VERSION 5.8 ;
BUSBITCHARS "[]" ;
DIVIDERCHAR "/" ;
UNITS
    DATABASE MICRONS 1000 ;
END UNITS

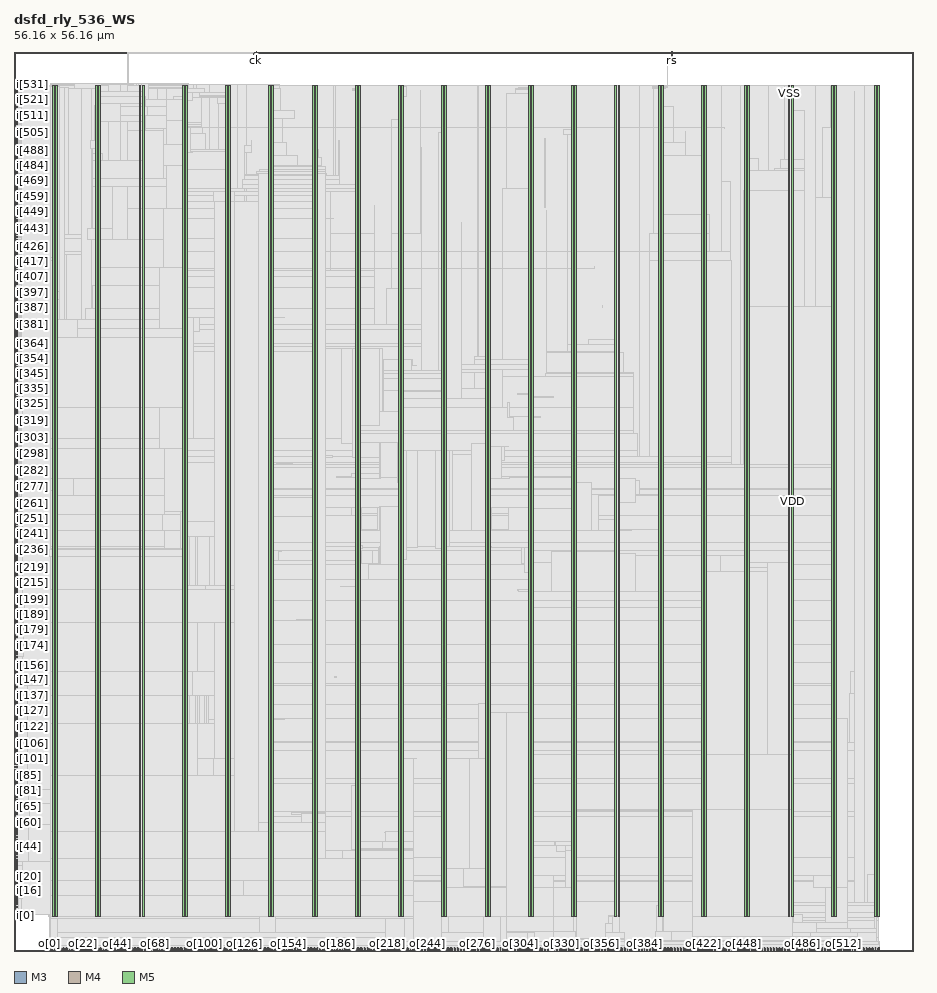
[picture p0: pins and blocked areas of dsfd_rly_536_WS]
MACRO dsfd_rly_536_WS
  FOREIGN dsfd_rly_536_WS 0 0 ;
  CLASS BLOCK ;
  SIZE 56.16 BY 56.16 ;
  PIN ck
    DIRECTION INPUT ;
    USE SIGNAL ;
    PORT
      LAYER M3 ;
        RECT  15.12 56.016 15.138 56.16 ;
    END
    PORT
      LAYER M3 ;
        RECT  14.94 55.915 15.138 56.028 ;
    END
  END ck
  PIN i[0]
    DIRECTION INPUT ;
    USE SIGNAL ;
    PORT
      LAYER M4 ;
        RECT  0 2.208 0.192 2.232 ;
    END
  END i[0]
  PIN i[100]
    DIRECTION INPUT ;
    USE SIGNAL ;
    PORT
      LAYER M4 ;
        RECT  0 11.904 0.192 11.928 ;
    END
  END i[100]
  PIN i[101]
    DIRECTION INPUT ;
    USE SIGNAL ;
    PORT
      LAYER M4 ;
        RECT  0 12 0.192 12.024 ;
    END
  END i[101]
  PIN i[102]
    DIRECTION INPUT ;
    USE SIGNAL ;
    PORT
      LAYER M4 ;
        RECT  0 12.096 0.192 12.12 ;
    END
  END i[102]
  PIN i[103]
    DIRECTION INPUT ;
    USE SIGNAL ;
    PORT
      LAYER M4 ;
        RECT  0 12.192 0.192 12.216 ;
    END
  END i[103]
  PIN i[104]
    DIRECTION INPUT ;
    USE SIGNAL ;
    PORT
      LAYER M4 ;
        RECT  0 12.288 0.192 12.312 ;
    END
  END i[104]
  PIN i[105]
    DIRECTION INPUT ;
    USE SIGNAL ;
    PORT
      LAYER M4 ;
        RECT  0 12.384 0.192 12.408 ;
    END
  END i[105]
  PIN i[106]
    DIRECTION INPUT ;
    USE SIGNAL ;
    PORT
      LAYER M4 ;
        RECT  0 12.48 0.192 12.504 ;
    END
  END i[106]
  PIN i[107]
    DIRECTION INPUT ;
    USE SIGNAL ;
    PORT
      LAYER M4 ;
        RECT  0 12.576 0.192 12.6 ;
    END
  END i[107]
  PIN i[108]
    DIRECTION INPUT ;
    USE SIGNAL ;
    PORT
      LAYER M4 ;
        RECT  0 12.672 0.192 12.696 ;
    END
  END i[108]
  PIN i[109]
    DIRECTION INPUT ;
    USE SIGNAL ;
    PORT
      LAYER M4 ;
        RECT  0 12.768 0.192 12.792 ;
    END
  END i[109]
  PIN i[10]
    DIRECTION INPUT ;
    USE SIGNAL ;
    PORT
      LAYER M4 ;
        RECT  0 3.168 0.192 3.192 ;
    END
  END i[10]
  PIN i[110]
    DIRECTION INPUT ;
    USE SIGNAL ;
    PORT
      LAYER M4 ;
        RECT  0 12.864 0.192 12.888 ;
    END
  END i[110]
  PIN i[111]
    DIRECTION INPUT ;
    USE SIGNAL ;
    PORT
      LAYER M4 ;
        RECT  0 12.96 0.192 12.984 ;
    END
  END i[111]
  PIN i[112]
    DIRECTION INPUT ;
    USE SIGNAL ;
    PORT
      LAYER M4 ;
        RECT  0 13.056 0.192 13.08 ;
    END
  END i[112]
  PIN i[113]
    DIRECTION INPUT ;
    USE SIGNAL ;
    PORT
      LAYER M4 ;
        RECT  0 13.152 0.192 13.176 ;
    END
  END i[113]
  PIN i[114]
    DIRECTION INPUT ;
    USE SIGNAL ;
    PORT
      LAYER M4 ;
        RECT  0 13.248 0.192 13.272 ;
    END
  END i[114]
  PIN i[115]
    DIRECTION INPUT ;
    USE SIGNAL ;
    PORT
      LAYER M4 ;
        RECT  0 13.344 0.192 13.368 ;
    END
  END i[115]
  PIN i[116]
    DIRECTION INPUT ;
    USE SIGNAL ;
    PORT
      LAYER M4 ;
        RECT  0 13.44 0.192 13.464 ;
    END
  END i[116]
  PIN i[117]
    DIRECTION INPUT ;
    USE SIGNAL ;
    PORT
      LAYER M4 ;
        RECT  0 13.536 0.192 13.56 ;
    END
  END i[117]
  PIN i[118]
    DIRECTION INPUT ;
    USE SIGNAL ;
    PORT
      LAYER M4 ;
        RECT  0 13.632 0.192 13.656 ;
    END
  END i[118]
  PIN i[119]
    DIRECTION INPUT ;
    USE SIGNAL ;
    PORT
      LAYER M4 ;
        RECT  0 13.728 0.192 13.752 ;
    END
  END i[119]
  PIN i[11]
    DIRECTION INPUT ;
    USE SIGNAL ;
    PORT
      LAYER M4 ;
        RECT  0 3.264 0.192 3.288 ;
    END
  END i[11]
  PIN i[120]
    DIRECTION INPUT ;
    USE SIGNAL ;
    PORT
      LAYER M4 ;
        RECT  0 13.824 0.192 13.848 ;
    END
  END i[120]
  PIN i[121]
    DIRECTION INPUT ;
    USE SIGNAL ;
    PORT
      LAYER M4 ;
        RECT  0 13.92 0.192 13.944 ;
    END
  END i[121]
  PIN i[122]
    DIRECTION INPUT ;
    USE SIGNAL ;
    PORT
      LAYER M4 ;
        RECT  0 14.016 0.192 14.04 ;
    END
  END i[122]
  PIN i[123]
    DIRECTION INPUT ;
    USE SIGNAL ;
    PORT
      LAYER M4 ;
        RECT  0 14.112 0.192 14.136 ;
    END
  END i[123]
  PIN i[124]
    DIRECTION INPUT ;
    USE SIGNAL ;
    PORT
      LAYER M4 ;
        RECT  0 14.208 0.192 14.232 ;
    END
  END i[124]
  PIN i[125]
    DIRECTION INPUT ;
    USE SIGNAL ;
    PORT
      LAYER M4 ;
        RECT  0 14.304 0.192 14.328 ;
    END
  END i[125]
  PIN i[126]
    DIRECTION INPUT ;
    USE SIGNAL ;
    PORT
      LAYER M4 ;
        RECT  0 14.4 0.192 14.424 ;
    END
  END i[126]
  PIN i[127]
    DIRECTION INPUT ;
    USE SIGNAL ;
    PORT
      LAYER M4 ;
        RECT  0 14.496 0.192 14.52 ;
    END
  END i[127]
  PIN i[128]
    DIRECTION INPUT ;
    USE SIGNAL ;
    PORT
      LAYER M4 ;
        RECT  0 14.592 0.192 14.616 ;
    END
  END i[128]
  PIN i[129]
    DIRECTION INPUT ;
    USE SIGNAL ;
    PORT
      LAYER M4 ;
        RECT  0 14.688 0.192 14.712 ;
    END
  END i[129]
  PIN i[12]
    DIRECTION INPUT ;
    USE SIGNAL ;
    PORT
      LAYER M4 ;
        RECT  0 3.36 0.192 3.384 ;
    END
  END i[12]
  PIN i[130]
    DIRECTION INPUT ;
    USE SIGNAL ;
    PORT
      LAYER M4 ;
        RECT  0 14.784 0.192 14.808 ;
    END
  END i[130]
  PIN i[131]
    DIRECTION INPUT ;
    USE SIGNAL ;
    PORT
      LAYER M4 ;
        RECT  0 14.88 0.192 14.904 ;
    END
  END i[131]
  PIN i[132]
    DIRECTION INPUT ;
    USE SIGNAL ;
    PORT
      LAYER M4 ;
        RECT  0 14.976 0.192 15 ;
    END
  END i[132]
  PIN i[133]
    DIRECTION INPUT ;
    USE SIGNAL ;
    PORT
      LAYER M4 ;
        RECT  0 15.072 0.192 15.096 ;
    END
  END i[133]
  PIN i[134]
    DIRECTION INPUT ;
    USE SIGNAL ;
    PORT
      LAYER M4 ;
        RECT  0 15.168 0.192 15.192 ;
    END
  END i[134]
  PIN i[135]
    DIRECTION INPUT ;
    USE SIGNAL ;
    PORT
      LAYER M4 ;
        RECT  0 15.264 0.192 15.288 ;
    END
  END i[135]
  PIN i[136]
    DIRECTION INPUT ;
    USE SIGNAL ;
    PORT
      LAYER M4 ;
        RECT  0 15.36 0.192 15.384 ;
    END
  END i[136]
  PIN i[137]
    DIRECTION INPUT ;
    USE SIGNAL ;
    PORT
      LAYER M4 ;
        RECT  0 15.456 0.192 15.48 ;
    END
  END i[137]
  PIN i[138]
    DIRECTION INPUT ;
    USE SIGNAL ;
    PORT
      LAYER M4 ;
        RECT  0 15.552 0.192 15.576 ;
    END
  END i[138]
  PIN i[139]
    DIRECTION INPUT ;
    USE SIGNAL ;
    PORT
      LAYER M4 ;
        RECT  0 15.648 0.192 15.672 ;
    END
  END i[139]
  PIN i[13]
    DIRECTION INPUT ;
    USE SIGNAL ;
    PORT
      LAYER M4 ;
        RECT  0 3.456 0.192 3.48 ;
    END
  END i[13]
  PIN i[140]
    DIRECTION INPUT ;
    USE SIGNAL ;
    PORT
      LAYER M4 ;
        RECT  0 15.744 0.192 15.768 ;
    END
  END i[140]
  PIN i[141]
    DIRECTION INPUT ;
    USE SIGNAL ;
    PORT
      LAYER M4 ;
        RECT  0 15.84 0.192 15.864 ;
    END
  END i[141]
  PIN i[142]
    DIRECTION INPUT ;
    USE SIGNAL ;
    PORT
      LAYER M4 ;
        RECT  0 15.936 0.192 15.96 ;
    END
  END i[142]
  PIN i[143]
    DIRECTION INPUT ;
    USE SIGNAL ;
    PORT
      LAYER M4 ;
        RECT  0 16.032 0.192 16.056 ;
    END
  END i[143]
  PIN i[144]
    DIRECTION INPUT ;
    USE SIGNAL ;
    PORT
      LAYER M4 ;
        RECT  0 16.128 0.192 16.152 ;
    END
  END i[144]
  PIN i[145]
    DIRECTION INPUT ;
    USE SIGNAL ;
    PORT
      LAYER M4 ;
        RECT  0 16.224 0.192 16.248 ;
    END
  END i[145]
  PIN i[146]
    DIRECTION INPUT ;
    USE SIGNAL ;
    PORT
      LAYER M4 ;
        RECT  0 16.32 0.192 16.344 ;
    END
  END i[146]
  PIN i[147]
    DIRECTION INPUT ;
    USE SIGNAL ;
    PORT
      LAYER M4 ;
        RECT  0 16.416 0.192 16.44 ;
    END
  END i[147]
  PIN i[148]
    DIRECTION INPUT ;
    USE SIGNAL ;
    PORT
      LAYER M4 ;
        RECT  0 16.512 0.192 16.536 ;
    END
  END i[148]
  PIN i[149]
    DIRECTION INPUT ;
    USE SIGNAL ;
    PORT
      LAYER M4 ;
        RECT  0 16.608 0.192 16.632 ;
    END
  END i[149]
  PIN i[14]
    DIRECTION INPUT ;
    USE SIGNAL ;
    PORT
      LAYER M4 ;
        RECT  0 3.552 0.192 3.576 ;
    END
  END i[14]
  PIN i[150]
    DIRECTION INPUT ;
    USE SIGNAL ;
    PORT
      LAYER M4 ;
        RECT  0 16.704 0.192 16.728 ;
    END
  END i[150]
  PIN i[151]
    DIRECTION INPUT ;
    USE SIGNAL ;
    PORT
      LAYER M4 ;
        RECT  0 16.848 0.192 16.872 ;
    END
  END i[151]
  PIN i[152]
    DIRECTION INPUT ;
    USE SIGNAL ;
    PORT
      LAYER M4 ;
        RECT  0 16.944 0.192 16.968 ;
    END
  END i[152]
  PIN i[153]
    DIRECTION INPUT ;
    USE SIGNAL ;
    PORT
      LAYER M4 ;
        RECT  0 17.04 0.192 17.064 ;
    END
  END i[153]
  PIN i[154]
    DIRECTION INPUT ;
    USE SIGNAL ;
    PORT
      LAYER M4 ;
        RECT  0 17.136 0.192 17.16 ;
    END
  END i[154]
  PIN i[155]
    DIRECTION INPUT ;
    USE SIGNAL ;
    PORT
      LAYER M4 ;
        RECT  0 17.232 0.192 17.256 ;
    END
  END i[155]
  PIN i[156]
    DIRECTION INPUT ;
    USE SIGNAL ;
    PORT
      LAYER M4 ;
        RECT  0 17.328 0.192 17.352 ;
    END
  END i[156]
  PIN i[157]
    DIRECTION INPUT ;
    USE SIGNAL ;
    PORT
      LAYER M4 ;
        RECT  0 17.424 0.192 17.448 ;
    END
  END i[157]
  PIN i[158]
    DIRECTION INPUT ;
    USE SIGNAL ;
    PORT
      LAYER M4 ;
        RECT  0 17.52 0.192 17.544 ;
    END
  END i[158]
  PIN i[159]
    DIRECTION INPUT ;
    USE SIGNAL ;
    PORT
      LAYER M4 ;
        RECT  0 17.616 0.192 17.64 ;
    END
  END i[159]
  PIN i[15]
    DIRECTION INPUT ;
    USE SIGNAL ;
    PORT
      LAYER M4 ;
        RECT  0 3.648 0.192 3.672 ;
    END
  END i[15]
  PIN i[160]
    DIRECTION INPUT ;
    USE SIGNAL ;
    PORT
      LAYER M4 ;
        RECT  0 17.712 0.192 17.736 ;
    END
  END i[160]
  PIN i[161]
    DIRECTION INPUT ;
    USE SIGNAL ;
    PORT
      LAYER M4 ;
        RECT  0 17.808 0.192 17.832 ;
    END
  END i[161]
  PIN i[162]
    DIRECTION INPUT ;
    USE SIGNAL ;
    PORT
      LAYER M4 ;
        RECT  0 17.904 0.192 17.928 ;
    END
  END i[162]
  PIN i[163]
    DIRECTION INPUT ;
    USE SIGNAL ;
    PORT
      LAYER M4 ;
        RECT  0 18 0.192 18.024 ;
    END
  END i[163]
  PIN i[164]
    DIRECTION INPUT ;
    USE SIGNAL ;
    PORT
      LAYER M4 ;
        RECT  0 18.096 0.192 18.12 ;
    END
  END i[164]
  PIN i[165]
    DIRECTION INPUT ;
    USE SIGNAL ;
    PORT
      LAYER M4 ;
        RECT  0 18.192 0.192 18.216 ;
    END
  END i[165]
  PIN i[166]
    DIRECTION INPUT ;
    USE SIGNAL ;
    PORT
      LAYER M4 ;
        RECT  0 18.288 0.192 18.312 ;
    END
  END i[166]
  PIN i[167]
    DIRECTION INPUT ;
    USE SIGNAL ;
    PORT
      LAYER M4 ;
        RECT  0 18.384 0.192 18.408 ;
    END
  END i[167]
  PIN i[168]
    DIRECTION INPUT ;
    USE SIGNAL ;
    PORT
      LAYER M4 ;
        RECT  0 18.48 0.192 18.504 ;
    END
  END i[168]
  PIN i[169]
    DIRECTION INPUT ;
    USE SIGNAL ;
    PORT
      LAYER M4 ;
        RECT  0 18.576 0.192 18.6 ;
    END
  END i[169]
  PIN i[16]
    DIRECTION INPUT ;
    USE SIGNAL ;
    PORT
      LAYER M4 ;
        RECT  0 3.744 0.192 3.768 ;
    END
  END i[16]
  PIN i[170]
    DIRECTION INPUT ;
    USE SIGNAL ;
    PORT
      LAYER M4 ;
        RECT  0 18.672 0.192 18.696 ;
    END
  END i[170]
  PIN i[171]
    DIRECTION INPUT ;
    USE SIGNAL ;
    PORT
      LAYER M4 ;
        RECT  0 18.768 0.192 18.792 ;
    END
  END i[171]
  PIN i[172]
    DIRECTION INPUT ;
    USE SIGNAL ;
    PORT
      LAYER M4 ;
        RECT  0 18.864 0.192 18.888 ;
    END
  END i[172]
  PIN i[173]
    DIRECTION INPUT ;
    USE SIGNAL ;
    PORT
      LAYER M4 ;
        RECT  0 18.96 0.192 18.984 ;
    END
  END i[173]
  PIN i[174]
    DIRECTION INPUT ;
    USE SIGNAL ;
    PORT
      LAYER M4 ;
        RECT  0 19.056 0.192 19.08 ;
    END
  END i[174]
  PIN i[175]
    DIRECTION INPUT ;
    USE SIGNAL ;
    PORT
      LAYER M4 ;
        RECT  0 19.152 0.192 19.176 ;
    END
  END i[175]
  PIN i[176]
    DIRECTION INPUT ;
    USE SIGNAL ;
    PORT
      LAYER M4 ;
        RECT  0 19.248 0.192 19.272 ;
    END
  END i[176]
  PIN i[177]
    DIRECTION INPUT ;
    USE SIGNAL ;
    PORT
      LAYER M4 ;
        RECT  0 19.344 0.192 19.368 ;
    END
  END i[177]
  PIN i[178]
    DIRECTION INPUT ;
    USE SIGNAL ;
    PORT
      LAYER M4 ;
        RECT  0 19.44 0.192 19.464 ;
    END
  END i[178]
  PIN i[179]
    DIRECTION INPUT ;
    USE SIGNAL ;
    PORT
      LAYER M4 ;
        RECT  0 19.536 0.192 19.56 ;
    END
  END i[179]
  PIN i[17]
    DIRECTION INPUT ;
    USE SIGNAL ;
    PORT
      LAYER M4 ;
        RECT  0 3.888 0.192 3.912 ;
    END
  END i[17]
  PIN i[180]
    DIRECTION INPUT ;
    USE SIGNAL ;
    PORT
      LAYER M4 ;
        RECT  0 19.632 0.192 19.656 ;
    END
  END i[180]
  PIN i[181]
    DIRECTION INPUT ;
    USE SIGNAL ;
    PORT
      LAYER M4 ;
        RECT  0 19.728 0.192 19.752 ;
    END
  END i[181]
  PIN i[182]
    DIRECTION INPUT ;
    USE SIGNAL ;
    PORT
      LAYER M4 ;
        RECT  0 19.824 0.192 19.848 ;
    END
  END i[182]
  PIN i[183]
    DIRECTION INPUT ;
    USE SIGNAL ;
    PORT
      LAYER M4 ;
        RECT  0 19.92 0.192 19.944 ;
    END
  END i[183]
  PIN i[184]
    DIRECTION INPUT ;
    USE SIGNAL ;
    PORT
      LAYER M4 ;
        RECT  0 20.016 0.192 20.04 ;
    END
  END i[184]
  PIN i[185]
    DIRECTION INPUT ;
    USE SIGNAL ;
    PORT
      LAYER M4 ;
        RECT  0 20.112 0.192 20.136 ;
    END
  END i[185]
  PIN i[186]
    DIRECTION INPUT ;
    USE SIGNAL ;
    PORT
      LAYER M4 ;
        RECT  0 20.208 0.192 20.232 ;
    END
  END i[186]
  PIN i[187]
    DIRECTION INPUT ;
    USE SIGNAL ;
    PORT
      LAYER M4 ;
        RECT  0 20.304 0.192 20.328 ;
    END
  END i[187]
  PIN i[188]
    DIRECTION INPUT ;
    USE SIGNAL ;
    PORT
      LAYER M4 ;
        RECT  0 20.4 0.192 20.424 ;
    END
  END i[188]
  PIN i[189]
    DIRECTION INPUT ;
    USE SIGNAL ;
    PORT
      LAYER M4 ;
        RECT  0 20.496 0.192 20.52 ;
    END
  END i[189]
  PIN i[18]
    DIRECTION INPUT ;
    USE SIGNAL ;
    PORT
      LAYER M4 ;
        RECT  0 3.984 0.192 4.008 ;
    END
  END i[18]
  PIN i[190]
    DIRECTION INPUT ;
    USE SIGNAL ;
    PORT
      LAYER M4 ;
        RECT  0 20.592 0.192 20.616 ;
    END
  END i[190]
  PIN i[191]
    DIRECTION INPUT ;
    USE SIGNAL ;
    PORT
      LAYER M4 ;
        RECT  0 20.688 0.192 20.712 ;
    END
  END i[191]
  PIN i[192]
    DIRECTION INPUT ;
    USE SIGNAL ;
    PORT
      LAYER M4 ;
        RECT  0 20.784 0.192 20.808 ;
    END
  END i[192]
  PIN i[193]
    DIRECTION INPUT ;
    USE SIGNAL ;
    PORT
      LAYER M4 ;
        RECT  0 20.88 0.192 20.904 ;
    END
  END i[193]
  PIN i[194]
    DIRECTION INPUT ;
    USE SIGNAL ;
    PORT
      LAYER M4 ;
        RECT  0 20.976 0.192 21 ;
    END
  END i[194]
  PIN i[195]
    DIRECTION INPUT ;
    USE SIGNAL ;
    PORT
      LAYER M4 ;
        RECT  0 21.072 0.192 21.096 ;
    END
  END i[195]
  PIN i[196]
    DIRECTION INPUT ;
    USE SIGNAL ;
    PORT
      LAYER M4 ;
        RECT  0 21.168 0.192 21.192 ;
    END
  END i[196]
  PIN i[197]
    DIRECTION INPUT ;
    USE SIGNAL ;
    PORT
      LAYER M4 ;
        RECT  0 21.264 0.192 21.288 ;
    END
  END i[197]
  PIN i[198]
    DIRECTION INPUT ;
    USE SIGNAL ;
    PORT
      LAYER M4 ;
        RECT  0 21.36 0.192 21.384 ;
    END
  END i[198]
  PIN i[199]
    DIRECTION INPUT ;
    USE SIGNAL ;
    PORT
      LAYER M4 ;
        RECT  0 21.456 0.192 21.48 ;
    END
  END i[199]
  PIN i[19]
    DIRECTION INPUT ;
    USE SIGNAL ;
    PORT
      LAYER M4 ;
        RECT  0 4.08 0.192 4.104 ;
    END
  END i[19]
  PIN i[1]
    DIRECTION INPUT ;
    USE SIGNAL ;
    PORT
      LAYER M4 ;
        RECT  0 2.304 0.192 2.328 ;
    END
  END i[1]
  PIN i[200]
    DIRECTION INPUT ;
    USE SIGNAL ;
    PORT
      LAYER M4 ;
        RECT  0 21.552 0.192 21.576 ;
    END
  END i[200]
  PIN i[201]
    DIRECTION INPUT ;
    USE SIGNAL ;
    PORT
      LAYER M4 ;
        RECT  0 21.648 0.192 21.672 ;
    END
  END i[201]
  PIN i[202]
    DIRECTION INPUT ;
    USE SIGNAL ;
    PORT
      LAYER M4 ;
        RECT  0 21.744 0.192 21.768 ;
    END
  END i[202]
  PIN i[203]
    DIRECTION INPUT ;
    USE SIGNAL ;
    PORT
      LAYER M4 ;
        RECT  0 21.84 0.192 21.864 ;
    END
  END i[203]
  PIN i[204]
    DIRECTION INPUT ;
    USE SIGNAL ;
    PORT
      LAYER M4 ;
        RECT  0 21.936 0.192 21.96 ;
    END
  END i[204]
  PIN i[205]
    DIRECTION INPUT ;
    USE SIGNAL ;
    PORT
      LAYER M4 ;
        RECT  0 22.032 0.192 22.056 ;
    END
  END i[205]
  PIN i[206]
    DIRECTION INPUT ;
    USE SIGNAL ;
    PORT
      LAYER M4 ;
        RECT  0 22.128 0.192 22.152 ;
    END
  END i[206]
  PIN i[207]
    DIRECTION INPUT ;
    USE SIGNAL ;
    PORT
      LAYER M4 ;
        RECT  0 22.224 0.192 22.248 ;
    END
  END i[207]
  PIN i[208]
    DIRECTION INPUT ;
    USE SIGNAL ;
    PORT
      LAYER M4 ;
        RECT  0 22.32 0.192 22.344 ;
    END
  END i[208]
  PIN i[209]
    DIRECTION INPUT ;
    USE SIGNAL ;
    PORT
      LAYER M4 ;
        RECT  0 22.416 0.192 22.44 ;
    END
  END i[209]
  PIN i[20]
    DIRECTION INPUT ;
    USE SIGNAL ;
    PORT
      LAYER M4 ;
        RECT  0 4.176 0.192 4.2 ;
    END
  END i[20]
  PIN i[210]
    DIRECTION INPUT ;
    USE SIGNAL ;
    PORT
      LAYER M4 ;
        RECT  0 22.512 0.192 22.536 ;
    END
  END i[210]
  PIN i[211]
    DIRECTION INPUT ;
    USE SIGNAL ;
    PORT
      LAYER M4 ;
        RECT  0 22.608 0.192 22.632 ;
    END
  END i[211]
  PIN i[212]
    DIRECTION INPUT ;
    USE SIGNAL ;
    PORT
      LAYER M4 ;
        RECT  0 22.704 0.192 22.728 ;
    END
  END i[212]
  PIN i[213]
    DIRECTION INPUT ;
    USE SIGNAL ;
    PORT
      LAYER M4 ;
        RECT  0 22.8 0.192 22.824 ;
    END
  END i[213]
  PIN i[214]
    DIRECTION INPUT ;
    USE SIGNAL ;
    PORT
      LAYER M4 ;
        RECT  0 22.896 0.192 22.92 ;
    END
  END i[214]
  PIN i[215]
    DIRECTION INPUT ;
    USE SIGNAL ;
    PORT
      LAYER M4 ;
        RECT  0 22.992 0.192 23.016 ;
    END
  END i[215]
  PIN i[216]
    DIRECTION INPUT ;
    USE SIGNAL ;
    PORT
      LAYER M4 ;
        RECT  0 23.088 0.192 23.112 ;
    END
  END i[216]
  PIN i[217]
    DIRECTION INPUT ;
    USE SIGNAL ;
    PORT
      LAYER M4 ;
        RECT  0 23.184 0.192 23.208 ;
    END
  END i[217]
  PIN i[218]
    DIRECTION INPUT ;
    USE SIGNAL ;
    PORT
      LAYER M4 ;
        RECT  0 23.328 0.192 23.352 ;
    END
  END i[218]
  PIN i[219]
    DIRECTION INPUT ;
    USE SIGNAL ;
    PORT
      LAYER M4 ;
        RECT  0 23.424 0.192 23.448 ;
    END
  END i[219]
  PIN i[21]
    DIRECTION INPUT ;
    USE SIGNAL ;
    PORT
      LAYER M4 ;
        RECT  0 4.272 0.192 4.296 ;
    END
  END i[21]
  PIN i[220]
    DIRECTION INPUT ;
    USE SIGNAL ;
    PORT
      LAYER M4 ;
        RECT  0 23.52 0.192 23.544 ;
    END
  END i[220]
  PIN i[221]
    DIRECTION INPUT ;
    USE SIGNAL ;
    PORT
      LAYER M4 ;
        RECT  0 23.616 0.192 23.64 ;
    END
  END i[221]
  PIN i[222]
    DIRECTION INPUT ;
    USE SIGNAL ;
    PORT
      LAYER M4 ;
        RECT  0 23.712 0.192 23.736 ;
    END
  END i[222]
  PIN i[223]
    DIRECTION INPUT ;
    USE SIGNAL ;
    PORT
      LAYER M4 ;
        RECT  0 23.808 0.192 23.832 ;
    END
  END i[223]
  PIN i[224]
    DIRECTION INPUT ;
    USE SIGNAL ;
    PORT
      LAYER M4 ;
        RECT  0 23.904 0.192 23.928 ;
    END
  END i[224]
  PIN i[225]
    DIRECTION INPUT ;
    USE SIGNAL ;
    PORT
      LAYER M4 ;
        RECT  0 24 0.192 24.024 ;
    END
  END i[225]
  PIN i[226]
    DIRECTION INPUT ;
    USE SIGNAL ;
    PORT
      LAYER M4 ;
        RECT  0 24.096 0.192 24.12 ;
    END
  END i[226]
  PIN i[227]
    DIRECTION INPUT ;
    USE SIGNAL ;
    PORT
      LAYER M4 ;
        RECT  0 24.192 0.192 24.216 ;
    END
  END i[227]
  PIN i[228]
    DIRECTION INPUT ;
    USE SIGNAL ;
    PORT
      LAYER M4 ;
        RECT  0 24.288 0.192 24.312 ;
    END
  END i[228]
  PIN i[229]
    DIRECTION INPUT ;
    USE SIGNAL ;
    PORT
      LAYER M4 ;
        RECT  0 24.384 0.192 24.408 ;
    END
  END i[229]
  PIN i[22]
    DIRECTION INPUT ;
    USE SIGNAL ;
    PORT
      LAYER M4 ;
        RECT  0 4.368 0.192 4.392 ;
    END
  END i[22]
  PIN i[230]
    DIRECTION INPUT ;
    USE SIGNAL ;
    PORT
      LAYER M4 ;
        RECT  0 24.48 0.192 24.504 ;
    END
  END i[230]
  PIN i[231]
    DIRECTION INPUT ;
    USE SIGNAL ;
    PORT
      LAYER M4 ;
        RECT  0 24.576 0.192 24.6 ;
    END
  END i[231]
  PIN i[232]
    DIRECTION INPUT ;
    USE SIGNAL ;
    PORT
      LAYER M4 ;
        RECT  0 24.672 0.192 24.696 ;
    END
  END i[232]
  PIN i[233]
    DIRECTION INPUT ;
    USE SIGNAL ;
    PORT
      LAYER M4 ;
        RECT  0 24.768 0.192 24.792 ;
    END
  END i[233]
  PIN i[234]
    DIRECTION INPUT ;
    USE SIGNAL ;
    PORT
      LAYER M4 ;
        RECT  0 24.864 0.192 24.888 ;
    END
  END i[234]
  PIN i[235]
    DIRECTION INPUT ;
    USE SIGNAL ;
    PORT
      LAYER M4 ;
        RECT  0 24.96 0.192 24.984 ;
    END
  END i[235]
  PIN i[236]
    DIRECTION INPUT ;
    USE SIGNAL ;
    PORT
      LAYER M4 ;
        RECT  0 25.056 0.192 25.08 ;
    END
  END i[236]
  PIN i[237]
    DIRECTION INPUT ;
    USE SIGNAL ;
    PORT
      LAYER M4 ;
        RECT  0 25.152 0.192 25.176 ;
    END
  END i[237]
  PIN i[238]
    DIRECTION INPUT ;
    USE SIGNAL ;
    PORT
      LAYER M4 ;
        RECT  0 25.248 0.192 25.272 ;
    END
  END i[238]
  PIN i[239]
    DIRECTION INPUT ;
    USE SIGNAL ;
    PORT
      LAYER M4 ;
        RECT  0 25.344 0.192 25.368 ;
    END
  END i[239]
  PIN i[23]
    DIRECTION INPUT ;
    USE SIGNAL ;
    PORT
      LAYER M4 ;
        RECT  0 4.464 0.192 4.488 ;
    END
  END i[23]
  PIN i[240]
    DIRECTION INPUT ;
    USE SIGNAL ;
    PORT
      LAYER M4 ;
        RECT  0 25.44 0.192 25.464 ;
    END
  END i[240]
  PIN i[241]
    DIRECTION INPUT ;
    USE SIGNAL ;
    PORT
      LAYER M4 ;
        RECT  0 25.536 0.192 25.56 ;
    END
  END i[241]
  PIN i[242]
    DIRECTION INPUT ;
    USE SIGNAL ;
    PORT
      LAYER M4 ;
        RECT  0 25.632 0.192 25.656 ;
    END
  END i[242]
  PIN i[243]
    DIRECTION INPUT ;
    USE SIGNAL ;
    PORT
      LAYER M4 ;
        RECT  0 25.728 0.192 25.752 ;
    END
  END i[243]
  PIN i[244]
    DIRECTION INPUT ;
    USE SIGNAL ;
    PORT
      LAYER M4 ;
        RECT  0 25.824 0.192 25.848 ;
    END
  END i[244]
  PIN i[245]
    DIRECTION INPUT ;
    USE SIGNAL ;
    PORT
      LAYER M4 ;
        RECT  0 25.92 0.192 25.944 ;
    END
  END i[245]
  PIN i[246]
    DIRECTION INPUT ;
    USE SIGNAL ;
    PORT
      LAYER M4 ;
        RECT  0 26.016 0.192 26.04 ;
    END
  END i[246]
  PIN i[247]
    DIRECTION INPUT ;
    USE SIGNAL ;
    PORT
      LAYER M4 ;
        RECT  0 26.112 0.192 26.136 ;
    END
  END i[247]
  PIN i[248]
    DIRECTION INPUT ;
    USE SIGNAL ;
    PORT
      LAYER M4 ;
        RECT  0 26.208 0.192 26.232 ;
    END
  END i[248]
  PIN i[249]
    DIRECTION INPUT ;
    USE SIGNAL ;
    PORT
      LAYER M4 ;
        RECT  0 26.304 0.192 26.328 ;
    END
  END i[249]
  PIN i[24]
    DIRECTION INPUT ;
    USE SIGNAL ;
    PORT
      LAYER M4 ;
        RECT  0 4.56 0.192 4.584 ;
    END
  END i[24]
  PIN i[250]
    DIRECTION INPUT ;
    USE SIGNAL ;
    PORT
      LAYER M4 ;
        RECT  0 26.4 0.192 26.424 ;
    END
  END i[250]
  PIN i[251]
    DIRECTION INPUT ;
    USE SIGNAL ;
    PORT
      LAYER M4 ;
        RECT  0 26.496 0.192 26.52 ;
    END
  END i[251]
  PIN i[252]
    DIRECTION INPUT ;
    USE SIGNAL ;
    PORT
      LAYER M4 ;
        RECT  0 26.592 0.192 26.616 ;
    END
  END i[252]
  PIN i[253]
    DIRECTION INPUT ;
    USE SIGNAL ;
    PORT
      LAYER M4 ;
        RECT  0 26.688 0.192 26.712 ;
    END
  END i[253]
  PIN i[254]
    DIRECTION INPUT ;
    USE SIGNAL ;
    PORT
      LAYER M4 ;
        RECT  0 26.784 0.192 26.808 ;
    END
  END i[254]
  PIN i[255]
    DIRECTION INPUT ;
    USE SIGNAL ;
    PORT
      LAYER M4 ;
        RECT  0 26.88 0.192 26.904 ;
    END
  END i[255]
  PIN i[256]
    DIRECTION INPUT ;
    USE SIGNAL ;
    PORT
      LAYER M4 ;
        RECT  0 26.976 0.192 27 ;
    END
  END i[256]
  PIN i[257]
    DIRECTION INPUT ;
    USE SIGNAL ;
    PORT
      LAYER M4 ;
        RECT  0 27.072 0.192 27.096 ;
    END
  END i[257]
  PIN i[258]
    DIRECTION INPUT ;
    USE SIGNAL ;
    PORT
      LAYER M4 ;
        RECT  0 27.168 0.192 27.192 ;
    END
  END i[258]
  PIN i[259]
    DIRECTION INPUT ;
    USE SIGNAL ;
    PORT
      LAYER M4 ;
        RECT  0 27.264 0.192 27.288 ;
    END
  END i[259]
  PIN i[25]
    DIRECTION INPUT ;
    USE SIGNAL ;
    PORT
      LAYER M4 ;
        RECT  0 4.656 0.192 4.68 ;
    END
  END i[25]
  PIN i[260]
    DIRECTION INPUT ;
    USE SIGNAL ;
    PORT
      LAYER M4 ;
        RECT  0 27.36 0.192 27.384 ;
    END
  END i[260]
  PIN i[261]
    DIRECTION INPUT ;
    USE SIGNAL ;
    PORT
      LAYER M4 ;
        RECT  0 27.456 0.192 27.48 ;
    END
  END i[261]
  PIN i[262]
    DIRECTION INPUT ;
    USE SIGNAL ;
    PORT
      LAYER M4 ;
        RECT  0 27.552 0.192 27.576 ;
    END
  END i[262]
  PIN i[263]
    DIRECTION INPUT ;
    USE SIGNAL ;
    PORT
      LAYER M4 ;
        RECT  0 27.648 0.192 27.672 ;
    END
  END i[263]
  PIN i[264]
    DIRECTION INPUT ;
    USE SIGNAL ;
    PORT
      LAYER M4 ;
        RECT  0 27.744 0.192 27.768 ;
    END
  END i[264]
  PIN i[265]
    DIRECTION INPUT ;
    USE SIGNAL ;
    PORT
      LAYER M4 ;
        RECT  0 27.84 0.192 27.864 ;
    END
  END i[265]
  PIN i[266]
    DIRECTION INPUT ;
    USE SIGNAL ;
    PORT
      LAYER M4 ;
        RECT  0 27.936 0.192 27.96 ;
    END
  END i[266]
  PIN i[267]
    DIRECTION INPUT ;
    USE SIGNAL ;
    PORT
      LAYER M4 ;
        RECT  0 28.032 0.192 28.056 ;
    END
  END i[267]
  PIN i[268]
    DIRECTION INPUT ;
    USE SIGNAL ;
    PORT
      LAYER M4 ;
        RECT  0 28.128 0.192 28.152 ;
    END
  END i[268]
  PIN i[269]
    DIRECTION INPUT ;
    USE SIGNAL ;
    PORT
      LAYER M4 ;
        RECT  0 28.224 0.192 28.248 ;
    END
  END i[269]
  PIN i[26]
    DIRECTION INPUT ;
    USE SIGNAL ;
    PORT
      LAYER M4 ;
        RECT  0 4.752 0.192 4.776 ;
    END
  END i[26]
  PIN i[270]
    DIRECTION INPUT ;
    USE SIGNAL ;
    PORT
      LAYER M4 ;
        RECT  0 28.32 0.192 28.344 ;
    END
  END i[270]
  PIN i[271]
    DIRECTION INPUT ;
    USE SIGNAL ;
    PORT
      LAYER M4 ;
        RECT  0 28.416 0.192 28.44 ;
    END
  END i[271]
  PIN i[272]
    DIRECTION INPUT ;
    USE SIGNAL ;
    PORT
      LAYER M4 ;
        RECT  0 28.512 0.192 28.536 ;
    END
  END i[272]
  PIN i[273]
    DIRECTION INPUT ;
    USE SIGNAL ;
    PORT
      LAYER M4 ;
        RECT  0 28.608 0.192 28.632 ;
    END
  END i[273]
  PIN i[274]
    DIRECTION INPUT ;
    USE SIGNAL ;
    PORT
      LAYER M4 ;
        RECT  0 28.704 0.192 28.728 ;
    END
  END i[274]
  PIN i[275]
    DIRECTION INPUT ;
    USE SIGNAL ;
    PORT
      LAYER M4 ;
        RECT  0 28.8 0.192 28.824 ;
    END
  END i[275]
  PIN i[276]
    DIRECTION INPUT ;
    USE SIGNAL ;
    PORT
      LAYER M4 ;
        RECT  0 28.896 0.192 28.92 ;
    END
  END i[276]
  PIN i[277]
    DIRECTION INPUT ;
    USE SIGNAL ;
    PORT
      LAYER M4 ;
        RECT  0 28.992 0.192 29.016 ;
    END
  END i[277]
  PIN i[278]
    DIRECTION INPUT ;
    USE SIGNAL ;
    PORT
      LAYER M4 ;
        RECT  0 29.088 0.192 29.112 ;
    END
  END i[278]
  PIN i[279]
    DIRECTION INPUT ;
    USE SIGNAL ;
    PORT
      LAYER M4 ;
        RECT  0 29.184 0.192 29.208 ;
    END
  END i[279]
  PIN i[27]
    DIRECTION INPUT ;
    USE SIGNAL ;
    PORT
      LAYER M4 ;
        RECT  0 4.848 0.192 4.872 ;
    END
  END i[27]
  PIN i[280]
    DIRECTION INPUT ;
    USE SIGNAL ;
    PORT
      LAYER M4 ;
        RECT  0 29.28 0.192 29.304 ;
    END
  END i[280]
  PIN i[281]
    DIRECTION INPUT ;
    USE SIGNAL ;
    PORT
      LAYER M4 ;
        RECT  0 29.376 0.192 29.4 ;
    END
  END i[281]
  PIN i[282]
    DIRECTION INPUT ;
    USE SIGNAL ;
    PORT
      LAYER M4 ;
        RECT  0 29.472 0.192 29.496 ;
    END
  END i[282]
  PIN i[283]
    DIRECTION INPUT ;
    USE SIGNAL ;
    PORT
      LAYER M4 ;
        RECT  0 29.568 0.192 29.592 ;
    END
  END i[283]
  PIN i[284]
    DIRECTION INPUT ;
    USE SIGNAL ;
    PORT
      LAYER M4 ;
        RECT  0 29.664 0.192 29.688 ;
    END
  END i[284]
  PIN i[285]
    DIRECTION INPUT ;
    USE SIGNAL ;
    PORT
      LAYER M4 ;
        RECT  0 29.808 0.192 29.832 ;
    END
  END i[285]
  PIN i[286]
    DIRECTION INPUT ;
    USE SIGNAL ;
    PORT
      LAYER M4 ;
        RECT  0 29.904 0.192 29.928 ;
    END
  END i[286]
  PIN i[287]
    DIRECTION INPUT ;
    USE SIGNAL ;
    PORT
      LAYER M4 ;
        RECT  0 30 0.192 30.024 ;
    END
  END i[287]
  PIN i[288]
    DIRECTION INPUT ;
    USE SIGNAL ;
    PORT
      LAYER M4 ;
        RECT  0 30.096 0.192 30.12 ;
    END
  END i[288]
  PIN i[289]
    DIRECTION INPUT ;
    USE SIGNAL ;
    PORT
      LAYER M4 ;
        RECT  0 30.192 0.192 30.216 ;
    END
  END i[289]
  PIN i[28]
    DIRECTION INPUT ;
    USE SIGNAL ;
    PORT
      LAYER M4 ;
        RECT  0 4.944 0.192 4.968 ;
    END
  END i[28]
  PIN i[290]
    DIRECTION INPUT ;
    USE SIGNAL ;
    PORT
      LAYER M4 ;
        RECT  0 30.288 0.192 30.312 ;
    END
  END i[290]
  PIN i[291]
    DIRECTION INPUT ;
    USE SIGNAL ;
    PORT
      LAYER M4 ;
        RECT  0 30.384 0.192 30.408 ;
    END
  END i[291]
  PIN i[292]
    DIRECTION INPUT ;
    USE SIGNAL ;
    PORT
      LAYER M4 ;
        RECT  0 30.48 0.192 30.504 ;
    END
  END i[292]
  PIN i[293]
    DIRECTION INPUT ;
    USE SIGNAL ;
    PORT
      LAYER M4 ;
        RECT  0 30.576 0.192 30.6 ;
    END
  END i[293]
  PIN i[294]
    DIRECTION INPUT ;
    USE SIGNAL ;
    PORT
      LAYER M4 ;
        RECT  0 30.672 0.192 30.696 ;
    END
  END i[294]
  PIN i[295]
    DIRECTION INPUT ;
    USE SIGNAL ;
    PORT
      LAYER M4 ;
        RECT  0 30.768 0.192 30.792 ;
    END
  END i[295]
  PIN i[296]
    DIRECTION INPUT ;
    USE SIGNAL ;
    PORT
      LAYER M4 ;
        RECT  0 30.864 0.192 30.888 ;
    END
  END i[296]
  PIN i[297]
    DIRECTION INPUT ;
    USE SIGNAL ;
    PORT
      LAYER M4 ;
        RECT  0 30.96 0.192 30.984 ;
    END
  END i[297]
  PIN i[298]
    DIRECTION INPUT ;
    USE SIGNAL ;
    PORT
      LAYER M4 ;
        RECT  0 31.056 0.192 31.08 ;
    END
  END i[298]
  PIN i[299]
    DIRECTION INPUT ;
    USE SIGNAL ;
    PORT
      LAYER M4 ;
        RECT  0 31.152 0.192 31.176 ;
    END
  END i[299]
  PIN i[29]
    DIRECTION INPUT ;
    USE SIGNAL ;
    PORT
      LAYER M4 ;
        RECT  0 5.04 0.192 5.064 ;
    END
  END i[29]
  PIN i[2]
    DIRECTION INPUT ;
    USE SIGNAL ;
    PORT
      LAYER M4 ;
        RECT  0 2.4 0.192 2.424 ;
    END
  END i[2]
  PIN i[300]
    DIRECTION INPUT ;
    USE SIGNAL ;
    PORT
      LAYER M4 ;
        RECT  0 31.248 0.192 31.272 ;
    END
  END i[300]
  PIN i[301]
    DIRECTION INPUT ;
    USE SIGNAL ;
    PORT
      LAYER M4 ;
        RECT  0 31.344 0.192 31.368 ;
    END
  END i[301]
  PIN i[302]
    DIRECTION INPUT ;
    USE SIGNAL ;
    PORT
      LAYER M4 ;
        RECT  0 31.44 0.192 31.464 ;
    END
  END i[302]
  PIN i[303]
    DIRECTION INPUT ;
    USE SIGNAL ;
    PORT
      LAYER M4 ;
        RECT  0 31.536 0.192 31.56 ;
    END
  END i[303]
  PIN i[304]
    DIRECTION INPUT ;
    USE SIGNAL ;
    PORT
      LAYER M4 ;
        RECT  0 31.632 0.192 31.656 ;
    END
  END i[304]
  PIN i[305]
    DIRECTION INPUT ;
    USE SIGNAL ;
    PORT
      LAYER M4 ;
        RECT  0 31.728 0.192 31.752 ;
    END
  END i[305]
  PIN i[306]
    DIRECTION INPUT ;
    USE SIGNAL ;
    PORT
      LAYER M4 ;
        RECT  0 31.824 0.192 31.848 ;
    END
  END i[306]
  PIN i[307]
    DIRECTION INPUT ;
    USE SIGNAL ;
    PORT
      LAYER M4 ;
        RECT  0 31.92 0.192 31.944 ;
    END
  END i[307]
  PIN i[308]
    DIRECTION INPUT ;
    USE SIGNAL ;
    PORT
      LAYER M4 ;
        RECT  0 32.016 0.192 32.04 ;
    END
  END i[308]
  PIN i[309]
    DIRECTION INPUT ;
    USE SIGNAL ;
    PORT
      LAYER M4 ;
        RECT  0 32.112 0.192 32.136 ;
    END
  END i[309]
  PIN i[30]
    DIRECTION INPUT ;
    USE SIGNAL ;
    PORT
      LAYER M4 ;
        RECT  0 5.136 0.192 5.16 ;
    END
  END i[30]
  PIN i[310]
    DIRECTION INPUT ;
    USE SIGNAL ;
    PORT
      LAYER M4 ;
        RECT  0 32.208 0.192 32.232 ;
    END
  END i[310]
  PIN i[311]
    DIRECTION INPUT ;
    USE SIGNAL ;
    PORT
      LAYER M4 ;
        RECT  0 32.304 0.192 32.328 ;
    END
  END i[311]
  PIN i[312]
    DIRECTION INPUT ;
    USE SIGNAL ;
    PORT
      LAYER M4 ;
        RECT  0 32.4 0.192 32.424 ;
    END
  END i[312]
  PIN i[313]
    DIRECTION INPUT ;
    USE SIGNAL ;
    PORT
      LAYER M4 ;
        RECT  0 32.496 0.192 32.52 ;
    END
  END i[313]
  PIN i[314]
    DIRECTION INPUT ;
    USE SIGNAL ;
    PORT
      LAYER M4 ;
        RECT  0 32.592 0.192 32.616 ;
    END
  END i[314]
  PIN i[315]
    DIRECTION INPUT ;
    USE SIGNAL ;
    PORT
      LAYER M4 ;
        RECT  0 32.688 0.192 32.712 ;
    END
  END i[315]
  PIN i[316]
    DIRECTION INPUT ;
    USE SIGNAL ;
    PORT
      LAYER M4 ;
        RECT  0 32.784 0.192 32.808 ;
    END
  END i[316]
  PIN i[317]
    DIRECTION INPUT ;
    USE SIGNAL ;
    PORT
      LAYER M4 ;
        RECT  0 32.88 0.192 32.904 ;
    END
  END i[317]
  PIN i[318]
    DIRECTION INPUT ;
    USE SIGNAL ;
    PORT
      LAYER M4 ;
        RECT  0 32.976 0.192 33 ;
    END
  END i[318]
  PIN i[319]
    DIRECTION INPUT ;
    USE SIGNAL ;
    PORT
      LAYER M4 ;
        RECT  0 33.072 0.192 33.096 ;
    END
  END i[319]
  PIN i[31]
    DIRECTION INPUT ;
    USE SIGNAL ;
    PORT
      LAYER M4 ;
        RECT  0 5.232 0.192 5.256 ;
    END
  END i[31]
  PIN i[320]
    DIRECTION INPUT ;
    USE SIGNAL ;
    PORT
      LAYER M4 ;
        RECT  0 33.168 0.192 33.192 ;
    END
  END i[320]
  PIN i[321]
    DIRECTION INPUT ;
    USE SIGNAL ;
    PORT
      LAYER M4 ;
        RECT  0 33.264 0.192 33.288 ;
    END
  END i[321]
  PIN i[322]
    DIRECTION INPUT ;
    USE SIGNAL ;
    PORT
      LAYER M4 ;
        RECT  0 33.36 0.192 33.384 ;
    END
  END i[322]
  PIN i[323]
    DIRECTION INPUT ;
    USE SIGNAL ;
    PORT
      LAYER M4 ;
        RECT  0 33.456 0.192 33.48 ;
    END
  END i[323]
  PIN i[324]
    DIRECTION INPUT ;
    USE SIGNAL ;
    PORT
      LAYER M4 ;
        RECT  0 33.552 0.192 33.576 ;
    END
  END i[324]
  PIN i[325]
    DIRECTION INPUT ;
    USE SIGNAL ;
    PORT
      LAYER M4 ;
        RECT  0 33.648 0.192 33.672 ;
    END
  END i[325]
  PIN i[326]
    DIRECTION INPUT ;
    USE SIGNAL ;
    PORT
      LAYER M4 ;
        RECT  0 33.744 0.192 33.768 ;
    END
  END i[326]
  PIN i[327]
    DIRECTION INPUT ;
    USE SIGNAL ;
    PORT
      LAYER M4 ;
        RECT  0 33.84 0.192 33.864 ;
    END
  END i[327]
  PIN i[328]
    DIRECTION INPUT ;
    USE SIGNAL ;
    PORT
      LAYER M4 ;
        RECT  0 33.936 0.192 33.96 ;
    END
  END i[328]
  PIN i[329]
    DIRECTION INPUT ;
    USE SIGNAL ;
    PORT
      LAYER M4 ;
        RECT  0 34.032 0.192 34.056 ;
    END
  END i[329]
  PIN i[32]
    DIRECTION INPUT ;
    USE SIGNAL ;
    PORT
      LAYER M4 ;
        RECT  0 5.328 0.192 5.352 ;
    END
  END i[32]
  PIN i[330]
    DIRECTION INPUT ;
    USE SIGNAL ;
    PORT
      LAYER M4 ;
        RECT  0 34.128 0.192 34.152 ;
    END
  END i[330]
  PIN i[331]
    DIRECTION INPUT ;
    USE SIGNAL ;
    PORT
      LAYER M4 ;
        RECT  0 34.224 0.192 34.248 ;
    END
  END i[331]
  PIN i[332]
    DIRECTION INPUT ;
    USE SIGNAL ;
    PORT
      LAYER M4 ;
        RECT  0 34.32 0.192 34.344 ;
    END
  END i[332]
  PIN i[333]
    DIRECTION INPUT ;
    USE SIGNAL ;
    PORT
      LAYER M4 ;
        RECT  0 34.416 0.192 34.44 ;
    END
  END i[333]
  PIN i[334]
    DIRECTION INPUT ;
    USE SIGNAL ;
    PORT
      LAYER M4 ;
        RECT  0 34.512 0.192 34.536 ;
    END
  END i[334]
  PIN i[335]
    DIRECTION INPUT ;
    USE SIGNAL ;
    PORT
      LAYER M4 ;
        RECT  0 34.608 0.192 34.632 ;
    END
  END i[335]
  PIN i[336]
    DIRECTION INPUT ;
    USE SIGNAL ;
    PORT
      LAYER M4 ;
        RECT  0 34.704 0.192 34.728 ;
    END
  END i[336]
  PIN i[337]
    DIRECTION INPUT ;
    USE SIGNAL ;
    PORT
      LAYER M4 ;
        RECT  0 34.8 0.192 34.824 ;
    END
  END i[337]
  PIN i[338]
    DIRECTION INPUT ;
    USE SIGNAL ;
    PORT
      LAYER M4 ;
        RECT  0 34.896 0.192 34.92 ;
    END
  END i[338]
  PIN i[339]
    DIRECTION INPUT ;
    USE SIGNAL ;
    PORT
      LAYER M4 ;
        RECT  0 34.992 0.192 35.016 ;
    END
  END i[339]
  PIN i[33]
    DIRECTION INPUT ;
    USE SIGNAL ;
    PORT
      LAYER M4 ;
        RECT  0 5.424 0.192 5.448 ;
    END
  END i[33]
  PIN i[340]
    DIRECTION INPUT ;
    USE SIGNAL ;
    PORT
      LAYER M4 ;
        RECT  0 35.088 0.192 35.112 ;
    END
  END i[340]
  PIN i[341]
    DIRECTION INPUT ;
    USE SIGNAL ;
    PORT
      LAYER M4 ;
        RECT  0 35.184 0.192 35.208 ;
    END
  END i[341]
  PIN i[342]
    DIRECTION INPUT ;
    USE SIGNAL ;
    PORT
      LAYER M4 ;
        RECT  0 35.28 0.192 35.304 ;
    END
  END i[342]
  PIN i[343]
    DIRECTION INPUT ;
    USE SIGNAL ;
    PORT
      LAYER M4 ;
        RECT  0 35.376 0.192 35.4 ;
    END
  END i[343]
  PIN i[344]
    DIRECTION INPUT ;
    USE SIGNAL ;
    PORT
      LAYER M4 ;
        RECT  0 35.472 0.192 35.496 ;
    END
  END i[344]
  PIN i[345]
    DIRECTION INPUT ;
    USE SIGNAL ;
    PORT
      LAYER M4 ;
        RECT  0 35.568 0.192 35.592 ;
    END
  END i[345]
  PIN i[346]
    DIRECTION INPUT ;
    USE SIGNAL ;
    PORT
      LAYER M4 ;
        RECT  0 35.664 0.192 35.688 ;
    END
  END i[346]
  PIN i[347]
    DIRECTION INPUT ;
    USE SIGNAL ;
    PORT
      LAYER M4 ;
        RECT  0 35.76 0.192 35.784 ;
    END
  END i[347]
  PIN i[348]
    DIRECTION INPUT ;
    USE SIGNAL ;
    PORT
      LAYER M4 ;
        RECT  0 35.856 0.192 35.88 ;
    END
  END i[348]
  PIN i[349]
    DIRECTION INPUT ;
    USE SIGNAL ;
    PORT
      LAYER M4 ;
        RECT  0 35.952 0.192 35.976 ;
    END
  END i[349]
  PIN i[34]
    DIRECTION INPUT ;
    USE SIGNAL ;
    PORT
      LAYER M4 ;
        RECT  0 5.52 0.192 5.544 ;
    END
  END i[34]
  PIN i[350]
    DIRECTION INPUT ;
    USE SIGNAL ;
    PORT
      LAYER M4 ;
        RECT  0 36.048 0.192 36.072 ;
    END
  END i[350]
  PIN i[351]
    DIRECTION INPUT ;
    USE SIGNAL ;
    PORT
      LAYER M4 ;
        RECT  0 36.144 0.192 36.168 ;
    END
  END i[351]
  PIN i[352]
    DIRECTION INPUT ;
    USE SIGNAL ;
    PORT
      LAYER M4 ;
        RECT  0 36.288 0.192 36.312 ;
    END
  END i[352]
  PIN i[353]
    DIRECTION INPUT ;
    USE SIGNAL ;
    PORT
      LAYER M4 ;
        RECT  0 36.384 0.192 36.408 ;
    END
  END i[353]
  PIN i[354]
    DIRECTION INPUT ;
    USE SIGNAL ;
    PORT
      LAYER M4 ;
        RECT  0 36.48 0.192 36.504 ;
    END
  END i[354]
  PIN i[355]
    DIRECTION INPUT ;
    USE SIGNAL ;
    PORT
      LAYER M4 ;
        RECT  0 36.576 0.192 36.6 ;
    END
  END i[355]
  PIN i[356]
    DIRECTION INPUT ;
    USE SIGNAL ;
    PORT
      LAYER M4 ;
        RECT  0 36.672 0.192 36.696 ;
    END
  END i[356]
  PIN i[357]
    DIRECTION INPUT ;
    USE SIGNAL ;
    PORT
      LAYER M4 ;
        RECT  0 36.768 0.192 36.792 ;
    END
  END i[357]
  PIN i[358]
    DIRECTION INPUT ;
    USE SIGNAL ;
    PORT
      LAYER M4 ;
        RECT  0 36.864 0.192 36.888 ;
    END
  END i[358]
  PIN i[359]
    DIRECTION INPUT ;
    USE SIGNAL ;
    PORT
      LAYER M4 ;
        RECT  0 36.96 0.192 36.984 ;
    END
  END i[359]
  PIN i[35]
    DIRECTION INPUT ;
    USE SIGNAL ;
    PORT
      LAYER M4 ;
        RECT  0 5.616 0.192 5.64 ;
    END
  END i[35]
  PIN i[360]
    DIRECTION INPUT ;
    USE SIGNAL ;
    PORT
      LAYER M4 ;
        RECT  0 37.056 0.192 37.08 ;
    END
  END i[360]
  PIN i[361]
    DIRECTION INPUT ;
    USE SIGNAL ;
    PORT
      LAYER M4 ;
        RECT  0 37.152 0.192 37.176 ;
    END
  END i[361]
  PIN i[362]
    DIRECTION INPUT ;
    USE SIGNAL ;
    PORT
      LAYER M4 ;
        RECT  0 37.248 0.192 37.272 ;
    END
  END i[362]
  PIN i[363]
    DIRECTION INPUT ;
    USE SIGNAL ;
    PORT
      LAYER M4 ;
        RECT  0 37.344 0.192 37.368 ;
    END
  END i[363]
  PIN i[364]
    DIRECTION INPUT ;
    USE SIGNAL ;
    PORT
      LAYER M4 ;
        RECT  0 37.44 0.192 37.464 ;
    END
  END i[364]
  PIN i[365]
    DIRECTION INPUT ;
    USE SIGNAL ;
    PORT
      LAYER M4 ;
        RECT  0 37.536 0.192 37.56 ;
    END
  END i[365]
  PIN i[366]
    DIRECTION INPUT ;
    USE SIGNAL ;
    PORT
      LAYER M4 ;
        RECT  0 37.632 0.192 37.656 ;
    END
  END i[366]
  PIN i[367]
    DIRECTION INPUT ;
    USE SIGNAL ;
    PORT
      LAYER M4 ;
        RECT  0 37.728 0.192 37.752 ;
    END
  END i[367]
  PIN i[368]
    DIRECTION INPUT ;
    USE SIGNAL ;
    PORT
      LAYER M4 ;
        RECT  0 37.824 0.192 37.848 ;
    END
  END i[368]
  PIN i[369]
    DIRECTION INPUT ;
    USE SIGNAL ;
    PORT
      LAYER M4 ;
        RECT  0 37.92 0.192 37.944 ;
    END
  END i[369]
  PIN i[36]
    DIRECTION INPUT ;
    USE SIGNAL ;
    PORT
      LAYER M4 ;
        RECT  0 5.712 0.192 5.736 ;
    END
  END i[36]
  PIN i[370]
    DIRECTION INPUT ;
    USE SIGNAL ;
    PORT
      LAYER M4 ;
        RECT  0 38.016 0.192 38.04 ;
    END
  END i[370]
  PIN i[371]
    DIRECTION INPUT ;
    USE SIGNAL ;
    PORT
      LAYER M4 ;
        RECT  0 38.112 0.192 38.136 ;
    END
  END i[371]
  PIN i[372]
    DIRECTION INPUT ;
    USE SIGNAL ;
    PORT
      LAYER M4 ;
        RECT  0 38.208 0.192 38.232 ;
    END
  END i[372]
  PIN i[373]
    DIRECTION INPUT ;
    USE SIGNAL ;
    PORT
      LAYER M4 ;
        RECT  0 38.304 0.192 38.328 ;
    END
  END i[373]
  PIN i[374]
    DIRECTION INPUT ;
    USE SIGNAL ;
    PORT
      LAYER M4 ;
        RECT  0 38.4 0.192 38.424 ;
    END
  END i[374]
  PIN i[375]
    DIRECTION INPUT ;
    USE SIGNAL ;
    PORT
      LAYER M4 ;
        RECT  0 38.496 0.192 38.52 ;
    END
  END i[375]
  PIN i[376]
    DIRECTION INPUT ;
    USE SIGNAL ;
    PORT
      LAYER M4 ;
        RECT  0 38.592 0.192 38.616 ;
    END
  END i[376]
  PIN i[377]
    DIRECTION INPUT ;
    USE SIGNAL ;
    PORT
      LAYER M4 ;
        RECT  0 38.688 0.192 38.712 ;
    END
  END i[377]
  PIN i[378]
    DIRECTION INPUT ;
    USE SIGNAL ;
    PORT
      LAYER M4 ;
        RECT  0 38.784 0.192 38.808 ;
    END
  END i[378]
  PIN i[379]
    DIRECTION INPUT ;
    USE SIGNAL ;
    PORT
      LAYER M4 ;
        RECT  0 38.88 0.192 38.904 ;
    END
  END i[379]
  PIN i[37]
    DIRECTION INPUT ;
    USE SIGNAL ;
    PORT
      LAYER M4 ;
        RECT  0 5.808 0.192 5.832 ;
    END
  END i[37]
  PIN i[380]
    DIRECTION INPUT ;
    USE SIGNAL ;
    PORT
      LAYER M4 ;
        RECT  0 38.976 0.192 39 ;
    END
  END i[380]
  PIN i[381]
    DIRECTION INPUT ;
    USE SIGNAL ;
    PORT
      LAYER M4 ;
        RECT  0 39.072 0.192 39.096 ;
    END
  END i[381]
  PIN i[382]
    DIRECTION INPUT ;
    USE SIGNAL ;
    PORT
      LAYER M4 ;
        RECT  0 39.168 0.192 39.192 ;
    END
  END i[382]
  PIN i[383]
    DIRECTION INPUT ;
    USE SIGNAL ;
    PORT
      LAYER M4 ;
        RECT  0 39.264 0.192 39.288 ;
    END
  END i[383]
  PIN i[384]
    DIRECTION INPUT ;
    USE SIGNAL ;
    PORT
      LAYER M4 ;
        RECT  0 39.36 0.192 39.384 ;
    END
  END i[384]
  PIN i[385]
    DIRECTION INPUT ;
    USE SIGNAL ;
    PORT
      LAYER M4 ;
        RECT  0 39.456 0.192 39.48 ;
    END
  END i[385]
  PIN i[386]
    DIRECTION INPUT ;
    USE SIGNAL ;
    PORT
      LAYER M4 ;
        RECT  0 39.552 0.192 39.576 ;
    END
  END i[386]
  PIN i[387]
    DIRECTION INPUT ;
    USE SIGNAL ;
    PORT
      LAYER M4 ;
        RECT  0 39.648 0.192 39.672 ;
    END
  END i[387]
  PIN i[388]
    DIRECTION INPUT ;
    USE SIGNAL ;
    PORT
      LAYER M4 ;
        RECT  0 39.744 0.192 39.768 ;
    END
  END i[388]
  PIN i[389]
    DIRECTION INPUT ;
    USE SIGNAL ;
    PORT
      LAYER M4 ;
        RECT  0 39.84 0.192 39.864 ;
    END
  END i[389]
  PIN i[38]
    DIRECTION INPUT ;
    USE SIGNAL ;
    PORT
      LAYER M4 ;
        RECT  0 5.904 0.192 5.928 ;
    END
  END i[38]
  PIN i[390]
    DIRECTION INPUT ;
    USE SIGNAL ;
    PORT
      LAYER M4 ;
        RECT  0 39.936 0.192 39.96 ;
    END
  END i[390]
  PIN i[391]
    DIRECTION INPUT ;
    USE SIGNAL ;
    PORT
      LAYER M4 ;
        RECT  0 40.032 0.192 40.056 ;
    END
  END i[391]
  PIN i[392]
    DIRECTION INPUT ;
    USE SIGNAL ;
    PORT
      LAYER M4 ;
        RECT  0 40.128 0.192 40.152 ;
    END
  END i[392]
  PIN i[393]
    DIRECTION INPUT ;
    USE SIGNAL ;
    PORT
      LAYER M4 ;
        RECT  0 40.224 0.192 40.248 ;
    END
  END i[393]
  PIN i[394]
    DIRECTION INPUT ;
    USE SIGNAL ;
    PORT
      LAYER M4 ;
        RECT  0 40.32 0.192 40.344 ;
    END
  END i[394]
  PIN i[395]
    DIRECTION INPUT ;
    USE SIGNAL ;
    PORT
      LAYER M4 ;
        RECT  0 40.416 0.192 40.44 ;
    END
  END i[395]
  PIN i[396]
    DIRECTION INPUT ;
    USE SIGNAL ;
    PORT
      LAYER M4 ;
        RECT  0 40.512 0.192 40.536 ;
    END
  END i[396]
  PIN i[397]
    DIRECTION INPUT ;
    USE SIGNAL ;
    PORT
      LAYER M4 ;
        RECT  0 40.608 0.192 40.632 ;
    END
  END i[397]
  PIN i[398]
    DIRECTION INPUT ;
    USE SIGNAL ;
    PORT
      LAYER M4 ;
        RECT  0 40.704 0.192 40.728 ;
    END
  END i[398]
  PIN i[399]
    DIRECTION INPUT ;
    USE SIGNAL ;
    PORT
      LAYER M4 ;
        RECT  0 40.8 0.192 40.824 ;
    END
  END i[399]
  PIN i[39]
    DIRECTION INPUT ;
    USE SIGNAL ;
    PORT
      LAYER M4 ;
        RECT  0 6 0.192 6.024 ;
    END
  END i[39]
  PIN i[3]
    DIRECTION INPUT ;
    USE SIGNAL ;
    PORT
      LAYER M4 ;
        RECT  0 2.496 0.192 2.52 ;
    END
  END i[3]
  PIN i[400]
    DIRECTION INPUT ;
    USE SIGNAL ;
    PORT
      LAYER M4 ;
        RECT  0 40.896 0.192 40.92 ;
    END
  END i[400]
  PIN i[401]
    DIRECTION INPUT ;
    USE SIGNAL ;
    PORT
      LAYER M4 ;
        RECT  0 40.992 0.192 41.016 ;
    END
  END i[401]
  PIN i[402]
    DIRECTION INPUT ;
    USE SIGNAL ;
    PORT
      LAYER M4 ;
        RECT  0 41.088 0.192 41.112 ;
    END
  END i[402]
  PIN i[403]
    DIRECTION INPUT ;
    USE SIGNAL ;
    PORT
      LAYER M4 ;
        RECT  0 41.184 0.192 41.208 ;
    END
  END i[403]
  PIN i[404]
    DIRECTION INPUT ;
    USE SIGNAL ;
    PORT
      LAYER M4 ;
        RECT  0 41.28 0.192 41.304 ;
    END
  END i[404]
  PIN i[405]
    DIRECTION INPUT ;
    USE SIGNAL ;
    PORT
      LAYER M4 ;
        RECT  0 41.376 0.192 41.4 ;
    END
  END i[405]
  PIN i[406]
    DIRECTION INPUT ;
    USE SIGNAL ;
    PORT
      LAYER M4 ;
        RECT  0 41.472 0.192 41.496 ;
    END
  END i[406]
  PIN i[407]
    DIRECTION INPUT ;
    USE SIGNAL ;
    PORT
      LAYER M4 ;
        RECT  0 41.568 0.192 41.592 ;
    END
  END i[407]
  PIN i[408]
    DIRECTION INPUT ;
    USE SIGNAL ;
    PORT
      LAYER M4 ;
        RECT  0 41.664 0.192 41.688 ;
    END
  END i[408]
  PIN i[409]
    DIRECTION INPUT ;
    USE SIGNAL ;
    PORT
      LAYER M4 ;
        RECT  0 41.76 0.192 41.784 ;
    END
  END i[409]
  PIN i[40]
    DIRECTION INPUT ;
    USE SIGNAL ;
    PORT
      LAYER M4 ;
        RECT  0 6.096 0.192 6.12 ;
    END
  END i[40]
  PIN i[410]
    DIRECTION INPUT ;
    USE SIGNAL ;
    PORT
      LAYER M4 ;
        RECT  0 41.856 0.192 41.88 ;
    END
  END i[410]
  PIN i[411]
    DIRECTION INPUT ;
    USE SIGNAL ;
    PORT
      LAYER M4 ;
        RECT  0 41.952 0.192 41.976 ;
    END
  END i[411]
  PIN i[412]
    DIRECTION INPUT ;
    USE SIGNAL ;
    PORT
      LAYER M4 ;
        RECT  0 42.048 0.192 42.072 ;
    END
  END i[412]
  PIN i[413]
    DIRECTION INPUT ;
    USE SIGNAL ;
    PORT
      LAYER M4 ;
        RECT  0 42.144 0.192 42.168 ;
    END
  END i[413]
  PIN i[414]
    DIRECTION INPUT ;
    USE SIGNAL ;
    PORT
      LAYER M4 ;
        RECT  0 42.24 0.192 42.264 ;
    END
  END i[414]
  PIN i[415]
    DIRECTION INPUT ;
    USE SIGNAL ;
    PORT
      LAYER M4 ;
        RECT  0 42.336 0.192 42.36 ;
    END
  END i[415]
  PIN i[416]
    DIRECTION INPUT ;
    USE SIGNAL ;
    PORT
      LAYER M4 ;
        RECT  0 42.432 0.192 42.456 ;
    END
  END i[416]
  PIN i[417]
    DIRECTION INPUT ;
    USE SIGNAL ;
    PORT
      LAYER M4 ;
        RECT  0 42.528 0.192 42.552 ;
    END
  END i[417]
  PIN i[418]
    DIRECTION INPUT ;
    USE SIGNAL ;
    PORT
      LAYER M4 ;
        RECT  0 42.624 0.192 42.648 ;
    END
  END i[418]
  PIN i[419]
    DIRECTION INPUT ;
    USE SIGNAL ;
    PORT
      LAYER M4 ;
        RECT  0 42.768 0.192 42.792 ;
    END
  END i[419]
  PIN i[41]
    DIRECTION INPUT ;
    USE SIGNAL ;
    PORT
      LAYER M4 ;
        RECT  0 6.192 0.192 6.216 ;
    END
  END i[41]
  PIN i[420]
    DIRECTION INPUT ;
    USE SIGNAL ;
    PORT
      LAYER M4 ;
        RECT  0 42.864 0.192 42.888 ;
    END
  END i[420]
  PIN i[421]
    DIRECTION INPUT ;
    USE SIGNAL ;
    PORT
      LAYER M4 ;
        RECT  0 42.96 0.192 42.984 ;
    END
  END i[421]
  PIN i[422]
    DIRECTION INPUT ;
    USE SIGNAL ;
    PORT
      LAYER M4 ;
        RECT  0 43.056 0.192 43.08 ;
    END
  END i[422]
  PIN i[423]
    DIRECTION INPUT ;
    USE SIGNAL ;
    PORT
      LAYER M4 ;
        RECT  0 43.152 0.192 43.176 ;
    END
  END i[423]
  PIN i[424]
    DIRECTION INPUT ;
    USE SIGNAL ;
    PORT
      LAYER M4 ;
        RECT  0 43.248 0.192 43.272 ;
    END
  END i[424]
  PIN i[425]
    DIRECTION INPUT ;
    USE SIGNAL ;
    PORT
      LAYER M4 ;
        RECT  0 43.344 0.192 43.368 ;
    END
  END i[425]
  PIN i[426]
    DIRECTION INPUT ;
    USE SIGNAL ;
    PORT
      LAYER M4 ;
        RECT  0 43.44 0.192 43.464 ;
    END
  END i[426]
  PIN i[427]
    DIRECTION INPUT ;
    USE SIGNAL ;
    PORT
      LAYER M4 ;
        RECT  0 43.536 0.192 43.56 ;
    END
  END i[427]
  PIN i[428]
    DIRECTION INPUT ;
    USE SIGNAL ;
    PORT
      LAYER M4 ;
        RECT  0 43.632 0.192 43.656 ;
    END
  END i[428]
  PIN i[429]
    DIRECTION INPUT ;
    USE SIGNAL ;
    PORT
      LAYER M4 ;
        RECT  0 43.728 0.192 43.752 ;
    END
  END i[429]
  PIN i[42]
    DIRECTION INPUT ;
    USE SIGNAL ;
    PORT
      LAYER M4 ;
        RECT  0 6.288 0.192 6.312 ;
    END
  END i[42]
  PIN i[430]
    DIRECTION INPUT ;
    USE SIGNAL ;
    PORT
      LAYER M4 ;
        RECT  0 43.824 0.192 43.848 ;
    END
  END i[430]
  PIN i[431]
    DIRECTION INPUT ;
    USE SIGNAL ;
    PORT
      LAYER M4 ;
        RECT  0 43.92 0.192 43.944 ;
    END
  END i[431]
  PIN i[432]
    DIRECTION INPUT ;
    USE SIGNAL ;
    PORT
      LAYER M4 ;
        RECT  0 44.016 0.192 44.04 ;
    END
  END i[432]
  PIN i[433]
    DIRECTION INPUT ;
    USE SIGNAL ;
    PORT
      LAYER M4 ;
        RECT  0 44.112 0.192 44.136 ;
    END
  END i[433]
  PIN i[434]
    DIRECTION INPUT ;
    USE SIGNAL ;
    PORT
      LAYER M4 ;
        RECT  0 44.208 0.192 44.232 ;
    END
  END i[434]
  PIN i[435]
    DIRECTION INPUT ;
    USE SIGNAL ;
    PORT
      LAYER M4 ;
        RECT  0 44.304 0.192 44.328 ;
    END
  END i[435]
  PIN i[436]
    DIRECTION INPUT ;
    USE SIGNAL ;
    PORT
      LAYER M4 ;
        RECT  0 44.4 0.192 44.424 ;
    END
  END i[436]
  PIN i[437]
    DIRECTION INPUT ;
    USE SIGNAL ;
    PORT
      LAYER M4 ;
        RECT  0 44.496 0.192 44.52 ;
    END
  END i[437]
  PIN i[438]
    DIRECTION INPUT ;
    USE SIGNAL ;
    PORT
      LAYER M4 ;
        RECT  0 44.592 0.192 44.616 ;
    END
  END i[438]
  PIN i[439]
    DIRECTION INPUT ;
    USE SIGNAL ;
    PORT
      LAYER M4 ;
        RECT  0 44.688 0.192 44.712 ;
    END
  END i[439]
  PIN i[43]
    DIRECTION INPUT ;
    USE SIGNAL ;
    PORT
      LAYER M4 ;
        RECT  0 6.384 0.192 6.408 ;
    END
  END i[43]
  PIN i[440]
    DIRECTION INPUT ;
    USE SIGNAL ;
    PORT
      LAYER M4 ;
        RECT  0 44.784 0.192 44.808 ;
    END
  END i[440]
  PIN i[441]
    DIRECTION INPUT ;
    USE SIGNAL ;
    PORT
      LAYER M4 ;
        RECT  0 44.88 0.192 44.904 ;
    END
  END i[441]
  PIN i[442]
    DIRECTION INPUT ;
    USE SIGNAL ;
    PORT
      LAYER M4 ;
        RECT  0 44.976 0.192 45 ;
    END
  END i[442]
  PIN i[443]
    DIRECTION INPUT ;
    USE SIGNAL ;
    PORT
      LAYER M4 ;
        RECT  0 45.072 0.192 45.096 ;
    END
  END i[443]
  PIN i[444]
    DIRECTION INPUT ;
    USE SIGNAL ;
    PORT
      LAYER M4 ;
        RECT  0 45.168 0.192 45.192 ;
    END
  END i[444]
  PIN i[445]
    DIRECTION INPUT ;
    USE SIGNAL ;
    PORT
      LAYER M4 ;
        RECT  0 45.264 0.192 45.288 ;
    END
  END i[445]
  PIN i[446]
    DIRECTION INPUT ;
    USE SIGNAL ;
    PORT
      LAYER M4 ;
        RECT  0 45.36 0.192 45.384 ;
    END
  END i[446]
  PIN i[447]
    DIRECTION INPUT ;
    USE SIGNAL ;
    PORT
      LAYER M4 ;
        RECT  0 45.456 0.192 45.48 ;
    END
  END i[447]
  PIN i[448]
    DIRECTION INPUT ;
    USE SIGNAL ;
    PORT
      LAYER M4 ;
        RECT  0 45.552 0.192 45.576 ;
    END
  END i[448]
  PIN i[449]
    DIRECTION INPUT ;
    USE SIGNAL ;
    PORT
      LAYER M4 ;
        RECT  0 45.648 0.192 45.672 ;
    END
  END i[449]
  PIN i[44]
    DIRECTION INPUT ;
    USE SIGNAL ;
    PORT
      LAYER M4 ;
        RECT  0 6.48 0.192 6.504 ;
    END
  END i[44]
  PIN i[450]
    DIRECTION INPUT ;
    USE SIGNAL ;
    PORT
      LAYER M4 ;
        RECT  0 45.744 0.192 45.768 ;
    END
  END i[450]
  PIN i[451]
    DIRECTION INPUT ;
    USE SIGNAL ;
    PORT
      LAYER M4 ;
        RECT  0 45.84 0.192 45.864 ;
    END
  END i[451]
  PIN i[452]
    DIRECTION INPUT ;
    USE SIGNAL ;
    PORT
      LAYER M4 ;
        RECT  0 45.936 0.192 45.96 ;
    END
  END i[452]
  PIN i[453]
    DIRECTION INPUT ;
    USE SIGNAL ;
    PORT
      LAYER M4 ;
        RECT  0 46.032 0.192 46.056 ;
    END
  END i[453]
  PIN i[454]
    DIRECTION INPUT ;
    USE SIGNAL ;
    PORT
      LAYER M4 ;
        RECT  0 46.128 0.192 46.152 ;
    END
  END i[454]
  PIN i[455]
    DIRECTION INPUT ;
    USE SIGNAL ;
    PORT
      LAYER M4 ;
        RECT  0 46.224 0.192 46.248 ;
    END
  END i[455]
  PIN i[456]
    DIRECTION INPUT ;
    USE SIGNAL ;
    PORT
      LAYER M4 ;
        RECT  0 46.32 0.192 46.344 ;
    END
  END i[456]
  PIN i[457]
    DIRECTION INPUT ;
    USE SIGNAL ;
    PORT
      LAYER M4 ;
        RECT  0 46.416 0.192 46.44 ;
    END
  END i[457]
  PIN i[458]
    DIRECTION INPUT ;
    USE SIGNAL ;
    PORT
      LAYER M4 ;
        RECT  0 46.512 0.192 46.536 ;
    END
  END i[458]
  PIN i[459]
    DIRECTION INPUT ;
    USE SIGNAL ;
    PORT
      LAYER M4 ;
        RECT  0 46.608 0.192 46.632 ;
    END
  END i[459]
  PIN i[45]
    DIRECTION INPUT ;
    USE SIGNAL ;
    PORT
      LAYER M4 ;
        RECT  0 6.576 0.192 6.6 ;
    END
  END i[45]
  PIN i[460]
    DIRECTION INPUT ;
    USE SIGNAL ;
    PORT
      LAYER M4 ;
        RECT  0 46.704 0.192 46.728 ;
    END
  END i[460]
  PIN i[461]
    DIRECTION INPUT ;
    USE SIGNAL ;
    PORT
      LAYER M4 ;
        RECT  0 46.8 0.192 46.824 ;
    END
  END i[461]
  PIN i[462]
    DIRECTION INPUT ;
    USE SIGNAL ;
    PORT
      LAYER M4 ;
        RECT  0 46.896 0.192 46.92 ;
    END
  END i[462]
  PIN i[463]
    DIRECTION INPUT ;
    USE SIGNAL ;
    PORT
      LAYER M4 ;
        RECT  0 46.992 0.192 47.016 ;
    END
  END i[463]
  PIN i[464]
    DIRECTION INPUT ;
    USE SIGNAL ;
    PORT
      LAYER M4 ;
        RECT  0 47.088 0.192 47.112 ;
    END
  END i[464]
  PIN i[465]
    DIRECTION INPUT ;
    USE SIGNAL ;
    PORT
      LAYER M4 ;
        RECT  0 47.184 0.192 47.208 ;
    END
  END i[465]
  PIN i[466]
    DIRECTION INPUT ;
    USE SIGNAL ;
    PORT
      LAYER M4 ;
        RECT  0 47.28 0.192 47.304 ;
    END
  END i[466]
  PIN i[467]
    DIRECTION INPUT ;
    USE SIGNAL ;
    PORT
      LAYER M4 ;
        RECT  0 47.376 0.192 47.4 ;
    END
  END i[467]
  PIN i[468]
    DIRECTION INPUT ;
    USE SIGNAL ;
    PORT
      LAYER M4 ;
        RECT  0 47.472 0.192 47.496 ;
    END
  END i[468]
  PIN i[469]
    DIRECTION INPUT ;
    USE SIGNAL ;
    PORT
      LAYER M4 ;
        RECT  0 47.568 0.192 47.592 ;
    END
  END i[469]
  PIN i[46]
    DIRECTION INPUT ;
    USE SIGNAL ;
    PORT
      LAYER M4 ;
        RECT  0 6.672 0.192 6.696 ;
    END
  END i[46]
  PIN i[470]
    DIRECTION INPUT ;
    USE SIGNAL ;
    PORT
      LAYER M4 ;
        RECT  0 47.664 0.192 47.688 ;
    END
  END i[470]
  PIN i[471]
    DIRECTION INPUT ;
    USE SIGNAL ;
    PORT
      LAYER M4 ;
        RECT  0 47.76 0.192 47.784 ;
    END
  END i[471]
  PIN i[472]
    DIRECTION INPUT ;
    USE SIGNAL ;
    PORT
      LAYER M4 ;
        RECT  0 47.856 0.192 47.88 ;
    END
  END i[472]
  PIN i[473]
    DIRECTION INPUT ;
    USE SIGNAL ;
    PORT
      LAYER M4 ;
        RECT  0 47.952 0.192 47.976 ;
    END
  END i[473]
  PIN i[474]
    DIRECTION INPUT ;
    USE SIGNAL ;
    PORT
      LAYER M4 ;
        RECT  0 48.048 0.192 48.072 ;
    END
  END i[474]
  PIN i[475]
    DIRECTION INPUT ;
    USE SIGNAL ;
    PORT
      LAYER M4 ;
        RECT  0 48.144 0.192 48.168 ;
    END
  END i[475]
  PIN i[476]
    DIRECTION INPUT ;
    USE SIGNAL ;
    PORT
      LAYER M4 ;
        RECT  0 48.24 0.192 48.264 ;
    END
  END i[476]
  PIN i[477]
    DIRECTION INPUT ;
    USE SIGNAL ;
    PORT
      LAYER M4 ;
        RECT  0 48.336 0.192 48.36 ;
    END
  END i[477]
  PIN i[478]
    DIRECTION INPUT ;
    USE SIGNAL ;
    PORT
      LAYER M4 ;
        RECT  0 48.432 0.192 48.456 ;
    END
  END i[478]
  PIN i[479]
    DIRECTION INPUT ;
    USE SIGNAL ;
    PORT
      LAYER M4 ;
        RECT  0 48.528 0.192 48.552 ;
    END
  END i[479]
  PIN i[47]
    DIRECTION INPUT ;
    USE SIGNAL ;
    PORT
      LAYER M4 ;
        RECT  0 6.768 0.192 6.792 ;
    END
  END i[47]
  PIN i[480]
    DIRECTION INPUT ;
    USE SIGNAL ;
    PORT
      LAYER M4 ;
        RECT  0 48.624 0.192 48.648 ;
    END
  END i[480]
  PIN i[481]
    DIRECTION INPUT ;
    USE SIGNAL ;
    PORT
      LAYER M4 ;
        RECT  0 48.72 0.192 48.744 ;
    END
  END i[481]
  PIN i[482]
    DIRECTION INPUT ;
    USE SIGNAL ;
    PORT
      LAYER M4 ;
        RECT  0 48.816 0.192 48.84 ;
    END
  END i[482]
  PIN i[483]
    DIRECTION INPUT ;
    USE SIGNAL ;
    PORT
      LAYER M4 ;
        RECT  0 48.912 0.192 48.936 ;
    END
  END i[483]
  PIN i[484]
    DIRECTION INPUT ;
    USE SIGNAL ;
    PORT
      LAYER M4 ;
        RECT  0 49.008 0.192 49.032 ;
    END
  END i[484]
  PIN i[485]
    DIRECTION INPUT ;
    USE SIGNAL ;
    PORT
      LAYER M4 ;
        RECT  0 49.104 0.192 49.128 ;
    END
  END i[485]
  PIN i[486]
    DIRECTION INPUT ;
    USE SIGNAL ;
    PORT
      LAYER M4 ;
        RECT  0 49.248 0.192 49.272 ;
    END
  END i[486]
  PIN i[487]
    DIRECTION INPUT ;
    USE SIGNAL ;
    PORT
      LAYER M4 ;
        RECT  0 49.344 0.192 49.368 ;
    END
  END i[487]
  PIN i[488]
    DIRECTION INPUT ;
    USE SIGNAL ;
    PORT
      LAYER M4 ;
        RECT  0 49.44 0.192 49.464 ;
    END
  END i[488]
  PIN i[489]
    DIRECTION INPUT ;
    USE SIGNAL ;
    PORT
      LAYER M4 ;
        RECT  0 49.536 0.192 49.56 ;
    END
  END i[489]
  PIN i[48]
    DIRECTION INPUT ;
    USE SIGNAL ;
    PORT
      LAYER M4 ;
        RECT  0 6.864 0.192 6.888 ;
    END
  END i[48]
  PIN i[490]
    DIRECTION INPUT ;
    USE SIGNAL ;
    PORT
      LAYER M4 ;
        RECT  0 49.632 0.192 49.656 ;
    END
  END i[490]
  PIN i[491]
    DIRECTION INPUT ;
    USE SIGNAL ;
    PORT
      LAYER M4 ;
        RECT  0 49.728 0.192 49.752 ;
    END
  END i[491]
  PIN i[492]
    DIRECTION INPUT ;
    USE SIGNAL ;
    PORT
      LAYER M4 ;
        RECT  0 49.824 0.192 49.848 ;
    END
  END i[492]
  PIN i[493]
    DIRECTION INPUT ;
    USE SIGNAL ;
    PORT
      LAYER M4 ;
        RECT  0 49.92 0.192 49.944 ;
    END
  END i[493]
  PIN i[494]
    DIRECTION INPUT ;
    USE SIGNAL ;
    PORT
      LAYER M4 ;
        RECT  0 50.016 0.192 50.04 ;
    END
  END i[494]
  PIN i[495]
    DIRECTION INPUT ;
    USE SIGNAL ;
    PORT
      LAYER M4 ;
        RECT  0 50.112 0.192 50.136 ;
    END
  END i[495]
  PIN i[496]
    DIRECTION INPUT ;
    USE SIGNAL ;
    PORT
      LAYER M4 ;
        RECT  0 50.208 0.192 50.232 ;
    END
  END i[496]
  PIN i[497]
    DIRECTION INPUT ;
    USE SIGNAL ;
    PORT
      LAYER M4 ;
        RECT  0 50.304 0.192 50.328 ;
    END
  END i[497]
  PIN i[498]
    DIRECTION INPUT ;
    USE SIGNAL ;
    PORT
      LAYER M4 ;
        RECT  0 50.4 0.192 50.424 ;
    END
  END i[498]
  PIN i[499]
    DIRECTION INPUT ;
    USE SIGNAL ;
    PORT
      LAYER M4 ;
        RECT  0 50.496 0.192 50.52 ;
    END
  END i[499]
  PIN i[49]
    DIRECTION INPUT ;
    USE SIGNAL ;
    PORT
      LAYER M4 ;
        RECT  0 6.96 0.192 6.984 ;
    END
  END i[49]
  PIN i[4]
    DIRECTION INPUT ;
    USE SIGNAL ;
    PORT
      LAYER M4 ;
        RECT  0 2.592 0.192 2.616 ;
    END
  END i[4]
  PIN i[500]
    DIRECTION INPUT ;
    USE SIGNAL ;
    PORT
      LAYER M4 ;
        RECT  0 50.592 0.192 50.616 ;
    END
  END i[500]
  PIN i[501]
    DIRECTION INPUT ;
    USE SIGNAL ;
    PORT
      LAYER M4 ;
        RECT  0 50.688 0.192 50.712 ;
    END
  END i[501]
  PIN i[502]
    DIRECTION INPUT ;
    USE SIGNAL ;
    PORT
      LAYER M4 ;
        RECT  0 50.784 0.192 50.808 ;
    END
  END i[502]
  PIN i[503]
    DIRECTION INPUT ;
    USE SIGNAL ;
    PORT
      LAYER M4 ;
        RECT  0 50.88 0.192 50.904 ;
    END
  END i[503]
  PIN i[504]
    DIRECTION INPUT ;
    USE SIGNAL ;
    PORT
      LAYER M4 ;
        RECT  0 50.976 0.192 51 ;
    END
  END i[504]
  PIN i[505]
    DIRECTION INPUT ;
    USE SIGNAL ;
    PORT
      LAYER M4 ;
        RECT  0 51.072 0.192 51.096 ;
    END
  END i[505]
  PIN i[506]
    DIRECTION INPUT ;
    USE SIGNAL ;
    PORT
      LAYER M4 ;
        RECT  0 51.168 0.192 51.192 ;
    END
  END i[506]
  PIN i[507]
    DIRECTION INPUT ;
    USE SIGNAL ;
    PORT
      LAYER M4 ;
        RECT  0 51.264 0.192 51.288 ;
    END
  END i[507]
  PIN i[508]
    DIRECTION INPUT ;
    USE SIGNAL ;
    PORT
      LAYER M4 ;
        RECT  0 51.36 0.192 51.384 ;
    END
  END i[508]
  PIN i[509]
    DIRECTION INPUT ;
    USE SIGNAL ;
    PORT
      LAYER M4 ;
        RECT  0 51.456 0.192 51.48 ;
    END
  END i[509]
  PIN i[50]
    DIRECTION INPUT ;
    USE SIGNAL ;
    PORT
      LAYER M4 ;
        RECT  0 7.056 0.192 7.08 ;
    END
  END i[50]
  PIN i[510]
    DIRECTION INPUT ;
    USE SIGNAL ;
    PORT
      LAYER M4 ;
        RECT  0 51.552 0.192 51.576 ;
    END
  END i[510]
  PIN i[511]
    DIRECTION INPUT ;
    USE SIGNAL ;
    PORT
      LAYER M4 ;
        RECT  0 51.648 0.192 51.672 ;
    END
  END i[511]
  PIN i[512]
    DIRECTION INPUT ;
    USE SIGNAL ;
    PORT
      LAYER M4 ;
        RECT  0 51.744 0.192 51.768 ;
    END
  END i[512]
  PIN i[513]
    DIRECTION INPUT ;
    USE SIGNAL ;
    PORT
      LAYER M4 ;
        RECT  0 51.84 0.192 51.864 ;
    END
  END i[513]
  PIN i[514]
    DIRECTION INPUT ;
    USE SIGNAL ;
    PORT
      LAYER M4 ;
        RECT  0 51.936 0.192 51.96 ;
    END
  END i[514]
  PIN i[515]
    DIRECTION INPUT ;
    USE SIGNAL ;
    PORT
      LAYER M4 ;
        RECT  0 52.032 0.192 52.056 ;
    END
  END i[515]
  PIN i[516]
    DIRECTION INPUT ;
    USE SIGNAL ;
    PORT
      LAYER M4 ;
        RECT  0 52.128 0.192 52.152 ;
    END
  END i[516]
  PIN i[517]
    DIRECTION INPUT ;
    USE SIGNAL ;
    PORT
      LAYER M4 ;
        RECT  0 52.224 0.192 52.248 ;
    END
  END i[517]
  PIN i[518]
    DIRECTION INPUT ;
    USE SIGNAL ;
    PORT
      LAYER M4 ;
        RECT  0 52.32 0.192 52.344 ;
    END
  END i[518]
  PIN i[519]
    DIRECTION INPUT ;
    USE SIGNAL ;
    PORT
      LAYER M4 ;
        RECT  0 52.416 0.192 52.44 ;
    END
  END i[519]
  PIN i[51]
    DIRECTION INPUT ;
    USE SIGNAL ;
    PORT
      LAYER M4 ;
        RECT  0 7.152 0.192 7.176 ;
    END
  END i[51]
  PIN i[520]
    DIRECTION INPUT ;
    USE SIGNAL ;
    PORT
      LAYER M4 ;
        RECT  0 52.512 0.192 52.536 ;
    END
  END i[520]
  PIN i[521]
    DIRECTION INPUT ;
    USE SIGNAL ;
    PORT
      LAYER M4 ;
        RECT  0 52.608 0.192 52.632 ;
    END
  END i[521]
  PIN i[522]
    DIRECTION INPUT ;
    USE SIGNAL ;
    PORT
      LAYER M4 ;
        RECT  0 52.704 0.192 52.728 ;
    END
  END i[522]
  PIN i[523]
    DIRECTION INPUT ;
    USE SIGNAL ;
    PORT
      LAYER M4 ;
        RECT  0 52.8 0.192 52.824 ;
    END
  END i[523]
  PIN i[524]
    DIRECTION INPUT ;
    USE SIGNAL ;
    PORT
      LAYER M4 ;
        RECT  0 52.896 0.192 52.92 ;
    END
  END i[524]
  PIN i[525]
    DIRECTION INPUT ;
    USE SIGNAL ;
    PORT
      LAYER M4 ;
        RECT  0 52.992 0.192 53.016 ;
    END
  END i[525]
  PIN i[526]
    DIRECTION INPUT ;
    USE SIGNAL ;
    PORT
      LAYER M4 ;
        RECT  0 53.088 0.192 53.112 ;
    END
  END i[526]
  PIN i[527]
    DIRECTION INPUT ;
    USE SIGNAL ;
    PORT
      LAYER M4 ;
        RECT  0 53.184 0.192 53.208 ;
    END
  END i[527]
  PIN i[528]
    DIRECTION INPUT ;
    USE SIGNAL ;
    PORT
      LAYER M4 ;
        RECT  0 53.28 0.192 53.304 ;
    END
  END i[528]
  PIN i[529]
    DIRECTION INPUT ;
    USE SIGNAL ;
    PORT
      LAYER M4 ;
        RECT  0 53.376 0.192 53.4 ;
    END
  END i[529]
  PIN i[52]
    DIRECTION INPUT ;
    USE SIGNAL ;
    PORT
      LAYER M4 ;
        RECT  0 7.248 0.192 7.272 ;
    END
  END i[52]
  PIN i[530]
    DIRECTION INPUT ;
    USE SIGNAL ;
    PORT
      LAYER M4 ;
        RECT  0 53.472 0.192 53.496 ;
    END
  END i[530]
  PIN i[531]
    DIRECTION INPUT ;
    USE SIGNAL ;
    PORT
      LAYER M4 ;
        RECT  0 53.568 0.192 53.592 ;
    END
  END i[531]
  PIN i[532]
    DIRECTION INPUT ;
    USE SIGNAL ;
    PORT
      LAYER M4 ;
        RECT  0 53.664 0.192 53.688 ;
    END
  END i[532]
  PIN i[533]
    DIRECTION INPUT ;
    USE SIGNAL ;
    PORT
      LAYER M4 ;
        RECT  0 53.76 0.192 53.784 ;
    END
  END i[533]
  PIN i[534]
    DIRECTION INPUT ;
    USE SIGNAL ;
    PORT
      LAYER M4 ;
        RECT  0 53.856 0.192 53.88 ;
    END
  END i[534]
  PIN i[535]
    DIRECTION INPUT ;
    USE SIGNAL ;
    PORT
      LAYER M4 ;
        RECT  0 53.952 0.192 53.976 ;
    END
  END i[535]
  PIN i[53]
    DIRECTION INPUT ;
    USE SIGNAL ;
    PORT
      LAYER M4 ;
        RECT  0 7.344 0.192 7.368 ;
    END
  END i[53]
  PIN i[54]
    DIRECTION INPUT ;
    USE SIGNAL ;
    PORT
      LAYER M4 ;
        RECT  0 7.44 0.192 7.464 ;
    END
  END i[54]
  PIN i[55]
    DIRECTION INPUT ;
    USE SIGNAL ;
    PORT
      LAYER M4 ;
        RECT  0 7.536 0.192 7.56 ;
    END
  END i[55]
  PIN i[56]
    DIRECTION INPUT ;
    USE SIGNAL ;
    PORT
      LAYER M4 ;
        RECT  0 7.632 0.192 7.656 ;
    END
  END i[56]
  PIN i[57]
    DIRECTION INPUT ;
    USE SIGNAL ;
    PORT
      LAYER M4 ;
        RECT  0 7.728 0.192 7.752 ;
    END
  END i[57]
  PIN i[58]
    DIRECTION INPUT ;
    USE SIGNAL ;
    PORT
      LAYER M4 ;
        RECT  0 7.824 0.192 7.848 ;
    END
  END i[58]
  PIN i[59]
    DIRECTION INPUT ;
    USE SIGNAL ;
    PORT
      LAYER M4 ;
        RECT  0 7.92 0.192 7.944 ;
    END
  END i[59]
  PIN i[5]
    DIRECTION INPUT ;
    USE SIGNAL ;
    PORT
      LAYER M4 ;
        RECT  0 2.688 0.192 2.712 ;
    END
  END i[5]
  PIN i[60]
    DIRECTION INPUT ;
    USE SIGNAL ;
    PORT
      LAYER M4 ;
        RECT  0 8.016 0.192 8.04 ;
    END
  END i[60]
  PIN i[61]
    DIRECTION INPUT ;
    USE SIGNAL ;
    PORT
      LAYER M4 ;
        RECT  0 8.112 0.192 8.136 ;
    END
  END i[61]
  PIN i[62]
    DIRECTION INPUT ;
    USE SIGNAL ;
    PORT
      LAYER M4 ;
        RECT  0 8.208 0.192 8.232 ;
    END
  END i[62]
  PIN i[63]
    DIRECTION INPUT ;
    USE SIGNAL ;
    PORT
      LAYER M4 ;
        RECT  0 8.304 0.192 8.328 ;
    END
  END i[63]
  PIN i[64]
    DIRECTION INPUT ;
    USE SIGNAL ;
    PORT
      LAYER M4 ;
        RECT  0 8.4 0.192 8.424 ;
    END
  END i[64]
  PIN i[65]
    DIRECTION INPUT ;
    USE SIGNAL ;
    PORT
      LAYER M4 ;
        RECT  0 8.496 0.192 8.52 ;
    END
  END i[65]
  PIN i[66]
    DIRECTION INPUT ;
    USE SIGNAL ;
    PORT
      LAYER M4 ;
        RECT  0 8.592 0.192 8.616 ;
    END
  END i[66]
  PIN i[67]
    DIRECTION INPUT ;
    USE SIGNAL ;
    PORT
      LAYER M4 ;
        RECT  0 8.688 0.192 8.712 ;
    END
  END i[67]
  PIN i[68]
    DIRECTION INPUT ;
    USE SIGNAL ;
    PORT
      LAYER M4 ;
        RECT  0 8.784 0.192 8.808 ;
    END
  END i[68]
  PIN i[69]
    DIRECTION INPUT ;
    USE SIGNAL ;
    PORT
      LAYER M4 ;
        RECT  0 8.88 0.192 8.904 ;
    END
  END i[69]
  PIN i[6]
    DIRECTION INPUT ;
    USE SIGNAL ;
    PORT
      LAYER M4 ;
        RECT  0 2.784 0.192 2.808 ;
    END
  END i[6]
  PIN i[70]
    DIRECTION INPUT ;
    USE SIGNAL ;
    PORT
      LAYER M4 ;
        RECT  0 8.976 0.192 9 ;
    END
  END i[70]
  PIN i[71]
    DIRECTION INPUT ;
    USE SIGNAL ;
    PORT
      LAYER M4 ;
        RECT  0 9.072 0.192 9.096 ;
    END
  END i[71]
  PIN i[72]
    DIRECTION INPUT ;
    USE SIGNAL ;
    PORT
      LAYER M4 ;
        RECT  0 9.168 0.192 9.192 ;
    END
  END i[72]
  PIN i[73]
    DIRECTION INPUT ;
    USE SIGNAL ;
    PORT
      LAYER M4 ;
        RECT  0 9.264 0.192 9.288 ;
    END
  END i[73]
  PIN i[74]
    DIRECTION INPUT ;
    USE SIGNAL ;
    PORT
      LAYER M4 ;
        RECT  0 9.36 0.192 9.384 ;
    END
  END i[74]
  PIN i[75]
    DIRECTION INPUT ;
    USE SIGNAL ;
    PORT
      LAYER M4 ;
        RECT  0 9.456 0.192 9.48 ;
    END
  END i[75]
  PIN i[76]
    DIRECTION INPUT ;
    USE SIGNAL ;
    PORT
      LAYER M4 ;
        RECT  0 9.552 0.192 9.576 ;
    END
  END i[76]
  PIN i[77]
    DIRECTION INPUT ;
    USE SIGNAL ;
    PORT
      LAYER M4 ;
        RECT  0 9.648 0.192 9.672 ;
    END
  END i[77]
  PIN i[78]
    DIRECTION INPUT ;
    USE SIGNAL ;
    PORT
      LAYER M4 ;
        RECT  0 9.744 0.192 9.768 ;
    END
  END i[78]
  PIN i[79]
    DIRECTION INPUT ;
    USE SIGNAL ;
    PORT
      LAYER M4 ;
        RECT  0 9.84 0.192 9.864 ;
    END
  END i[79]
  PIN i[7]
    DIRECTION INPUT ;
    USE SIGNAL ;
    PORT
      LAYER M4 ;
        RECT  0 2.88 0.192 2.904 ;
    END
  END i[7]
  PIN i[80]
    DIRECTION INPUT ;
    USE SIGNAL ;
    PORT
      LAYER M4 ;
        RECT  0 9.936 0.192 9.96 ;
    END
  END i[80]
  PIN i[81]
    DIRECTION INPUT ;
    USE SIGNAL ;
    PORT
      LAYER M4 ;
        RECT  0 10.032 0.192 10.056 ;
    END
  END i[81]
  PIN i[82]
    DIRECTION INPUT ;
    USE SIGNAL ;
    PORT
      LAYER M4 ;
        RECT  0 10.128 0.192 10.152 ;
    END
  END i[82]
  PIN i[83]
    DIRECTION INPUT ;
    USE SIGNAL ;
    PORT
      LAYER M4 ;
        RECT  0 10.224 0.192 10.248 ;
    END
  END i[83]
  PIN i[84]
    DIRECTION INPUT ;
    USE SIGNAL ;
    PORT
      LAYER M4 ;
        RECT  0 10.368 0.192 10.392 ;
    END
  END i[84]
  PIN i[85]
    DIRECTION INPUT ;
    USE SIGNAL ;
    PORT
      LAYER M4 ;
        RECT  0 10.464 0.192 10.488 ;
    END
  END i[85]
  PIN i[86]
    DIRECTION INPUT ;
    USE SIGNAL ;
    PORT
      LAYER M4 ;
        RECT  0 10.56 0.192 10.584 ;
    END
  END i[86]
  PIN i[87]
    DIRECTION INPUT ;
    USE SIGNAL ;
    PORT
      LAYER M4 ;
        RECT  0 10.656 0.192 10.68 ;
    END
  END i[87]
  PIN i[88]
    DIRECTION INPUT ;
    USE SIGNAL ;
    PORT
      LAYER M4 ;
        RECT  0 10.752 0.192 10.776 ;
    END
  END i[88]
  PIN i[89]
    DIRECTION INPUT ;
    USE SIGNAL ;
    PORT
      LAYER M4 ;
        RECT  0 10.848 0.192 10.872 ;
    END
  END i[89]
  PIN i[8]
    DIRECTION INPUT ;
    USE SIGNAL ;
    PORT
      LAYER M4 ;
        RECT  0 2.976 0.192 3 ;
    END
  END i[8]
  PIN i[90]
    DIRECTION INPUT ;
    USE SIGNAL ;
    PORT
      LAYER M4 ;
        RECT  0 10.944 0.192 10.968 ;
    END
  END i[90]
  PIN i[91]
    DIRECTION INPUT ;
    USE SIGNAL ;
    PORT
      LAYER M4 ;
        RECT  0 11.04 0.192 11.064 ;
    END
  END i[91]
  PIN i[92]
    DIRECTION INPUT ;
    USE SIGNAL ;
    PORT
      LAYER M4 ;
        RECT  0 11.136 0.192 11.16 ;
    END
  END i[92]
  PIN i[93]
    DIRECTION INPUT ;
    USE SIGNAL ;
    PORT
      LAYER M4 ;
        RECT  0 11.232 0.192 11.256 ;
    END
  END i[93]
  PIN i[94]
    DIRECTION INPUT ;
    USE SIGNAL ;
    PORT
      LAYER M4 ;
        RECT  0 11.328 0.192 11.352 ;
    END
  END i[94]
  PIN i[95]
    DIRECTION INPUT ;
    USE SIGNAL ;
    PORT
      LAYER M4 ;
        RECT  0 11.424 0.192 11.448 ;
    END
  END i[95]
  PIN i[96]
    DIRECTION INPUT ;
    USE SIGNAL ;
    PORT
      LAYER M4 ;
        RECT  0 11.52 0.192 11.544 ;
    END
  END i[96]
  PIN i[97]
    DIRECTION INPUT ;
    USE SIGNAL ;
    PORT
      LAYER M4 ;
        RECT  0 11.616 0.192 11.64 ;
    END
  END i[97]
  PIN i[98]
    DIRECTION INPUT ;
    USE SIGNAL ;
    PORT
      LAYER M4 ;
        RECT  0 11.712 0.192 11.736 ;
    END
  END i[98]
  PIN i[99]
    DIRECTION INPUT ;
    USE SIGNAL ;
    PORT
      LAYER M4 ;
        RECT  0 11.808 0.192 11.832 ;
    END
  END i[99]
  PIN i[9]
    DIRECTION INPUT ;
    USE SIGNAL ;
    PORT
      LAYER M4 ;
        RECT  0 3.072 0.192 3.096 ;
    END
  END i[9]
  PIN o[0]
    DIRECTION OUTPUT ;
    USE SIGNAL ;
    PORT
      LAYER M3 ;
        RECT  2.196 0 2.214 0.144 ;
    END
  END o[0]
  PIN o[100]
    DIRECTION OUTPUT ;
    USE SIGNAL ;
    PORT
      LAYER M3 ;
        RECT  11.88 0 11.898 0.144 ;
    END
  END o[100]
  PIN o[101]
    DIRECTION OUTPUT ;
    USE SIGNAL ;
    PORT
      LAYER M5 ;
        RECT  11.952 0 11.976 0.192 ;
    END
  END o[101]
  PIN o[102]
    DIRECTION OUTPUT ;
    USE SIGNAL ;
    PORT
      LAYER M3 ;
        RECT  12.06 0 12.078 0.144 ;
    END
  END o[102]
  PIN o[103]
    DIRECTION OUTPUT ;
    USE SIGNAL ;
    PORT
      LAYER M5 ;
        RECT  12.144 0 12.168 0.192 ;
    END
  END o[103]
  PIN o[104]
    DIRECTION OUTPUT ;
    USE SIGNAL ;
    PORT
      LAYER M3 ;
        RECT  12.24 0 12.258 0.144 ;
    END
  END o[104]
  PIN o[105]
    DIRECTION OUTPUT ;
    USE SIGNAL ;
    PORT
      LAYER M5 ;
        RECT  12.336 0 12.36 0.192 ;
    END
  END o[105]
  PIN o[106]
    DIRECTION OUTPUT ;
    USE SIGNAL ;
    PORT
      LAYER M3 ;
        RECT  12.456 0 12.474 0.144 ;
    END
  END o[106]
  PIN o[107]
    DIRECTION OUTPUT ;
    USE SIGNAL ;
    PORT
      LAYER M5 ;
        RECT  12.528 0 12.552 0.192 ;
    END
  END o[107]
  PIN o[108]
    DIRECTION OUTPUT ;
    USE SIGNAL ;
    PORT
      LAYER M3 ;
        RECT  12.636 0 12.654 0.144 ;
    END
  END o[108]
  PIN o[109]
    DIRECTION OUTPUT ;
    USE SIGNAL ;
    PORT
      LAYER M5 ;
        RECT  12.72 0 12.744 0.192 ;
    END
  END o[109]
  PIN o[10]
    DIRECTION OUTPUT ;
    USE SIGNAL ;
    PORT
      LAYER M3 ;
        RECT  3.168 0 3.186 0.144 ;
    END
  END o[10]
  PIN o[110]
    DIRECTION OUTPUT ;
    USE SIGNAL ;
    PORT
      LAYER M3 ;
        RECT  12.852 0 12.87 0.144 ;
    END
  END o[110]
  PIN o[111]
    DIRECTION OUTPUT ;
    USE SIGNAL ;
    PORT
      LAYER M5 ;
        RECT  12.912 0 12.936 0.192 ;
    END
  END o[111]
  PIN o[112]
    DIRECTION OUTPUT ;
    USE SIGNAL ;
    PORT
      LAYER M3 ;
        RECT  13.032 0 13.05 0.144 ;
    END
  END o[112]
  PIN o[113]
    DIRECTION OUTPUT ;
    USE SIGNAL ;
    PORT
      LAYER M5 ;
        RECT  13.104 0 13.128 0.192 ;
    END
  END o[113]
  PIN o[114]
    DIRECTION OUTPUT ;
    USE SIGNAL ;
    PORT
      LAYER M3 ;
        RECT  13.212 0 13.23 0.144 ;
    END
  END o[114]
  PIN o[115]
    DIRECTION OUTPUT ;
    USE SIGNAL ;
    PORT
      LAYER M5 ;
        RECT  13.296 0 13.32 0.192 ;
    END
  END o[115]
  PIN o[116]
    DIRECTION OUTPUT ;
    USE SIGNAL ;
    PORT
      LAYER M3 ;
        RECT  13.428 0 13.446 0.144 ;
    END
  END o[116]
  PIN o[117]
    DIRECTION OUTPUT ;
    USE SIGNAL ;
    PORT
      LAYER M5 ;
        RECT  13.536 0 13.56 0.192 ;
    END
  END o[117]
  PIN o[118]
    DIRECTION OUTPUT ;
    USE SIGNAL ;
    PORT
      LAYER M3 ;
        RECT  13.608 0 13.626 0.144 ;
    END
  END o[118]
  PIN o[119]
    DIRECTION OUTPUT ;
    USE SIGNAL ;
    PORT
      LAYER M5 ;
        RECT  13.728 0 13.752 0.192 ;
    END
  END o[119]
  PIN o[11]
    DIRECTION OUTPUT ;
    USE SIGNAL ;
    PORT
      LAYER M5 ;
        RECT  3.264 0 3.288 0.192 ;
    END
  END o[11]
  PIN o[120]
    DIRECTION OUTPUT ;
    USE SIGNAL ;
    PORT
      LAYER M3 ;
        RECT  13.788 0 13.806 0.144 ;
    END
  END o[120]
  PIN o[121]
    DIRECTION OUTPUT ;
    USE SIGNAL ;
    PORT
      LAYER M5 ;
        RECT  13.92 0 13.944 0.192 ;
    END
  END o[121]
  PIN o[122]
    DIRECTION OUTPUT ;
    USE SIGNAL ;
    PORT
      LAYER M3 ;
        RECT  14.004 0 14.022 0.144 ;
    END
  END o[122]
  PIN o[123]
    DIRECTION OUTPUT ;
    USE SIGNAL ;
    PORT
      LAYER M5 ;
        RECT  14.112 0 14.136 0.192 ;
    END
  END o[123]
  PIN o[124]
    DIRECTION OUTPUT ;
    USE SIGNAL ;
    PORT
      LAYER M3 ;
        RECT  14.184 0 14.202 0.144 ;
    END
  END o[124]
  PIN o[125]
    DIRECTION OUTPUT ;
    USE SIGNAL ;
    PORT
      LAYER M5 ;
        RECT  14.304 0 14.328 0.192 ;
    END
  END o[125]
  PIN o[126]
    DIRECTION OUTPUT ;
    USE SIGNAL ;
    PORT
      LAYER M3 ;
        RECT  14.4 0 14.418 0.144 ;
    END
  END o[126]
  PIN o[127]
    DIRECTION OUTPUT ;
    USE SIGNAL ;
    PORT
      LAYER M5 ;
        RECT  14.496 0 14.52 0.192 ;
    END
  END o[127]
  PIN o[128]
    DIRECTION OUTPUT ;
    USE SIGNAL ;
    PORT
      LAYER M3 ;
        RECT  14.58 0 14.598 0.144 ;
    END
  END o[128]
  PIN o[129]
    DIRECTION OUTPUT ;
    USE SIGNAL ;
    PORT
      LAYER M5 ;
        RECT  14.688 0 14.712 0.192 ;
    END
  END o[129]
  PIN o[12]
    DIRECTION OUTPUT ;
    USE SIGNAL ;
    PORT
      LAYER M3 ;
        RECT  3.348 0 3.366 0.144 ;
    END
  END o[12]
  PIN o[130]
    DIRECTION OUTPUT ;
    USE SIGNAL ;
    PORT
      LAYER M3 ;
        RECT  14.76 0 14.778 0.144 ;
    END
  END o[130]
  PIN o[131]
    DIRECTION OUTPUT ;
    USE SIGNAL ;
    PORT
      LAYER M5 ;
        RECT  14.88 0 14.904 0.192 ;
    END
  END o[131]
  PIN o[132]
    DIRECTION OUTPUT ;
    USE SIGNAL ;
    PORT
      LAYER M3 ;
        RECT  14.976 0 14.994 0.144 ;
    END
  END o[132]
  PIN o[133]
    DIRECTION OUTPUT ;
    USE SIGNAL ;
    PORT
      LAYER M5 ;
        RECT  15.072 0 15.096 0.192 ;
    END
  END o[133]
  PIN o[134]
    DIRECTION OUTPUT ;
    USE SIGNAL ;
    PORT
      LAYER M3 ;
        RECT  15.156 0 15.174 0.144 ;
    END
  END o[134]
  PIN o[135]
    DIRECTION OUTPUT ;
    USE SIGNAL ;
    PORT
      LAYER M5 ;
        RECT  15.264 0 15.288 0.192 ;
    END
  END o[135]
  PIN o[136]
    DIRECTION OUTPUT ;
    USE SIGNAL ;
    PORT
      LAYER M3 ;
        RECT  15.336 0 15.354 0.144 ;
    END
  END o[136]
  PIN o[137]
    DIRECTION OUTPUT ;
    USE SIGNAL ;
    PORT
      LAYER M5 ;
        RECT  15.456 0 15.48 0.192 ;
    END
  END o[137]
  PIN o[138]
    DIRECTION OUTPUT ;
    USE SIGNAL ;
    PORT
      LAYER M3 ;
        RECT  15.552 0 15.57 0.144 ;
    END
  END o[138]
  PIN o[139]
    DIRECTION OUTPUT ;
    USE SIGNAL ;
    PORT
      LAYER M5 ;
        RECT  15.648 0 15.672 0.192 ;
    END
  END o[139]
  PIN o[13]
    DIRECTION OUTPUT ;
    USE SIGNAL ;
    PORT
      LAYER M5 ;
        RECT  3.456 0 3.48 0.192 ;
    END
  END o[13]
  PIN o[140]
    DIRECTION OUTPUT ;
    USE SIGNAL ;
    PORT
      LAYER M3 ;
        RECT  15.732 0 15.75 0.144 ;
    END
  END o[140]
  PIN o[141]
    DIRECTION OUTPUT ;
    USE SIGNAL ;
    PORT
      LAYER M5 ;
        RECT  15.84 0 15.864 0.192 ;
    END
  END o[141]
  PIN o[142]
    DIRECTION OUTPUT ;
    USE SIGNAL ;
    PORT
      LAYER M3 ;
        RECT  15.948 0 15.966 0.144 ;
    END
  END o[142]
  PIN o[143]
    DIRECTION OUTPUT ;
    USE SIGNAL ;
    PORT
      LAYER M5 ;
        RECT  16.032 0 16.056 0.192 ;
    END
  END o[143]
  PIN o[144]
    DIRECTION OUTPUT ;
    USE SIGNAL ;
    PORT
      LAYER M3 ;
        RECT  16.128 0 16.146 0.144 ;
    END
  END o[144]
  PIN o[145]
    DIRECTION OUTPUT ;
    USE SIGNAL ;
    PORT
      LAYER M5 ;
        RECT  16.224 0 16.248 0.192 ;
    END
  END o[145]
  PIN o[146]
    DIRECTION OUTPUT ;
    USE SIGNAL ;
    PORT
      LAYER M3 ;
        RECT  16.308 0 16.326 0.144 ;
    END
  END o[146]
  PIN o[147]
    DIRECTION OUTPUT ;
    USE SIGNAL ;
    PORT
      LAYER M5 ;
        RECT  16.416 0 16.44 0.192 ;
    END
  END o[147]
  PIN o[148]
    DIRECTION OUTPUT ;
    USE SIGNAL ;
    PORT
      LAYER M3 ;
        RECT  16.524 0 16.542 0.144 ;
    END
  END o[148]
  PIN o[149]
    DIRECTION OUTPUT ;
    USE SIGNAL ;
    PORT
      LAYER M5 ;
        RECT  16.608 0 16.632 0.192 ;
    END
  END o[149]
  PIN o[14]
    DIRECTION OUTPUT ;
    USE SIGNAL ;
    PORT
      LAYER M3 ;
        RECT  3.564 0 3.582 0.144 ;
    END
  END o[14]
  PIN o[150]
    DIRECTION OUTPUT ;
    USE SIGNAL ;
    PORT
      LAYER M3 ;
        RECT  16.704 0 16.722 0.144 ;
    END
  END o[150]
  PIN o[151]
    DIRECTION OUTPUT ;
    USE SIGNAL ;
    PORT
      LAYER M5 ;
        RECT  16.8 0 16.824 0.192 ;
    END
  END o[151]
  PIN o[152]
    DIRECTION OUTPUT ;
    USE SIGNAL ;
    PORT
      LAYER M3 ;
        RECT  16.884 0 16.902 0.144 ;
    END
  END o[152]
  PIN o[153]
    DIRECTION OUTPUT ;
    USE SIGNAL ;
    PORT
      LAYER M5 ;
        RECT  16.992 0 17.016 0.192 ;
    END
  END o[153]
  PIN o[154]
    DIRECTION OUTPUT ;
    USE SIGNAL ;
    PORT
      LAYER M3 ;
        RECT  17.1 0 17.118 0.144 ;
    END
  END o[154]
  PIN o[155]
    DIRECTION OUTPUT ;
    USE SIGNAL ;
    PORT
      LAYER M5 ;
        RECT  17.184 0 17.208 0.192 ;
    END
  END o[155]
  PIN o[156]
    DIRECTION OUTPUT ;
    USE SIGNAL ;
    PORT
      LAYER M3 ;
        RECT  17.28 0 17.298 0.144 ;
    END
  END o[156]
  PIN o[157]
    DIRECTION OUTPUT ;
    USE SIGNAL ;
    PORT
      LAYER M5 ;
        RECT  17.376 0 17.4 0.192 ;
    END
  END o[157]
  PIN o[158]
    DIRECTION OUTPUT ;
    USE SIGNAL ;
    PORT
      LAYER M3 ;
        RECT  17.496 0 17.514 0.144 ;
    END
  END o[158]
  PIN o[159]
    DIRECTION OUTPUT ;
    USE SIGNAL ;
    PORT
      LAYER M5 ;
        RECT  17.568 0 17.592 0.192 ;
    END
  END o[159]
  PIN o[15]
    DIRECTION OUTPUT ;
    USE SIGNAL ;
    PORT
      LAYER M5 ;
        RECT  3.648 0 3.672 0.192 ;
    END
  END o[15]
  PIN o[160]
    DIRECTION OUTPUT ;
    USE SIGNAL ;
    PORT
      LAYER M3 ;
        RECT  17.676 0 17.694 0.144 ;
    END
  END o[160]
  PIN o[161]
    DIRECTION OUTPUT ;
    USE SIGNAL ;
    PORT
      LAYER M5 ;
        RECT  17.76 0 17.784 0.192 ;
    END
  END o[161]
  PIN o[162]
    DIRECTION OUTPUT ;
    USE SIGNAL ;
    PORT
      LAYER M3 ;
        RECT  17.856 0 17.874 0.144 ;
    END
  END o[162]
  PIN o[163]
    DIRECTION OUTPUT ;
    USE SIGNAL ;
    PORT
      LAYER M5 ;
        RECT  17.952 0 17.976 0.192 ;
    END
  END o[163]
  PIN o[164]
    DIRECTION OUTPUT ;
    USE SIGNAL ;
    PORT
      LAYER M3 ;
        RECT  18.072 0 18.09 0.144 ;
    END
  END o[164]
  PIN o[165]
    DIRECTION OUTPUT ;
    USE SIGNAL ;
    PORT
      LAYER M5 ;
        RECT  18.144 0 18.168 0.192 ;
    END
  END o[165]
  PIN o[166]
    DIRECTION OUTPUT ;
    USE SIGNAL ;
    PORT
      LAYER M3 ;
        RECT  18.252 0 18.27 0.144 ;
    END
  END o[166]
  PIN o[167]
    DIRECTION OUTPUT ;
    USE SIGNAL ;
    PORT
      LAYER M5 ;
        RECT  18.336 0 18.36 0.192 ;
    END
  END o[167]
  PIN o[168]
    DIRECTION OUTPUT ;
    USE SIGNAL ;
    PORT
      LAYER M3 ;
        RECT  18.432 0 18.45 0.144 ;
    END
  END o[168]
  PIN o[169]
    DIRECTION OUTPUT ;
    USE SIGNAL ;
    PORT
      LAYER M5 ;
        RECT  18.528 0 18.552 0.192 ;
    END
  END o[169]
  PIN o[16]
    DIRECTION OUTPUT ;
    USE SIGNAL ;
    PORT
      LAYER M3 ;
        RECT  3.744 0 3.762 0.144 ;
    END
  END o[16]
  PIN o[170]
    DIRECTION OUTPUT ;
    USE SIGNAL ;
    PORT
      LAYER M3 ;
        RECT  18.648 0 18.666 0.144 ;
    END
  END o[170]
  PIN o[171]
    DIRECTION OUTPUT ;
    USE SIGNAL ;
    PORT
      LAYER M5 ;
        RECT  18.72 0 18.744 0.192 ;
    END
  END o[171]
  PIN o[172]
    DIRECTION OUTPUT ;
    USE SIGNAL ;
    PORT
      LAYER M3 ;
        RECT  18.828 0 18.846 0.144 ;
    END
  END o[172]
  PIN o[173]
    DIRECTION OUTPUT ;
    USE SIGNAL ;
    PORT
      LAYER M5 ;
        RECT  18.912 0 18.936 0.192 ;
    END
  END o[173]
  PIN o[174]
    DIRECTION OUTPUT ;
    USE SIGNAL ;
    PORT
      LAYER M3 ;
        RECT  19.044 0 19.062 0.144 ;
    END
  END o[174]
  PIN o[175]
    DIRECTION OUTPUT ;
    USE SIGNAL ;
    PORT
      LAYER M5 ;
        RECT  19.104 0 19.128 0.192 ;
    END
  END o[175]
  PIN o[176]
    DIRECTION OUTPUT ;
    USE SIGNAL ;
    PORT
      LAYER M3 ;
        RECT  19.224 0 19.242 0.144 ;
    END
  END o[176]
  PIN o[177]
    DIRECTION OUTPUT ;
    USE SIGNAL ;
    PORT
      LAYER M5 ;
        RECT  19.296 0 19.32 0.192 ;
    END
  END o[177]
  PIN o[178]
    DIRECTION OUTPUT ;
    USE SIGNAL ;
    PORT
      LAYER M3 ;
        RECT  19.404 0 19.422 0.144 ;
    END
  END o[178]
  PIN o[179]
    DIRECTION OUTPUT ;
    USE SIGNAL ;
    PORT
      LAYER M5 ;
        RECT  19.488 0 19.512 0.192 ;
    END
  END o[179]
  PIN o[17]
    DIRECTION OUTPUT ;
    USE SIGNAL ;
    PORT
      LAYER M5 ;
        RECT  3.84 0 3.864 0.192 ;
    END
  END o[17]
  PIN o[180]
    DIRECTION OUTPUT ;
    USE SIGNAL ;
    PORT
      LAYER M3 ;
        RECT  19.62 0 19.638 0.144 ;
    END
  END o[180]
  PIN o[181]
    DIRECTION OUTPUT ;
    USE SIGNAL ;
    PORT
      LAYER M5 ;
        RECT  19.68 0 19.704 0.192 ;
    END
  END o[181]
  PIN o[182]
    DIRECTION OUTPUT ;
    USE SIGNAL ;
    PORT
      LAYER M3 ;
        RECT  19.8 0 19.818 0.144 ;
    END
  END o[182]
  PIN o[183]
    DIRECTION OUTPUT ;
    USE SIGNAL ;
    PORT
      LAYER M5 ;
        RECT  19.872 0 19.896 0.192 ;
    END
  END o[183]
  PIN o[184]
    DIRECTION OUTPUT ;
    USE SIGNAL ;
    PORT
      LAYER M3 ;
        RECT  19.98 0 19.998 0.144 ;
    END
  END o[184]
  PIN o[185]
    DIRECTION OUTPUT ;
    USE SIGNAL ;
    PORT
      LAYER M5 ;
        RECT  20.112 0 20.136 0.192 ;
    END
  END o[185]
  PIN o[186]
    DIRECTION OUTPUT ;
    USE SIGNAL ;
    PORT
      LAYER M3 ;
        RECT  20.196 0 20.214 0.144 ;
    END
  END o[186]
  PIN o[187]
    DIRECTION OUTPUT ;
    USE SIGNAL ;
    PORT
      LAYER M5 ;
        RECT  20.304 0 20.328 0.192 ;
    END
  END o[187]
  PIN o[188]
    DIRECTION OUTPUT ;
    USE SIGNAL ;
    PORT
      LAYER M3 ;
        RECT  20.376 0 20.394 0.144 ;
    END
  END o[188]
  PIN o[189]
    DIRECTION OUTPUT ;
    USE SIGNAL ;
    PORT
      LAYER M5 ;
        RECT  20.496 0 20.52 0.192 ;
    END
  END o[189]
  PIN o[18]
    DIRECTION OUTPUT ;
    USE SIGNAL ;
    PORT
      LAYER M3 ;
        RECT  3.924 0 3.942 0.144 ;
    END
  END o[18]
  PIN o[190]
    DIRECTION OUTPUT ;
    USE SIGNAL ;
    PORT
      LAYER M3 ;
        RECT  20.592 0 20.61 0.144 ;
    END
  END o[190]
  PIN o[191]
    DIRECTION OUTPUT ;
    USE SIGNAL ;
    PORT
      LAYER M5 ;
        RECT  20.688 0 20.712 0.192 ;
    END
  END o[191]
  PIN o[192]
    DIRECTION OUTPUT ;
    USE SIGNAL ;
    PORT
      LAYER M3 ;
        RECT  20.772 0 20.79 0.144 ;
    END
  END o[192]
  PIN o[193]
    DIRECTION OUTPUT ;
    USE SIGNAL ;
    PORT
      LAYER M5 ;
        RECT  20.88 0 20.904 0.192 ;
    END
  END o[193]
  PIN o[194]
    DIRECTION OUTPUT ;
    USE SIGNAL ;
    PORT
      LAYER M3 ;
        RECT  20.952 0 20.97 0.144 ;
    END
  END o[194]
  PIN o[195]
    DIRECTION OUTPUT ;
    USE SIGNAL ;
    PORT
      LAYER M5 ;
        RECT  21.072 0 21.096 0.192 ;
    END
  END o[195]
  PIN o[196]
    DIRECTION OUTPUT ;
    USE SIGNAL ;
    PORT
      LAYER M3 ;
        RECT  21.168 0 21.186 0.144 ;
    END
  END o[196]
  PIN o[197]
    DIRECTION OUTPUT ;
    USE SIGNAL ;
    PORT
      LAYER M5 ;
        RECT  21.264 0 21.288 0.192 ;
    END
  END o[197]
  PIN o[198]
    DIRECTION OUTPUT ;
    USE SIGNAL ;
    PORT
      LAYER M3 ;
        RECT  21.348 0 21.366 0.144 ;
    END
  END o[198]
  PIN o[199]
    DIRECTION OUTPUT ;
    USE SIGNAL ;
    PORT
      LAYER M5 ;
        RECT  21.456 0 21.48 0.192 ;
    END
  END o[199]
  PIN o[19]
    DIRECTION OUTPUT ;
    USE SIGNAL ;
    PORT
      LAYER M5 ;
        RECT  4.032 0 4.056 0.192 ;
    END
  END o[19]
  PIN o[1]
    DIRECTION OUTPUT ;
    USE SIGNAL ;
    PORT
      LAYER M5 ;
        RECT  2.304 0 2.328 0.192 ;
    END
  END o[1]
  PIN o[200]
    DIRECTION OUTPUT ;
    USE SIGNAL ;
    PORT
      LAYER M3 ;
        RECT  21.528 0 21.546 0.144 ;
    END
  END o[200]
  PIN o[201]
    DIRECTION OUTPUT ;
    USE SIGNAL ;
    PORT
      LAYER M5 ;
        RECT  21.648 0 21.672 0.192 ;
    END
  END o[201]
  PIN o[202]
    DIRECTION OUTPUT ;
    USE SIGNAL ;
    PORT
      LAYER M3 ;
        RECT  21.744 0 21.762 0.144 ;
    END
  END o[202]
  PIN o[203]
    DIRECTION OUTPUT ;
    USE SIGNAL ;
    PORT
      LAYER M5 ;
        RECT  21.84 0 21.864 0.192 ;
    END
  END o[203]
  PIN o[204]
    DIRECTION OUTPUT ;
    USE SIGNAL ;
    PORT
      LAYER M3 ;
        RECT  21.924 0 21.942 0.144 ;
    END
  END o[204]
  PIN o[205]
    DIRECTION OUTPUT ;
    USE SIGNAL ;
    PORT
      LAYER M5 ;
        RECT  22.032 0 22.056 0.192 ;
    END
  END o[205]
  PIN o[206]
    DIRECTION OUTPUT ;
    USE SIGNAL ;
    PORT
      LAYER M3 ;
        RECT  22.14 0 22.158 0.144 ;
    END
  END o[206]
  PIN o[207]
    DIRECTION OUTPUT ;
    USE SIGNAL ;
    PORT
      LAYER M5 ;
        RECT  22.224 0 22.248 0.192 ;
    END
  END o[207]
  PIN o[208]
    DIRECTION OUTPUT ;
    USE SIGNAL ;
    PORT
      LAYER M3 ;
        RECT  22.32 0 22.338 0.144 ;
    END
  END o[208]
  PIN o[209]
    DIRECTION OUTPUT ;
    USE SIGNAL ;
    PORT
      LAYER M5 ;
        RECT  22.416 0 22.44 0.192 ;
    END
  END o[209]
  PIN o[20]
    DIRECTION OUTPUT ;
    USE SIGNAL ;
    PORT
      LAYER M3 ;
        RECT  4.14 0 4.158 0.144 ;
    END
  END o[20]
  PIN o[210]
    DIRECTION OUTPUT ;
    USE SIGNAL ;
    PORT
      LAYER M3 ;
        RECT  22.5 0 22.518 0.144 ;
    END
  END o[210]
  PIN o[211]
    DIRECTION OUTPUT ;
    USE SIGNAL ;
    PORT
      LAYER M5 ;
        RECT  22.608 0 22.632 0.192 ;
    END
  END o[211]
  PIN o[212]
    DIRECTION OUTPUT ;
    USE SIGNAL ;
    PORT
      LAYER M3 ;
        RECT  22.716 0 22.734 0.144 ;
    END
  END o[212]
  PIN o[213]
    DIRECTION OUTPUT ;
    USE SIGNAL ;
    PORT
      LAYER M5 ;
        RECT  22.8 0 22.824 0.192 ;
    END
  END o[213]
  PIN o[214]
    DIRECTION OUTPUT ;
    USE SIGNAL ;
    PORT
      LAYER M3 ;
        RECT  22.896 0 22.914 0.144 ;
    END
  END o[214]
  PIN o[215]
    DIRECTION OUTPUT ;
    USE SIGNAL ;
    PORT
      LAYER M5 ;
        RECT  22.992 0 23.016 0.192 ;
    END
  END o[215]
  PIN o[216]
    DIRECTION OUTPUT ;
    USE SIGNAL ;
    PORT
      LAYER M3 ;
        RECT  23.076 0 23.094 0.144 ;
    END
  END o[216]
  PIN o[217]
    DIRECTION OUTPUT ;
    USE SIGNAL ;
    PORT
      LAYER M5 ;
        RECT  23.184 0 23.208 0.192 ;
    END
  END o[217]
  PIN o[218]
    DIRECTION OUTPUT ;
    USE SIGNAL ;
    PORT
      LAYER M3 ;
        RECT  23.292 0 23.31 0.144 ;
    END
  END o[218]
  PIN o[219]
    DIRECTION OUTPUT ;
    USE SIGNAL ;
    PORT
      LAYER M5 ;
        RECT  23.376 0 23.4 0.192 ;
    END
  END o[219]
  PIN o[21]
    DIRECTION OUTPUT ;
    USE SIGNAL ;
    PORT
      LAYER M5 ;
        RECT  4.224 0 4.248 0.192 ;
    END
  END o[21]
  PIN o[220]
    DIRECTION OUTPUT ;
    USE SIGNAL ;
    PORT
      LAYER M3 ;
        RECT  23.472 0 23.49 0.144 ;
    END
  END o[220]
  PIN o[221]
    DIRECTION OUTPUT ;
    USE SIGNAL ;
    PORT
      LAYER M5 ;
        RECT  23.568 0 23.592 0.192 ;
    END
  END o[221]
  PIN o[222]
    DIRECTION OUTPUT ;
    USE SIGNAL ;
    PORT
      LAYER M3 ;
        RECT  23.688 0 23.706 0.144 ;
    END
  END o[222]
  PIN o[223]
    DIRECTION OUTPUT ;
    USE SIGNAL ;
    PORT
      LAYER M5 ;
        RECT  23.76 0 23.784 0.192 ;
    END
  END o[223]
  PIN o[224]
    DIRECTION OUTPUT ;
    USE SIGNAL ;
    PORT
      LAYER M3 ;
        RECT  23.868 0 23.886 0.144 ;
    END
  END o[224]
  PIN o[225]
    DIRECTION OUTPUT ;
    USE SIGNAL ;
    PORT
      LAYER M5 ;
        RECT  23.952 0 23.976 0.192 ;
    END
  END o[225]
  PIN o[226]
    DIRECTION OUTPUT ;
    USE SIGNAL ;
    PORT
      LAYER M3 ;
        RECT  24.048 0 24.066 0.144 ;
    END
  END o[226]
  PIN o[227]
    DIRECTION OUTPUT ;
    USE SIGNAL ;
    PORT
      LAYER M5 ;
        RECT  24.144 0 24.168 0.192 ;
    END
  END o[227]
  PIN o[228]
    DIRECTION OUTPUT ;
    USE SIGNAL ;
    PORT
      LAYER M3 ;
        RECT  24.264 0 24.282 0.144 ;
    END
  END o[228]
  PIN o[229]
    DIRECTION OUTPUT ;
    USE SIGNAL ;
    PORT
      LAYER M5 ;
        RECT  24.336 0 24.36 0.192 ;
    END
  END o[229]
  PIN o[22]
    DIRECTION OUTPUT ;
    USE SIGNAL ;
    PORT
      LAYER M3 ;
        RECT  4.32 0 4.338 0.144 ;
    END
  END o[22]
  PIN o[230]
    DIRECTION OUTPUT ;
    USE SIGNAL ;
    PORT
      LAYER M3 ;
        RECT  24.444 0 24.462 0.144 ;
    END
  END o[230]
  PIN o[231]
    DIRECTION OUTPUT ;
    USE SIGNAL ;
    PORT
      LAYER M5 ;
        RECT  24.528 0 24.552 0.192 ;
    END
  END o[231]
  PIN o[232]
    DIRECTION OUTPUT ;
    USE SIGNAL ;
    PORT
      LAYER M3 ;
        RECT  24.624 0 24.642 0.144 ;
    END
  END o[232]
  PIN o[233]
    DIRECTION OUTPUT ;
    USE SIGNAL ;
    PORT
      LAYER M5 ;
        RECT  24.72 0 24.744 0.192 ;
    END
  END o[233]
  PIN o[234]
    DIRECTION OUTPUT ;
    USE SIGNAL ;
    PORT
      LAYER M3 ;
        RECT  24.84 0 24.858 0.144 ;
    END
  END o[234]
  PIN o[235]
    DIRECTION OUTPUT ;
    USE SIGNAL ;
    PORT
      LAYER M5 ;
        RECT  24.912 0 24.936 0.192 ;
    END
  END o[235]
  PIN o[236]
    DIRECTION OUTPUT ;
    USE SIGNAL ;
    PORT
      LAYER M3 ;
        RECT  25.02 0 25.038 0.144 ;
    END
  END o[236]
  PIN o[237]
    DIRECTION OUTPUT ;
    USE SIGNAL ;
    PORT
      LAYER M5 ;
        RECT  25.104 0 25.128 0.192 ;
    END
  END o[237]
  PIN o[238]
    DIRECTION OUTPUT ;
    USE SIGNAL ;
    PORT
      LAYER M3 ;
        RECT  25.2 0 25.218 0.144 ;
    END
  END o[238]
  PIN o[239]
    DIRECTION OUTPUT ;
    USE SIGNAL ;
    PORT
      LAYER M5 ;
        RECT  25.296 0 25.32 0.192 ;
    END
  END o[239]
  PIN o[23]
    DIRECTION OUTPUT ;
    USE SIGNAL ;
    PORT
      LAYER M5 ;
        RECT  4.416 0 4.44 0.192 ;
    END
  END o[23]
  PIN o[240]
    DIRECTION OUTPUT ;
    USE SIGNAL ;
    PORT
      LAYER M3 ;
        RECT  25.416 0 25.434 0.144 ;
    END
  END o[240]
  PIN o[241]
    DIRECTION OUTPUT ;
    USE SIGNAL ;
    PORT
      LAYER M5 ;
        RECT  25.488 0 25.512 0.192 ;
    END
  END o[241]
  PIN o[242]
    DIRECTION OUTPUT ;
    USE SIGNAL ;
    PORT
      LAYER M3 ;
        RECT  25.596 0 25.614 0.144 ;
    END
  END o[242]
  PIN o[243]
    DIRECTION OUTPUT ;
    USE SIGNAL ;
    PORT
      LAYER M5 ;
        RECT  25.68 0 25.704 0.192 ;
    END
  END o[243]
  PIN o[244]
    DIRECTION OUTPUT ;
    USE SIGNAL ;
    PORT
      LAYER M3 ;
        RECT  25.812 0 25.83 0.144 ;
    END
  END o[244]
  PIN o[245]
    DIRECTION OUTPUT ;
    USE SIGNAL ;
    PORT
      LAYER M5 ;
        RECT  25.872 0 25.896 0.192 ;
    END
  END o[245]
  PIN o[246]
    DIRECTION OUTPUT ;
    USE SIGNAL ;
    PORT
      LAYER M3 ;
        RECT  25.992 0 26.01 0.144 ;
    END
  END o[246]
  PIN o[247]
    DIRECTION OUTPUT ;
    USE SIGNAL ;
    PORT
      LAYER M5 ;
        RECT  26.064 0 26.088 0.192 ;
    END
  END o[247]
  PIN o[248]
    DIRECTION OUTPUT ;
    USE SIGNAL ;
    PORT
      LAYER M3 ;
        RECT  26.172 0 26.19 0.144 ;
    END
  END o[248]
  PIN o[249]
    DIRECTION OUTPUT ;
    USE SIGNAL ;
    PORT
      LAYER M5 ;
        RECT  26.256 0 26.28 0.192 ;
    END
  END o[249]
  PIN o[24]
    DIRECTION OUTPUT ;
    USE SIGNAL ;
    PORT
      LAYER M3 ;
        RECT  4.536 0 4.554 0.144 ;
    END
  END o[24]
  PIN o[250]
    DIRECTION OUTPUT ;
    USE SIGNAL ;
    PORT
      LAYER M3 ;
        RECT  26.388 0 26.406 0.144 ;
    END
  END o[250]
  PIN o[251]
    DIRECTION OUTPUT ;
    USE SIGNAL ;
    PORT
      LAYER M5 ;
        RECT  26.496 0 26.52 0.192 ;
    END
  END o[251]
  PIN o[252]
    DIRECTION OUTPUT ;
    USE SIGNAL ;
    PORT
      LAYER M3 ;
        RECT  26.568 0 26.586 0.144 ;
    END
  END o[252]
  PIN o[253]
    DIRECTION OUTPUT ;
    USE SIGNAL ;
    PORT
      LAYER M5 ;
        RECT  26.688 0 26.712 0.192 ;
    END
  END o[253]
  PIN o[254]
    DIRECTION OUTPUT ;
    USE SIGNAL ;
    PORT
      LAYER M3 ;
        RECT  26.748 0 26.766 0.144 ;
    END
  END o[254]
  PIN o[255]
    DIRECTION OUTPUT ;
    USE SIGNAL ;
    PORT
      LAYER M5 ;
        RECT  26.88 0 26.904 0.192 ;
    END
  END o[255]
  PIN o[256]
    DIRECTION OUTPUT ;
    USE SIGNAL ;
    PORT
      LAYER M3 ;
        RECT  26.964 0 26.982 0.144 ;
    END
  END o[256]
  PIN o[257]
    DIRECTION OUTPUT ;
    USE SIGNAL ;
    PORT
      LAYER M5 ;
        RECT  27.072 0 27.096 0.192 ;
    END
  END o[257]
  PIN o[258]
    DIRECTION OUTPUT ;
    USE SIGNAL ;
    PORT
      LAYER M3 ;
        RECT  27.144 0 27.162 0.144 ;
    END
  END o[258]
  PIN o[259]
    DIRECTION OUTPUT ;
    USE SIGNAL ;
    PORT
      LAYER M5 ;
        RECT  27.264 0 27.288 0.192 ;
    END
  END o[259]
  PIN o[25]
    DIRECTION OUTPUT ;
    USE SIGNAL ;
    PORT
      LAYER M5 ;
        RECT  4.608 0 4.632 0.192 ;
    END
  END o[25]
  PIN o[260]
    DIRECTION OUTPUT ;
    USE SIGNAL ;
    PORT
      LAYER M3 ;
        RECT  27.36 0 27.378 0.144 ;
    END
  END o[260]
  PIN o[261]
    DIRECTION OUTPUT ;
    USE SIGNAL ;
    PORT
      LAYER M5 ;
        RECT  27.456 0 27.48 0.192 ;
    END
  END o[261]
  PIN o[262]
    DIRECTION OUTPUT ;
    USE SIGNAL ;
    PORT
      LAYER M3 ;
        RECT  27.54 0 27.558 0.144 ;
    END
  END o[262]
  PIN o[263]
    DIRECTION OUTPUT ;
    USE SIGNAL ;
    PORT
      LAYER M5 ;
        RECT  27.648 0 27.672 0.192 ;
    END
  END o[263]
  PIN o[264]
    DIRECTION OUTPUT ;
    USE SIGNAL ;
    PORT
      LAYER M3 ;
        RECT  27.72 0 27.738 0.144 ;
    END
  END o[264]
  PIN o[265]
    DIRECTION OUTPUT ;
    USE SIGNAL ;
    PORT
      LAYER M5 ;
        RECT  27.84 0 27.864 0.192 ;
    END
  END o[265]
  PIN o[266]
    DIRECTION OUTPUT ;
    USE SIGNAL ;
    PORT
      LAYER M3 ;
        RECT  27.936 0 27.954 0.144 ;
    END
  END o[266]
  PIN o[267]
    DIRECTION OUTPUT ;
    USE SIGNAL ;
    PORT
      LAYER M5 ;
        RECT  28.032 0 28.056 0.192 ;
    END
  END o[267]
  PIN o[268]
    DIRECTION OUTPUT ;
    USE SIGNAL ;
    PORT
      LAYER M3 ;
        RECT  28.116 0 28.134 0.144 ;
    END
  END o[268]
  PIN o[269]
    DIRECTION OUTPUT ;
    USE SIGNAL ;
    PORT
      LAYER M5 ;
        RECT  28.224 0 28.248 0.192 ;
    END
  END o[269]
  PIN o[26]
    DIRECTION OUTPUT ;
    USE SIGNAL ;
    PORT
      LAYER M3 ;
        RECT  4.716 0 4.734 0.144 ;
    END
  END o[26]
  PIN o[270]
    DIRECTION OUTPUT ;
    USE SIGNAL ;
    PORT
      LAYER M3 ;
        RECT  28.296 0 28.314 0.144 ;
    END
  END o[270]
  PIN o[271]
    DIRECTION OUTPUT ;
    USE SIGNAL ;
    PORT
      LAYER M5 ;
        RECT  28.416 0 28.44 0.192 ;
    END
  END o[271]
  PIN o[272]
    DIRECTION OUTPUT ;
    USE SIGNAL ;
    PORT
      LAYER M3 ;
        RECT  28.512 0 28.53 0.144 ;
    END
  END o[272]
  PIN o[273]
    DIRECTION OUTPUT ;
    USE SIGNAL ;
    PORT
      LAYER M5 ;
        RECT  28.608 0 28.632 0.192 ;
    END
  END o[273]
  PIN o[274]
    DIRECTION OUTPUT ;
    USE SIGNAL ;
    PORT
      LAYER M3 ;
        RECT  28.692 0 28.71 0.144 ;
    END
  END o[274]
  PIN o[275]
    DIRECTION OUTPUT ;
    USE SIGNAL ;
    PORT
      LAYER M5 ;
        RECT  28.8 0 28.824 0.192 ;
    END
  END o[275]
  PIN o[276]
    DIRECTION OUTPUT ;
    USE SIGNAL ;
    PORT
      LAYER M3 ;
        RECT  28.908 0 28.926 0.144 ;
    END
  END o[276]
  PIN o[277]
    DIRECTION OUTPUT ;
    USE SIGNAL ;
    PORT
      LAYER M5 ;
        RECT  28.992 0 29.016 0.192 ;
    END
  END o[277]
  PIN o[278]
    DIRECTION OUTPUT ;
    USE SIGNAL ;
    PORT
      LAYER M3 ;
        RECT  29.088 0 29.106 0.144 ;
    END
  END o[278]
  PIN o[279]
    DIRECTION OUTPUT ;
    USE SIGNAL ;
    PORT
      LAYER M5 ;
        RECT  29.184 0 29.208 0.192 ;
    END
  END o[279]
  PIN o[27]
    DIRECTION OUTPUT ;
    USE SIGNAL ;
    PORT
      LAYER M5 ;
        RECT  4.8 0 4.824 0.192 ;
    END
  END o[27]
  PIN o[280]
    DIRECTION OUTPUT ;
    USE SIGNAL ;
    PORT
      LAYER M3 ;
        RECT  29.268 0 29.286 0.144 ;
    END
  END o[280]
  PIN o[281]
    DIRECTION OUTPUT ;
    USE SIGNAL ;
    PORT
      LAYER M5 ;
        RECT  29.376 0 29.4 0.192 ;
    END
  END o[281]
  PIN o[282]
    DIRECTION OUTPUT ;
    USE SIGNAL ;
    PORT
      LAYER M3 ;
        RECT  29.484 0 29.502 0.144 ;
    END
  END o[282]
  PIN o[283]
    DIRECTION OUTPUT ;
    USE SIGNAL ;
    PORT
      LAYER M5 ;
        RECT  29.568 0 29.592 0.192 ;
    END
  END o[283]
  PIN o[284]
    DIRECTION OUTPUT ;
    USE SIGNAL ;
    PORT
      LAYER M3 ;
        RECT  29.664 0 29.682 0.144 ;
    END
  END o[284]
  PIN o[285]
    DIRECTION OUTPUT ;
    USE SIGNAL ;
    PORT
      LAYER M5 ;
        RECT  29.76 0 29.784 0.192 ;
    END
  END o[285]
  PIN o[286]
    DIRECTION OUTPUT ;
    USE SIGNAL ;
    PORT
      LAYER M3 ;
        RECT  29.844 0 29.862 0.144 ;
    END
  END o[286]
  PIN o[287]
    DIRECTION OUTPUT ;
    USE SIGNAL ;
    PORT
      LAYER M5 ;
        RECT  29.952 0 29.976 0.192 ;
    END
  END o[287]
  PIN o[288]
    DIRECTION OUTPUT ;
    USE SIGNAL ;
    PORT
      LAYER M3 ;
        RECT  30.06 0 30.078 0.144 ;
    END
  END o[288]
  PIN o[289]
    DIRECTION OUTPUT ;
    USE SIGNAL ;
    PORT
      LAYER M5 ;
        RECT  30.144 0 30.168 0.192 ;
    END
  END o[289]
  PIN o[28]
    DIRECTION OUTPUT ;
    USE SIGNAL ;
    PORT
      LAYER M3 ;
        RECT  4.896 0 4.914 0.144 ;
    END
  END o[28]
  PIN o[290]
    DIRECTION OUTPUT ;
    USE SIGNAL ;
    PORT
      LAYER M3 ;
        RECT  30.24 0 30.258 0.144 ;
    END
  END o[290]
  PIN o[291]
    DIRECTION OUTPUT ;
    USE SIGNAL ;
    PORT
      LAYER M5 ;
        RECT  30.336 0 30.36 0.192 ;
    END
  END o[291]
  PIN o[292]
    DIRECTION OUTPUT ;
    USE SIGNAL ;
    PORT
      LAYER M3 ;
        RECT  30.456 0 30.474 0.144 ;
    END
  END o[292]
  PIN o[293]
    DIRECTION OUTPUT ;
    USE SIGNAL ;
    PORT
      LAYER M5 ;
        RECT  30.528 0 30.552 0.192 ;
    END
  END o[293]
  PIN o[294]
    DIRECTION OUTPUT ;
    USE SIGNAL ;
    PORT
      LAYER M3 ;
        RECT  30.636 0 30.654 0.144 ;
    END
  END o[294]
  PIN o[295]
    DIRECTION OUTPUT ;
    USE SIGNAL ;
    PORT
      LAYER M5 ;
        RECT  30.72 0 30.744 0.192 ;
    END
  END o[295]
  PIN o[296]
    DIRECTION OUTPUT ;
    USE SIGNAL ;
    PORT
      LAYER M3 ;
        RECT  30.816 0 30.834 0.144 ;
    END
  END o[296]
  PIN o[297]
    DIRECTION OUTPUT ;
    USE SIGNAL ;
    PORT
      LAYER M5 ;
        RECT  30.912 0 30.936 0.192 ;
    END
  END o[297]
  PIN o[298]
    DIRECTION OUTPUT ;
    USE SIGNAL ;
    PORT
      LAYER M3 ;
        RECT  31.032 0 31.05 0.144 ;
    END
  END o[298]
  PIN o[299]
    DIRECTION OUTPUT ;
    USE SIGNAL ;
    PORT
      LAYER M5 ;
        RECT  31.104 0 31.128 0.192 ;
    END
  END o[299]
  PIN o[29]
    DIRECTION OUTPUT ;
    USE SIGNAL ;
    PORT
      LAYER M5 ;
        RECT  4.992 0 5.016 0.192 ;
    END
  END o[29]
  PIN o[2]
    DIRECTION OUTPUT ;
    USE SIGNAL ;
    PORT
      LAYER M3 ;
        RECT  2.376 0 2.394 0.144 ;
    END
  END o[2]
  PIN o[300]
    DIRECTION OUTPUT ;
    USE SIGNAL ;
    PORT
      LAYER M3 ;
        RECT  31.212 0 31.23 0.144 ;
    END
  END o[300]
  PIN o[301]
    DIRECTION OUTPUT ;
    USE SIGNAL ;
    PORT
      LAYER M5 ;
        RECT  31.296 0 31.32 0.192 ;
    END
  END o[301]
  PIN o[302]
    DIRECTION OUTPUT ;
    USE SIGNAL ;
    PORT
      LAYER M3 ;
        RECT  31.392 0 31.41 0.144 ;
    END
  END o[302]
  PIN o[303]
    DIRECTION OUTPUT ;
    USE SIGNAL ;
    PORT
      LAYER M5 ;
        RECT  31.488 0 31.512 0.192 ;
    END
  END o[303]
  PIN o[304]
    DIRECTION OUTPUT ;
    USE SIGNAL ;
    PORT
      LAYER M3 ;
        RECT  31.608 0 31.626 0.144 ;
    END
  END o[304]
  PIN o[305]
    DIRECTION OUTPUT ;
    USE SIGNAL ;
    PORT
      LAYER M5 ;
        RECT  31.68 0 31.704 0.192 ;
    END
  END o[305]
  PIN o[306]
    DIRECTION OUTPUT ;
    USE SIGNAL ;
    PORT
      LAYER M3 ;
        RECT  31.788 0 31.806 0.144 ;
    END
  END o[306]
  PIN o[307]
    DIRECTION OUTPUT ;
    USE SIGNAL ;
    PORT
      LAYER M5 ;
        RECT  31.872 0 31.896 0.192 ;
    END
  END o[307]
  PIN o[308]
    DIRECTION OUTPUT ;
    USE SIGNAL ;
    PORT
      LAYER M3 ;
        RECT  32.004 0 32.022 0.144 ;
    END
  END o[308]
  PIN o[309]
    DIRECTION OUTPUT ;
    USE SIGNAL ;
    PORT
      LAYER M5 ;
        RECT  32.064 0 32.088 0.192 ;
    END
  END o[309]
  PIN o[30]
    DIRECTION OUTPUT ;
    USE SIGNAL ;
    PORT
      LAYER M3 ;
        RECT  5.112 0 5.13 0.144 ;
    END
  END o[30]
  PIN o[310]
    DIRECTION OUTPUT ;
    USE SIGNAL ;
    PORT
      LAYER M3 ;
        RECT  32.184 0 32.202 0.144 ;
    END
  END o[310]
  PIN o[311]
    DIRECTION OUTPUT ;
    USE SIGNAL ;
    PORT
      LAYER M5 ;
        RECT  32.256 0 32.28 0.192 ;
    END
  END o[311]
  PIN o[312]
    DIRECTION OUTPUT ;
    USE SIGNAL ;
    PORT
      LAYER M3 ;
        RECT  32.364 0 32.382 0.144 ;
    END
  END o[312]
  PIN o[313]
    DIRECTION OUTPUT ;
    USE SIGNAL ;
    PORT
      LAYER M5 ;
        RECT  32.448 0 32.472 0.192 ;
    END
  END o[313]
  PIN o[314]
    DIRECTION OUTPUT ;
    USE SIGNAL ;
    PORT
      LAYER M3 ;
        RECT  32.58 0 32.598 0.144 ;
    END
  END o[314]
  PIN o[315]
    DIRECTION OUTPUT ;
    USE SIGNAL ;
    PORT
      LAYER M5 ;
        RECT  32.64 0 32.664 0.192 ;
    END
  END o[315]
  PIN o[316]
    DIRECTION OUTPUT ;
    USE SIGNAL ;
    PORT
      LAYER M3 ;
        RECT  32.76 0 32.778 0.144 ;
    END
  END o[316]
  PIN o[317]
    DIRECTION OUTPUT ;
    USE SIGNAL ;
    PORT
      LAYER M5 ;
        RECT  32.832 0 32.856 0.192 ;
    END
  END o[317]
  PIN o[318]
    DIRECTION OUTPUT ;
    USE SIGNAL ;
    PORT
      LAYER M3 ;
        RECT  32.94 0 32.958 0.144 ;
    END
  END o[318]
  PIN o[319]
    DIRECTION OUTPUT ;
    USE SIGNAL ;
    PORT
      LAYER M5 ;
        RECT  33.072 0 33.096 0.192 ;
    END
  END o[319]
  PIN o[31]
    DIRECTION OUTPUT ;
    USE SIGNAL ;
    PORT
      LAYER M5 ;
        RECT  5.184 0 5.208 0.192 ;
    END
  END o[31]
  PIN o[320]
    DIRECTION OUTPUT ;
    USE SIGNAL ;
    PORT
      LAYER M3 ;
        RECT  33.156 0 33.174 0.144 ;
    END
  END o[320]
  PIN o[321]
    DIRECTION OUTPUT ;
    USE SIGNAL ;
    PORT
      LAYER M5 ;
        RECT  33.264 0 33.288 0.192 ;
    END
  END o[321]
  PIN o[322]
    DIRECTION OUTPUT ;
    USE SIGNAL ;
    PORT
      LAYER M3 ;
        RECT  33.336 0 33.354 0.144 ;
    END
  END o[322]
  PIN o[323]
    DIRECTION OUTPUT ;
    USE SIGNAL ;
    PORT
      LAYER M5 ;
        RECT  33.456 0 33.48 0.192 ;
    END
  END o[323]
  PIN o[324]
    DIRECTION OUTPUT ;
    USE SIGNAL ;
    PORT
      LAYER M3 ;
        RECT  33.552 0 33.57 0.144 ;
    END
  END o[324]
  PIN o[325]
    DIRECTION OUTPUT ;
    USE SIGNAL ;
    PORT
      LAYER M5 ;
        RECT  33.648 0 33.672 0.192 ;
    END
  END o[325]
  PIN o[326]
    DIRECTION OUTPUT ;
    USE SIGNAL ;
    PORT
      LAYER M3 ;
        RECT  33.732 0 33.75 0.144 ;
    END
  END o[326]
  PIN o[327]
    DIRECTION OUTPUT ;
    USE SIGNAL ;
    PORT
      LAYER M5 ;
        RECT  33.84 0 33.864 0.192 ;
    END
  END o[327]
  PIN o[328]
    DIRECTION OUTPUT ;
    USE SIGNAL ;
    PORT
      LAYER M3 ;
        RECT  33.912 0 33.93 0.144 ;
    END
  END o[328]
  PIN o[329]
    DIRECTION OUTPUT ;
    USE SIGNAL ;
    PORT
      LAYER M5 ;
        RECT  34.032 0 34.056 0.192 ;
    END
  END o[329]
  PIN o[32]
    DIRECTION OUTPUT ;
    USE SIGNAL ;
    PORT
      LAYER M3 ;
        RECT  5.292 0 5.31 0.144 ;
    END
  END o[32]
  PIN o[330]
    DIRECTION OUTPUT ;
    USE SIGNAL ;
    PORT
      LAYER M3 ;
        RECT  34.128 0 34.146 0.144 ;
    END
  END o[330]
  PIN o[331]
    DIRECTION OUTPUT ;
    USE SIGNAL ;
    PORT
      LAYER M5 ;
        RECT  34.224 0 34.248 0.192 ;
    END
  END o[331]
  PIN o[332]
    DIRECTION OUTPUT ;
    USE SIGNAL ;
    PORT
      LAYER M3 ;
        RECT  34.308 0 34.326 0.144 ;
    END
  END o[332]
  PIN o[333]
    DIRECTION OUTPUT ;
    USE SIGNAL ;
    PORT
      LAYER M5 ;
        RECT  34.416 0 34.44 0.192 ;
    END
  END o[333]
  PIN o[334]
    DIRECTION OUTPUT ;
    USE SIGNAL ;
    PORT
      LAYER M3 ;
        RECT  34.488 0 34.506 0.144 ;
    END
  END o[334]
  PIN o[335]
    DIRECTION OUTPUT ;
    USE SIGNAL ;
    PORT
      LAYER M5 ;
        RECT  34.608 0 34.632 0.192 ;
    END
  END o[335]
  PIN o[336]
    DIRECTION OUTPUT ;
    USE SIGNAL ;
    PORT
      LAYER M3 ;
        RECT  34.704 0 34.722 0.144 ;
    END
  END o[336]
  PIN o[337]
    DIRECTION OUTPUT ;
    USE SIGNAL ;
    PORT
      LAYER M5 ;
        RECT  34.8 0 34.824 0.192 ;
    END
  END o[337]
  PIN o[338]
    DIRECTION OUTPUT ;
    USE SIGNAL ;
    PORT
      LAYER M3 ;
        RECT  34.884 0 34.902 0.144 ;
    END
  END o[338]
  PIN o[339]
    DIRECTION OUTPUT ;
    USE SIGNAL ;
    PORT
      LAYER M5 ;
        RECT  34.992 0 35.016 0.192 ;
    END
  END o[339]
  PIN o[33]
    DIRECTION OUTPUT ;
    USE SIGNAL ;
    PORT
      LAYER M5 ;
        RECT  5.376 0 5.4 0.192 ;
    END
  END o[33]
  PIN o[340]
    DIRECTION OUTPUT ;
    USE SIGNAL ;
    PORT
      LAYER M3 ;
        RECT  35.1 0 35.118 0.144 ;
    END
  END o[340]
  PIN o[341]
    DIRECTION OUTPUT ;
    USE SIGNAL ;
    PORT
      LAYER M5 ;
        RECT  35.184 0 35.208 0.192 ;
    END
  END o[341]
  PIN o[342]
    DIRECTION OUTPUT ;
    USE SIGNAL ;
    PORT
      LAYER M3 ;
        RECT  35.28 0 35.298 0.144 ;
    END
  END o[342]
  PIN o[343]
    DIRECTION OUTPUT ;
    USE SIGNAL ;
    PORT
      LAYER M5 ;
        RECT  35.376 0 35.4 0.192 ;
    END
  END o[343]
  PIN o[344]
    DIRECTION OUTPUT ;
    USE SIGNAL ;
    PORT
      LAYER M3 ;
        RECT  35.46 0 35.478 0.144 ;
    END
  END o[344]
  PIN o[345]
    DIRECTION OUTPUT ;
    USE SIGNAL ;
    PORT
      LAYER M5 ;
        RECT  35.568 0 35.592 0.192 ;
    END
  END o[345]
  PIN o[346]
    DIRECTION OUTPUT ;
    USE SIGNAL ;
    PORT
      LAYER M3 ;
        RECT  35.676 0 35.694 0.144 ;
    END
  END o[346]
  PIN o[347]
    DIRECTION OUTPUT ;
    USE SIGNAL ;
    PORT
      LAYER M5 ;
        RECT  35.76 0 35.784 0.192 ;
    END
  END o[347]
  PIN o[348]
    DIRECTION OUTPUT ;
    USE SIGNAL ;
    PORT
      LAYER M3 ;
        RECT  35.856 0 35.874 0.144 ;
    END
  END o[348]
  PIN o[349]
    DIRECTION OUTPUT ;
    USE SIGNAL ;
    PORT
      LAYER M5 ;
        RECT  35.952 0 35.976 0.192 ;
    END
  END o[349]
  PIN o[34]
    DIRECTION OUTPUT ;
    USE SIGNAL ;
    PORT
      LAYER M3 ;
        RECT  5.472 0 5.49 0.144 ;
    END
  END o[34]
  PIN o[350]
    DIRECTION OUTPUT ;
    USE SIGNAL ;
    PORT
      LAYER M3 ;
        RECT  36.036 0 36.054 0.144 ;
    END
  END o[350]
  PIN o[351]
    DIRECTION OUTPUT ;
    USE SIGNAL ;
    PORT
      LAYER M5 ;
        RECT  36.144 0 36.168 0.192 ;
    END
  END o[351]
  PIN o[352]
    DIRECTION OUTPUT ;
    USE SIGNAL ;
    PORT
      LAYER M3 ;
        RECT  36.252 0 36.27 0.144 ;
    END
  END o[352]
  PIN o[353]
    DIRECTION OUTPUT ;
    USE SIGNAL ;
    PORT
      LAYER M5 ;
        RECT  36.336 0 36.36 0.192 ;
    END
  END o[353]
  PIN o[354]
    DIRECTION OUTPUT ;
    USE SIGNAL ;
    PORT
      LAYER M3 ;
        RECT  36.432 0 36.45 0.144 ;
    END
  END o[354]
  PIN o[355]
    DIRECTION OUTPUT ;
    USE SIGNAL ;
    PORT
      LAYER M5 ;
        RECT  36.528 0 36.552 0.192 ;
    END
  END o[355]
  PIN o[356]
    DIRECTION OUTPUT ;
    USE SIGNAL ;
    PORT
      LAYER M3 ;
        RECT  36.648 0 36.666 0.144 ;
    END
  END o[356]
  PIN o[357]
    DIRECTION OUTPUT ;
    USE SIGNAL ;
    PORT
      LAYER M5 ;
        RECT  36.72 0 36.744 0.192 ;
    END
  END o[357]
  PIN o[358]
    DIRECTION OUTPUT ;
    USE SIGNAL ;
    PORT
      LAYER M3 ;
        RECT  36.828 0 36.846 0.144 ;
    END
  END o[358]
  PIN o[359]
    DIRECTION OUTPUT ;
    USE SIGNAL ;
    PORT
      LAYER M5 ;
        RECT  36.912 0 36.936 0.192 ;
    END
  END o[359]
  PIN o[35]
    DIRECTION OUTPUT ;
    USE SIGNAL ;
    PORT
      LAYER M5 ;
        RECT  5.568 0 5.592 0.192 ;
    END
  END o[35]
  PIN o[360]
    DIRECTION OUTPUT ;
    USE SIGNAL ;
    PORT
      LAYER M3 ;
        RECT  37.008 0 37.026 0.144 ;
    END
  END o[360]
  PIN o[361]
    DIRECTION OUTPUT ;
    USE SIGNAL ;
    PORT
      LAYER M5 ;
        RECT  37.104 0 37.128 0.192 ;
    END
  END o[361]
  PIN o[362]
    DIRECTION OUTPUT ;
    USE SIGNAL ;
    PORT
      LAYER M3 ;
        RECT  37.224 0 37.242 0.144 ;
    END
  END o[362]
  PIN o[363]
    DIRECTION OUTPUT ;
    USE SIGNAL ;
    PORT
      LAYER M5 ;
        RECT  37.296 0 37.32 0.192 ;
    END
  END o[363]
  PIN o[364]
    DIRECTION OUTPUT ;
    USE SIGNAL ;
    PORT
      LAYER M3 ;
        RECT  37.404 0 37.422 0.144 ;
    END
  END o[364]
  PIN o[365]
    DIRECTION OUTPUT ;
    USE SIGNAL ;
    PORT
      LAYER M5 ;
        RECT  37.488 0 37.512 0.192 ;
    END
  END o[365]
  PIN o[366]
    DIRECTION OUTPUT ;
    USE SIGNAL ;
    PORT
      LAYER M3 ;
        RECT  37.584 0 37.602 0.144 ;
    END
  END o[366]
  PIN o[367]
    DIRECTION OUTPUT ;
    USE SIGNAL ;
    PORT
      LAYER M5 ;
        RECT  37.68 0 37.704 0.192 ;
    END
  END o[367]
  PIN o[368]
    DIRECTION OUTPUT ;
    USE SIGNAL ;
    PORT
      LAYER M3 ;
        RECT  37.8 0 37.818 0.144 ;
    END
  END o[368]
  PIN o[369]
    DIRECTION OUTPUT ;
    USE SIGNAL ;
    PORT
      LAYER M5 ;
        RECT  37.872 0 37.896 0.192 ;
    END
  END o[369]
  PIN o[36]
    DIRECTION OUTPUT ;
    USE SIGNAL ;
    PORT
      LAYER M3 ;
        RECT  5.688 0 5.706 0.144 ;
    END
  END o[36]
  PIN o[370]
    DIRECTION OUTPUT ;
    USE SIGNAL ;
    PORT
      LAYER M3 ;
        RECT  37.98 0 37.998 0.144 ;
    END
  END o[370]
  PIN o[371]
    DIRECTION OUTPUT ;
    USE SIGNAL ;
    PORT
      LAYER M5 ;
        RECT  38.064 0 38.088 0.192 ;
    END
  END o[371]
  PIN o[372]
    DIRECTION OUTPUT ;
    USE SIGNAL ;
    PORT
      LAYER M3 ;
        RECT  38.16 0 38.178 0.144 ;
    END
  END o[372]
  PIN o[373]
    DIRECTION OUTPUT ;
    USE SIGNAL ;
    PORT
      LAYER M5 ;
        RECT  38.256 0 38.28 0.192 ;
    END
  END o[373]
  PIN o[374]
    DIRECTION OUTPUT ;
    USE SIGNAL ;
    PORT
      LAYER M3 ;
        RECT  38.376 0 38.394 0.144 ;
    END
  END o[374]
  PIN o[375]
    DIRECTION OUTPUT ;
    USE SIGNAL ;
    PORT
      LAYER M5 ;
        RECT  38.448 0 38.472 0.192 ;
    END
  END o[375]
  PIN o[376]
    DIRECTION OUTPUT ;
    USE SIGNAL ;
    PORT
      LAYER M3 ;
        RECT  38.556 0 38.574 0.144 ;
    END
  END o[376]
  PIN o[377]
    DIRECTION OUTPUT ;
    USE SIGNAL ;
    PORT
      LAYER M5 ;
        RECT  38.64 0 38.664 0.192 ;
    END
  END o[377]
  PIN o[378]
    DIRECTION OUTPUT ;
    USE SIGNAL ;
    PORT
      LAYER M3 ;
        RECT  38.772 0 38.79 0.144 ;
    END
  END o[378]
  PIN o[379]
    DIRECTION OUTPUT ;
    USE SIGNAL ;
    PORT
      LAYER M5 ;
        RECT  38.832 0 38.856 0.192 ;
    END
  END o[379]
  PIN o[37]
    DIRECTION OUTPUT ;
    USE SIGNAL ;
    PORT
      LAYER M5 ;
        RECT  5.76 0 5.784 0.192 ;
    END
  END o[37]
  PIN o[380]
    DIRECTION OUTPUT ;
    USE SIGNAL ;
    PORT
      LAYER M3 ;
        RECT  38.952 0 38.97 0.144 ;
    END
  END o[380]
  PIN o[381]
    DIRECTION OUTPUT ;
    USE SIGNAL ;
    PORT
      LAYER M5 ;
        RECT  39.024 0 39.048 0.192 ;
    END
  END o[381]
  PIN o[382]
    DIRECTION OUTPUT ;
    USE SIGNAL ;
    PORT
      LAYER M3 ;
        RECT  39.132 0 39.15 0.144 ;
    END
  END o[382]
  PIN o[383]
    DIRECTION OUTPUT ;
    USE SIGNAL ;
    PORT
      LAYER M5 ;
        RECT  39.216 0 39.24 0.192 ;
    END
  END o[383]
  PIN o[384]
    DIRECTION OUTPUT ;
    USE SIGNAL ;
    PORT
      LAYER M3 ;
        RECT  39.348 0 39.366 0.144 ;
    END
  END o[384]
  PIN o[385]
    DIRECTION OUTPUT ;
    USE SIGNAL ;
    PORT
      LAYER M5 ;
        RECT  39.456 0 39.48 0.192 ;
    END
  END o[385]
  PIN o[386]
    DIRECTION OUTPUT ;
    USE SIGNAL ;
    PORT
      LAYER M3 ;
        RECT  39.528 0 39.546 0.144 ;
    END
  END o[386]
  PIN o[387]
    DIRECTION OUTPUT ;
    USE SIGNAL ;
    PORT
      LAYER M5 ;
        RECT  39.648 0 39.672 0.192 ;
    END
  END o[387]
  PIN o[388]
    DIRECTION OUTPUT ;
    USE SIGNAL ;
    PORT
      LAYER M3 ;
        RECT  39.708 0 39.726 0.144 ;
    END
  END o[388]
  PIN o[389]
    DIRECTION OUTPUT ;
    USE SIGNAL ;
    PORT
      LAYER M5 ;
        RECT  39.84 0 39.864 0.192 ;
    END
  END o[389]
  PIN o[38]
    DIRECTION OUTPUT ;
    USE SIGNAL ;
    PORT
      LAYER M3 ;
        RECT  5.868 0 5.886 0.144 ;
    END
  END o[38]
  PIN o[390]
    DIRECTION OUTPUT ;
    USE SIGNAL ;
    PORT
      LAYER M3 ;
        RECT  39.924 0 39.942 0.144 ;
    END
  END o[390]
  PIN o[391]
    DIRECTION OUTPUT ;
    USE SIGNAL ;
    PORT
      LAYER M5 ;
        RECT  40.032 0 40.056 0.192 ;
    END
  END o[391]
  PIN o[392]
    DIRECTION OUTPUT ;
    USE SIGNAL ;
    PORT
      LAYER M3 ;
        RECT  40.104 0 40.122 0.144 ;
    END
  END o[392]
  PIN o[393]
    DIRECTION OUTPUT ;
    USE SIGNAL ;
    PORT
      LAYER M5 ;
        RECT  40.224 0 40.248 0.192 ;
    END
  END o[393]
  PIN o[394]
    DIRECTION OUTPUT ;
    USE SIGNAL ;
    PORT
      LAYER M3 ;
        RECT  40.32 0 40.338 0.144 ;
    END
  END o[394]
  PIN o[395]
    DIRECTION OUTPUT ;
    USE SIGNAL ;
    PORT
      LAYER M5 ;
        RECT  40.416 0 40.44 0.192 ;
    END
  END o[395]
  PIN o[396]
    DIRECTION OUTPUT ;
    USE SIGNAL ;
    PORT
      LAYER M3 ;
        RECT  40.5 0 40.518 0.144 ;
    END
  END o[396]
  PIN o[397]
    DIRECTION OUTPUT ;
    USE SIGNAL ;
    PORT
      LAYER M5 ;
        RECT  40.608 0 40.632 0.192 ;
    END
  END o[397]
  PIN o[398]
    DIRECTION OUTPUT ;
    USE SIGNAL ;
    PORT
      LAYER M3 ;
        RECT  40.68 0 40.698 0.144 ;
    END
  END o[398]
  PIN o[399]
    DIRECTION OUTPUT ;
    USE SIGNAL ;
    PORT
      LAYER M5 ;
        RECT  40.8 0 40.824 0.192 ;
    END
  END o[399]
  PIN o[39]
    DIRECTION OUTPUT ;
    USE SIGNAL ;
    PORT
      LAYER M5 ;
        RECT  5.952 0 5.976 0.192 ;
    END
  END o[39]
  PIN o[3]
    DIRECTION OUTPUT ;
    USE SIGNAL ;
    PORT
      LAYER M5 ;
        RECT  2.496 0 2.52 0.192 ;
    END
  END o[3]
  PIN o[400]
    DIRECTION OUTPUT ;
    USE SIGNAL ;
    PORT
      LAYER M3 ;
        RECT  40.896 0 40.914 0.144 ;
    END
  END o[400]
  PIN o[401]
    DIRECTION OUTPUT ;
    USE SIGNAL ;
    PORT
      LAYER M5 ;
        RECT  40.992 0 41.016 0.192 ;
    END
  END o[401]
  PIN o[402]
    DIRECTION OUTPUT ;
    USE SIGNAL ;
    PORT
      LAYER M3 ;
        RECT  41.076 0 41.094 0.144 ;
    END
  END o[402]
  PIN o[403]
    DIRECTION OUTPUT ;
    USE SIGNAL ;
    PORT
      LAYER M5 ;
        RECT  41.184 0 41.208 0.192 ;
    END
  END o[403]
  PIN o[404]
    DIRECTION OUTPUT ;
    USE SIGNAL ;
    PORT
      LAYER M3 ;
        RECT  41.256 0 41.274 0.144 ;
    END
  END o[404]
  PIN o[405]
    DIRECTION OUTPUT ;
    USE SIGNAL ;
    PORT
      LAYER M5 ;
        RECT  41.376 0 41.4 0.192 ;
    END
  END o[405]
  PIN o[406]
    DIRECTION OUTPUT ;
    USE SIGNAL ;
    PORT
      LAYER M3 ;
        RECT  41.472 0 41.49 0.144 ;
    END
  END o[406]
  PIN o[407]
    DIRECTION OUTPUT ;
    USE SIGNAL ;
    PORT
      LAYER M5 ;
        RECT  41.568 0 41.592 0.192 ;
    END
  END o[407]
  PIN o[408]
    DIRECTION OUTPUT ;
    USE SIGNAL ;
    PORT
      LAYER M3 ;
        RECT  41.652 0 41.67 0.144 ;
    END
  END o[408]
  PIN o[409]
    DIRECTION OUTPUT ;
    USE SIGNAL ;
    PORT
      LAYER M5 ;
        RECT  41.76 0 41.784 0.192 ;
    END
  END o[409]
  PIN o[40]
    DIRECTION OUTPUT ;
    USE SIGNAL ;
    PORT
      LAYER M3 ;
        RECT  6.084 0 6.102 0.144 ;
    END
  END o[40]
  PIN o[410]
    DIRECTION OUTPUT ;
    USE SIGNAL ;
    PORT
      LAYER M3 ;
        RECT  41.868 0 41.886 0.144 ;
    END
  END o[410]
  PIN o[411]
    DIRECTION OUTPUT ;
    USE SIGNAL ;
    PORT
      LAYER M5 ;
        RECT  41.952 0 41.976 0.192 ;
    END
  END o[411]
  PIN o[412]
    DIRECTION OUTPUT ;
    USE SIGNAL ;
    PORT
      LAYER M3 ;
        RECT  42.048 0 42.066 0.144 ;
    END
  END o[412]
  PIN o[413]
    DIRECTION OUTPUT ;
    USE SIGNAL ;
    PORT
      LAYER M5 ;
        RECT  42.144 0 42.168 0.192 ;
    END
  END o[413]
  PIN o[414]
    DIRECTION OUTPUT ;
    USE SIGNAL ;
    PORT
      LAYER M3 ;
        RECT  42.228 0 42.246 0.144 ;
    END
  END o[414]
  PIN o[415]
    DIRECTION OUTPUT ;
    USE SIGNAL ;
    PORT
      LAYER M5 ;
        RECT  42.336 0 42.36 0.192 ;
    END
  END o[415]
  PIN o[416]
    DIRECTION OUTPUT ;
    USE SIGNAL ;
    PORT
      LAYER M3 ;
        RECT  42.444 0 42.462 0.144 ;
    END
  END o[416]
  PIN o[417]
    DIRECTION OUTPUT ;
    USE SIGNAL ;
    PORT
      LAYER M5 ;
        RECT  42.528 0 42.552 0.192 ;
    END
  END o[417]
  PIN o[418]
    DIRECTION OUTPUT ;
    USE SIGNAL ;
    PORT
      LAYER M3 ;
        RECT  42.624 0 42.642 0.144 ;
    END
  END o[418]
  PIN o[419]
    DIRECTION OUTPUT ;
    USE SIGNAL ;
    PORT
      LAYER M5 ;
        RECT  42.72 0 42.744 0.192 ;
    END
  END o[419]
  PIN o[41]
    DIRECTION OUTPUT ;
    USE SIGNAL ;
    PORT
      LAYER M5 ;
        RECT  6.144 0 6.168 0.192 ;
    END
  END o[41]
  PIN o[420]
    DIRECTION OUTPUT ;
    USE SIGNAL ;
    PORT
      LAYER M3 ;
        RECT  42.804 0 42.822 0.144 ;
    END
  END o[420]
  PIN o[421]
    DIRECTION OUTPUT ;
    USE SIGNAL ;
    PORT
      LAYER M5 ;
        RECT  42.912 0 42.936 0.192 ;
    END
  END o[421]
  PIN o[422]
    DIRECTION OUTPUT ;
    USE SIGNAL ;
    PORT
      LAYER M3 ;
        RECT  43.02 0 43.038 0.144 ;
    END
  END o[422]
  PIN o[423]
    DIRECTION OUTPUT ;
    USE SIGNAL ;
    PORT
      LAYER M5 ;
        RECT  43.104 0 43.128 0.192 ;
    END
  END o[423]
  PIN o[424]
    DIRECTION OUTPUT ;
    USE SIGNAL ;
    PORT
      LAYER M3 ;
        RECT  43.2 0 43.218 0.144 ;
    END
  END o[424]
  PIN o[425]
    DIRECTION OUTPUT ;
    USE SIGNAL ;
    PORT
      LAYER M5 ;
        RECT  43.296 0 43.32 0.192 ;
    END
  END o[425]
  PIN o[426]
    DIRECTION OUTPUT ;
    USE SIGNAL ;
    PORT
      LAYER M3 ;
        RECT  43.416 0 43.434 0.144 ;
    END
  END o[426]
  PIN o[427]
    DIRECTION OUTPUT ;
    USE SIGNAL ;
    PORT
      LAYER M5 ;
        RECT  43.488 0 43.512 0.192 ;
    END
  END o[427]
  PIN o[428]
    DIRECTION OUTPUT ;
    USE SIGNAL ;
    PORT
      LAYER M3 ;
        RECT  43.596 0 43.614 0.144 ;
    END
  END o[428]
  PIN o[429]
    DIRECTION OUTPUT ;
    USE SIGNAL ;
    PORT
      LAYER M5 ;
        RECT  43.68 0 43.704 0.192 ;
    END
  END o[429]
  PIN o[42]
    DIRECTION OUTPUT ;
    USE SIGNAL ;
    PORT
      LAYER M3 ;
        RECT  6.264 0 6.282 0.144 ;
    END
  END o[42]
  PIN o[430]
    DIRECTION OUTPUT ;
    USE SIGNAL ;
    PORT
      LAYER M3 ;
        RECT  43.776 0 43.794 0.144 ;
    END
  END o[430]
  PIN o[431]
    DIRECTION OUTPUT ;
    USE SIGNAL ;
    PORT
      LAYER M5 ;
        RECT  43.872 0 43.896 0.192 ;
    END
  END o[431]
  PIN o[432]
    DIRECTION OUTPUT ;
    USE SIGNAL ;
    PORT
      LAYER M3 ;
        RECT  43.992 0 44.01 0.144 ;
    END
  END o[432]
  PIN o[433]
    DIRECTION OUTPUT ;
    USE SIGNAL ;
    PORT
      LAYER M5 ;
        RECT  44.064 0 44.088 0.192 ;
    END
  END o[433]
  PIN o[434]
    DIRECTION OUTPUT ;
    USE SIGNAL ;
    PORT
      LAYER M3 ;
        RECT  44.172 0 44.19 0.144 ;
    END
  END o[434]
  PIN o[435]
    DIRECTION OUTPUT ;
    USE SIGNAL ;
    PORT
      LAYER M5 ;
        RECT  44.256 0 44.28 0.192 ;
    END
  END o[435]
  PIN o[436]
    DIRECTION OUTPUT ;
    USE SIGNAL ;
    PORT
      LAYER M3 ;
        RECT  44.352 0 44.37 0.144 ;
    END
  END o[436]
  PIN o[437]
    DIRECTION OUTPUT ;
    USE SIGNAL ;
    PORT
      LAYER M5 ;
        RECT  44.448 0 44.472 0.192 ;
    END
  END o[437]
  PIN o[438]
    DIRECTION OUTPUT ;
    USE SIGNAL ;
    PORT
      LAYER M3 ;
        RECT  44.568 0 44.586 0.144 ;
    END
  END o[438]
  PIN o[439]
    DIRECTION OUTPUT ;
    USE SIGNAL ;
    PORT
      LAYER M5 ;
        RECT  44.64 0 44.664 0.192 ;
    END
  END o[439]
  PIN o[43]
    DIRECTION OUTPUT ;
    USE SIGNAL ;
    PORT
      LAYER M5 ;
        RECT  6.336 0 6.36 0.192 ;
    END
  END o[43]
  PIN o[440]
    DIRECTION OUTPUT ;
    USE SIGNAL ;
    PORT
      LAYER M3 ;
        RECT  44.748 0 44.766 0.144 ;
    END
  END o[440]
  PIN o[441]
    DIRECTION OUTPUT ;
    USE SIGNAL ;
    PORT
      LAYER M5 ;
        RECT  44.832 0 44.856 0.192 ;
    END
  END o[441]
  PIN o[442]
    DIRECTION OUTPUT ;
    USE SIGNAL ;
    PORT
      LAYER M3 ;
        RECT  44.964 0 44.982 0.144 ;
    END
  END o[442]
  PIN o[443]
    DIRECTION OUTPUT ;
    USE SIGNAL ;
    PORT
      LAYER M5 ;
        RECT  45.024 0 45.048 0.192 ;
    END
  END o[443]
  PIN o[444]
    DIRECTION OUTPUT ;
    USE SIGNAL ;
    PORT
      LAYER M3 ;
        RECT  45.144 0 45.162 0.144 ;
    END
  END o[444]
  PIN o[445]
    DIRECTION OUTPUT ;
    USE SIGNAL ;
    PORT
      LAYER M5 ;
        RECT  45.216 0 45.24 0.192 ;
    END
  END o[445]
  PIN o[446]
    DIRECTION OUTPUT ;
    USE SIGNAL ;
    PORT
      LAYER M3 ;
        RECT  45.324 0 45.342 0.144 ;
    END
  END o[446]
  PIN o[447]
    DIRECTION OUTPUT ;
    USE SIGNAL ;
    PORT
      LAYER M5 ;
        RECT  45.408 0 45.432 0.192 ;
    END
  END o[447]
  PIN o[448]
    DIRECTION OUTPUT ;
    USE SIGNAL ;
    PORT
      LAYER M3 ;
        RECT  45.54 0 45.558 0.144 ;
    END
  END o[448]
  PIN o[449]
    DIRECTION OUTPUT ;
    USE SIGNAL ;
    PORT
      LAYER M5 ;
        RECT  45.6 0 45.624 0.192 ;
    END
  END o[449]
  PIN o[44]
    DIRECTION OUTPUT ;
    USE SIGNAL ;
    PORT
      LAYER M3 ;
        RECT  6.444 0 6.462 0.144 ;
    END
  END o[44]
  PIN o[450]
    DIRECTION OUTPUT ;
    USE SIGNAL ;
    PORT
      LAYER M3 ;
        RECT  45.72 0 45.738 0.144 ;
    END
  END o[450]
  PIN o[451]
    DIRECTION OUTPUT ;
    USE SIGNAL ;
    PORT
      LAYER M5 ;
        RECT  45.792 0 45.816 0.192 ;
    END
  END o[451]
  PIN o[452]
    DIRECTION OUTPUT ;
    USE SIGNAL ;
    PORT
      LAYER M3 ;
        RECT  45.9 0 45.918 0.144 ;
    END
  END o[452]
  PIN o[453]
    DIRECTION OUTPUT ;
    USE SIGNAL ;
    PORT
      LAYER M5 ;
        RECT  46.032 0 46.056 0.192 ;
    END
  END o[453]
  PIN o[454]
    DIRECTION OUTPUT ;
    USE SIGNAL ;
    PORT
      LAYER M3 ;
        RECT  46.116 0 46.134 0.144 ;
    END
  END o[454]
  PIN o[455]
    DIRECTION OUTPUT ;
    USE SIGNAL ;
    PORT
      LAYER M5 ;
        RECT  46.224 0 46.248 0.192 ;
    END
  END o[455]
  PIN o[456]
    DIRECTION OUTPUT ;
    USE SIGNAL ;
    PORT
      LAYER M3 ;
        RECT  46.296 0 46.314 0.144 ;
    END
  END o[456]
  PIN o[457]
    DIRECTION OUTPUT ;
    USE SIGNAL ;
    PORT
      LAYER M5 ;
        RECT  46.416 0 46.44 0.192 ;
    END
  END o[457]
  PIN o[458]
    DIRECTION OUTPUT ;
    USE SIGNAL ;
    PORT
      LAYER M3 ;
        RECT  46.512 0 46.53 0.144 ;
    END
  END o[458]
  PIN o[459]
    DIRECTION OUTPUT ;
    USE SIGNAL ;
    PORT
      LAYER M5 ;
        RECT  46.608 0 46.632 0.192 ;
    END
  END o[459]
  PIN o[45]
    DIRECTION OUTPUT ;
    USE SIGNAL ;
    PORT
      LAYER M5 ;
        RECT  6.528 0 6.552 0.192 ;
    END
  END o[45]
  PIN o[460]
    DIRECTION OUTPUT ;
    USE SIGNAL ;
    PORT
      LAYER M3 ;
        RECT  46.692 0 46.71 0.144 ;
    END
  END o[460]
  PIN o[461]
    DIRECTION OUTPUT ;
    USE SIGNAL ;
    PORT
      LAYER M5 ;
        RECT  46.8 0 46.824 0.192 ;
    END
  END o[461]
  PIN o[462]
    DIRECTION OUTPUT ;
    USE SIGNAL ;
    PORT
      LAYER M3 ;
        RECT  46.872 0 46.89 0.144 ;
    END
  END o[462]
  PIN o[463]
    DIRECTION OUTPUT ;
    USE SIGNAL ;
    PORT
      LAYER M5 ;
        RECT  46.992 0 47.016 0.192 ;
    END
  END o[463]
  PIN o[464]
    DIRECTION OUTPUT ;
    USE SIGNAL ;
    PORT
      LAYER M3 ;
        RECT  47.088 0 47.106 0.144 ;
    END
  END o[464]
  PIN o[465]
    DIRECTION OUTPUT ;
    USE SIGNAL ;
    PORT
      LAYER M5 ;
        RECT  47.184 0 47.208 0.192 ;
    END
  END o[465]
  PIN o[466]
    DIRECTION OUTPUT ;
    USE SIGNAL ;
    PORT
      LAYER M3 ;
        RECT  47.268 0 47.286 0.144 ;
    END
  END o[466]
  PIN o[467]
    DIRECTION OUTPUT ;
    USE SIGNAL ;
    PORT
      LAYER M5 ;
        RECT  47.376 0 47.4 0.192 ;
    END
  END o[467]
  PIN o[468]
    DIRECTION OUTPUT ;
    USE SIGNAL ;
    PORT
      LAYER M3 ;
        RECT  47.448 0 47.466 0.144 ;
    END
  END o[468]
  PIN o[469]
    DIRECTION OUTPUT ;
    USE SIGNAL ;
    PORT
      LAYER M5 ;
        RECT  47.568 0 47.592 0.192 ;
    END
  END o[469]
  PIN o[46]
    DIRECTION OUTPUT ;
    USE SIGNAL ;
    PORT
      LAYER M3 ;
        RECT  6.66 0 6.678 0.144 ;
    END
  END o[46]
  PIN o[470]
    DIRECTION OUTPUT ;
    USE SIGNAL ;
    PORT
      LAYER M3 ;
        RECT  47.664 0 47.682 0.144 ;
    END
  END o[470]
  PIN o[471]
    DIRECTION OUTPUT ;
    USE SIGNAL ;
    PORT
      LAYER M5 ;
        RECT  47.76 0 47.784 0.192 ;
    END
  END o[471]
  PIN o[472]
    DIRECTION OUTPUT ;
    USE SIGNAL ;
    PORT
      LAYER M3 ;
        RECT  47.844 0 47.862 0.144 ;
    END
  END o[472]
  PIN o[473]
    DIRECTION OUTPUT ;
    USE SIGNAL ;
    PORT
      LAYER M5 ;
        RECT  47.952 0 47.976 0.192 ;
    END
  END o[473]
  PIN o[474]
    DIRECTION OUTPUT ;
    USE SIGNAL ;
    PORT
      LAYER M3 ;
        RECT  48.06 0 48.078 0.144 ;
    END
  END o[474]
  PIN o[475]
    DIRECTION OUTPUT ;
    USE SIGNAL ;
    PORT
      LAYER M5 ;
        RECT  48.144 0 48.168 0.192 ;
    END
  END o[475]
  PIN o[476]
    DIRECTION OUTPUT ;
    USE SIGNAL ;
    PORT
      LAYER M3 ;
        RECT  48.24 0 48.258 0.144 ;
    END
  END o[476]
  PIN o[477]
    DIRECTION OUTPUT ;
    USE SIGNAL ;
    PORT
      LAYER M5 ;
        RECT  48.336 0 48.36 0.192 ;
    END
  END o[477]
  PIN o[478]
    DIRECTION OUTPUT ;
    USE SIGNAL ;
    PORT
      LAYER M3 ;
        RECT  48.42 0 48.438 0.144 ;
    END
  END o[478]
  PIN o[479]
    DIRECTION OUTPUT ;
    USE SIGNAL ;
    PORT
      LAYER M5 ;
        RECT  48.528 0 48.552 0.192 ;
    END
  END o[479]
  PIN o[47]
    DIRECTION OUTPUT ;
    USE SIGNAL ;
    PORT
      LAYER M5 ;
        RECT  6.72 0 6.744 0.192 ;
    END
  END o[47]
  PIN o[480]
    DIRECTION OUTPUT ;
    USE SIGNAL ;
    PORT
      LAYER M3 ;
        RECT  48.636 0 48.654 0.144 ;
    END
  END o[480]
  PIN o[481]
    DIRECTION OUTPUT ;
    USE SIGNAL ;
    PORT
      LAYER M5 ;
        RECT  48.72 0 48.744 0.192 ;
    END
  END o[481]
  PIN o[482]
    DIRECTION OUTPUT ;
    USE SIGNAL ;
    PORT
      LAYER M3 ;
        RECT  48.816 0 48.834 0.144 ;
    END
  END o[482]
  PIN o[483]
    DIRECTION OUTPUT ;
    USE SIGNAL ;
    PORT
      LAYER M5 ;
        RECT  48.912 0 48.936 0.192 ;
    END
  END o[483]
  PIN o[484]
    DIRECTION OUTPUT ;
    USE SIGNAL ;
    PORT
      LAYER M3 ;
        RECT  48.996 0 49.014 0.144 ;
    END
  END o[484]
  PIN o[485]
    DIRECTION OUTPUT ;
    USE SIGNAL ;
    PORT
      LAYER M5 ;
        RECT  49.104 0 49.128 0.192 ;
    END
  END o[485]
  PIN o[486]
    DIRECTION OUTPUT ;
    USE SIGNAL ;
    PORT
      LAYER M3 ;
        RECT  49.212 0 49.23 0.144 ;
    END
  END o[486]
  PIN o[487]
    DIRECTION OUTPUT ;
    USE SIGNAL ;
    PORT
      LAYER M5 ;
        RECT  49.296 0 49.32 0.192 ;
    END
  END o[487]
  PIN o[488]
    DIRECTION OUTPUT ;
    USE SIGNAL ;
    PORT
      LAYER M3 ;
        RECT  49.392 0 49.41 0.144 ;
    END
  END o[488]
  PIN o[489]
    DIRECTION OUTPUT ;
    USE SIGNAL ;
    PORT
      LAYER M5 ;
        RECT  49.488 0 49.512 0.192 ;
    END
  END o[489]
  PIN o[48]
    DIRECTION OUTPUT ;
    USE SIGNAL ;
    PORT
      LAYER M3 ;
        RECT  6.84 0 6.858 0.144 ;
    END
  END o[48]
  PIN o[490]
    DIRECTION OUTPUT ;
    USE SIGNAL ;
    PORT
      LAYER M3 ;
        RECT  49.608 0 49.626 0.144 ;
    END
  END o[490]
  PIN o[491]
    DIRECTION OUTPUT ;
    USE SIGNAL ;
    PORT
      LAYER M5 ;
        RECT  49.68 0 49.704 0.192 ;
    END
  END o[491]
  PIN o[492]
    DIRECTION OUTPUT ;
    USE SIGNAL ;
    PORT
      LAYER M3 ;
        RECT  49.788 0 49.806 0.144 ;
    END
  END o[492]
  PIN o[493]
    DIRECTION OUTPUT ;
    USE SIGNAL ;
    PORT
      LAYER M5 ;
        RECT  49.872 0 49.896 0.192 ;
    END
  END o[493]
  PIN o[494]
    DIRECTION OUTPUT ;
    USE SIGNAL ;
    PORT
      LAYER M3 ;
        RECT  49.968 0 49.986 0.144 ;
    END
  END o[494]
  PIN o[495]
    DIRECTION OUTPUT ;
    USE SIGNAL ;
    PORT
      LAYER M5 ;
        RECT  50.064 0 50.088 0.192 ;
    END
  END o[495]
  PIN o[496]
    DIRECTION OUTPUT ;
    USE SIGNAL ;
    PORT
      LAYER M3 ;
        RECT  50.184 0 50.202 0.144 ;
    END
  END o[496]
  PIN o[497]
    DIRECTION OUTPUT ;
    USE SIGNAL ;
    PORT
      LAYER M5 ;
        RECT  50.256 0 50.28 0.192 ;
    END
  END o[497]
  PIN o[498]
    DIRECTION OUTPUT ;
    USE SIGNAL ;
    PORT
      LAYER M3 ;
        RECT  50.364 0 50.382 0.144 ;
    END
  END o[498]
  PIN o[499]
    DIRECTION OUTPUT ;
    USE SIGNAL ;
    PORT
      LAYER M5 ;
        RECT  50.448 0 50.472 0.192 ;
    END
  END o[499]
  PIN o[49]
    DIRECTION OUTPUT ;
    USE SIGNAL ;
    PORT
      LAYER M5 ;
        RECT  6.912 0 6.936 0.192 ;
    END
  END o[49]
  PIN o[4]
    DIRECTION OUTPUT ;
    USE SIGNAL ;
    PORT
      LAYER M3 ;
        RECT  2.592 0 2.61 0.144 ;
    END
  END o[4]
  PIN o[500]
    DIRECTION OUTPUT ;
    USE SIGNAL ;
    PORT
      LAYER M3 ;
        RECT  50.544 0 50.562 0.144 ;
    END
  END o[500]
  PIN o[501]
    DIRECTION OUTPUT ;
    USE SIGNAL ;
    PORT
      LAYER M5 ;
        RECT  50.64 0 50.664 0.192 ;
    END
  END o[501]
  PIN o[502]
    DIRECTION OUTPUT ;
    USE SIGNAL ;
    PORT
      LAYER M3 ;
        RECT  50.76 0 50.778 0.144 ;
    END
  END o[502]
  PIN o[503]
    DIRECTION OUTPUT ;
    USE SIGNAL ;
    PORT
      LAYER M5 ;
        RECT  50.832 0 50.856 0.192 ;
    END
  END o[503]
  PIN o[504]
    DIRECTION OUTPUT ;
    USE SIGNAL ;
    PORT
      LAYER M3 ;
        RECT  50.94 0 50.958 0.144 ;
    END
  END o[504]
  PIN o[505]
    DIRECTION OUTPUT ;
    USE SIGNAL ;
    PORT
      LAYER M5 ;
        RECT  51.024 0 51.048 0.192 ;
    END
  END o[505]
  PIN o[506]
    DIRECTION OUTPUT ;
    USE SIGNAL ;
    PORT
      LAYER M3 ;
        RECT  51.12 0 51.138 0.144 ;
    END
  END o[506]
  PIN o[507]
    DIRECTION OUTPUT ;
    USE SIGNAL ;
    PORT
      LAYER M5 ;
        RECT  51.216 0 51.24 0.192 ;
    END
  END o[507]
  PIN o[508]
    DIRECTION OUTPUT ;
    USE SIGNAL ;
    PORT
      LAYER M3 ;
        RECT  51.336 0 51.354 0.144 ;
    END
  END o[508]
  PIN o[509]
    DIRECTION OUTPUT ;
    USE SIGNAL ;
    PORT
      LAYER M5 ;
        RECT  51.408 0 51.432 0.192 ;
    END
  END o[509]
  PIN o[50]
    DIRECTION OUTPUT ;
    USE SIGNAL ;
    PORT
      LAYER M3 ;
        RECT  7.02 0 7.038 0.144 ;
    END
  END o[50]
  PIN o[510]
    DIRECTION OUTPUT ;
    USE SIGNAL ;
    PORT
      LAYER M3 ;
        RECT  51.516 0 51.534 0.144 ;
    END
  END o[510]
  PIN o[511]
    DIRECTION OUTPUT ;
    USE SIGNAL ;
    PORT
      LAYER M5 ;
        RECT  51.6 0 51.624 0.192 ;
    END
  END o[511]
  PIN o[512]
    DIRECTION OUTPUT ;
    USE SIGNAL ;
    PORT
      LAYER M3 ;
        RECT  51.732 0 51.75 0.144 ;
    END
  END o[512]
  PIN o[513]
    DIRECTION OUTPUT ;
    USE SIGNAL ;
    PORT
      LAYER M5 ;
        RECT  51.792 0 51.816 0.192 ;
    END
  END o[513]
  PIN o[514]
    DIRECTION OUTPUT ;
    USE SIGNAL ;
    PORT
      LAYER M3 ;
        RECT  51.912 0 51.93 0.144 ;
    END
  END o[514]
  PIN o[515]
    DIRECTION OUTPUT ;
    USE SIGNAL ;
    PORT
      LAYER M5 ;
        RECT  51.984 0 52.008 0.192 ;
    END
  END o[515]
  PIN o[516]
    DIRECTION OUTPUT ;
    USE SIGNAL ;
    PORT
      LAYER M3 ;
        RECT  52.092 0 52.11 0.144 ;
    END
  END o[516]
  PIN o[517]
    DIRECTION OUTPUT ;
    USE SIGNAL ;
    PORT
      LAYER M5 ;
        RECT  52.176 0 52.2 0.192 ;
    END
  END o[517]
  PIN o[518]
    DIRECTION OUTPUT ;
    USE SIGNAL ;
    PORT
      LAYER M3 ;
        RECT  52.308 0 52.326 0.144 ;
    END
  END o[518]
  PIN o[519]
    DIRECTION OUTPUT ;
    USE SIGNAL ;
    PORT
      LAYER M5 ;
        RECT  52.416 0 52.44 0.192 ;
    END
  END o[519]
  PIN o[51]
    DIRECTION OUTPUT ;
    USE SIGNAL ;
    PORT
      LAYER M5 ;
        RECT  7.152 0 7.176 0.192 ;
    END
  END o[51]
  PIN o[520]
    DIRECTION OUTPUT ;
    USE SIGNAL ;
    PORT
      LAYER M3 ;
        RECT  52.488 0 52.506 0.144 ;
    END
  END o[520]
  PIN o[521]
    DIRECTION OUTPUT ;
    USE SIGNAL ;
    PORT
      LAYER M5 ;
        RECT  52.608 0 52.632 0.192 ;
    END
  END o[521]
  PIN o[522]
    DIRECTION OUTPUT ;
    USE SIGNAL ;
    PORT
      LAYER M3 ;
        RECT  52.668 0 52.686 0.144 ;
    END
  END o[522]
  PIN o[523]
    DIRECTION OUTPUT ;
    USE SIGNAL ;
    PORT
      LAYER M5 ;
        RECT  52.8 0 52.824 0.192 ;
    END
  END o[523]
  PIN o[524]
    DIRECTION OUTPUT ;
    USE SIGNAL ;
    PORT
      LAYER M3 ;
        RECT  52.884 0 52.902 0.144 ;
    END
  END o[524]
  PIN o[525]
    DIRECTION OUTPUT ;
    USE SIGNAL ;
    PORT
      LAYER M5 ;
        RECT  52.992 0 53.016 0.192 ;
    END
  END o[525]
  PIN o[526]
    DIRECTION OUTPUT ;
    USE SIGNAL ;
    PORT
      LAYER M3 ;
        RECT  53.064 0 53.082 0.144 ;
    END
  END o[526]
  PIN o[527]
    DIRECTION OUTPUT ;
    USE SIGNAL ;
    PORT
      LAYER M5 ;
        RECT  53.184 0 53.208 0.192 ;
    END
  END o[527]
  PIN o[528]
    DIRECTION OUTPUT ;
    USE SIGNAL ;
    PORT
      LAYER M3 ;
        RECT  53.28 0 53.298 0.144 ;
    END
  END o[528]
  PIN o[529]
    DIRECTION OUTPUT ;
    USE SIGNAL ;
    PORT
      LAYER M5 ;
        RECT  53.376 0 53.4 0.192 ;
    END
  END o[529]
  PIN o[52]
    DIRECTION OUTPUT ;
    USE SIGNAL ;
    PORT
      LAYER M3 ;
        RECT  7.236 0 7.254 0.144 ;
    END
  END o[52]
  PIN o[530]
    DIRECTION OUTPUT ;
    USE SIGNAL ;
    PORT
      LAYER M3 ;
        RECT  53.46 0 53.478 0.144 ;
    END
  END o[530]
  PIN o[531]
    DIRECTION OUTPUT ;
    USE SIGNAL ;
    PORT
      LAYER M5 ;
        RECT  53.568 0 53.592 0.192 ;
    END
  END o[531]
  PIN o[532]
    DIRECTION OUTPUT ;
    USE SIGNAL ;
    PORT
      LAYER M3 ;
        RECT  53.64 0 53.658 0.144 ;
    END
  END o[532]
  PIN o[533]
    DIRECTION OUTPUT ;
    USE SIGNAL ;
    PORT
      LAYER M5 ;
        RECT  53.76 0 53.784 0.192 ;
    END
  END o[533]
  PIN o[534]
    DIRECTION OUTPUT ;
    USE SIGNAL ;
    PORT
      LAYER M3 ;
        RECT  53.856 0 53.874 0.144 ;
    END
  END o[534]
  PIN o[535]
    DIRECTION OUTPUT ;
    USE SIGNAL ;
    PORT
      LAYER M5 ;
        RECT  53.952 0 53.976 0.192 ;
    END
  END o[535]
  PIN o[53]
    DIRECTION OUTPUT ;
    USE SIGNAL ;
    PORT
      LAYER M5 ;
        RECT  7.344 0 7.368 0.192 ;
    END
  END o[53]
  PIN o[54]
    DIRECTION OUTPUT ;
    USE SIGNAL ;
    PORT
      LAYER M3 ;
        RECT  7.416 0 7.434 0.144 ;
    END
  END o[54]
  PIN o[55]
    DIRECTION OUTPUT ;
    USE SIGNAL ;
    PORT
      LAYER M5 ;
        RECT  7.536 0 7.56 0.192 ;
    END
  END o[55]
  PIN o[56]
    DIRECTION OUTPUT ;
    USE SIGNAL ;
    PORT
      LAYER M3 ;
        RECT  7.632 0 7.65 0.144 ;
    END
  END o[56]
  PIN o[57]
    DIRECTION OUTPUT ;
    USE SIGNAL ;
    PORT
      LAYER M5 ;
        RECT  7.728 0 7.752 0.192 ;
    END
  END o[57]
  PIN o[58]
    DIRECTION OUTPUT ;
    USE SIGNAL ;
    PORT
      LAYER M3 ;
        RECT  7.812 0 7.83 0.144 ;
    END
  END o[58]
  PIN o[59]
    DIRECTION OUTPUT ;
    USE SIGNAL ;
    PORT
      LAYER M5 ;
        RECT  7.92 0 7.944 0.192 ;
    END
  END o[59]
  PIN o[5]
    DIRECTION OUTPUT ;
    USE SIGNAL ;
    PORT
      LAYER M5 ;
        RECT  2.688 0 2.712 0.192 ;
    END
  END o[5]
  PIN o[60]
    DIRECTION OUTPUT ;
    USE SIGNAL ;
    PORT
      LAYER M3 ;
        RECT  7.992 0 8.01 0.144 ;
    END
  END o[60]
  PIN o[61]
    DIRECTION OUTPUT ;
    USE SIGNAL ;
    PORT
      LAYER M5 ;
        RECT  8.112 0 8.136 0.192 ;
    END
  END o[61]
  PIN o[62]
    DIRECTION OUTPUT ;
    USE SIGNAL ;
    PORT
      LAYER M3 ;
        RECT  8.208 0 8.226 0.144 ;
    END
  END o[62]
  PIN o[63]
    DIRECTION OUTPUT ;
    USE SIGNAL ;
    PORT
      LAYER M5 ;
        RECT  8.304 0 8.328 0.192 ;
    END
  END o[63]
  PIN o[64]
    DIRECTION OUTPUT ;
    USE SIGNAL ;
    PORT
      LAYER M3 ;
        RECT  8.388 0 8.406 0.144 ;
    END
  END o[64]
  PIN o[65]
    DIRECTION OUTPUT ;
    USE SIGNAL ;
    PORT
      LAYER M5 ;
        RECT  8.496 0 8.52 0.192 ;
    END
  END o[65]
  PIN o[66]
    DIRECTION OUTPUT ;
    USE SIGNAL ;
    PORT
      LAYER M3 ;
        RECT  8.568 0 8.586 0.144 ;
    END
  END o[66]
  PIN o[67]
    DIRECTION OUTPUT ;
    USE SIGNAL ;
    PORT
      LAYER M5 ;
        RECT  8.688 0 8.712 0.192 ;
    END
  END o[67]
  PIN o[68]
    DIRECTION OUTPUT ;
    USE SIGNAL ;
    PORT
      LAYER M3 ;
        RECT  8.784 0 8.802 0.144 ;
    END
  END o[68]
  PIN o[69]
    DIRECTION OUTPUT ;
    USE SIGNAL ;
    PORT
      LAYER M5 ;
        RECT  8.88 0 8.904 0.192 ;
    END
  END o[69]
  PIN o[6]
    DIRECTION OUTPUT ;
    USE SIGNAL ;
    PORT
      LAYER M3 ;
        RECT  2.772 0 2.79 0.144 ;
    END
  END o[6]
  PIN o[70]
    DIRECTION OUTPUT ;
    USE SIGNAL ;
    PORT
      LAYER M3 ;
        RECT  8.964 0 8.982 0.144 ;
    END
  END o[70]
  PIN o[71]
    DIRECTION OUTPUT ;
    USE SIGNAL ;
    PORT
      LAYER M5 ;
        RECT  9.072 0 9.096 0.192 ;
    END
  END o[71]
  PIN o[72]
    DIRECTION OUTPUT ;
    USE SIGNAL ;
    PORT
      LAYER M3 ;
        RECT  9.18 0 9.198 0.144 ;
    END
  END o[72]
  PIN o[73]
    DIRECTION OUTPUT ;
    USE SIGNAL ;
    PORT
      LAYER M5 ;
        RECT  9.264 0 9.288 0.192 ;
    END
  END o[73]
  PIN o[74]
    DIRECTION OUTPUT ;
    USE SIGNAL ;
    PORT
      LAYER M3 ;
        RECT  9.36 0 9.378 0.144 ;
    END
  END o[74]
  PIN o[75]
    DIRECTION OUTPUT ;
    USE SIGNAL ;
    PORT
      LAYER M5 ;
        RECT  9.456 0 9.48 0.192 ;
    END
  END o[75]
  PIN o[76]
    DIRECTION OUTPUT ;
    USE SIGNAL ;
    PORT
      LAYER M3 ;
        RECT  9.54 0 9.558 0.144 ;
    END
  END o[76]
  PIN o[77]
    DIRECTION OUTPUT ;
    USE SIGNAL ;
    PORT
      LAYER M5 ;
        RECT  9.648 0 9.672 0.192 ;
    END
  END o[77]
  PIN o[78]
    DIRECTION OUTPUT ;
    USE SIGNAL ;
    PORT
      LAYER M3 ;
        RECT  9.756 0 9.774 0.144 ;
    END
  END o[78]
  PIN o[79]
    DIRECTION OUTPUT ;
    USE SIGNAL ;
    PORT
      LAYER M5 ;
        RECT  9.84 0 9.864 0.192 ;
    END
  END o[79]
  PIN o[7]
    DIRECTION OUTPUT ;
    USE SIGNAL ;
    PORT
      LAYER M5 ;
        RECT  2.88 0 2.904 0.192 ;
    END
  END o[7]
  PIN o[80]
    DIRECTION OUTPUT ;
    USE SIGNAL ;
    PORT
      LAYER M3 ;
        RECT  9.936 0 9.954 0.144 ;
    END
  END o[80]
  PIN o[81]
    DIRECTION OUTPUT ;
    USE SIGNAL ;
    PORT
      LAYER M5 ;
        RECT  10.032 0 10.056 0.192 ;
    END
  END o[81]
  PIN o[82]
    DIRECTION OUTPUT ;
    USE SIGNAL ;
    PORT
      LAYER M3 ;
        RECT  10.116 0 10.134 0.144 ;
    END
  END o[82]
  PIN o[83]
    DIRECTION OUTPUT ;
    USE SIGNAL ;
    PORT
      LAYER M5 ;
        RECT  10.224 0 10.248 0.192 ;
    END
  END o[83]
  PIN o[84]
    DIRECTION OUTPUT ;
    USE SIGNAL ;
    PORT
      LAYER M3 ;
        RECT  10.332 0 10.35 0.144 ;
    END
  END o[84]
  PIN o[85]
    DIRECTION OUTPUT ;
    USE SIGNAL ;
    PORT
      LAYER M5 ;
        RECT  10.416 0 10.44 0.192 ;
    END
  END o[85]
  PIN o[86]
    DIRECTION OUTPUT ;
    USE SIGNAL ;
    PORT
      LAYER M3 ;
        RECT  10.512 0 10.53 0.144 ;
    END
  END o[86]
  PIN o[87]
    DIRECTION OUTPUT ;
    USE SIGNAL ;
    PORT
      LAYER M5 ;
        RECT  10.608 0 10.632 0.192 ;
    END
  END o[87]
  PIN o[88]
    DIRECTION OUTPUT ;
    USE SIGNAL ;
    PORT
      LAYER M3 ;
        RECT  10.728 0 10.746 0.144 ;
    END
  END o[88]
  PIN o[89]
    DIRECTION OUTPUT ;
    USE SIGNAL ;
    PORT
      LAYER M5 ;
        RECT  10.8 0 10.824 0.192 ;
    END
  END o[89]
  PIN o[8]
    DIRECTION OUTPUT ;
    USE SIGNAL ;
    PORT
      LAYER M3 ;
        RECT  2.988 0 3.006 0.144 ;
    END
  END o[8]
  PIN o[90]
    DIRECTION OUTPUT ;
    USE SIGNAL ;
    PORT
      LAYER M3 ;
        RECT  10.908 0 10.926 0.144 ;
    END
  END o[90]
  PIN o[91]
    DIRECTION OUTPUT ;
    USE SIGNAL ;
    PORT
      LAYER M5 ;
        RECT  10.992 0 11.016 0.192 ;
    END
  END o[91]
  PIN o[92]
    DIRECTION OUTPUT ;
    USE SIGNAL ;
    PORT
      LAYER M3 ;
        RECT  11.088 0 11.106 0.144 ;
    END
  END o[92]
  PIN o[93]
    DIRECTION OUTPUT ;
    USE SIGNAL ;
    PORT
      LAYER M5 ;
        RECT  11.184 0 11.208 0.192 ;
    END
  END o[93]
  PIN o[94]
    DIRECTION OUTPUT ;
    USE SIGNAL ;
    PORT
      LAYER M3 ;
        RECT  11.304 0 11.322 0.144 ;
    END
  END o[94]
  PIN o[95]
    DIRECTION OUTPUT ;
    USE SIGNAL ;
    PORT
      LAYER M5 ;
        RECT  11.376 0 11.4 0.192 ;
    END
  END o[95]
  PIN o[96]
    DIRECTION OUTPUT ;
    USE SIGNAL ;
    PORT
      LAYER M3 ;
        RECT  11.484 0 11.502 0.144 ;
    END
  END o[96]
  PIN o[97]
    DIRECTION OUTPUT ;
    USE SIGNAL ;
    PORT
      LAYER M5 ;
        RECT  11.568 0 11.592 0.192 ;
    END
  END o[97]
  PIN o[98]
    DIRECTION OUTPUT ;
    USE SIGNAL ;
    PORT
      LAYER M3 ;
        RECT  11.664 0 11.682 0.144 ;
    END
  END o[98]
  PIN o[99]
    DIRECTION OUTPUT ;
    USE SIGNAL ;
    PORT
      LAYER M5 ;
        RECT  11.76 0 11.784 0.192 ;
    END
  END o[99]
  PIN o[9]
    DIRECTION OUTPUT ;
    USE SIGNAL ;
    PORT
      LAYER M5 ;
        RECT  3.072 0 3.096 0.192 ;
    END
  END o[9]
  PIN rs
    DIRECTION INPUT ;
    USE SIGNAL ;
    PORT
      LAYER M5 ;
        RECT  41.04 55.968 41.064 56.16 ;
    END
    PORT
      LAYER M5 ;
        RECT  41.04 55.285 41.064 56.016 ;
    END
  END rs
  PIN VDD
    DIRECTION INOUT ;
    USE POWER ;
    PORT
      LAYER M5 ;
        RECT  53.892 2.151 54.012 54.009 ;
        RECT  51.192 2.151 51.312 54.009 ;
        RECT  48.492 2.151 48.612 54.009 ;
        RECT  45.792 2.151 45.912 54.009 ;
        RECT  43.092 2.151 43.212 54.009 ;
        RECT  40.392 2.151 40.512 54.009 ;
        RECT  37.692 2.151 37.812 54.009 ;
        RECT  34.992 2.151 35.112 54.009 ;
        RECT  32.292 2.151 32.412 54.009 ;
        RECT  29.592 2.151 29.712 54.009 ;
        RECT  26.892 2.151 27.012 54.009 ;
        RECT  24.192 2.151 24.312 54.009 ;
        RECT  21.492 2.151 21.612 54.009 ;
        RECT  18.792 2.151 18.912 54.009 ;
        RECT  16.092 2.151 16.212 54.009 ;
        RECT  13.392 2.151 13.512 54.009 ;
        RECT  10.692 2.151 10.812 54.009 ;
        RECT  7.992 2.151 8.112 54.009 ;
        RECT  5.292 2.151 5.412 54.009 ;
        RECT  2.592 2.151 2.712 54.009 ;
    END
  END VDD
  PIN VSS
    DIRECTION INOUT ;
    USE GROUND ;
    PORT
      LAYER M5 ;
        RECT  53.7 2.137 53.82 54.023 ;
        RECT  51 2.137 51.12 54.023 ;
        RECT  48.3 2.137 48.42 54.023 ;
        RECT  45.6 2.137 45.72 54.023 ;
        RECT  42.9 2.137 43.02 54.023 ;
        RECT  40.2 2.137 40.32 54.023 ;
        RECT  37.5 2.137 37.62 54.023 ;
        RECT  34.8 2.137 34.92 54.023 ;
        RECT  32.1 2.137 32.22 54.023 ;
        RECT  29.4 2.137 29.52 54.023 ;
        RECT  26.7 2.137 26.82 54.023 ;
        RECT  24 2.137 24.12 54.023 ;
        RECT  21.3 2.137 21.42 54.023 ;
        RECT  18.6 2.137 18.72 54.023 ;
        RECT  15.9 2.137 16.02 54.023 ;
        RECT  13.2 2.137 13.32 54.023 ;
        RECT  10.5 2.137 10.62 54.023 ;
        RECT  7.8 2.137 7.92 54.023 ;
        RECT  5.1 2.137 5.22 54.023 ;
        RECT  2.4 2.137 2.52 54.023 ;
    END
  END VSS
  # OT_OBS_CLOSED layer=M5 d_um=1.536 added=79
  OBS
    LAYER RVTN ;
     RECT  2.16 2.16 54 2.295 ;
     RECT  2.16 2.565 54 2.835 ;
     RECT  2.16 3.105 54 3.375 ;
     RECT  2.16 3.645 54 3.915 ;
     RECT  2.16 4.185 54 4.455 ;
     RECT  2.16 4.725 54 4.995 ;
     RECT  2.16 5.265 54 5.535 ;
     RECT  2.16 5.805 54 6.075 ;
     RECT  2.16 6.345 54 6.615 ;
     RECT  2.16 6.885 54 7.155 ;
     RECT  2.16 7.425 54 7.695 ;
     RECT  2.16 7.965 54 8.235 ;
     RECT  2.16 8.505 54 8.775 ;
     RECT  2.16 9.045 54 9.315 ;
     RECT  2.16 9.585 54 9.855 ;
     RECT  2.16 10.125 54 10.395 ;
     RECT  2.16 10.665 54 10.935 ;
     RECT  2.16 11.205 54 11.475 ;
     RECT  2.16 11.745 54 12.015 ;
     RECT  2.16 12.285 54 12.555 ;
     RECT  2.16 12.825 54 13.095 ;
     RECT  2.16 13.365 54 13.635 ;
     RECT  2.16 13.905 54 14.175 ;
     RECT  2.16 14.445 54 14.715 ;
     RECT  2.16 14.985 54 15.255 ;
     RECT  2.16 15.525 54 15.795 ;
     RECT  2.16 16.065 54 16.335 ;
     RECT  2.16 16.605 54 16.875 ;
     RECT  2.16 17.145 54 17.415 ;
     RECT  2.16 17.685 54 17.955 ;
     RECT  2.16 18.225 54 18.495 ;
     RECT  2.16 18.765 54 19.035 ;
     RECT  2.16 19.305 54 19.575 ;
     RECT  2.16 19.845 54 20.115 ;
     RECT  2.16 20.385 54 20.655 ;
     RECT  2.16 20.925 54 21.195 ;
     RECT  2.16 21.465 54 21.735 ;
     RECT  2.16 22.005 54 22.275 ;
     RECT  2.16 22.545 54 22.815 ;
     RECT  2.16 23.085 54 23.355 ;
     RECT  2.16 23.625 54 23.895 ;
     RECT  2.16 24.165 54 24.435 ;
     RECT  2.16 24.705 54 24.975 ;
     RECT  2.16 25.245 54 25.515 ;
     RECT  2.16 25.785 54 26.055 ;
     RECT  2.16 26.325 54 26.595 ;
     RECT  2.16 26.865 54 27.135 ;
     RECT  2.16 27.405 54 27.675 ;
     RECT  2.16 27.945 54 28.215 ;
     RECT  2.16 28.485 54 28.755 ;
     RECT  2.16 29.025 54 29.295 ;
     RECT  2.16 29.565 54 29.835 ;
     RECT  2.16 30.105 54 30.375 ;
     RECT  2.16 30.645 54 30.915 ;
     RECT  2.16 31.185 54 31.455 ;
     RECT  2.16 31.725 54 31.995 ;
     RECT  2.16 32.265 54 32.535 ;
     RECT  2.16 32.805 54 33.075 ;
     RECT  2.16 33.345 54 33.615 ;
     RECT  2.16 33.885 54 34.155 ;
     RECT  2.16 34.425 54 34.695 ;
     RECT  2.16 34.965 54 35.235 ;
     RECT  2.16 35.505 54 35.775 ;
     RECT  2.16 36.045 54 36.315 ;
     RECT  2.16 36.585 54 36.855 ;
     RECT  2.16 37.125 54 37.395 ;
     RECT  2.16 37.665 54 37.935 ;
     RECT  2.16 38.205 54 38.475 ;
     RECT  2.16 38.745 54 39.015 ;
     RECT  2.16 39.285 54 39.555 ;
     RECT  2.16 39.825 54 40.095 ;
     RECT  2.16 40.365 54 40.635 ;
     RECT  2.16 40.905 54 41.175 ;
     RECT  2.16 41.445 54 41.715 ;
     RECT  2.16 41.985 54 42.255 ;
     RECT  2.16 42.525 54 42.795 ;
     RECT  2.16 43.065 54 43.335 ;
     RECT  2.16 43.605 54 43.875 ;
     RECT  2.16 44.145 54 44.415 ;
     RECT  2.16 44.685 54 44.955 ;
     RECT  2.16 45.225 54 45.495 ;
     RECT  2.16 45.765 54 46.035 ;
     RECT  2.16 46.305 54 46.575 ;
     RECT  2.16 46.845 54 47.115 ;
     RECT  2.16 47.385 54 47.655 ;
     RECT  2.16 47.925 54 48.195 ;
     RECT  2.16 48.465 54 48.735 ;
     RECT  2.16 49.005 54 49.275 ;
     RECT  2.16 49.545 54 49.815 ;
     RECT  2.16 50.085 54 50.355 ;
     RECT  2.16 50.625 54 50.895 ;
     RECT  2.16 51.165 54 51.435 ;
     RECT  2.16 51.705 54 51.975 ;
     RECT  2.16 52.245 54 52.515 ;
     RECT  2.16 52.785 54 53.055 ;
     RECT  2.16 53.325 54 53.595 ;
     RECT  2.16 53.865 54 54 ;
    LAYER RVTP ;
     RECT  2.16 2.295 54 2.565 ;
     RECT  2.16 2.835 54 3.105 ;
     RECT  2.16 3.375 54 3.645 ;
     RECT  2.16 3.915 54 4.185 ;
     RECT  2.16 4.455 54 4.725 ;
     RECT  2.16 4.995 54 5.265 ;
     RECT  2.16 5.535 54 5.805 ;
     RECT  2.16 6.075 54 6.345 ;
     RECT  2.16 6.615 54 6.885 ;
     RECT  2.16 7.155 54 7.425 ;
     RECT  2.16 7.695 54 7.965 ;
     RECT  2.16 8.235 54 8.505 ;
     RECT  2.16 8.775 54 9.045 ;
     RECT  2.16 9.315 54 9.585 ;
     RECT  2.16 9.855 54 10.125 ;
     RECT  2.16 10.395 54 10.665 ;
     RECT  2.16 10.935 54 11.205 ;
     RECT  2.16 11.475 54 11.745 ;
     RECT  2.16 12.015 54 12.285 ;
     RECT  2.16 12.555 54 12.825 ;
     RECT  2.16 13.095 54 13.365 ;
     RECT  2.16 13.635 54 13.905 ;
     RECT  2.16 14.175 54 14.445 ;
     RECT  2.16 14.715 54 14.985 ;
     RECT  2.16 15.255 54 15.525 ;
     RECT  2.16 15.795 54 16.065 ;
     RECT  2.16 16.335 54 16.605 ;
     RECT  2.16 16.875 54 17.145 ;
     RECT  2.16 17.415 54 17.685 ;
     RECT  2.16 17.955 54 18.225 ;
     RECT  2.16 18.495 54 18.765 ;
     RECT  2.16 19.035 54 19.305 ;
     RECT  2.16 19.575 54 19.845 ;
     RECT  2.16 20.115 54 20.385 ;
     RECT  2.16 20.655 54 20.925 ;
     RECT  2.16 21.195 54 21.465 ;
     RECT  2.16 21.735 54 22.005 ;
     RECT  2.16 22.275 54 22.545 ;
     RECT  2.16 22.815 54 23.085 ;
     RECT  2.16 23.355 54 23.625 ;
     RECT  2.16 23.895 54 24.165 ;
     RECT  2.16 24.435 54 24.705 ;
     RECT  2.16 24.975 54 25.245 ;
     RECT  2.16 25.515 54 25.785 ;
     RECT  2.16 26.055 54 26.325 ;
     RECT  2.16 26.595 54 26.865 ;
     RECT  2.16 27.135 54 27.405 ;
     RECT  2.16 27.675 54 27.945 ;
     RECT  2.16 28.215 54 28.485 ;
     RECT  2.16 28.755 54 29.025 ;
     RECT  2.16 29.295 54 29.565 ;
     RECT  2.16 29.835 54 30.105 ;
     RECT  2.16 30.375 54 30.645 ;
     RECT  2.16 30.915 54 31.185 ;
     RECT  2.16 31.455 54 31.725 ;
     RECT  2.16 31.995 54 32.265 ;
     RECT  2.16 32.535 54 32.805 ;
     RECT  2.16 33.075 54 33.345 ;
     RECT  2.16 33.615 54 33.885 ;
     RECT  2.16 34.155 54 34.425 ;
     RECT  2.16 34.695 54 34.965 ;
     RECT  2.16 35.235 54 35.505 ;
     RECT  2.16 35.775 54 36.045 ;
     RECT  2.16 36.315 54 36.585 ;
     RECT  2.16 36.855 54 37.125 ;
     RECT  2.16 37.395 54 37.665 ;
     RECT  2.16 37.935 54 38.205 ;
     RECT  2.16 38.475 54 38.745 ;
     RECT  2.16 39.015 54 39.285 ;
     RECT  2.16 39.555 54 39.825 ;
     RECT  2.16 40.095 54 40.365 ;
     RECT  2.16 40.635 54 40.905 ;
     RECT  2.16 41.175 54 41.445 ;
     RECT  2.16 41.715 54 41.985 ;
     RECT  2.16 42.255 54 42.525 ;
     RECT  2.16 42.795 54 43.065 ;
     RECT  2.16 43.335 54 43.605 ;
     RECT  2.16 43.875 54 44.145 ;
     RECT  2.16 44.415 54 44.685 ;
     RECT  2.16 44.955 54 45.225 ;
     RECT  2.16 45.495 54 45.765 ;
     RECT  2.16 46.035 54 46.305 ;
     RECT  2.16 46.575 54 46.845 ;
     RECT  2.16 47.115 54 47.385 ;
     RECT  2.16 47.655 54 47.925 ;
     RECT  2.16 48.195 54 48.465 ;
     RECT  2.16 48.735 54 49.005 ;
     RECT  2.16 49.275 54 49.545 ;
     RECT  2.16 49.815 54 50.085 ;
     RECT  2.16 50.355 54 50.625 ;
     RECT  2.16 50.895 54 51.165 ;
     RECT  2.16 51.435 54 51.705 ;
     RECT  2.16 51.975 54 52.245 ;
     RECT  2.16 52.515 54 52.785 ;
     RECT  2.16 53.055 54 53.325 ;
     RECT  2.16 53.595 54 53.865 ;
    LAYER M1 ;
     RECT  2.16 2.151 54 54.009 ;
    LAYER M2 ;
     RECT  0.031 10.791 0.211 10.809 ;
     RECT  0.211 3.312 0.247 3.33 ;
     RECT  0.211 44.964 0.247 45.558 ;
     RECT  0.211 10.602 0.275 10.809 ;
     RECT  0.211 13.986 0.283 14.004 ;
     RECT  0.211 17.001 0.283 17.019 ;
     RECT  0.247 20.781 0.283 20.799 ;
     RECT  0.211 29.34 0.283 29.358 ;
     RECT  0.275 10.602 0.311 10.62 ;
     RECT  0.211 22.752 0.311 23.148 ;
     RECT  0.211 53.874 0.311 53.892 ;
     RECT  0.211 8.244 0.319 8.262 ;
     RECT  0.283 16.65 0.319 17.019 ;
     RECT  0.211 17.928 0.319 18.099 ;
     RECT  0.283 20.628 0.319 20.88 ;
     RECT  0.211 24.408 0.319 24.426 ;
     RECT  0.211 36.36 0.319 36.378 ;
     RECT  0.319 16.65 0.347 18.099 ;
     RECT  0.211 19.62 0.347 19.836 ;
     RECT  0.211 27.954 0.347 27.972 ;
     RECT  0.247 44.73 0.347 46.134 ;
     RECT  0.211 26.64 0.355 26.658 ;
     RECT  0.211 47.862 0.355 47.88 ;
     RECT  0.283 7.47 0.383 7.488 ;
     RECT  0.347 44.73 0.391 45.558 ;
     RECT  0.319 11.556 0.419 11.574 ;
     RECT  0.283 13.914 0.419 14.004 ;
     RECT  0.347 17.73 0.419 18.099 ;
     RECT  0.347 19.818 0.419 19.836 ;
     RECT  0.391 43.308 0.427 43.326 ;
     RECT  0.283 9.63 0.455 9.648 ;
     RECT  0.283 15.768 0.455 15.786 ;
     RECT  0.319 20.628 0.455 20.988 ;
     RECT  0.319 24.21 0.455 24.426 ;
     RECT  0.455 20.862 0.491 20.988 ;
     RECT  0.455 24.21 0.491 24.228 ;
     RECT  0.311 22.752 0.499 22.77 ;
     RECT  0.211 39.294 0.499 39.312 ;
     RECT  0.463 42.228 0.499 42.246 ;
     RECT  0.427 43.038 0.499 43.326 ;
     RECT  0.391 44.19 0.499 45.558 ;
     RECT  0.419 17.928 0.527 18.099 ;
     RECT  0.319 8.244 0.535 8.298 ;
     RECT  0.211 32.472 0.535 32.49 ;
     RECT  0.499 39.06 0.535 39.312 ;
     RECT  0.499 40.68 0.535 40.698 ;
     RECT  0.499 42.228 0.535 45.558 ;
     RECT  0.355 47.862 0.535 48.42 ;
     RECT  0.211 50.022 0.535 50.688 ;
     RECT  0.031 12.492 0.823 12.51 ;
     RECT  0.347 16.65 1.147 16.974 ;
     RECT  0.283 29.232 1.147 29.358 ;
     RECT  0.535 47.736 1.147 48.42 ;
     RECT  0.535 49.356 1.147 50.688 ;
     RECT  0.355 26.64 1.211 27.126 ;
     RECT  0.535 18.198 1.435 18.216 ;
     RECT  1.147 16.578 1.507 16.974 ;
     RECT  0.823 12.492 1.723 13.086 ;
     RECT  0.499 22.554 1.723 22.77 ;
     RECT  1.147 28.962 1.723 29.358 ;
     RECT  0.211 34.74 1.723 35.298 ;
     RECT  0.319 36.09 1.723 36.378 ;
     RECT  1.435 18 1.759 18.216 ;
     RECT  0.535 38.718 1.759 40.896 ;
     RECT  0.535 41.994 1.759 45.558 ;
     RECT  1.723 12.366 1.939 13.086 ;
     RECT  1.723 13.914 2.047 13.932 ;
     RECT  1.399 15.192 2.047 15.21 ;
     RECT  0.247 3.312 2.16 3.402 ;
     RECT  0.535 7.74 2.16 8.298 ;
     RECT  2.119 9.126 2.16 9.144 ;
     RECT  1.939 11.79 2.16 13.086 ;
     RECT  2.047 13.914 2.16 15.21 ;
     RECT  1.507 16.074 2.16 16.974 ;
     RECT  1.759 17.964 2.16 18.216 ;
     RECT  1.723 20.592 2.16 20.61 ;
     RECT  1.723 22.554 2.16 23.184 ;
     RECT  1.975 24.372 2.16 24.39 ;
     RECT  1.211 26.64 2.16 26.928 ;
     RECT  1.723 28.422 2.16 29.358 ;
     RECT  0.283 31.194 2.16 31.212 ;
     RECT  0.535 32.31 2.16 32.49 ;
     RECT  1.723 34.74 2.16 36.378 ;
     RECT  1.759 38.718 2.16 45.558 ;
     RECT  1.147 47.736 2.16 50.688 ;
     RECT  1.687 51.48 2.16 51.498 ;
     RECT  1.147 53.37 2.16 53.388 ;
     RECT  2.16 2.151 2.299 54.009 ;
     RECT  2.299 2.106 3.163 54.126 ;
     RECT  3.595 0.144 4.855 0.162 ;
     RECT  4.855 1.224 4.927 1.242 ;
     RECT  4.855 0.144 4.955 0.234 ;
     RECT  4.927 1.152 4.955 1.242 ;
     RECT  4.955 1.152 5.099 1.17 ;
     RECT  4.955 0.216 5.135 0.234 ;
     RECT  3.163 1.998 6.223 54.126 ;
     RECT  6.259 0.144 6.547 0.162 ;
     RECT  6.547 0.036 7.627 0.162 ;
     RECT  6.223 1.8 7.987 54.126 ;
     RECT  7.627 0.036 8.879 0.594 ;
     RECT  8.879 0.144 9.139 0.594 ;
     RECT  7.987 1.728 9.139 54.126 ;
     RECT  9.139 0.144 9.239 54.126 ;
     RECT  9.239 0.144 9.383 0.594 ;
     RECT  9.383 0.216 9.563 0.594 ;
     RECT  9.239 1.8 10.499 54.126 ;
     RECT  9.563 0.576 10.687 0.594 ;
     RECT  10.499 1.926 10.859 54.126 ;
     RECT  10.687 0.216 10.903 0.594 ;
     RECT  10.903 0.144 11.047 0.594 ;
     RECT  11.047 0.144 11.111 1.17 ;
     RECT  11.111 1.152 11.227 1.17 ;
     RECT  10.859 1.926 11.227 54.09 ;
     RECT  11.227 1.152 11.363 54.09 ;
     RECT  11.111 0.144 11.579 0.324 ;
     RECT  11.579 0.306 11.687 0.324 ;
     RECT  11.363 1.926 12.227 54.09 ;
     RECT  11.363 1.152 12.919 1.17 ;
     RECT  12.919 1.152 12.983 1.242 ;
     RECT  12.983 1.224 13.019 1.242 ;
     RECT  12.631 0.144 13.351 0.162 ;
     RECT  13.351 0.144 13.451 0.198 ;
     RECT  13.451 0.144 13.667 0.162 ;
     RECT  12.227 2.151 13.927 54.09 ;
     RECT  13.927 1.998 14.539 54.09 ;
     RECT  14.395 0.144 16.295 0.162 ;
     RECT  14.539 1.881 16.303 54.09 ;
     RECT  16.303 1.152 16.403 54.09 ;
     RECT  16.403 1.422 16.583 54.09 ;
     RECT  17.671 0.144 19.679 0.162 ;
     RECT  16.583 1.422 19.939 54.009 ;
     RECT  19.939 1.116 20.075 54.009 ;
     RECT  20.767 0.144 21.091 0.162 ;
     RECT  21.091 0.144 21.371 0.234 ;
     RECT  21.371 0.216 21.551 0.234 ;
     RECT  22.315 0.144 22.811 0.162 ;
     RECT  23.971 0.144 24.359 0.162 ;
     RECT  25.483 0.036 25.987 0.054 ;
     RECT  25.987 0.036 26.347 0.162 ;
     RECT  26.347 0.036 26.483 0.234 ;
     RECT  26.483 0.036 27.239 0.162 ;
     RECT  27.239 0.036 28.111 0.054 ;
     RECT  28.111 0.036 28.175 0.162 ;
     RECT  20.075 1.422 28.939 54.009 ;
     RECT  28.175 0.036 29.011 0.054 ;
     RECT  28.939 0.882 29.011 54.009 ;
     RECT  29.011 0.036 39.011 54.009 ;
     RECT  39.011 0.036 39.919 0.09 ;
     RECT  39.011 0.846 39.919 54.009 ;
     RECT  39.919 0.036 44.123 54.009 ;
     RECT  44.123 0.036 45.355 0.09 ;
     RECT  44.123 0.846 45.355 54.009 ;
     RECT  45.355 0.036 45.923 54.009 ;
     RECT  45.923 0.846 47.111 54.009 ;
     RECT  45.923 0.036 47.191 0.09 ;
     RECT  47.191 0.036 47.291 0.162 ;
     RECT  47.111 1.152 48.083 54.009 ;
     RECT  47.291 0.036 48.271 0.09 ;
     RECT  48.271 0.036 48.443 0.162 ;
     RECT  48.083 1.422 49.991 54.009 ;
     RECT  49.991 1.764 50.971 54.009 ;
     RECT  50.971 1.728 51.143 54.009 ;
     RECT  48.443 0.036 52.483 0.09 ;
     RECT  52.483 0.036 53.051 0.162 ;
     RECT  51.143 1.764 53.087 54.009 ;
     RECT  53.051 0.144 53.483 0.162 ;
     RECT  53.087 1.881 53.879 54.009 ;
     RECT  53.879 2.151 54 54.009 ;
     RECT  54 2.421 54.012 53.739 ;
    LAYER M3 ;
     RECT  53.028 0.031 53.046 0.067 ;
     RECT  6.552 0.031 6.57 0.108 ;
     RECT  8.856 0.031 8.874 0.108 ;
     RECT  25.488 0.031 25.506 0.108 ;
     RECT  35.172 0.067 35.19 0.108 ;
     RECT  52.56 0.067 52.668 0.108 ;
     RECT  52.686 0.067 52.884 0.108 ;
     RECT  52.902 0.067 53.046 0.108 ;
     RECT  2.214 0.108 2.376 0.144 ;
     RECT  2.394 0.108 2.592 0.144 ;
     RECT  2.61 0.108 2.772 0.144 ;
     RECT  2.79 0.108 2.988 0.144 ;
     RECT  3.006 0.108 3.168 0.144 ;
     RECT  3.186 0.108 3.348 0.144 ;
     RECT  3.366 0.108 3.564 0.144 ;
     RECT  3.582 0.108 3.744 0.144 ;
     RECT  3.762 0.108 3.924 0.144 ;
     RECT  3.942 0.108 4.14 0.144 ;
     RECT  4.158 0.108 4.32 0.144 ;
     RECT  4.338 0.108 4.536 0.144 ;
     RECT  4.554 0.108 4.716 0.144 ;
     RECT  4.734 0.108 4.896 0.144 ;
     RECT  4.914 0.108 5.112 0.144 ;
     RECT  5.13 0.108 5.292 0.144 ;
     RECT  5.31 0.108 5.472 0.144 ;
     RECT  5.49 0.108 5.688 0.144 ;
     RECT  5.706 0.108 5.868 0.144 ;
     RECT  5.886 0.108 6.084 0.144 ;
     RECT  6.102 0.108 6.264 0.144 ;
     RECT  6.282 0.108 6.444 0.144 ;
     RECT  6.462 0.108 6.66 0.144 ;
     RECT  6.678 0.108 6.84 0.144 ;
     RECT  6.858 0.108 7.02 0.144 ;
     RECT  7.038 0.108 7.236 0.144 ;
     RECT  7.254 0.108 7.416 0.144 ;
     RECT  7.434 0.108 7.632 0.144 ;
     RECT  7.65 0.108 7.812 0.144 ;
     RECT  7.83 0.108 7.992 0.144 ;
     RECT  8.01 0.108 8.208 0.144 ;
     RECT  8.226 0.108 8.388 0.144 ;
     RECT  8.406 0.108 8.568 0.144 ;
     RECT  8.586 0.108 8.784 0.144 ;
     RECT  8.802 0.108 8.964 0.144 ;
     RECT  8.982 0.108 9.18 0.144 ;
     RECT  9.198 0.108 9.36 0.144 ;
     RECT  9.378 0.108 9.54 0.144 ;
     RECT  9.558 0.108 9.756 0.144 ;
     RECT  9.774 0.108 9.936 0.144 ;
     RECT  9.954 0.108 10.116 0.144 ;
     RECT  10.134 0.108 10.332 0.144 ;
     RECT  10.35 0.108 10.512 0.144 ;
     RECT  10.53 0.108 10.728 0.144 ;
     RECT  10.746 0.108 10.908 0.144 ;
     RECT  10.926 0.108 11.088 0.144 ;
     RECT  11.106 0.108 11.304 0.144 ;
     RECT  11.322 0.108 11.484 0.144 ;
     RECT  11.502 0.108 11.664 0.144 ;
     RECT  11.682 0.108 11.88 0.144 ;
     RECT  11.898 0.108 12.06 0.144 ;
     RECT  12.078 0.108 12.24 0.144 ;
     RECT  12.258 0.108 12.456 0.144 ;
     RECT  12.474 0.108 12.636 0.144 ;
     RECT  12.654 0.108 12.852 0.144 ;
     RECT  12.87 0.108 13.032 0.144 ;
     RECT  13.05 0.108 13.212 0.144 ;
     RECT  13.23 0.108 13.428 0.144 ;
     RECT  13.446 0.108 13.608 0.144 ;
     RECT  13.626 0.108 13.788 0.144 ;
     RECT  13.806 0.108 14.004 0.144 ;
     RECT  14.022 0.108 14.184 0.144 ;
     RECT  14.202 0.108 14.4 0.144 ;
     RECT  14.418 0.108 14.58 0.144 ;
     RECT  14.598 0.108 14.76 0.144 ;
     RECT  14.778 0.108 14.976 0.144 ;
     RECT  14.994 0.108 15.156 0.144 ;
     RECT  15.174 0.108 15.336 0.144 ;
     RECT  15.354 0.108 15.552 0.144 ;
     RECT  15.57 0.108 15.732 0.144 ;
     RECT  15.75 0.108 15.948 0.144 ;
     RECT  15.966 0.108 16.128 0.144 ;
     RECT  16.146 0.108 16.308 0.144 ;
     RECT  16.326 0.108 16.524 0.144 ;
     RECT  16.542 0.108 16.704 0.144 ;
     RECT  16.722 0.108 16.884 0.144 ;
     RECT  16.902 0.108 17.1 0.144 ;
     RECT  17.118 0.108 17.28 0.144 ;
     RECT  17.298 0.108 17.496 0.144 ;
     RECT  17.514 0.108 17.676 0.144 ;
     RECT  17.694 0.108 17.856 0.144 ;
     RECT  17.874 0.108 18.072 0.144 ;
     RECT  18.09 0.108 18.252 0.144 ;
     RECT  18.27 0.108 18.432 0.144 ;
     RECT  18.45 0.108 18.648 0.144 ;
     RECT  18.666 0.108 18.828 0.144 ;
     RECT  18.846 0.108 19.044 0.144 ;
     RECT  19.062 0.108 19.224 0.144 ;
     RECT  19.242 0.108 19.404 0.144 ;
     RECT  19.422 0.108 19.62 0.144 ;
     RECT  19.638 0.108 19.8 0.144 ;
     RECT  19.818 0.108 19.98 0.144 ;
     RECT  19.998 0.108 20.196 0.144 ;
     RECT  20.214 0.108 20.376 0.144 ;
     RECT  20.394 0.108 20.592 0.144 ;
     RECT  20.61 0.108 20.772 0.144 ;
     RECT  20.79 0.108 20.952 0.144 ;
     RECT  20.97 0.108 21.168 0.144 ;
     RECT  21.186 0.108 21.348 0.144 ;
     RECT  21.366 0.108 21.528 0.144 ;
     RECT  21.546 0.108 21.744 0.144 ;
     RECT  21.762 0.108 21.924 0.144 ;
     RECT  21.942 0.108 22.14 0.144 ;
     RECT  22.158 0.108 22.32 0.144 ;
     RECT  22.338 0.108 22.5 0.144 ;
     RECT  22.518 0.108 22.716 0.144 ;
     RECT  22.734 0.108 22.896 0.144 ;
     RECT  22.914 0.108 23.076 0.144 ;
     RECT  23.094 0.108 23.292 0.144 ;
     RECT  23.31 0.108 23.472 0.144 ;
     RECT  23.49 0.108 23.688 0.144 ;
     RECT  23.706 0.108 23.868 0.144 ;
     RECT  23.886 0.108 24.048 0.144 ;
     RECT  24.066 0.108 24.264 0.144 ;
     RECT  24.282 0.108 24.444 0.144 ;
     RECT  24.462 0.108 24.624 0.144 ;
     RECT  24.642 0.108 24.84 0.144 ;
     RECT  24.858 0.108 25.02 0.144 ;
     RECT  25.038 0.108 25.2 0.144 ;
     RECT  25.218 0.108 25.416 0.144 ;
     RECT  25.434 0.108 25.596 0.144 ;
     RECT  25.614 0.108 25.812 0.144 ;
     RECT  25.83 0.108 25.992 0.144 ;
     RECT  26.01 0.108 26.172 0.144 ;
     RECT  26.19 0.108 26.388 0.144 ;
     RECT  26.406 0.108 26.568 0.144 ;
     RECT  26.586 0.108 26.748 0.144 ;
     RECT  26.766 0.108 26.964 0.144 ;
     RECT  26.982 0.108 27.144 0.144 ;
     RECT  27.162 0.108 27.36 0.144 ;
     RECT  27.378 0.108 27.54 0.144 ;
     RECT  27.558 0.108 27.72 0.144 ;
     RECT  27.738 0.108 27.936 0.144 ;
     RECT  27.954 0.108 28.116 0.144 ;
     RECT  28.134 0.108 28.296 0.144 ;
     RECT  28.314 0.108 28.512 0.144 ;
     RECT  28.53 0.108 28.692 0.144 ;
     RECT  28.71 0.108 28.908 0.144 ;
     RECT  28.926 0.108 29.088 0.144 ;
     RECT  29.106 0.108 29.268 0.144 ;
     RECT  29.286 0.108 29.484 0.144 ;
     RECT  29.502 0.108 29.664 0.144 ;
     RECT  29.682 0.108 29.844 0.144 ;
     RECT  29.862 0.108 30.06 0.144 ;
     RECT  30.078 0.108 30.24 0.144 ;
     RECT  30.258 0.108 30.456 0.144 ;
     RECT  30.474 0.108 30.636 0.144 ;
     RECT  30.654 0.108 30.816 0.144 ;
     RECT  30.834 0.108 31.032 0.144 ;
     RECT  31.05 0.108 31.212 0.144 ;
     RECT  31.23 0.108 31.392 0.144 ;
     RECT  31.41 0.108 31.608 0.144 ;
     RECT  31.626 0.108 31.788 0.144 ;
     RECT  31.806 0.108 32.004 0.144 ;
     RECT  32.022 0.108 32.184 0.144 ;
     RECT  32.202 0.108 32.364 0.144 ;
     RECT  32.382 0.108 32.58 0.144 ;
     RECT  32.598 0.108 32.76 0.144 ;
     RECT  32.778 0.108 32.94 0.144 ;
     RECT  32.958 0.108 33.156 0.144 ;
     RECT  33.174 0.108 33.336 0.144 ;
     RECT  33.354 0.108 33.552 0.144 ;
     RECT  33.57 0.108 33.732 0.144 ;
     RECT  33.75 0.108 33.912 0.144 ;
     RECT  33.93 0.108 34.128 0.144 ;
     RECT  34.146 0.108 34.308 0.144 ;
     RECT  34.326 0.108 34.488 0.144 ;
     RECT  34.506 0.108 34.704 0.144 ;
     RECT  34.722 0.108 34.884 0.144 ;
     RECT  34.902 0.108 35.1 0.144 ;
     RECT  35.118 0.108 35.28 0.144 ;
     RECT  35.298 0.108 35.46 0.144 ;
     RECT  35.478 0.108 35.676 0.144 ;
     RECT  35.694 0.108 35.856 0.144 ;
     RECT  35.874 0.108 36.036 0.144 ;
     RECT  36.054 0.108 36.252 0.144 ;
     RECT  36.27 0.108 36.432 0.144 ;
     RECT  36.45 0.108 36.648 0.144 ;
     RECT  36.666 0.108 36.828 0.144 ;
     RECT  36.846 0.108 37.008 0.144 ;
     RECT  37.026 0.108 37.224 0.144 ;
     RECT  37.242 0.108 37.404 0.144 ;
     RECT  37.422 0.108 37.584 0.144 ;
     RECT  37.602 0.108 37.8 0.144 ;
     RECT  37.818 0.108 37.98 0.144 ;
     RECT  37.998 0.108 38.16 0.144 ;
     RECT  38.178 0.108 38.376 0.144 ;
     RECT  38.394 0.108 38.556 0.144 ;
     RECT  38.574 0.108 38.772 0.144 ;
     RECT  38.79 0.108 38.952 0.144 ;
     RECT  38.97 0.108 39.132 0.144 ;
     RECT  39.15 0.108 39.348 0.144 ;
     RECT  39.366 0.108 39.528 0.144 ;
     RECT  39.546 0.108 39.708 0.144 ;
     RECT  39.726 0.108 39.924 0.144 ;
     RECT  39.942 0.108 40.104 0.144 ;
     RECT  40.122 0.108 40.32 0.144 ;
     RECT  40.338 0.108 40.5 0.144 ;
     RECT  40.518 0.108 40.68 0.144 ;
     RECT  40.698 0.108 40.896 0.144 ;
     RECT  40.914 0.108 41.076 0.144 ;
     RECT  41.094 0.108 41.256 0.144 ;
     RECT  41.274 0.108 41.472 0.144 ;
     RECT  41.49 0.108 41.652 0.144 ;
     RECT  41.67 0.108 41.868 0.144 ;
     RECT  41.886 0.108 42.048 0.144 ;
     RECT  42.066 0.108 42.228 0.144 ;
     RECT  42.246 0.108 42.444 0.144 ;
     RECT  42.462 0.108 42.624 0.144 ;
     RECT  42.642 0.108 42.804 0.144 ;
     RECT  42.822 0.108 43.02 0.144 ;
     RECT  43.038 0.108 43.2 0.144 ;
     RECT  43.218 0.108 43.416 0.144 ;
     RECT  43.434 0.108 43.596 0.144 ;
     RECT  43.614 0.108 43.776 0.144 ;
     RECT  43.794 0.108 43.992 0.144 ;
     RECT  44.01 0.108 44.172 0.144 ;
     RECT  44.19 0.108 44.352 0.144 ;
     RECT  44.37 0.108 44.568 0.144 ;
     RECT  44.586 0.108 44.748 0.144 ;
     RECT  44.766 0.108 44.964 0.144 ;
     RECT  44.982 0.108 45.144 0.144 ;
     RECT  45.162 0.108 45.324 0.144 ;
     RECT  45.342 0.108 45.54 0.144 ;
     RECT  45.558 0.108 45.72 0.144 ;
     RECT  45.738 0.108 45.9 0.144 ;
     RECT  45.918 0.108 46.116 0.144 ;
     RECT  46.134 0.108 46.296 0.144 ;
     RECT  46.314 0.108 46.512 0.144 ;
     RECT  46.53 0.108 46.692 0.144 ;
     RECT  46.71 0.108 46.872 0.144 ;
     RECT  46.89 0.108 47.088 0.144 ;
     RECT  47.106 0.108 47.268 0.144 ;
     RECT  47.286 0.108 47.448 0.144 ;
     RECT  47.466 0.108 47.664 0.144 ;
     RECT  47.682 0.108 47.844 0.144 ;
     RECT  47.862 0.108 48.06 0.144 ;
     RECT  48.078 0.108 48.24 0.144 ;
     RECT  48.258 0.108 48.42 0.144 ;
     RECT  48.438 0.108 48.636 0.144 ;
     RECT  48.654 0.108 48.816 0.144 ;
     RECT  48.834 0.108 48.996 0.144 ;
     RECT  49.014 0.108 49.212 0.144 ;
     RECT  49.23 0.108 49.392 0.144 ;
     RECT  49.41 0.108 49.608 0.144 ;
     RECT  49.626 0.108 49.788 0.144 ;
     RECT  49.806 0.108 49.968 0.144 ;
     RECT  49.986 0.108 50.184 0.144 ;
     RECT  50.202 0.108 50.364 0.144 ;
     RECT  50.382 0.108 50.544 0.144 ;
     RECT  50.562 0.108 50.76 0.144 ;
     RECT  50.778 0.108 50.94 0.144 ;
     RECT  50.958 0.108 51.12 0.144 ;
     RECT  51.138 0.108 51.336 0.144 ;
     RECT  51.354 0.108 51.516 0.144 ;
     RECT  51.534 0.108 51.732 0.144 ;
     RECT  51.75 0.108 51.912 0.144 ;
     RECT  51.93 0.108 52.092 0.144 ;
     RECT  52.11 0.108 52.308 0.144 ;
     RECT  52.326 0.108 52.488 0.144 ;
     RECT  52.506 0.108 52.668 0.144 ;
     RECT  52.686 0.108 52.884 0.144 ;
     RECT  52.902 0.108 53.064 0.144 ;
     RECT  53.082 0.108 53.28 0.144 ;
     RECT  53.298 0.108 53.46 0.144 ;
     RECT  53.478 0.108 53.64 0.144 ;
     RECT  53.658 0.108 53.856 0.144 ;
     RECT  2.196 0.144 53.874 0.317 ;
     RECT  2.196 0.317 5.706 0.413 ;
     RECT  6.66 0.317 53.874 0.571 ;
     RECT  6.66 0.571 53.946 0.845 ;
     RECT  6.228 1.795 6.246 1.876 ;
     RECT  7.128 0.845 53.946 1.876 ;
     RECT  2.196 0.413 5.49 2.065 ;
     RECT  6.228 1.876 53.946 2.065 ;
     RECT  2.196 2.065 53.946 2.413 ;
     RECT  0.288 2.539 0.306 2.683 ;
     RECT  2.196 2.413 53.997 2.867 ;
     RECT  0.288 2.683 0.414 2.971 ;
     RECT  2.304 2.867 53.997 3.029 ;
     RECT  0.252 2.971 0.414 3.307 ;
     RECT  0.216 3.307 0.414 3.355 ;
     RECT  0.216 3.355 0.558 3.581 ;
     RECT  0.252 3.581 0.558 3.773 ;
     RECT  2.304 3.029 52.47 4.363 ;
     RECT  2.268 4.363 52.47 4.415 ;
     RECT  0.54 3.773 0.558 4.555 ;
     RECT  53.28 3.029 53.997 4.793 ;
     RECT  0.252 4.555 0.558 4.843 ;
     RECT  0.252 4.843 0.846 5.131 ;
     RECT  2.304 4.415 52.47 5.845 ;
     RECT  0.216 5.131 0.846 8.267 ;
     RECT  2.196 5.845 52.47 8.395 ;
     RECT  0.252 8.267 0.846 8.683 ;
     RECT  1.98 8.395 52.47 8.683 ;
     RECT  0.252 8.683 52.47 10.459 ;
     RECT  0.216 10.459 52.47 10.786 ;
     RECT  0.036 10.786 52.47 12.515 ;
     RECT  0.684 12.515 52.47 13.019 ;
     RECT  0.684 13.019 51.297 13.091 ;
     RECT  0.252 13.339 0.414 13.915 ;
     RECT  0.216 13.915 0.414 14.009 ;
     RECT  0.324 14.009 0.414 14.189 ;
     RECT  1.404 13.091 51.297 14.477 ;
     RECT  1.404 14.477 1.53 14.587 ;
     RECT  0.936 14.587 1.53 14.717 ;
     RECT  1.404 14.717 1.53 15.215 ;
     RECT  1.44 15.215 1.53 15.355 ;
     RECT  2.304 14.477 51.297 15.355 ;
     RECT  0.288 15.019 0.414 15.763 ;
     RECT  0.288 15.763 0.45 15.869 ;
     RECT  52.128 13.019 52.47 16.061 ;
     RECT  0.252 16.075 0.27 16.253 ;
     RECT  1.44 15.355 51.297 16.573 ;
     RECT  1.152 16.573 51.297 16.673 ;
     RECT  0.288 16.645 0.306 16.891 ;
     RECT  0.288 16.891 0.342 16.939 ;
     RECT  0.288 16.939 0.414 16.951 ;
     RECT  0.288 16.951 0.558 16.996 ;
     RECT  0.216 16.996 0.558 17.069 ;
     RECT  0.252 17.069 0.558 17.261 ;
     RECT  52.2 16.061 52.47 17.411 ;
     RECT  0.252 17.261 0.522 17.899 ;
     RECT  1.44 16.673 51.297 17.987 ;
     RECT  1.44 17.987 1.458 18.023 ;
     RECT  0.216 17.899 0.522 18.125 ;
     RECT  0.468 18.125 0.522 18.193 ;
     RECT  0.468 18.193 0.558 18.605 ;
     RECT  0.468 18.605 0.486 18.859 ;
     RECT  2.232 17.987 51.297 19.099 ;
     RECT  0.252 18.859 0.486 19.277 ;
     RECT  0.252 19.277 0.45 19.612 ;
     RECT  0.216 19.612 0.45 20.107 ;
     RECT  1.728 19.099 51.297 20.615 ;
     RECT  0.216 20.107 0.522 20.779 ;
     RECT  0.216 20.779 0.702 21.053 ;
     RECT  1.98 20.615 51.297 21.883 ;
     RECT  0.216 21.053 0.594 22.649 ;
     RECT  0.216 22.649 0.522 23.153 ;
     RECT  1.728 21.883 51.297 23.189 ;
     RECT  0.252 23.153 0.522 23.597 ;
     RECT  0.324 23.597 0.522 23.741 ;
     RECT  1.98 23.189 51.297 24.089 ;
     RECT  0.324 23.741 0.486 24.379 ;
     RECT  1.98 24.089 21.654 24.395 ;
     RECT  0.216 24.379 0.486 24.413 ;
     RECT  0.216 24.413 0.45 24.431 ;
     RECT  0.252 24.431 0.45 24.509 ;
     RECT  0.252 24.509 0.27 24.941 ;
     RECT  2.232 24.395 21.654 24.979 ;
     RECT  22.392 24.089 51.297 24.979 ;
     RECT  2.232 24.979 51.297 25.469 ;
     RECT  0.396 25.915 0.414 26.011 ;
     RECT  0.288 26.011 0.414 26.347 ;
     RECT  0.252 26.347 0.414 26.635 ;
     RECT  1.152 26.347 1.17 26.905 ;
     RECT  0.216 26.635 0.414 26.909 ;
     RECT  0.216 26.909 0.378 27.005 ;
     RECT  1.152 26.905 1.206 27.163 ;
     RECT  2.304 25.469 51.297 27.163 ;
     RECT  0.36 27.005 0.378 27.389 ;
     RECT  0.216 27.931 0.342 27.977 ;
     RECT  0.252 27.977 0.342 28.123 ;
     RECT  0.252 28.123 0.414 28.253 ;
     RECT  1.152 27.163 51.297 28.445 ;
     RECT  1.944 28.445 51.297 28.823 ;
     RECT  2.268 28.823 51.297 28.859 ;
     RECT  1.152 28.445 1.17 28.985 ;
     RECT  0.252 28.253 0.27 29.227 ;
     RECT  0.252 29.227 0.306 29.335 ;
     RECT  0.216 29.335 0.306 29.693 ;
     RECT  0.252 29.693 0.306 30.077 ;
     RECT  2.304 28.859 51.297 30.187 ;
     RECT  2.232 30.187 51.297 30.371 ;
     RECT  2.232 30.371 44.802 30.479 ;
     RECT  0.288 30.077 0.306 30.571 ;
     RECT  0.288 30.571 0.414 30.701 ;
     RECT  2.268 30.479 44.802 30.839 ;
     RECT  0.288 30.701 0.306 31.217 ;
     RECT  2.268 30.839 38.934 31.217 ;
     RECT  2.268 31.217 38.898 31.243 ;
     RECT  0.252 31.339 0.27 31.709 ;
     RECT  2.232 31.243 38.898 32.261 ;
     RECT  0.54 32.305 0.558 32.467 ;
     RECT  2.232 32.261 38.646 32.491 ;
     RECT  0.216 32.467 0.558 32.621 ;
     RECT  0.54 32.621 0.558 33.197 ;
     RECT  1.728 32.491 38.646 33.917 ;
     RECT  1.728 33.917 29.697 34.457 ;
     RECT  0.252 34.459 0.27 34.735 ;
     RECT  0.216 34.735 0.27 34.987 ;
     RECT  27.9 34.457 29.697 35.069 ;
     RECT  0.216 34.987 0.414 35.117 ;
     RECT  0.216 35.117 0.27 35.405 ;
     RECT  0.252 35.405 0.27 35.501 ;
     RECT  1.728 34.457 26.997 35.735 ;
     RECT  30.456 33.917 38.646 35.879 ;
     RECT  2.268 35.735 26.997 36.005 ;
     RECT  33.156 35.879 38.646 36.041 ;
     RECT  27.9 35.069 27.918 36.085 ;
     RECT  28.728 35.069 29.697 36.085 ;
     RECT  33.228 36.041 38.646 36.113 ;
     RECT  2.304 36.005 26.997 36.239 ;
     RECT  27.9 36.085 29.697 36.283 ;
     RECT  30.456 35.879 32.397 36.283 ;
     RECT  0.288 35.947 0.414 36.355 ;
     RECT  27.9 36.283 32.397 36.581 ;
     RECT  0.216 36.355 0.414 36.605 ;
     RECT  28.728 36.581 32.397 36.887 ;
     RECT  0.252 36.605 0.414 36.893 ;
     RECT  28.728 36.887 29.697 37.121 ;
     RECT  0.252 36.893 0.27 37.277 ;
     RECT  33.228 36.113 38.034 37.319 ;
     RECT  33.228 37.319 37.797 37.427 ;
     RECT  2.304 36.239 25.398 37.723 ;
     RECT  34.56 37.427 37.797 37.859 ;
     RECT  2.268 37.723 25.398 37.931 ;
     RECT  35.856 37.859 37.797 38.129 ;
     RECT  35.928 38.129 36.162 38.165 ;
     RECT  0.252 38.011 0.27 38.189 ;
     RECT  0.396 38.299 0.414 38.429 ;
     RECT  2.304 37.931 25.398 38.779 ;
     RECT  2.052 38.779 25.398 39.083 ;
     RECT  0.504 38.713 0.558 39.163 ;
     RECT  0.252 39.163 0.558 39.289 ;
     RECT  0.216 39.289 0.558 39.451 ;
     RECT  0.216 39.451 1.278 39.677 ;
     RECT  0.216 39.677 0.558 39.773 ;
     RECT  0.252 39.773 0.558 40.109 ;
     RECT  2.052 39.083 22.482 40.123 ;
     RECT  45.54 30.371 51.297 40.199 ;
     RECT  36.72 40.171 36.738 40.289 ;
     RECT  0.288 40.109 0.558 41.213 ;
     RECT  23.256 39.083 25.398 41.369 ;
     RECT  1.764 40.123 22.482 41.405 ;
     RECT  0.288 41.213 0.522 41.419 ;
     RECT  0.252 41.419 0.522 41.947 ;
     RECT  2.268 41.405 22.482 42.077 ;
     RECT  0.252 41.947 1.17 42.173 ;
     RECT  0.468 42.173 1.17 42.235 ;
     RECT  2.304 42.077 22.482 42.485 ;
     RECT  36.216 42.571 36.234 42.719 ;
     RECT  0.468 42.235 1.206 42.955 ;
     RECT  0.396 42.955 1.206 43.033 ;
     RECT  39.672 30.839 44.802 43.061 ;
     RECT  0.396 43.033 1.242 43.133 ;
     RECT  39.672 43.061 44.73 43.661 ;
     RECT  2.304 42.485 18.954 43.673 ;
     RECT  0.396 43.133 1.206 44.203 ;
     RECT  2.34 43.673 18.954 44.491 ;
     RECT  0.252 44.203 1.206 44.645 ;
     RECT  19.764 42.485 22.482 44.753 ;
     RECT  39.672 43.661 43.398 44.753 ;
     RECT  23.544 41.369 25.398 44.789 ;
     RECT  0.252 44.645 0.558 44.959 ;
     RECT  27.9 36.581 27.918 45.455 ;
     RECT  0.216 44.959 0.558 45.677 ;
     RECT  0.216 45.677 0.414 45.869 ;
     RECT  40.215 44.753 43.398 45.959 ;
     RECT  33.228 37.427 33.246 46.229 ;
     RECT  2.304 44.491 18.954 46.363 ;
     RECT  22.464 44.753 22.482 46.499 ;
     RECT  0.252 45.869 0.414 46.541 ;
     RECT  1.692 46.363 18.954 46.769 ;
     RECT  0.252 46.541 0.342 47.021 ;
     RECT  50.04 40.199 51.297 47.039 ;
     RECT  15.372 46.769 18.954 47.371 ;
     RECT  19.764 44.753 21.597 47.371 ;
     RECT  45.54 40.199 49.302 47.453 ;
     RECT  0.324 47.021 0.342 47.467 ;
     RECT  0.324 47.467 0.414 47.563 ;
     RECT  1.692 46.769 14.382 47.579 ;
     RECT  30.456 36.887 32.397 47.579 ;
     RECT  14.256 47.579 14.382 47.587 ;
     RECT  15.372 47.371 21.597 47.587 ;
     RECT  0.324 47.563 0.486 47.731 ;
     RECT  14.256 47.587 21.597 47.849 ;
     RECT  0.324 47.731 0.558 47.857 ;
     RECT  44.136 43.661 44.73 47.993 ;
     RECT  0.216 47.857 0.558 48.077 ;
     RECT  14.256 47.849 20.322 48.119 ;
     RECT  0.216 48.077 0.414 48.365 ;
     RECT  14.364 48.119 20.322 48.389 ;
     RECT  14.364 48.389 19.458 48.425 ;
     RECT  44.136 47.993 44.154 48.461 ;
     RECT  15.156 48.425 19.458 48.659 ;
     RECT  45.615 47.453 49.302 48.731 ;
     RECT  1.692 47.579 13.497 48.767 ;
     RECT  15.3 48.659 19.458 48.767 ;
     RECT  47.484 48.731 49.302 48.839 ;
     RECT  15.915 48.767 19.458 48.929 ;
     RECT  15.915 48.929 19.206 49.001 ;
     RECT  1.152 48.973 1.17 49.037 ;
     RECT  0.288 48.365 0.414 49.339 ;
     RECT  0.252 49.339 0.414 49.351 ;
     RECT  47.808 48.839 49.302 49.379 ;
     RECT  45.615 48.731 46.458 49.469 ;
     RECT  18.615 49.001 19.206 49.505 ;
     RECT  40.215 45.959 43.197 49.613 ;
     RECT  15.915 49.001 17.694 49.649 ;
     RECT  14.364 48.425 14.382 49.819 ;
     RECT  2.268 48.767 13.497 49.883 ;
     RECT  0.252 49.351 0.558 49.949 ;
     RECT  2.304 49.883 13.497 50.009 ;
     RECT  18.615 49.505 19.026 50.009 ;
     RECT  0.252 49.949 0.414 50.017 ;
     RECT  25.344 44.789 25.398 50.117 ;
     RECT  14.364 49.819 14.85 50.279 ;
     RECT  40.215 49.613 41.922 50.423 ;
     RECT  15.915 49.649 17.01 50.459 ;
     RECT  14.832 50.279 14.85 50.549 ;
     RECT  18.615 50.009 18.954 50.549 ;
     RECT  20.232 48.389 20.322 50.549 ;
     RECT  33.12 46.381 33.138 50.729 ;
     RECT  0.216 50.017 0.414 50.813 ;
     RECT  34.56 37.859 35.097 50.971 ;
     RECT  2.304 50.009 11.934 50.999 ;
     RECT  26.46 36.239 26.997 51.089 ;
     RECT  41.904 50.423 41.922 51.125 ;
     RECT  34.308 50.971 35.097 51.269 ;
     RECT  2.304 50.999 11.79 51.359 ;
     RECT  44.316 51.331 44.334 51.389 ;
     RECT  50.436 47.039 51.297 51.395 ;
     RECT  1.152 51.259 1.17 51.475 ;
     RECT  2.304 51.359 11.718 51.475 ;
     RECT  0.288 50.813 0.414 51.547 ;
     RECT  1.152 51.475 11.718 51.547 ;
     RECT  0.288 51.547 11.718 51.677 ;
     RECT  0.288 51.677 0.378 51.869 ;
     RECT  23.544 44.789 24.297 51.899 ;
     RECT  15.915 50.459 16.758 51.979 ;
     RECT  0.288 51.869 0.342 52.171 ;
     RECT  0.252 52.171 0.342 52.349 ;
     RECT  15.915 51.979 17.478 52.439 ;
     RECT  48.315 49.379 49.302 52.439 ;
     RECT  0.324 52.349 0.342 52.445 ;
     RECT  40.215 50.423 41.13 52.709 ;
     RECT  12.744 50.009 13.497 52.861 ;
     RECT  1.152 51.677 11.718 53.257 ;
     RECT  12.672 52.861 13.497 53.257 ;
     RECT  24.015 51.899 24.297 53.293 ;
     RECT  1.152 53.257 13.497 53.393 ;
     RECT  30.744 47.579 32.397 53.519 ;
     RECT  1.692 53.393 13.497 53.555 ;
     RECT  0.396 53.467 0.414 53.563 ;
     RECT  0.288 53.563 0.414 53.597 ;
     RECT  52.452 17.411 52.47 53.663 ;
     RECT  21.315 47.849 21.597 53.671 ;
     RECT  25.344 50.117 25.362 53.699 ;
     RECT  13.215 53.555 13.497 53.747 ;
     RECT  18.615 50.549 18.897 53.747 ;
     RECT  21.132 53.671 21.597 53.747 ;
     RECT  26.715 51.089 26.997 53.747 ;
     RECT  29.415 37.121 29.697 53.747 ;
     RECT  31.284 53.519 32.397 53.747 ;
     RECT  34.815 51.269 35.097 53.747 ;
     RECT  37.515 38.129 37.797 53.747 ;
     RECT  42.915 49.613 43.197 53.747 ;
     RECT  45.615 49.469 45.897 53.747 ;
     RECT  48.315 52.439 48.597 53.747 ;
     RECT  51.015 51.395 51.297 53.747 ;
     RECT  53.715 4.793 53.997 53.747 ;
     RECT  1.692 53.555 11.862 53.789 ;
     RECT  15.915 52.439 16.65 53.789 ;
     RECT  19.944 51.907 19.962 53.789 ;
     RECT  21.132 53.747 21.405 53.789 ;
     RECT  31.284 53.747 32.205 53.789 ;
     RECT  34.815 53.747 34.905 53.797 ;
     RECT  40.215 52.709 40.497 53.797 ;
     RECT  1.692 53.789 4.158 53.837 ;
     RECT  0.288 53.597 0.378 53.851 ;
     RECT  13.215 53.747 13.374 53.861 ;
     RECT  0.216 53.851 0.378 53.885 ;
     RECT  0.216 53.885 0.306 53.897 ;
     RECT  5.076 53.789 10.854 53.897 ;
     RECT  31.464 53.789 32.205 53.897 ;
     RECT  39.852 53.797 40.626 53.905 ;
     RECT  0.288 53.897 0.306 53.933 ;
     RECT  39.852 53.905 40.77 53.933 ;
     RECT  5.076 53.897 5.922 53.969 ;
     RECT  24.015 53.293 24.498 53.969 ;
     RECT  34.776 53.797 34.905 53.969 ;
     RECT  40.14 53.933 40.77 53.969 ;
     RECT  1.692 53.837 3.798 53.981 ;
     RECT  5.115 53.969 5.922 54.017 ;
     RECT  6.696 53.897 10.854 54.017 ;
     RECT  13.215 53.861 13.305 54.017 ;
     RECT  15.915 53.789 16.578 54.017 ;
     RECT  18.615 53.747 18.705 54.017 ;
     RECT  21.315 53.789 21.405 54.017 ;
     RECT  24.015 53.969 24.105 54.017 ;
     RECT  26.715 53.747 26.805 54.017 ;
     RECT  29.415 53.747 29.505 54.017 ;
     RECT  32.115 53.897 32.205 54.017 ;
     RECT  34.815 53.969 34.905 54.017 ;
     RECT  37.515 53.747 37.605 54.017 ;
     RECT  40.215 53.969 40.77 54.017 ;
     RECT  42.915 53.747 43.005 54.017 ;
     RECT  45.615 53.747 45.705 54.017 ;
     RECT  48.315 53.747 48.405 54.017 ;
     RECT  51.015 53.747 51.105 54.017 ;
     RECT  53.715 53.747 53.805 54.017 ;
     RECT  2.304 53.981 3.798 54.059 ;
     RECT  5.436 54.017 5.922 54.059 ;
     RECT  8.388 54.017 10.854 54.059 ;
     RECT  5.904 54.059 5.922 54.077 ;
     RECT  2.304 54.059 3.078 54.095 ;
     RECT  6.696 54.017 7.65 54.095 ;
     RECT  8.388 54.059 9.702 54.095 ;
     RECT  16.56 54.017 16.578 54.095 ;
     RECT  8.388 54.095 8.406 54.125 ;
     RECT  2.304 54.095 2.934 54.131 ;
     RECT  7.488 54.095 7.578 54.131 ;
     RECT  10.836 54.059 10.854 54.131 ;
     RECT  40.752 54.017 40.77 55.325 ;
     RECT  14.94 56.028 14.958 56.045 ;
    LAYER M4 ;
     RECT  0.156 2.232 0.181 2.304 ;
     RECT  0.156 2.328 0.181 2.4 ;
     RECT  0.156 2.424 0.181 2.496 ;
     RECT  0.156 2.52 0.181 2.592 ;
     RECT  0.156 2.616 0.181 2.688 ;
     RECT  0.156 2.712 0.181 2.784 ;
     RECT  0.156 2.808 0.181 2.88 ;
     RECT  0.156 2.904 0.181 2.976 ;
     RECT  0.156 3 0.181 3.072 ;
     RECT  0.156 3.096 0.181 3.168 ;
     RECT  0.156 3.192 0.181 3.264 ;
     RECT  0.156 3.288 0.181 3.36 ;
     RECT  0.156 3.384 0.181 3.456 ;
     RECT  0.156 3.48 0.181 3.552 ;
     RECT  0.156 3.576 0.181 3.648 ;
     RECT  0.156 3.672 0.181 3.744 ;
     RECT  0.156 3.768 0.181 3.888 ;
     RECT  0.156 3.912 0.181 3.984 ;
     RECT  0.156 4.008 0.181 4.08 ;
     RECT  0.156 4.104 0.181 4.176 ;
     RECT  0.156 4.2 0.181 4.272 ;
     RECT  0.156 4.296 0.181 4.368 ;
     RECT  0.156 4.392 0.181 4.464 ;
     RECT  0.156 4.488 0.181 4.56 ;
     RECT  0.156 4.584 0.181 4.656 ;
     RECT  0.156 4.68 0.181 4.752 ;
     RECT  0.156 4.776 0.181 4.848 ;
     RECT  0.156 4.872 0.181 4.944 ;
     RECT  0.156 4.968 0.181 5.04 ;
     RECT  0.156 5.064 0.181 5.136 ;
     RECT  0.156 5.16 0.181 5.232 ;
     RECT  0.156 5.256 0.181 5.328 ;
     RECT  0.156 5.352 0.181 5.424 ;
     RECT  0.156 5.448 0.181 5.52 ;
     RECT  0.156 5.544 0.181 5.616 ;
     RECT  0.156 5.64 0.181 5.712 ;
     RECT  0.156 5.736 0.181 5.808 ;
     RECT  0.156 5.832 0.181 5.904 ;
     RECT  0.156 5.928 0.181 6 ;
     RECT  0.156 6.024 0.181 6.096 ;
     RECT  0.156 6.12 0.181 6.192 ;
     RECT  0.156 6.216 0.181 6.288 ;
     RECT  0.156 6.312 0.181 6.384 ;
     RECT  0.156 6.408 0.181 6.48 ;
     RECT  0.156 6.504 0.181 6.576 ;
     RECT  0.156 6.6 0.181 6.672 ;
     RECT  0.156 6.696 0.181 6.768 ;
     RECT  0.156 6.792 0.181 6.864 ;
     RECT  0.156 6.888 0.181 6.96 ;
     RECT  0.156 6.984 0.181 7.056 ;
     RECT  0.156 7.08 0.181 7.152 ;
     RECT  0.156 7.176 0.181 7.248 ;
     RECT  0.156 7.272 0.181 7.344 ;
     RECT  0.156 7.368 0.181 7.44 ;
     RECT  0.156 7.464 0.181 7.536 ;
     RECT  0.156 7.56 0.181 7.632 ;
     RECT  0.156 7.656 0.181 7.728 ;
     RECT  0.156 7.752 0.181 7.824 ;
     RECT  0.156 7.848 0.181 7.92 ;
     RECT  0.156 7.944 0.181 8.016 ;
     RECT  0.156 8.04 0.181 8.112 ;
     RECT  0.156 8.136 0.181 8.208 ;
     RECT  0.156 8.232 0.181 8.304 ;
     RECT  0.156 8.328 0.181 8.4 ;
     RECT  0.156 8.424 0.181 8.496 ;
     RECT  0.156 8.52 0.181 8.592 ;
     RECT  0.156 8.616 0.181 8.688 ;
     RECT  0.156 8.712 0.181 8.784 ;
     RECT  0.156 8.808 0.181 8.88 ;
     RECT  0.156 8.904 0.181 8.976 ;
     RECT  0.156 9 0.181 9.072 ;
     RECT  0.156 9.096 0.181 9.168 ;
     RECT  0.156 9.192 0.181 9.264 ;
     RECT  0.156 9.288 0.181 9.36 ;
     RECT  0.156 9.384 0.181 9.456 ;
     RECT  0.156 9.48 0.181 9.552 ;
     RECT  0.156 9.576 0.181 9.648 ;
     RECT  0.156 9.672 0.181 9.744 ;
     RECT  0.156 9.768 0.181 9.84 ;
     RECT  0.156 9.864 0.181 9.936 ;
     RECT  0.156 9.96 0.181 10.032 ;
     RECT  0.156 10.056 0.181 10.128 ;
     RECT  0.156 10.152 0.181 10.224 ;
     RECT  0.156 10.248 0.181 10.368 ;
     RECT  0.156 10.392 0.181 10.464 ;
     RECT  0.156 10.488 0.181 10.56 ;
     RECT  0.156 10.584 0.181 10.656 ;
     RECT  0.156 10.68 0.181 10.752 ;
     RECT  0.156 10.776 0.181 10.848 ;
     RECT  0.156 10.872 0.181 10.944 ;
     RECT  0.156 10.968 0.181 11.04 ;
     RECT  0.156 11.064 0.181 11.136 ;
     RECT  0.156 11.16 0.181 11.232 ;
     RECT  0.156 11.256 0.181 11.328 ;
     RECT  0.156 11.352 0.181 11.424 ;
     RECT  0.156 11.448 0.181 11.52 ;
     RECT  0.156 11.544 0.181 11.616 ;
     RECT  0.156 11.64 0.181 11.712 ;
     RECT  0.156 11.736 0.181 11.808 ;
     RECT  0.156 11.832 0.181 11.904 ;
     RECT  0.156 11.928 0.181 12 ;
     RECT  0.156 12.024 0.181 12.096 ;
     RECT  0.156 12.12 0.181 12.192 ;
     RECT  0.156 12.216 0.181 12.288 ;
     RECT  0.156 12.312 0.181 12.384 ;
     RECT  0.156 12.408 0.181 12.48 ;
     RECT  0.156 12.504 0.181 12.576 ;
     RECT  0.156 12.6 0.181 12.672 ;
     RECT  0.156 12.696 0.181 12.768 ;
     RECT  0.156 12.792 0.181 12.864 ;
     RECT  0.156 12.888 0.181 12.96 ;
     RECT  0.156 12.984 0.181 13.056 ;
     RECT  0.156 13.08 0.181 13.152 ;
     RECT  0.156 13.176 0.181 13.248 ;
     RECT  0.156 13.272 0.181 13.344 ;
     RECT  0.156 13.368 0.181 13.44 ;
     RECT  0.156 13.464 0.181 13.536 ;
     RECT  0.156 13.56 0.181 13.632 ;
     RECT  0.156 13.656 0.181 13.728 ;
     RECT  0.156 13.752 0.181 13.824 ;
     RECT  0.156 13.848 0.181 13.92 ;
     RECT  0.156 13.944 0.181 14.016 ;
     RECT  0.156 14.04 0.181 14.112 ;
     RECT  0.156 14.136 0.181 14.208 ;
     RECT  0.156 14.232 0.181 14.304 ;
     RECT  0.156 14.328 0.181 14.4 ;
     RECT  0.156 14.424 0.181 14.496 ;
     RECT  0.156 14.52 0.181 14.592 ;
     RECT  0.156 14.616 0.181 14.688 ;
     RECT  0.156 14.712 0.181 14.784 ;
     RECT  0.156 14.808 0.181 14.88 ;
     RECT  0.156 14.904 0.181 14.976 ;
     RECT  0.156 15 0.181 15.072 ;
     RECT  0.156 15.096 0.181 15.168 ;
     RECT  0.156 15.192 0.181 15.264 ;
     RECT  0.156 15.288 0.181 15.36 ;
     RECT  0.156 15.384 0.181 15.456 ;
     RECT  0.156 15.48 0.181 15.552 ;
     RECT  0.156 15.576 0.181 15.648 ;
     RECT  0.156 15.672 0.181 15.744 ;
     RECT  0.156 15.768 0.181 15.84 ;
     RECT  0.156 15.864 0.181 15.936 ;
     RECT  0.156 15.96 0.181 16.032 ;
     RECT  0.156 16.056 0.181 16.128 ;
     RECT  0.156 16.152 0.181 16.224 ;
     RECT  0.156 16.248 0.181 16.32 ;
     RECT  0.156 16.344 0.181 16.416 ;
     RECT  0.156 16.44 0.181 16.512 ;
     RECT  0.156 16.536 0.181 16.608 ;
     RECT  0.156 16.632 0.181 16.704 ;
     RECT  0.156 16.728 0.181 16.848 ;
     RECT  0.156 16.872 0.181 16.944 ;
     RECT  0.156 16.968 0.181 17.04 ;
     RECT  0.156 17.064 0.181 17.136 ;
     RECT  0.156 17.16 0.181 17.232 ;
     RECT  0.156 17.256 0.181 17.328 ;
     RECT  0.156 17.352 0.181 17.424 ;
     RECT  0.156 17.448 0.181 17.52 ;
     RECT  0.156 17.544 0.181 17.616 ;
     RECT  0.156 17.64 0.181 17.712 ;
     RECT  0.156 17.736 0.181 17.808 ;
     RECT  0.156 17.832 0.181 17.904 ;
     RECT  0.156 17.928 0.181 18 ;
     RECT  0.156 18.024 0.181 18.096 ;
     RECT  0.156 18.12 0.181 18.192 ;
     RECT  0.156 18.216 0.181 18.288 ;
     RECT  0.156 18.312 0.181 18.384 ;
     RECT  0.156 18.408 0.181 18.48 ;
     RECT  0.156 18.504 0.181 18.576 ;
     RECT  0.156 18.6 0.181 18.672 ;
     RECT  0.156 18.696 0.181 18.768 ;
     RECT  0.156 18.792 0.181 18.864 ;
     RECT  0.156 18.888 0.181 18.96 ;
     RECT  0.156 18.984 0.181 19.056 ;
     RECT  0.156 19.08 0.181 19.152 ;
     RECT  0.156 19.176 0.181 19.248 ;
     RECT  0.156 19.272 0.181 19.344 ;
     RECT  0.156 19.368 0.181 19.44 ;
     RECT  0.156 19.464 0.181 19.536 ;
     RECT  0.156 19.56 0.181 19.632 ;
     RECT  0.156 19.656 0.181 19.728 ;
     RECT  0.156 19.752 0.181 19.824 ;
     RECT  0.156 19.848 0.181 19.92 ;
     RECT  0.156 19.944 0.181 20.016 ;
     RECT  0.156 20.04 0.181 20.112 ;
     RECT  0.156 20.136 0.181 20.208 ;
     RECT  0.156 20.232 0.181 20.304 ;
     RECT  0.156 20.328 0.181 20.4 ;
     RECT  0.156 20.424 0.181 20.496 ;
     RECT  0.156 20.52 0.181 20.592 ;
     RECT  0.156 20.616 0.181 20.688 ;
     RECT  0.156 20.712 0.181 20.784 ;
     RECT  0.156 20.808 0.181 20.88 ;
     RECT  0.156 20.904 0.181 20.976 ;
     RECT  0.156 21 0.181 21.072 ;
     RECT  0.156 21.096 0.181 21.168 ;
     RECT  0.156 21.192 0.181 21.264 ;
     RECT  0.156 21.288 0.181 21.36 ;
     RECT  0.156 21.384 0.181 21.456 ;
     RECT  0.156 21.48 0.181 21.552 ;
     RECT  0.156 21.576 0.181 21.648 ;
     RECT  0.156 21.672 0.181 21.744 ;
     RECT  0.156 21.768 0.181 21.84 ;
     RECT  0.156 21.864 0.181 21.936 ;
     RECT  0.156 21.96 0.181 22.032 ;
     RECT  0.156 22.056 0.181 22.128 ;
     RECT  0.156 22.152 0.181 22.224 ;
     RECT  0.156 22.248 0.181 22.32 ;
     RECT  0.156 22.344 0.181 22.416 ;
     RECT  0.156 22.44 0.181 22.512 ;
     RECT  0.156 22.536 0.181 22.608 ;
     RECT  0.156 22.632 0.181 22.704 ;
     RECT  0.156 22.728 0.181 22.8 ;
     RECT  0.156 22.824 0.181 22.896 ;
     RECT  0.156 22.92 0.181 22.992 ;
     RECT  0.156 23.016 0.181 23.088 ;
     RECT  0.156 23.112 0.181 23.184 ;
     RECT  0.156 23.208 0.181 23.328 ;
     RECT  0.156 23.352 0.181 23.424 ;
     RECT  0.156 23.448 0.181 23.52 ;
     RECT  0.156 23.544 0.181 23.616 ;
     RECT  0.156 23.64 0.181 23.712 ;
     RECT  0.156 23.736 0.181 23.808 ;
     RECT  0.156 23.832 0.181 23.904 ;
     RECT  0.156 23.928 0.181 24 ;
     RECT  0.156 24.024 0.181 24.096 ;
     RECT  0.156 24.12 0.181 24.192 ;
     RECT  0.156 24.216 0.181 24.288 ;
     RECT  0.156 24.312 0.181 24.384 ;
     RECT  0.156 24.408 0.181 24.48 ;
     RECT  0.156 24.504 0.181 24.576 ;
     RECT  0.156 24.6 0.181 24.672 ;
     RECT  0.156 24.696 0.181 24.768 ;
     RECT  0.156 24.792 0.181 24.864 ;
     RECT  0.156 24.888 0.181 24.96 ;
     RECT  0.156 24.984 0.181 25.056 ;
     RECT  0.156 25.08 0.181 25.152 ;
     RECT  0.156 25.176 0.181 25.248 ;
     RECT  0.156 25.272 0.181 25.344 ;
     RECT  0.156 25.368 0.181 25.44 ;
     RECT  0.156 25.464 0.181 25.536 ;
     RECT  0.156 25.56 0.181 25.632 ;
     RECT  0.156 25.656 0.181 25.728 ;
     RECT  0.156 25.752 0.181 25.824 ;
     RECT  0.156 25.848 0.181 25.92 ;
     RECT  0.156 25.944 0.181 26.016 ;
     RECT  0.156 26.04 0.181 26.112 ;
     RECT  0.156 26.136 0.181 26.208 ;
     RECT  0.156 26.232 0.181 26.304 ;
     RECT  0.156 26.328 0.181 26.4 ;
     RECT  0.156 26.424 0.181 26.496 ;
     RECT  0.156 26.52 0.181 26.592 ;
     RECT  0.156 26.616 0.181 26.688 ;
     RECT  0.156 26.712 0.181 26.784 ;
     RECT  0.156 26.808 0.181 26.88 ;
     RECT  0.156 26.904 0.181 26.976 ;
     RECT  0.156 27 0.181 27.072 ;
     RECT  0.156 27.096 0.181 27.168 ;
     RECT  0.156 27.192 0.181 27.264 ;
     RECT  0.156 27.288 0.181 27.36 ;
     RECT  0.156 27.384 0.181 27.456 ;
     RECT  0.156 27.48 0.181 27.552 ;
     RECT  0.156 27.576 0.181 27.648 ;
     RECT  0.156 27.672 0.181 27.744 ;
     RECT  0.156 27.768 0.181 27.84 ;
     RECT  0.156 27.864 0.181 27.936 ;
     RECT  0.156 27.96 0.181 28.032 ;
     RECT  0.156 28.056 0.181 28.128 ;
     RECT  0.156 28.152 0.181 28.224 ;
     RECT  0.156 28.248 0.181 28.32 ;
     RECT  0.156 28.344 0.181 28.416 ;
     RECT  0.156 28.44 0.181 28.512 ;
     RECT  0.156 28.536 0.181 28.608 ;
     RECT  0.156 28.632 0.181 28.704 ;
     RECT  0.156 28.728 0.181 28.8 ;
     RECT  0.156 28.824 0.181 28.896 ;
     RECT  0.156 28.92 0.181 28.992 ;
     RECT  0.156 29.016 0.181 29.088 ;
     RECT  0.156 29.112 0.181 29.184 ;
     RECT  0.156 29.208 0.181 29.28 ;
     RECT  0.156 29.304 0.181 29.376 ;
     RECT  0.156 29.4 0.181 29.472 ;
     RECT  0.156 29.496 0.181 29.568 ;
     RECT  0.156 29.592 0.181 29.664 ;
     RECT  0.156 29.688 0.181 29.808 ;
     RECT  0.156 29.832 0.181 29.904 ;
     RECT  0.156 29.928 0.181 30 ;
     RECT  0.156 30.024 0.181 30.096 ;
     RECT  0.156 30.12 0.181 30.192 ;
     RECT  0.156 30.216 0.181 30.288 ;
     RECT  0.156 30.312 0.181 30.384 ;
     RECT  0.156 30.408 0.181 30.48 ;
     RECT  0.156 30.504 0.181 30.576 ;
     RECT  0.156 30.6 0.181 30.672 ;
     RECT  0.156 30.696 0.181 30.768 ;
     RECT  0.156 30.792 0.181 30.864 ;
     RECT  0.156 30.888 0.181 30.96 ;
     RECT  0.156 30.984 0.181 31.056 ;
     RECT  0.156 31.08 0.181 31.152 ;
     RECT  0.156 31.176 0.181 31.248 ;
     RECT  0.156 31.272 0.181 31.344 ;
     RECT  0.156 31.368 0.181 31.44 ;
     RECT  0.156 31.464 0.181 31.536 ;
     RECT  0.156 31.56 0.181 31.632 ;
     RECT  0.156 31.656 0.181 31.728 ;
     RECT  0.156 31.752 0.181 31.824 ;
     RECT  0.156 31.848 0.181 31.92 ;
     RECT  0.156 31.944 0.181 32.016 ;
     RECT  0.156 32.04 0.181 32.112 ;
     RECT  0.156 32.136 0.181 32.208 ;
     RECT  0.156 32.232 0.181 32.304 ;
     RECT  0.156 32.328 0.181 32.4 ;
     RECT  0.156 32.424 0.181 32.496 ;
     RECT  0.156 32.52 0.181 32.592 ;
     RECT  0.156 32.616 0.181 32.688 ;
     RECT  0.156 32.712 0.181 32.784 ;
     RECT  0.156 32.808 0.181 32.88 ;
     RECT  0.156 32.904 0.181 32.976 ;
     RECT  0.156 33 0.181 33.072 ;
     RECT  0.156 33.096 0.181 33.168 ;
     RECT  0.156 33.192 0.181 33.264 ;
     RECT  0.156 33.288 0.181 33.36 ;
     RECT  0.156 33.384 0.181 33.456 ;
     RECT  0.156 33.48 0.181 33.552 ;
     RECT  0.156 33.576 0.181 33.648 ;
     RECT  0.156 33.672 0.181 33.744 ;
     RECT  0.156 33.768 0.181 33.84 ;
     RECT  0.156 33.864 0.181 33.936 ;
     RECT  0.156 33.96 0.181 34.032 ;
     RECT  0.156 34.056 0.181 34.128 ;
     RECT  0.156 34.152 0.181 34.224 ;
     RECT  0.156 34.248 0.181 34.32 ;
     RECT  0.156 34.344 0.181 34.416 ;
     RECT  0.156 34.44 0.181 34.512 ;
     RECT  0.156 34.536 0.181 34.608 ;
     RECT  0.156 34.632 0.181 34.704 ;
     RECT  0.156 34.728 0.181 34.8 ;
     RECT  0.156 34.824 0.181 34.896 ;
     RECT  0.156 34.92 0.181 34.992 ;
     RECT  0.156 35.016 0.181 35.088 ;
     RECT  0.156 35.112 0.181 35.184 ;
     RECT  0.156 35.208 0.181 35.28 ;
     RECT  0.156 35.304 0.181 35.376 ;
     RECT  0.156 35.4 0.181 35.472 ;
     RECT  0.156 35.496 0.181 35.568 ;
     RECT  0.156 35.592 0.181 35.664 ;
     RECT  0.156 35.688 0.181 35.76 ;
     RECT  0.156 35.784 0.181 35.856 ;
     RECT  0.156 35.88 0.181 35.952 ;
     RECT  0.156 35.976 0.181 36.048 ;
     RECT  0.156 36.072 0.181 36.144 ;
     RECT  0.156 36.168 0.181 36.288 ;
     RECT  0.156 36.312 0.181 36.384 ;
     RECT  0.156 36.408 0.181 36.48 ;
     RECT  0.156 36.504 0.181 36.576 ;
     RECT  0.156 36.6 0.181 36.672 ;
     RECT  0.156 36.696 0.181 36.768 ;
     RECT  0.156 36.792 0.181 36.864 ;
     RECT  0.156 36.888 0.181 36.96 ;
     RECT  0.156 36.984 0.181 37.056 ;
     RECT  0.156 37.08 0.181 37.152 ;
     RECT  0.156 37.176 0.181 37.248 ;
     RECT  0.156 37.272 0.181 37.344 ;
     RECT  0.156 37.368 0.181 37.44 ;
     RECT  0.156 37.464 0.181 37.536 ;
     RECT  0.156 37.56 0.181 37.632 ;
     RECT  0.156 37.656 0.181 37.728 ;
     RECT  0.156 37.752 0.181 37.824 ;
     RECT  0.156 37.848 0.181 37.92 ;
     RECT  0.156 37.944 0.181 38.016 ;
     RECT  0.156 38.04 0.181 38.112 ;
     RECT  0.156 38.136 0.181 38.208 ;
     RECT  0.156 38.232 0.181 38.304 ;
     RECT  0.156 38.328 0.181 38.4 ;
     RECT  0.156 38.424 0.181 38.496 ;
     RECT  0.156 38.52 0.181 38.592 ;
     RECT  0.156 38.616 0.181 38.688 ;
     RECT  0.156 38.712 0.181 38.784 ;
     RECT  0.156 38.808 0.181 38.88 ;
     RECT  0.156 38.904 0.181 38.976 ;
     RECT  0.156 39 0.181 39.072 ;
     RECT  0.156 39.096 0.181 39.168 ;
     RECT  0.156 39.192 0.181 39.264 ;
     RECT  0.156 39.288 0.181 39.36 ;
     RECT  0.156 39.384 0.181 39.456 ;
     RECT  0.156 39.48 0.181 39.552 ;
     RECT  0.156 39.576 0.181 39.648 ;
     RECT  0.156 39.672 0.181 39.744 ;
     RECT  0.156 39.768 0.181 39.84 ;
     RECT  0.156 39.864 0.181 39.936 ;
     RECT  0.156 39.96 0.181 40.032 ;
     RECT  0.156 40.056 0.181 40.128 ;
     RECT  0.156 40.152 0.181 40.224 ;
     RECT  0.156 40.248 0.181 40.32 ;
     RECT  0.156 40.344 0.181 40.416 ;
     RECT  0.156 40.44 0.181 40.512 ;
     RECT  0.156 40.536 0.181 40.608 ;
     RECT  0.156 40.632 0.181 40.704 ;
     RECT  0.156 40.728 0.181 40.8 ;
     RECT  0.156 40.824 0.181 40.896 ;
     RECT  0.156 40.92 0.181 40.992 ;
     RECT  0.156 41.016 0.181 41.088 ;
     RECT  0.156 41.112 0.181 41.184 ;
     RECT  0.156 41.208 0.181 41.28 ;
     RECT  0.156 41.304 0.181 41.376 ;
     RECT  0.156 41.4 0.181 41.472 ;
     RECT  0.156 41.496 0.181 41.568 ;
     RECT  0.156 41.592 0.181 41.664 ;
     RECT  0.156 41.688 0.181 41.76 ;
     RECT  0.156 41.784 0.181 41.856 ;
     RECT  0.156 41.88 0.181 41.952 ;
     RECT  0.156 41.976 0.181 42.048 ;
     RECT  0.156 42.072 0.181 42.144 ;
     RECT  0.156 42.168 0.181 42.24 ;
     RECT  0.156 42.264 0.181 42.336 ;
     RECT  0.156 42.36 0.181 42.432 ;
     RECT  0.156 42.456 0.181 42.528 ;
     RECT  0.156 42.552 0.181 42.624 ;
     RECT  0.156 42.648 0.181 42.768 ;
     RECT  0.156 42.792 0.181 42.864 ;
     RECT  0.156 42.888 0.181 42.96 ;
     RECT  0.156 42.984 0.181 43.056 ;
     RECT  0.156 43.08 0.181 43.152 ;
     RECT  0.156 43.176 0.181 43.248 ;
     RECT  0.156 43.272 0.181 43.344 ;
     RECT  0.156 43.368 0.181 43.44 ;
     RECT  0.156 43.464 0.181 43.536 ;
     RECT  0.156 43.56 0.181 43.632 ;
     RECT  0.156 43.656 0.181 43.728 ;
     RECT  0.156 43.752 0.181 43.824 ;
     RECT  0.156 43.848 0.181 43.92 ;
     RECT  0.156 43.944 0.181 44.016 ;
     RECT  0.156 44.04 0.181 44.112 ;
     RECT  0.156 44.136 0.181 44.208 ;
     RECT  0.156 44.232 0.181 44.304 ;
     RECT  0.156 44.328 0.181 44.4 ;
     RECT  0.156 44.424 0.181 44.496 ;
     RECT  0.156 44.52 0.181 44.592 ;
     RECT  0.156 44.616 0.181 44.688 ;
     RECT  0.156 44.712 0.181 44.784 ;
     RECT  0.156 44.808 0.181 44.88 ;
     RECT  0.156 44.904 0.181 44.976 ;
     RECT  0.156 45 0.181 45.072 ;
     RECT  0.156 45.096 0.181 45.168 ;
     RECT  0.156 45.192 0.181 45.264 ;
     RECT  0.156 45.288 0.181 45.36 ;
     RECT  0.156 45.384 0.181 45.456 ;
     RECT  0.156 45.48 0.181 45.552 ;
     RECT  0.156 45.576 0.181 45.648 ;
     RECT  0.156 45.672 0.181 45.744 ;
     RECT  0.156 45.768 0.181 45.84 ;
     RECT  0.156 45.864 0.181 45.936 ;
     RECT  0.156 45.96 0.181 46.032 ;
     RECT  0.156 46.056 0.181 46.128 ;
     RECT  0.156 46.152 0.181 46.224 ;
     RECT  0.156 46.248 0.181 46.32 ;
     RECT  0.156 46.344 0.181 46.416 ;
     RECT  0.156 46.44 0.181 46.512 ;
     RECT  0.156 46.536 0.181 46.608 ;
     RECT  0.156 46.632 0.181 46.704 ;
     RECT  0.156 46.728 0.181 46.8 ;
     RECT  0.156 46.824 0.181 46.896 ;
     RECT  0.156 46.92 0.181 46.992 ;
     RECT  0.156 47.016 0.181 47.088 ;
     RECT  0.156 47.112 0.181 47.184 ;
     RECT  0.156 47.208 0.181 47.28 ;
     RECT  0.156 47.304 0.181 47.376 ;
     RECT  0.156 47.4 0.181 47.472 ;
     RECT  0.156 47.496 0.181 47.568 ;
     RECT  0.156 47.592 0.181 47.664 ;
     RECT  0.156 47.688 0.181 47.76 ;
     RECT  0.156 47.784 0.181 47.856 ;
     RECT  0.156 47.88 0.181 47.952 ;
     RECT  0.156 47.976 0.181 48.048 ;
     RECT  0.156 48.072 0.181 48.144 ;
     RECT  0.156 48.168 0.181 48.24 ;
     RECT  0.156 48.264 0.181 48.336 ;
     RECT  0.156 48.36 0.181 48.432 ;
     RECT  0.156 48.456 0.181 48.528 ;
     RECT  0.156 48.552 0.181 48.624 ;
     RECT  0.156 48.648 0.181 48.72 ;
     RECT  0.156 48.744 0.181 48.816 ;
     RECT  0.156 48.84 0.181 48.912 ;
     RECT  0.156 48.936 0.181 49.008 ;
     RECT  0.156 49.032 0.181 49.104 ;
     RECT  0.156 49.128 0.181 49.248 ;
     RECT  0.156 49.272 0.181 49.344 ;
     RECT  0.156 49.368 0.181 49.44 ;
     RECT  0.156 49.464 0.181 49.536 ;
     RECT  0.156 49.56 0.181 49.632 ;
     RECT  0.156 49.656 0.181 49.728 ;
     RECT  0.156 49.752 0.181 49.824 ;
     RECT  0.156 49.848 0.181 49.92 ;
     RECT  0.156 49.944 0.181 50.016 ;
     RECT  0.156 50.04 0.181 50.112 ;
     RECT  0.156 50.136 0.181 50.208 ;
     RECT  0.156 50.232 0.181 50.304 ;
     RECT  0.156 50.328 0.181 50.4 ;
     RECT  0.156 50.424 0.181 50.496 ;
     RECT  0.156 50.52 0.181 50.592 ;
     RECT  0.156 50.616 0.181 50.688 ;
     RECT  0.156 50.712 0.181 50.784 ;
     RECT  0.156 50.808 0.181 50.88 ;
     RECT  0.156 50.904 0.181 50.976 ;
     RECT  0.156 51 0.181 51.072 ;
     RECT  0.156 51.096 0.181 51.168 ;
     RECT  0.156 51.192 0.181 51.264 ;
     RECT  0.156 51.288 0.181 51.36 ;
     RECT  0.156 51.384 0.181 51.456 ;
     RECT  0.156 51.48 0.181 51.552 ;
     RECT  0.156 51.576 0.181 51.648 ;
     RECT  0.156 51.672 0.181 51.744 ;
     RECT  0.156 51.768 0.181 51.84 ;
     RECT  0.156 51.864 0.181 51.936 ;
     RECT  0.156 51.96 0.181 52.032 ;
     RECT  0.156 52.056 0.181 52.128 ;
     RECT  0.156 52.152 0.181 52.224 ;
     RECT  0.156 52.248 0.181 52.32 ;
     RECT  0.156 52.344 0.181 52.416 ;
     RECT  0.156 52.44 0.181 52.512 ;
     RECT  0.156 52.536 0.181 52.608 ;
     RECT  0.156 52.632 0.181 52.704 ;
     RECT  0.156 52.728 0.181 52.8 ;
     RECT  0.156 52.824 0.181 52.896 ;
     RECT  0.156 52.92 0.181 52.992 ;
     RECT  0.156 53.016 0.181 53.088 ;
     RECT  0.156 53.112 0.181 53.184 ;
     RECT  0.156 53.208 0.181 53.28 ;
     RECT  0.156 53.304 0.181 53.376 ;
     RECT  0.156 53.4 0.181 53.472 ;
     RECT  0.156 53.496 0.181 53.568 ;
     RECT  0.156 53.592 0.181 53.664 ;
     RECT  0.156 53.688 0.181 53.76 ;
     RECT  0.156 53.784 0.181 53.856 ;
     RECT  0.156 53.88 0.181 53.952 ;
     RECT  0.181 2.112 0.467 2.208 ;
     RECT  0.192 2.208 0.467 2.232 ;
     RECT  0.181 2.232 0.467 2.304 ;
     RECT  0.192 2.304 0.467 2.328 ;
     RECT  0.181 2.328 0.467 2.4 ;
     RECT  0.192 2.4 0.467 2.424 ;
     RECT  0.181 2.424 0.467 2.496 ;
     RECT  0.192 2.496 0.467 2.52 ;
     RECT  0.181 2.52 0.467 2.592 ;
     RECT  0.192 2.592 0.467 2.616 ;
     RECT  0.181 2.616 0.467 2.688 ;
     RECT  0.192 2.688 0.467 2.712 ;
     RECT  0.181 2.712 0.467 2.784 ;
     RECT  0.192 2.784 0.467 2.808 ;
     RECT  0.181 2.808 0.467 2.88 ;
     RECT  0.192 2.88 0.467 2.904 ;
     RECT  0.181 2.904 0.467 2.976 ;
     RECT  0.192 2.976 0.467 3 ;
     RECT  0.181 3 0.467 3.072 ;
     RECT  0.192 3.072 0.467 3.096 ;
     RECT  0.181 3.096 0.467 3.168 ;
     RECT  0.192 3.168 0.467 3.192 ;
     RECT  0.181 3.192 0.467 3.264 ;
     RECT  0.192 3.264 0.467 3.288 ;
     RECT  0.181 3.288 0.467 3.36 ;
     RECT  0.192 3.36 0.467 3.384 ;
     RECT  0.181 3.384 0.467 3.456 ;
     RECT  0.192 3.456 0.467 3.48 ;
     RECT  0.181 3.48 0.467 3.552 ;
     RECT  0.192 3.552 0.467 3.576 ;
     RECT  0.181 3.576 0.467 3.648 ;
     RECT  0.192 3.648 0.467 3.672 ;
     RECT  0.181 3.672 0.467 3.744 ;
     RECT  0.192 3.744 0.467 3.768 ;
     RECT  0.181 3.768 0.467 3.888 ;
     RECT  0.192 3.888 0.467 3.912 ;
     RECT  0.181 3.912 0.467 3.984 ;
     RECT  0.192 3.984 0.467 4.008 ;
     RECT  0.181 4.008 0.467 4.08 ;
     RECT  0.192 4.08 0.467 4.104 ;
     RECT  0.181 4.104 0.467 4.176 ;
     RECT  0.192 4.176 0.467 4.2 ;
     RECT  0.181 4.2 0.467 4.272 ;
     RECT  0.192 4.272 0.467 4.296 ;
     RECT  0.181 4.296 0.467 4.368 ;
     RECT  0.192 4.368 0.467 4.392 ;
     RECT  0.181 4.392 0.467 4.464 ;
     RECT  0.192 4.464 0.467 4.488 ;
     RECT  0.181 4.488 0.467 4.56 ;
     RECT  0.192 4.56 0.467 4.584 ;
     RECT  0.181 4.584 0.467 4.656 ;
     RECT  0.192 4.656 0.467 4.68 ;
     RECT  0.181 4.68 0.467 4.752 ;
     RECT  0.192 4.752 0.467 4.776 ;
     RECT  0.181 4.776 0.467 4.848 ;
     RECT  0.192 4.848 0.467 4.872 ;
     RECT  0.181 4.872 0.467 4.944 ;
     RECT  0.192 4.944 0.467 4.968 ;
     RECT  0.181 4.968 0.467 5.04 ;
     RECT  0.192 5.04 0.467 5.064 ;
     RECT  0.181 5.064 0.467 5.136 ;
     RECT  0.192 5.136 0.467 5.16 ;
     RECT  0.181 5.16 0.467 5.232 ;
     RECT  0.192 5.232 0.467 5.256 ;
     RECT  0.181 5.256 0.467 5.328 ;
     RECT  0.192 5.328 0.467 5.352 ;
     RECT  0.181 5.352 0.467 5.424 ;
     RECT  0.192 5.424 0.467 5.448 ;
     RECT  0.181 5.448 0.467 5.52 ;
     RECT  0.192 5.52 0.467 5.544 ;
     RECT  0.181 5.544 0.467 5.616 ;
     RECT  0.192 5.616 0.467 5.64 ;
     RECT  0.181 5.64 0.467 5.712 ;
     RECT  0.192 5.712 0.467 5.736 ;
     RECT  0.181 5.736 0.467 5.808 ;
     RECT  0.192 5.808 0.467 5.832 ;
     RECT  0.181 5.832 0.467 5.904 ;
     RECT  0.192 5.904 0.467 5.928 ;
     RECT  0.181 5.928 0.467 6 ;
     RECT  0.192 6 0.467 6.024 ;
     RECT  0.181 6.024 0.467 6.096 ;
     RECT  0.192 6.096 0.467 6.12 ;
     RECT  0.181 6.12 0.467 6.192 ;
     RECT  0.192 6.192 0.467 6.216 ;
     RECT  0.181 6.216 0.467 6.288 ;
     RECT  0.192 6.288 0.467 6.312 ;
     RECT  0.181 6.312 0.467 6.384 ;
     RECT  0.192 6.384 0.467 6.408 ;
     RECT  0.181 6.408 0.467 6.48 ;
     RECT  0.192 6.48 0.467 6.504 ;
     RECT  0.181 6.504 0.467 6.576 ;
     RECT  0.192 6.576 0.467 6.6 ;
     RECT  0.181 6.6 0.467 6.672 ;
     RECT  0.192 6.672 0.467 6.696 ;
     RECT  0.181 6.696 0.467 6.768 ;
     RECT  0.192 6.768 0.467 6.792 ;
     RECT  0.181 6.792 0.467 6.864 ;
     RECT  0.192 6.864 0.467 6.888 ;
     RECT  0.181 6.888 0.467 6.96 ;
     RECT  0.192 6.96 0.467 6.984 ;
     RECT  0.181 6.984 0.467 7.056 ;
     RECT  0.192 7.056 0.467 7.08 ;
     RECT  0.181 7.08 0.467 7.152 ;
     RECT  0.192 7.152 0.467 7.176 ;
     RECT  0.181 7.176 0.467 7.248 ;
     RECT  0.192 7.248 0.467 7.272 ;
     RECT  0.181 7.272 0.467 7.344 ;
     RECT  0.192 7.344 0.467 7.368 ;
     RECT  0.181 7.368 0.467 7.44 ;
     RECT  0.192 7.44 0.467 7.464 ;
     RECT  0.181 7.464 0.467 7.536 ;
     RECT  0.192 7.536 0.467 7.56 ;
     RECT  0.181 7.56 0.467 7.632 ;
     RECT  0.192 7.632 0.467 7.656 ;
     RECT  0.181 7.656 0.467 7.728 ;
     RECT  0.192 7.728 0.467 7.752 ;
     RECT  0.181 7.752 0.467 7.824 ;
     RECT  0.192 7.824 0.467 7.848 ;
     RECT  0.181 7.848 0.467 7.92 ;
     RECT  0.192 7.92 0.467 7.944 ;
     RECT  0.181 7.944 0.467 8.016 ;
     RECT  0.192 8.016 0.467 8.04 ;
     RECT  0.181 8.04 0.467 8.112 ;
     RECT  0.192 8.112 0.467 8.136 ;
     RECT  0.181 8.136 0.467 8.208 ;
     RECT  0.192 8.208 0.467 8.232 ;
     RECT  0.181 8.232 0.467 8.304 ;
     RECT  0.192 8.304 0.467 8.328 ;
     RECT  0.181 8.328 0.467 8.4 ;
     RECT  0.192 8.4 0.467 8.424 ;
     RECT  0.181 8.424 0.467 8.496 ;
     RECT  0.192 8.496 0.467 8.52 ;
     RECT  0.181 8.52 0.467 8.592 ;
     RECT  0.192 8.592 0.467 8.616 ;
     RECT  0.181 8.616 0.467 8.688 ;
     RECT  0.192 8.688 0.467 8.712 ;
     RECT  0.181 8.712 0.467 8.784 ;
     RECT  0.192 8.784 0.467 8.808 ;
     RECT  0.181 8.808 0.467 8.88 ;
     RECT  0.192 8.88 0.467 8.904 ;
     RECT  0.181 8.904 0.467 8.976 ;
     RECT  0.192 8.976 0.467 9 ;
     RECT  0.181 9 0.467 9.072 ;
     RECT  0.192 9.072 0.467 9.096 ;
     RECT  0.181 9.096 0.467 9.168 ;
     RECT  0.192 9.168 0.467 9.192 ;
     RECT  0.181 9.192 0.467 9.264 ;
     RECT  0.192 9.264 0.467 9.288 ;
     RECT  0.181 9.288 0.467 9.36 ;
     RECT  0.192 9.36 0.467 9.384 ;
     RECT  0.181 9.384 0.467 9.456 ;
     RECT  0.192 9.456 0.467 9.48 ;
     RECT  0.181 9.48 0.467 9.552 ;
     RECT  0.192 9.552 0.467 9.576 ;
     RECT  0.181 9.576 0.467 9.648 ;
     RECT  0.192 9.648 0.467 9.672 ;
     RECT  0.181 9.672 0.467 9.744 ;
     RECT  0.192 9.744 0.467 9.768 ;
     RECT  0.181 9.768 0.467 9.84 ;
     RECT  0.192 9.84 0.467 9.864 ;
     RECT  0.181 9.864 0.467 9.936 ;
     RECT  0.192 9.936 0.467 9.96 ;
     RECT  0.181 9.96 0.467 10.032 ;
     RECT  0.192 10.032 0.467 10.056 ;
     RECT  0.181 10.056 0.467 10.128 ;
     RECT  0.192 10.128 0.467 10.152 ;
     RECT  0.181 10.152 0.467 10.224 ;
     RECT  0.192 10.224 0.467 10.248 ;
     RECT  0.181 10.248 0.467 10.368 ;
     RECT  0.192 10.368 0.467 10.392 ;
     RECT  0.181 10.392 0.467 10.464 ;
     RECT  0.192 10.464 0.467 10.488 ;
     RECT  0.181 10.488 0.467 10.56 ;
     RECT  0.192 10.56 0.467 10.584 ;
     RECT  0.181 10.584 0.467 10.656 ;
     RECT  0.192 10.656 0.467 10.68 ;
     RECT  0.181 10.68 0.467 10.752 ;
     RECT  0.192 10.752 0.467 10.776 ;
     RECT  0.181 10.776 0.467 10.848 ;
     RECT  0.192 10.848 0.467 10.872 ;
     RECT  0.181 10.872 0.467 10.944 ;
     RECT  0.192 10.944 0.467 10.968 ;
     RECT  0.181 10.968 0.467 11.04 ;
     RECT  0.192 11.04 0.467 11.064 ;
     RECT  0.181 11.064 0.467 11.136 ;
     RECT  0.192 11.136 0.467 11.16 ;
     RECT  0.181 11.16 0.467 11.232 ;
     RECT  0.192 11.232 0.467 11.256 ;
     RECT  0.181 11.256 0.467 11.328 ;
     RECT  0.192 11.328 0.467 11.352 ;
     RECT  0.181 11.352 0.467 11.424 ;
     RECT  0.192 11.424 0.467 11.448 ;
     RECT  0.181 11.448 0.467 11.52 ;
     RECT  0.192 11.52 0.467 11.544 ;
     RECT  0.181 11.544 0.467 11.616 ;
     RECT  0.192 11.616 0.467 11.64 ;
     RECT  0.181 11.64 0.467 11.712 ;
     RECT  0.192 11.712 0.467 11.736 ;
     RECT  0.181 11.736 0.467 11.808 ;
     RECT  0.192 11.808 0.467 11.832 ;
     RECT  0.181 11.832 0.467 11.904 ;
     RECT  0.192 11.904 0.467 11.928 ;
     RECT  0.181 11.928 0.467 12 ;
     RECT  0.192 12 0.467 12.024 ;
     RECT  0.181 12.024 0.467 12.096 ;
     RECT  0.192 12.096 0.467 12.12 ;
     RECT  0.181 12.12 0.467 12.192 ;
     RECT  0.192 12.192 0.467 12.216 ;
     RECT  0.181 12.216 0.467 12.288 ;
     RECT  0.192 12.288 0.467 12.312 ;
     RECT  0.181 12.312 0.467 12.384 ;
     RECT  0.192 12.384 0.467 12.408 ;
     RECT  0.181 12.408 0.467 12.48 ;
     RECT  0.192 12.48 0.467 12.504 ;
     RECT  0.181 12.504 0.467 12.576 ;
     RECT  0.192 12.576 0.467 12.6 ;
     RECT  0.181 12.6 0.467 12.672 ;
     RECT  0.192 12.672 0.467 12.696 ;
     RECT  0.181 12.696 0.467 12.768 ;
     RECT  0.192 12.768 0.467 12.792 ;
     RECT  0.181 12.792 0.467 12.864 ;
     RECT  0.192 12.864 0.467 12.888 ;
     RECT  0.181 12.888 0.467 12.96 ;
     RECT  0.192 12.96 0.467 12.984 ;
     RECT  0.181 12.984 0.467 13.056 ;
     RECT  0.192 13.056 0.467 13.08 ;
     RECT  0.181 13.08 0.467 13.152 ;
     RECT  0.192 13.152 0.467 13.176 ;
     RECT  0.181 13.176 0.467 13.248 ;
     RECT  0.192 13.248 0.467 13.272 ;
     RECT  0.181 13.272 0.467 13.344 ;
     RECT  0.192 13.344 0.467 13.368 ;
     RECT  0.181 13.368 0.467 13.44 ;
     RECT  0.192 13.44 0.467 13.464 ;
     RECT  0.181 13.464 0.467 13.536 ;
     RECT  0.192 13.536 0.467 13.56 ;
     RECT  0.181 13.56 0.467 13.632 ;
     RECT  0.192 13.632 0.467 13.656 ;
     RECT  0.181 13.656 0.467 13.728 ;
     RECT  0.192 13.728 0.467 13.752 ;
     RECT  0.181 13.752 0.467 13.824 ;
     RECT  0.192 13.824 0.467 13.848 ;
     RECT  0.181 13.848 0.467 13.92 ;
     RECT  0.192 13.92 0.467 13.944 ;
     RECT  0.181 13.944 0.467 14.016 ;
     RECT  0.192 14.016 0.467 14.04 ;
     RECT  0.181 14.04 0.467 14.112 ;
     RECT  0.192 14.112 0.467 14.136 ;
     RECT  0.181 14.136 0.467 14.208 ;
     RECT  0.192 14.208 0.467 14.232 ;
     RECT  0.181 14.232 0.467 14.304 ;
     RECT  0.192 14.304 0.467 14.328 ;
     RECT  0.181 14.328 0.467 14.4 ;
     RECT  0.192 14.4 0.467 14.424 ;
     RECT  0.181 14.424 0.467 14.496 ;
     RECT  0.192 14.496 0.467 14.52 ;
     RECT  0.181 14.52 0.467 14.592 ;
     RECT  0.192 14.592 0.467 14.616 ;
     RECT  0.181 14.616 0.467 14.688 ;
     RECT  0.192 14.688 0.467 14.712 ;
     RECT  0.181 14.712 0.467 14.784 ;
     RECT  0.192 14.784 0.467 14.808 ;
     RECT  0.181 14.808 0.467 14.88 ;
     RECT  0.192 14.88 0.467 14.904 ;
     RECT  0.181 14.904 0.467 14.976 ;
     RECT  0.192 14.976 0.467 15 ;
     RECT  0.181 15 0.467 15.072 ;
     RECT  0.192 15.072 0.467 15.096 ;
     RECT  0.181 15.096 0.467 15.168 ;
     RECT  0.192 15.168 0.467 15.192 ;
     RECT  0.181 15.192 0.467 15.264 ;
     RECT  0.192 15.264 0.467 15.288 ;
     RECT  0.181 15.288 0.467 15.36 ;
     RECT  0.192 15.36 0.467 15.384 ;
     RECT  0.181 15.384 0.467 15.456 ;
     RECT  0.192 15.456 0.467 15.48 ;
     RECT  0.181 15.48 0.467 15.552 ;
     RECT  0.192 15.552 0.467 15.576 ;
     RECT  0.181 15.576 0.467 15.648 ;
     RECT  0.192 15.648 0.467 15.672 ;
     RECT  0.181 15.672 0.467 15.744 ;
     RECT  0.192 15.744 0.467 15.768 ;
     RECT  0.181 15.768 0.467 15.84 ;
     RECT  0.192 15.84 0.467 15.864 ;
     RECT  0.181 15.864 0.467 15.936 ;
     RECT  0.192 15.936 0.467 15.96 ;
     RECT  0.181 15.96 0.467 16.032 ;
     RECT  0.192 16.032 0.467 16.056 ;
     RECT  0.181 16.056 0.467 16.128 ;
     RECT  0.192 16.128 0.467 16.152 ;
     RECT  0.181 16.152 0.467 16.224 ;
     RECT  0.192 16.224 0.467 16.248 ;
     RECT  0.181 16.248 0.467 16.32 ;
     RECT  0.192 16.32 0.467 16.344 ;
     RECT  0.181 16.344 0.467 16.416 ;
     RECT  0.192 16.416 0.467 16.44 ;
     RECT  0.181 16.44 0.467 16.512 ;
     RECT  0.192 16.512 0.467 16.536 ;
     RECT  0.181 16.536 0.467 16.608 ;
     RECT  0.192 16.608 0.467 16.632 ;
     RECT  0.181 16.632 0.467 16.704 ;
     RECT  0.192 16.704 0.467 16.728 ;
     RECT  0.181 16.728 0.467 16.848 ;
     RECT  0.192 16.848 0.467 16.872 ;
     RECT  0.181 16.872 0.467 16.944 ;
     RECT  0.192 16.944 0.467 16.968 ;
     RECT  0.181 16.968 0.467 17.04 ;
     RECT  0.192 17.04 0.467 17.064 ;
     RECT  0.181 17.064 0.467 17.136 ;
     RECT  0.192 17.136 0.467 17.16 ;
     RECT  0.181 17.16 0.467 17.232 ;
     RECT  0.192 17.232 0.467 17.256 ;
     RECT  0.181 17.256 0.467 17.328 ;
     RECT  0.192 17.328 0.467 17.352 ;
     RECT  0.181 17.352 0.467 17.424 ;
     RECT  0.192 17.424 0.467 17.448 ;
     RECT  0.181 17.448 0.467 17.52 ;
     RECT  0.192 17.52 0.467 17.544 ;
     RECT  0.181 17.544 0.467 17.616 ;
     RECT  0.192 17.616 0.467 17.64 ;
     RECT  0.181 17.64 0.467 17.712 ;
     RECT  0.192 17.712 0.467 17.736 ;
     RECT  0.181 17.736 0.467 17.808 ;
     RECT  0.192 17.808 0.467 17.832 ;
     RECT  0.181 17.832 0.467 17.904 ;
     RECT  0.192 17.904 0.467 17.928 ;
     RECT  0.181 17.928 0.467 18 ;
     RECT  0.192 18 0.467 18.024 ;
     RECT  0.181 18.024 0.467 18.096 ;
     RECT  0.192 18.096 0.467 18.12 ;
     RECT  0.181 18.12 0.467 18.192 ;
     RECT  0.192 18.192 0.467 18.216 ;
     RECT  0.181 18.216 0.467 18.288 ;
     RECT  0.192 18.288 0.467 18.312 ;
     RECT  0.181 18.312 0.467 18.384 ;
     RECT  0.192 18.384 0.467 18.408 ;
     RECT  0.181 18.408 0.467 18.48 ;
     RECT  0.192 18.48 0.467 18.504 ;
     RECT  0.181 18.504 0.467 18.576 ;
     RECT  0.192 18.576 0.467 18.6 ;
     RECT  0.181 18.6 0.467 18.672 ;
     RECT  0.192 18.672 0.467 18.696 ;
     RECT  0.181 18.696 0.467 18.768 ;
     RECT  0.192 18.768 0.467 18.792 ;
     RECT  0.181 18.792 0.467 18.864 ;
     RECT  0.192 18.864 0.467 18.888 ;
     RECT  0.181 18.888 0.467 18.96 ;
     RECT  0.192 18.96 0.467 18.984 ;
     RECT  0.181 18.984 0.467 19.056 ;
     RECT  0.192 19.056 0.467 19.08 ;
     RECT  0.181 19.08 0.467 19.152 ;
     RECT  0.192 19.152 0.467 19.176 ;
     RECT  0.181 19.176 0.467 19.248 ;
     RECT  0.192 19.248 0.467 19.272 ;
     RECT  0.181 19.272 0.467 19.344 ;
     RECT  0.192 19.344 0.467 19.368 ;
     RECT  0.181 19.368 0.467 19.44 ;
     RECT  0.192 19.44 0.467 19.464 ;
     RECT  0.181 19.464 0.467 19.536 ;
     RECT  0.192 19.536 0.467 19.56 ;
     RECT  0.181 19.56 0.467 19.632 ;
     RECT  0.192 19.632 0.467 19.656 ;
     RECT  0.181 19.656 0.467 19.728 ;
     RECT  0.192 19.728 0.467 19.752 ;
     RECT  0.181 19.752 0.467 19.824 ;
     RECT  0.192 19.824 0.467 19.848 ;
     RECT  0.181 19.848 0.467 19.92 ;
     RECT  0.192 19.92 0.467 19.944 ;
     RECT  0.181 19.944 0.467 20.016 ;
     RECT  0.192 20.016 0.467 20.04 ;
     RECT  0.181 20.04 0.467 20.112 ;
     RECT  0.192 20.112 0.467 20.136 ;
     RECT  0.181 20.136 0.467 20.208 ;
     RECT  0.192 20.208 0.467 20.232 ;
     RECT  0.181 20.232 0.467 20.304 ;
     RECT  0.192 20.304 0.467 20.328 ;
     RECT  0.181 20.328 0.467 20.4 ;
     RECT  0.192 20.4 0.467 20.424 ;
     RECT  0.181 20.424 0.467 20.496 ;
     RECT  0.192 20.496 0.467 20.52 ;
     RECT  0.181 20.52 0.467 20.592 ;
     RECT  0.192 20.592 0.467 20.616 ;
     RECT  0.181 20.616 0.467 20.688 ;
     RECT  0.192 20.688 0.467 20.712 ;
     RECT  0.181 20.712 0.467 20.784 ;
     RECT  0.192 20.784 0.467 20.808 ;
     RECT  0.181 20.808 0.467 20.88 ;
     RECT  0.192 20.88 0.467 20.904 ;
     RECT  0.181 20.904 0.467 20.976 ;
     RECT  0.192 20.976 0.467 21 ;
     RECT  0.181 21 0.467 21.072 ;
     RECT  0.192 21.072 0.467 21.096 ;
     RECT  0.181 21.096 0.467 21.168 ;
     RECT  0.192 21.168 0.467 21.192 ;
     RECT  0.181 21.192 0.467 21.264 ;
     RECT  0.192 21.264 0.467 21.288 ;
     RECT  0.181 21.288 0.467 21.36 ;
     RECT  0.192 21.36 0.467 21.384 ;
     RECT  0.181 21.384 0.467 21.456 ;
     RECT  0.192 21.456 0.467 21.48 ;
     RECT  0.181 21.48 0.467 21.552 ;
     RECT  0.192 21.552 0.467 21.576 ;
     RECT  0.181 21.576 0.467 21.648 ;
     RECT  0.192 21.648 0.467 21.672 ;
     RECT  0.181 21.672 0.467 21.744 ;
     RECT  0.192 21.744 0.467 21.768 ;
     RECT  0.181 21.768 0.467 21.84 ;
     RECT  0.192 21.84 0.467 21.864 ;
     RECT  0.181 21.864 0.467 21.936 ;
     RECT  0.192 21.936 0.467 21.96 ;
     RECT  0.181 21.96 0.467 22.032 ;
     RECT  0.192 22.032 0.467 22.056 ;
     RECT  0.181 22.056 0.467 22.128 ;
     RECT  0.192 22.128 0.467 22.152 ;
     RECT  0.181 22.152 0.467 22.224 ;
     RECT  0.192 22.224 0.467 22.248 ;
     RECT  0.181 22.248 0.467 22.32 ;
     RECT  0.192 22.32 0.467 22.344 ;
     RECT  0.181 22.344 0.467 22.416 ;
     RECT  0.192 22.416 0.467 22.44 ;
     RECT  0.181 22.44 0.467 22.512 ;
     RECT  0.192 22.512 0.467 22.536 ;
     RECT  0.181 22.536 0.467 22.608 ;
     RECT  0.192 22.608 0.467 22.632 ;
     RECT  0.181 22.632 0.467 22.704 ;
     RECT  0.192 22.704 0.467 22.728 ;
     RECT  0.181 22.728 0.467 22.8 ;
     RECT  0.192 22.8 0.467 22.824 ;
     RECT  0.181 22.824 0.467 22.896 ;
     RECT  0.192 22.896 0.467 22.92 ;
     RECT  0.181 22.92 0.467 22.992 ;
     RECT  0.192 22.992 0.467 23.016 ;
     RECT  0.181 23.016 0.467 23.088 ;
     RECT  0.192 23.088 0.467 23.112 ;
     RECT  0.181 23.112 0.467 23.184 ;
     RECT  0.192 23.184 0.467 23.208 ;
     RECT  0.181 23.208 0.467 23.328 ;
     RECT  0.192 23.328 0.467 23.352 ;
     RECT  0.181 23.352 0.467 23.424 ;
     RECT  0.192 23.424 0.467 23.448 ;
     RECT  0.181 23.448 0.467 23.52 ;
     RECT  0.192 23.52 0.467 23.544 ;
     RECT  0.181 23.544 0.467 23.616 ;
     RECT  0.192 23.616 0.467 23.64 ;
     RECT  0.181 23.64 0.467 23.712 ;
     RECT  0.192 23.712 0.467 23.736 ;
     RECT  0.181 23.736 0.467 23.808 ;
     RECT  0.192 23.808 0.467 23.832 ;
     RECT  0.181 23.832 0.467 23.904 ;
     RECT  0.192 23.904 0.467 23.928 ;
     RECT  0.181 23.928 0.467 24 ;
     RECT  0.192 24 0.467 24.024 ;
     RECT  0.181 24.024 0.467 24.096 ;
     RECT  0.192 24.096 0.467 24.12 ;
     RECT  0.181 24.12 0.467 24.192 ;
     RECT  0.192 24.192 0.467 24.216 ;
     RECT  0.181 24.216 0.467 24.288 ;
     RECT  0.192 24.288 0.467 24.312 ;
     RECT  0.181 24.312 0.467 24.384 ;
     RECT  0.192 24.384 0.467 24.408 ;
     RECT  0.181 24.408 0.467 24.48 ;
     RECT  0.192 24.48 0.467 24.504 ;
     RECT  0.181 24.504 0.467 24.576 ;
     RECT  0.192 24.576 0.467 24.6 ;
     RECT  0.181 24.6 0.467 24.672 ;
     RECT  0.192 24.672 0.467 24.696 ;
     RECT  0.181 24.696 0.467 24.768 ;
     RECT  0.192 24.768 0.467 24.792 ;
     RECT  0.181 24.792 0.467 24.864 ;
     RECT  0.192 24.864 0.467 24.888 ;
     RECT  0.181 24.888 0.467 24.96 ;
     RECT  0.192 24.96 0.467 24.984 ;
     RECT  0.181 24.984 0.467 25.056 ;
     RECT  0.192 25.056 0.467 25.08 ;
     RECT  0.181 25.08 0.467 25.152 ;
     RECT  0.192 25.152 0.467 25.176 ;
     RECT  0.181 25.176 0.467 25.248 ;
     RECT  0.192 25.248 0.467 25.272 ;
     RECT  0.181 25.272 0.467 25.344 ;
     RECT  0.192 25.344 0.467 25.368 ;
     RECT  0.181 25.368 0.467 25.44 ;
     RECT  0.192 25.44 0.467 25.464 ;
     RECT  0.181 25.464 0.467 25.536 ;
     RECT  0.192 25.536 0.467 25.56 ;
     RECT  0.181 25.56 0.467 25.632 ;
     RECT  0.192 25.632 0.467 25.656 ;
     RECT  0.181 25.656 0.467 25.728 ;
     RECT  0.192 25.728 0.467 25.752 ;
     RECT  0.181 25.752 0.467 25.824 ;
     RECT  0.192 25.824 0.467 25.848 ;
     RECT  0.181 25.848 0.467 25.92 ;
     RECT  0.192 25.92 0.467 25.944 ;
     RECT  0.181 25.944 0.467 26.016 ;
     RECT  0.192 26.016 0.467 26.04 ;
     RECT  0.181 26.04 0.467 26.112 ;
     RECT  0.192 26.112 0.467 26.136 ;
     RECT  0.181 26.136 0.467 26.208 ;
     RECT  0.192 26.208 0.467 26.232 ;
     RECT  0.181 26.232 0.467 26.304 ;
     RECT  0.192 26.304 0.467 26.328 ;
     RECT  0.181 26.328 0.467 26.4 ;
     RECT  0.192 26.4 0.467 26.424 ;
     RECT  0.181 26.424 0.467 26.496 ;
     RECT  0.192 26.496 0.467 26.52 ;
     RECT  0.181 26.52 0.467 26.592 ;
     RECT  0.192 26.592 0.467 26.616 ;
     RECT  0.181 26.616 0.467 26.688 ;
     RECT  0.192 26.688 0.467 26.712 ;
     RECT  0.181 26.712 0.467 26.784 ;
     RECT  0.192 26.784 0.467 26.808 ;
     RECT  0.181 26.808 0.467 26.88 ;
     RECT  0.192 26.88 0.467 26.904 ;
     RECT  0.181 26.904 0.467 26.976 ;
     RECT  0.192 26.976 0.467 27 ;
     RECT  0.181 27 0.467 27.072 ;
     RECT  0.192 27.072 0.467 27.096 ;
     RECT  0.181 27.096 0.467 27.168 ;
     RECT  0.192 27.168 0.467 27.192 ;
     RECT  0.181 27.192 0.467 27.264 ;
     RECT  0.192 27.264 0.467 27.288 ;
     RECT  0.181 27.288 0.467 27.36 ;
     RECT  0.192 27.36 0.467 27.384 ;
     RECT  0.181 27.384 0.467 27.456 ;
     RECT  0.192 27.456 0.467 27.48 ;
     RECT  0.181 27.48 0.467 27.552 ;
     RECT  0.192 27.552 0.467 27.576 ;
     RECT  0.181 27.576 0.467 27.648 ;
     RECT  0.192 27.648 0.467 27.672 ;
     RECT  0.181 27.672 0.467 27.744 ;
     RECT  0.192 27.744 0.467 27.768 ;
     RECT  0.181 27.768 0.467 27.84 ;
     RECT  0.192 27.84 0.467 27.864 ;
     RECT  0.181 27.864 0.467 27.936 ;
     RECT  0.192 27.936 0.467 27.96 ;
     RECT  0.181 27.96 0.467 28.032 ;
     RECT  0.192 28.032 0.467 28.056 ;
     RECT  0.181 28.056 0.467 28.128 ;
     RECT  0.192 28.128 0.467 28.152 ;
     RECT  0.181 28.152 0.467 28.224 ;
     RECT  0.192 28.224 0.467 28.248 ;
     RECT  0.181 28.248 0.467 28.32 ;
     RECT  0.192 28.32 0.467 28.344 ;
     RECT  0.181 28.344 0.467 28.416 ;
     RECT  0.192 28.416 0.467 28.44 ;
     RECT  0.181 28.44 0.467 28.512 ;
     RECT  0.192 28.512 0.467 28.536 ;
     RECT  0.181 28.536 0.467 28.608 ;
     RECT  0.192 28.608 0.467 28.632 ;
     RECT  0.181 28.632 0.467 28.704 ;
     RECT  0.192 28.704 0.467 28.728 ;
     RECT  0.181 28.728 0.467 28.8 ;
     RECT  0.192 28.8 0.467 28.824 ;
     RECT  0.181 28.824 0.467 28.896 ;
     RECT  0.192 28.896 0.467 28.92 ;
     RECT  0.181 28.92 0.467 28.992 ;
     RECT  0.192 28.992 0.467 29.016 ;
     RECT  0.181 29.016 0.467 29.088 ;
     RECT  0.192 29.088 0.467 29.112 ;
     RECT  0.181 29.112 0.467 29.184 ;
     RECT  0.192 29.184 0.467 29.208 ;
     RECT  0.181 29.208 0.467 29.28 ;
     RECT  0.192 29.28 0.467 29.304 ;
     RECT  0.181 29.304 0.467 29.376 ;
     RECT  0.192 29.376 0.467 29.4 ;
     RECT  0.181 29.4 0.467 29.472 ;
     RECT  0.192 29.472 0.467 29.496 ;
     RECT  0.181 29.496 0.467 29.568 ;
     RECT  0.192 29.568 0.467 29.592 ;
     RECT  0.181 29.592 0.467 29.664 ;
     RECT  0.192 29.664 0.467 29.688 ;
     RECT  0.181 29.688 0.467 29.808 ;
     RECT  0.192 29.808 0.467 29.832 ;
     RECT  0.181 29.832 0.467 29.904 ;
     RECT  0.192 29.904 0.467 29.928 ;
     RECT  0.181 29.928 0.467 30 ;
     RECT  0.192 30 0.467 30.024 ;
     RECT  0.181 30.024 0.467 30.096 ;
     RECT  0.192 30.096 0.467 30.12 ;
     RECT  0.181 30.12 0.467 30.192 ;
     RECT  0.192 30.192 0.467 30.216 ;
     RECT  0.181 30.216 0.467 30.288 ;
     RECT  0.192 30.288 0.467 30.312 ;
     RECT  0.181 30.312 0.467 30.384 ;
     RECT  0.192 30.384 0.467 30.408 ;
     RECT  0.181 30.408 0.467 30.48 ;
     RECT  0.192 30.48 0.467 30.504 ;
     RECT  0.181 30.504 0.467 30.576 ;
     RECT  0.192 30.576 0.467 30.6 ;
     RECT  0.181 30.6 0.467 30.672 ;
     RECT  0.192 30.672 0.467 30.696 ;
     RECT  0.181 30.696 0.467 30.768 ;
     RECT  0.192 30.768 0.467 30.792 ;
     RECT  0.181 30.792 0.467 30.864 ;
     RECT  0.192 30.864 0.467 30.888 ;
     RECT  0.181 30.888 0.467 30.96 ;
     RECT  0.192 30.96 0.467 30.984 ;
     RECT  0.181 30.984 0.467 31.056 ;
     RECT  0.192 31.056 0.467 31.08 ;
     RECT  0.181 31.08 0.467 31.152 ;
     RECT  0.192 31.152 0.467 31.176 ;
     RECT  0.181 31.176 0.467 31.248 ;
     RECT  0.192 31.248 0.467 31.272 ;
     RECT  0.181 31.272 0.467 31.344 ;
     RECT  0.192 31.344 0.467 31.368 ;
     RECT  0.181 31.368 0.467 31.44 ;
     RECT  0.192 31.44 0.467 31.464 ;
     RECT  0.181 31.464 0.467 31.536 ;
     RECT  0.192 31.536 0.467 31.56 ;
     RECT  0.181 31.56 0.467 31.632 ;
     RECT  0.192 31.632 0.467 31.656 ;
     RECT  0.181 31.656 0.467 31.728 ;
     RECT  0.192 31.728 0.467 31.752 ;
     RECT  0.181 31.752 0.467 31.824 ;
     RECT  0.192 31.824 0.467 31.848 ;
     RECT  0.181 31.848 0.467 31.92 ;
     RECT  0.192 31.92 0.467 31.944 ;
     RECT  0.181 31.944 0.467 32.016 ;
     RECT  0.192 32.016 0.467 32.04 ;
     RECT  0.181 32.04 0.467 32.112 ;
     RECT  0.192 32.112 0.467 32.136 ;
     RECT  0.181 32.136 0.467 32.208 ;
     RECT  0.192 32.208 0.467 32.232 ;
     RECT  0.181 32.232 0.467 32.304 ;
     RECT  0.192 32.304 0.467 32.328 ;
     RECT  0.181 32.328 0.467 32.4 ;
     RECT  0.192 32.4 0.467 32.424 ;
     RECT  0.181 32.424 0.467 32.496 ;
     RECT  0.192 32.496 0.467 32.52 ;
     RECT  0.181 32.52 0.467 32.592 ;
     RECT  0.192 32.592 0.467 32.616 ;
     RECT  0.181 32.616 0.467 32.688 ;
     RECT  0.192 32.688 0.467 32.712 ;
     RECT  0.181 32.712 0.467 32.784 ;
     RECT  0.192 32.784 0.467 32.808 ;
     RECT  0.181 32.808 0.467 32.88 ;
     RECT  0.192 32.88 0.467 32.904 ;
     RECT  0.181 32.904 0.467 32.976 ;
     RECT  0.192 32.976 0.467 33 ;
     RECT  0.181 33 0.467 33.072 ;
     RECT  0.192 33.072 0.467 33.096 ;
     RECT  0.181 33.096 0.467 33.168 ;
     RECT  0.192 33.168 0.467 33.192 ;
     RECT  0.181 33.192 0.467 33.264 ;
     RECT  0.192 33.264 0.467 33.288 ;
     RECT  0.181 33.288 0.467 33.36 ;
     RECT  0.192 33.36 0.467 33.384 ;
     RECT  0.181 33.384 0.467 33.456 ;
     RECT  0.192 33.456 0.467 33.48 ;
     RECT  0.181 33.48 0.467 33.552 ;
     RECT  0.192 33.552 0.467 33.576 ;
     RECT  0.181 33.576 0.467 33.648 ;
     RECT  0.192 33.648 0.467 33.672 ;
     RECT  0.181 33.672 0.467 33.744 ;
     RECT  0.192 33.744 0.467 33.768 ;
     RECT  0.181 33.768 0.467 33.84 ;
     RECT  0.192 33.84 0.467 33.864 ;
     RECT  0.181 33.864 0.467 33.936 ;
     RECT  0.192 33.936 0.467 33.96 ;
     RECT  0.181 33.96 0.467 34.032 ;
     RECT  0.192 34.032 0.467 34.056 ;
     RECT  0.181 34.056 0.467 34.128 ;
     RECT  0.192 34.128 0.467 34.152 ;
     RECT  0.181 34.152 0.467 34.224 ;
     RECT  0.192 34.224 0.467 34.248 ;
     RECT  0.181 34.248 0.467 34.32 ;
     RECT  0.192 34.32 0.467 34.344 ;
     RECT  0.181 34.344 0.467 34.416 ;
     RECT  0.192 34.416 0.467 34.44 ;
     RECT  0.181 34.44 0.467 34.512 ;
     RECT  0.192 34.512 0.467 34.536 ;
     RECT  0.181 34.536 0.467 34.608 ;
     RECT  0.192 34.608 0.467 34.632 ;
     RECT  0.181 34.632 0.467 34.704 ;
     RECT  0.192 34.704 0.467 34.728 ;
     RECT  0.181 34.728 0.467 34.8 ;
     RECT  0.192 34.8 0.467 34.824 ;
     RECT  0.181 34.824 0.467 34.896 ;
     RECT  0.192 34.896 0.467 34.92 ;
     RECT  0.181 34.92 0.467 34.992 ;
     RECT  0.192 34.992 0.467 35.016 ;
     RECT  0.181 35.016 0.467 35.088 ;
     RECT  0.192 35.088 0.467 35.112 ;
     RECT  0.181 35.112 0.467 35.184 ;
     RECT  0.192 35.184 0.467 35.208 ;
     RECT  0.181 35.208 0.467 35.28 ;
     RECT  0.192 35.28 0.467 35.304 ;
     RECT  0.181 35.304 0.467 35.376 ;
     RECT  0.192 35.376 0.467 35.4 ;
     RECT  0.181 35.4 0.467 35.472 ;
     RECT  0.192 35.472 0.467 35.496 ;
     RECT  0.181 35.496 0.467 35.568 ;
     RECT  0.192 35.568 0.467 35.592 ;
     RECT  0.181 35.592 0.467 35.664 ;
     RECT  0.192 35.664 0.467 35.688 ;
     RECT  0.181 35.688 0.467 35.76 ;
     RECT  0.192 35.76 0.467 35.784 ;
     RECT  0.181 35.784 0.467 35.856 ;
     RECT  0.192 35.856 0.467 35.88 ;
     RECT  0.181 35.88 0.467 35.952 ;
     RECT  0.192 35.952 0.467 35.976 ;
     RECT  0.181 35.976 0.467 36.048 ;
     RECT  0.192 36.048 0.467 36.072 ;
     RECT  0.181 36.072 0.467 36.144 ;
     RECT  0.192 36.144 0.467 36.168 ;
     RECT  0.181 36.168 0.467 36.288 ;
     RECT  0.192 36.288 0.467 36.312 ;
     RECT  0.181 36.312 0.467 36.384 ;
     RECT  0.192 36.384 0.467 36.408 ;
     RECT  0.181 36.408 0.467 36.48 ;
     RECT  0.192 36.48 0.467 36.504 ;
     RECT  0.181 36.504 0.467 36.576 ;
     RECT  0.192 36.576 0.467 36.6 ;
     RECT  0.181 36.6 0.467 36.672 ;
     RECT  0.192 36.672 0.467 36.696 ;
     RECT  0.181 36.696 0.467 36.768 ;
     RECT  0.192 36.768 0.467 36.792 ;
     RECT  0.181 36.792 0.467 36.864 ;
     RECT  0.192 36.864 0.467 36.888 ;
     RECT  0.181 36.888 0.467 36.96 ;
     RECT  0.192 36.96 0.467 36.984 ;
     RECT  0.181 36.984 0.467 37.056 ;
     RECT  0.192 37.056 0.467 37.08 ;
     RECT  0.181 37.08 0.467 37.152 ;
     RECT  0.192 37.152 0.467 37.176 ;
     RECT  0.181 37.176 0.467 37.248 ;
     RECT  0.192 37.248 0.467 37.272 ;
     RECT  0.181 37.272 0.467 37.344 ;
     RECT  0.192 37.344 0.467 37.368 ;
     RECT  0.181 37.368 0.467 37.44 ;
     RECT  0.192 37.44 0.467 37.464 ;
     RECT  0.181 37.464 0.467 37.536 ;
     RECT  0.192 37.536 0.467 37.56 ;
     RECT  0.181 37.56 0.467 37.632 ;
     RECT  0.192 37.632 0.467 37.656 ;
     RECT  0.181 37.656 0.467 37.728 ;
     RECT  0.192 37.728 0.467 37.752 ;
     RECT  0.181 37.752 0.467 37.824 ;
     RECT  0.192 37.824 0.467 37.848 ;
     RECT  0.181 37.848 0.467 37.92 ;
     RECT  0.192 37.92 0.467 37.944 ;
     RECT  0.181 37.944 0.467 38.016 ;
     RECT  0.192 38.016 0.467 38.04 ;
     RECT  0.181 38.04 0.467 38.112 ;
     RECT  0.192 38.112 0.467 38.136 ;
     RECT  0.181 38.136 0.467 38.208 ;
     RECT  0.192 38.208 0.467 38.232 ;
     RECT  0.181 38.232 0.467 38.304 ;
     RECT  0.192 38.304 0.467 38.328 ;
     RECT  0.181 38.328 0.467 38.4 ;
     RECT  0.192 38.4 0.467 38.424 ;
     RECT  0.181 38.424 0.467 38.496 ;
     RECT  0.192 38.496 0.467 38.52 ;
     RECT  0.181 38.52 0.467 38.592 ;
     RECT  0.192 38.592 0.467 38.616 ;
     RECT  0.181 38.616 0.467 38.688 ;
     RECT  0.192 38.688 0.467 38.712 ;
     RECT  0.181 38.712 0.467 38.784 ;
     RECT  0.192 38.784 0.467 38.808 ;
     RECT  0.181 38.808 0.467 38.88 ;
     RECT  0.192 38.88 0.467 38.904 ;
     RECT  0.181 38.904 0.467 38.976 ;
     RECT  0.192 38.976 0.467 39 ;
     RECT  0.181 39 0.467 39.072 ;
     RECT  0.192 39.072 0.467 39.096 ;
     RECT  0.181 39.096 0.467 39.168 ;
     RECT  0.192 39.168 0.467 39.192 ;
     RECT  0.181 39.192 0.467 39.264 ;
     RECT  0.192 39.264 0.467 39.288 ;
     RECT  0.181 39.288 0.467 39.36 ;
     RECT  0.192 39.36 0.467 39.384 ;
     RECT  0.181 39.384 0.467 39.456 ;
     RECT  0.192 39.456 0.467 39.48 ;
     RECT  0.181 39.48 0.467 39.552 ;
     RECT  0.192 39.552 0.467 39.576 ;
     RECT  0.181 39.576 0.467 39.648 ;
     RECT  0.192 39.648 0.467 39.672 ;
     RECT  0.181 39.672 0.467 39.744 ;
     RECT  0.192 39.744 0.467 39.768 ;
     RECT  0.181 39.768 0.467 39.84 ;
     RECT  0.192 39.84 0.467 39.864 ;
     RECT  0.181 39.864 0.467 39.936 ;
     RECT  0.192 39.936 0.467 39.96 ;
     RECT  0.181 39.96 0.467 40.032 ;
     RECT  0.192 40.032 0.467 40.056 ;
     RECT  0.181 40.056 0.467 40.128 ;
     RECT  0.192 40.128 0.467 40.152 ;
     RECT  0.181 40.152 0.467 40.224 ;
     RECT  0.192 40.224 0.467 40.248 ;
     RECT  0.181 40.248 0.467 40.32 ;
     RECT  0.192 40.32 0.467 40.344 ;
     RECT  0.181 40.344 0.467 40.416 ;
     RECT  0.192 40.416 0.467 40.44 ;
     RECT  0.181 40.44 0.467 40.512 ;
     RECT  0.192 40.512 0.467 40.536 ;
     RECT  0.181 40.536 0.467 40.608 ;
     RECT  0.192 40.608 0.467 40.632 ;
     RECT  0.181 40.632 0.467 40.704 ;
     RECT  0.192 40.704 0.467 40.728 ;
     RECT  0.181 40.728 0.467 40.8 ;
     RECT  0.192 40.8 0.467 40.824 ;
     RECT  0.181 40.824 0.467 40.896 ;
     RECT  0.192 40.896 0.467 40.92 ;
     RECT  0.181 40.92 0.467 40.992 ;
     RECT  0.192 40.992 0.467 41.016 ;
     RECT  0.181 41.016 0.467 41.088 ;
     RECT  0.192 41.088 0.467 41.112 ;
     RECT  0.181 41.112 0.467 41.184 ;
     RECT  0.192 41.184 0.467 41.208 ;
     RECT  0.181 41.208 0.467 41.28 ;
     RECT  0.192 41.28 0.467 41.304 ;
     RECT  0.181 41.304 0.467 41.376 ;
     RECT  0.192 41.376 0.467 41.4 ;
     RECT  0.181 41.4 0.467 41.472 ;
     RECT  0.192 41.472 0.467 41.496 ;
     RECT  0.181 41.496 0.467 41.568 ;
     RECT  0.192 41.568 0.467 41.592 ;
     RECT  0.181 41.592 0.467 41.664 ;
     RECT  0.192 41.664 0.467 41.688 ;
     RECT  0.181 41.688 0.467 41.76 ;
     RECT  0.192 41.76 0.467 41.784 ;
     RECT  0.181 41.784 0.467 41.856 ;
     RECT  0.192 41.856 0.467 41.88 ;
     RECT  0.181 41.88 0.467 41.952 ;
     RECT  0.192 41.952 0.467 41.976 ;
     RECT  0.181 41.976 0.467 42.048 ;
     RECT  0.192 42.048 0.467 42.072 ;
     RECT  0.181 42.072 0.467 42.144 ;
     RECT  0.192 42.144 0.467 42.168 ;
     RECT  0.181 42.168 0.467 42.24 ;
     RECT  0.192 42.24 0.467 42.264 ;
     RECT  0.181 42.264 0.467 42.336 ;
     RECT  0.192 42.336 0.467 42.36 ;
     RECT  0.181 42.36 0.467 42.432 ;
     RECT  0.192 42.432 0.467 42.456 ;
     RECT  0.181 42.456 0.467 42.528 ;
     RECT  0.192 42.528 0.467 42.552 ;
     RECT  0.181 42.552 0.467 42.624 ;
     RECT  0.192 42.624 0.467 42.648 ;
     RECT  0.181 42.648 0.467 42.768 ;
     RECT  0.192 42.768 0.467 42.792 ;
     RECT  0.181 42.792 0.467 42.864 ;
     RECT  0.192 42.864 0.467 42.888 ;
     RECT  0.181 42.888 0.467 42.96 ;
     RECT  0.192 42.96 0.467 42.984 ;
     RECT  0.181 42.984 0.467 43.056 ;
     RECT  0.192 43.056 0.467 43.08 ;
     RECT  0.181 43.08 0.467 43.152 ;
     RECT  0.192 43.152 0.467 43.176 ;
     RECT  0.181 43.176 0.467 43.248 ;
     RECT  0.192 43.248 0.467 43.272 ;
     RECT  0.181 43.272 0.467 43.344 ;
     RECT  0.192 43.344 0.467 43.368 ;
     RECT  0.181 43.368 0.467 43.44 ;
     RECT  0.192 43.44 0.467 43.464 ;
     RECT  0.181 43.464 0.467 43.536 ;
     RECT  0.192 43.536 0.467 43.56 ;
     RECT  0.181 43.56 0.467 43.632 ;
     RECT  0.192 43.632 0.467 43.656 ;
     RECT  0.181 43.656 0.467 43.728 ;
     RECT  0.192 43.728 0.467 43.752 ;
     RECT  0.181 43.752 0.467 43.824 ;
     RECT  0.192 43.824 0.467 43.848 ;
     RECT  0.181 43.848 0.467 43.92 ;
     RECT  0.192 43.92 0.467 43.944 ;
     RECT  0.181 43.944 0.467 44.016 ;
     RECT  0.192 44.016 0.467 44.04 ;
     RECT  0.181 44.04 0.467 44.112 ;
     RECT  0.192 44.112 0.467 44.136 ;
     RECT  0.181 44.136 0.467 44.208 ;
     RECT  0.192 44.208 0.467 44.232 ;
     RECT  0.181 44.232 0.467 44.304 ;
     RECT  0.192 44.304 0.467 44.328 ;
     RECT  0.181 44.328 0.467 44.4 ;
     RECT  0.192 44.4 0.467 44.424 ;
     RECT  0.181 44.424 0.467 44.496 ;
     RECT  0.192 44.496 0.467 44.52 ;
     RECT  0.181 44.52 0.467 44.592 ;
     RECT  0.192 44.592 0.467 44.616 ;
     RECT  0.181 44.616 0.467 44.688 ;
     RECT  0.192 44.688 0.467 44.712 ;
     RECT  0.181 44.712 0.467 44.784 ;
     RECT  0.192 44.784 0.467 44.808 ;
     RECT  0.181 44.808 0.467 44.88 ;
     RECT  0.192 44.88 0.467 44.904 ;
     RECT  0.181 44.904 0.467 44.976 ;
     RECT  0.192 44.976 0.467 45 ;
     RECT  0.181 45 0.467 45.072 ;
     RECT  0.192 45.072 0.467 45.096 ;
     RECT  0.181 45.096 0.467 45.168 ;
     RECT  0.192 45.168 0.467 45.192 ;
     RECT  0.181 45.192 0.467 45.264 ;
     RECT  0.192 45.264 0.467 45.288 ;
     RECT  0.181 45.288 0.467 45.36 ;
     RECT  0.192 45.36 0.467 45.384 ;
     RECT  0.181 45.384 0.467 45.456 ;
     RECT  0.192 45.456 0.467 45.48 ;
     RECT  0.181 45.48 0.467 45.552 ;
     RECT  0.192 45.552 0.467 45.576 ;
     RECT  0.181 45.576 0.467 45.648 ;
     RECT  0.192 45.648 0.467 45.672 ;
     RECT  0.181 45.672 0.467 45.744 ;
     RECT  0.192 45.744 0.467 45.768 ;
     RECT  0.181 45.768 0.467 45.84 ;
     RECT  0.192 45.84 0.467 45.864 ;
     RECT  0.181 45.864 0.467 45.936 ;
     RECT  0.192 45.936 0.467 45.96 ;
     RECT  0.181 45.96 0.467 46.032 ;
     RECT  0.192 46.032 0.467 46.056 ;
     RECT  0.181 46.056 0.467 46.128 ;
     RECT  0.192 46.128 0.467 46.152 ;
     RECT  0.181 46.152 0.467 46.224 ;
     RECT  0.192 46.224 0.467 46.248 ;
     RECT  0.181 46.248 0.467 46.32 ;
     RECT  0.192 46.32 0.467 46.344 ;
     RECT  0.181 46.344 0.467 46.416 ;
     RECT  0.192 46.416 0.467 46.44 ;
     RECT  0.181 46.44 0.467 46.512 ;
     RECT  0.192 46.512 0.467 46.536 ;
     RECT  0.181 46.536 0.467 46.608 ;
     RECT  0.192 46.608 0.467 46.632 ;
     RECT  0.181 46.632 0.467 46.704 ;
     RECT  0.192 46.704 0.467 46.728 ;
     RECT  0.181 46.728 0.467 46.8 ;
     RECT  0.192 46.8 0.467 46.824 ;
     RECT  0.181 46.824 0.467 46.896 ;
     RECT  0.192 46.896 0.467 46.92 ;
     RECT  0.181 46.92 0.467 46.992 ;
     RECT  0.192 46.992 0.467 47.016 ;
     RECT  0.181 47.016 0.467 47.088 ;
     RECT  0.192 47.088 0.467 47.112 ;
     RECT  0.181 47.112 0.467 47.184 ;
     RECT  0.192 47.184 0.467 47.208 ;
     RECT  0.181 47.208 0.467 47.28 ;
     RECT  0.192 47.28 0.467 47.304 ;
     RECT  0.181 47.304 0.467 47.376 ;
     RECT  0.192 47.376 0.467 47.4 ;
     RECT  0.181 47.4 0.467 47.472 ;
     RECT  0.192 47.472 0.467 47.496 ;
     RECT  0.181 47.496 0.467 47.568 ;
     RECT  0.192 47.568 0.467 47.592 ;
     RECT  0.181 47.592 0.467 47.664 ;
     RECT  0.192 47.664 0.467 47.688 ;
     RECT  0.181 47.688 0.467 47.76 ;
     RECT  0.192 47.76 0.467 47.784 ;
     RECT  0.181 47.784 0.467 47.856 ;
     RECT  0.192 47.856 0.467 47.88 ;
     RECT  0.181 47.88 0.467 47.952 ;
     RECT  0.192 47.952 0.467 47.976 ;
     RECT  0.181 47.976 0.467 48.048 ;
     RECT  0.192 48.048 0.467 48.072 ;
     RECT  0.181 48.072 0.467 48.144 ;
     RECT  0.192 48.144 0.467 48.168 ;
     RECT  0.181 48.168 0.467 48.24 ;
     RECT  0.192 48.24 0.467 48.264 ;
     RECT  0.181 48.264 0.467 48.336 ;
     RECT  0.192 48.336 0.467 48.36 ;
     RECT  0.181 48.36 0.467 48.432 ;
     RECT  0.192 48.432 0.467 48.456 ;
     RECT  0.181 48.456 0.467 48.528 ;
     RECT  0.192 48.528 0.467 48.552 ;
     RECT  0.181 48.552 0.467 48.624 ;
     RECT  0.192 48.624 0.467 48.648 ;
     RECT  0.181 48.648 0.467 48.72 ;
     RECT  0.192 48.72 0.467 48.744 ;
     RECT  0.181 48.744 0.467 48.816 ;
     RECT  0.192 48.816 0.467 48.84 ;
     RECT  0.181 48.84 0.467 48.912 ;
     RECT  0.192 48.912 0.467 48.936 ;
     RECT  0.181 48.936 0.467 49.008 ;
     RECT  0.192 49.008 0.467 49.032 ;
     RECT  0.181 49.032 0.467 49.104 ;
     RECT  0.192 49.104 0.467 49.128 ;
     RECT  0.181 49.128 0.467 49.248 ;
     RECT  0.192 49.248 0.467 49.272 ;
     RECT  0.181 49.272 0.467 49.344 ;
     RECT  0.192 49.344 0.467 49.368 ;
     RECT  0.181 49.368 0.467 49.44 ;
     RECT  0.192 49.44 0.467 49.464 ;
     RECT  0.181 49.464 0.467 49.536 ;
     RECT  0.192 49.536 0.467 49.56 ;
     RECT  0.181 49.56 0.467 49.632 ;
     RECT  0.192 49.632 0.467 49.656 ;
     RECT  0.181 49.656 0.467 49.728 ;
     RECT  0.192 49.728 0.467 49.752 ;
     RECT  0.181 49.752 0.467 49.824 ;
     RECT  0.192 49.824 0.467 49.848 ;
     RECT  0.181 49.848 0.467 49.92 ;
     RECT  0.192 49.92 0.467 49.944 ;
     RECT  0.181 49.944 0.467 50.016 ;
     RECT  0.192 50.016 0.467 50.04 ;
     RECT  0.181 50.04 0.467 50.112 ;
     RECT  0.192 50.112 0.467 50.136 ;
     RECT  0.181 50.136 0.467 50.208 ;
     RECT  0.192 50.208 0.467 50.232 ;
     RECT  0.181 50.232 0.467 50.304 ;
     RECT  0.192 50.304 0.467 50.328 ;
     RECT  0.181 50.328 0.467 50.4 ;
     RECT  0.192 50.4 0.467 50.424 ;
     RECT  0.181 50.424 0.467 50.496 ;
     RECT  0.192 50.496 0.467 50.52 ;
     RECT  0.181 50.52 0.467 50.592 ;
     RECT  0.192 50.592 0.467 50.616 ;
     RECT  0.181 50.616 0.467 50.688 ;
     RECT  0.192 50.688 0.467 50.712 ;
     RECT  0.181 50.712 0.467 50.784 ;
     RECT  0.192 50.784 0.467 50.808 ;
     RECT  0.181 50.808 0.467 50.88 ;
     RECT  0.192 50.88 0.467 50.904 ;
     RECT  0.181 50.904 0.467 50.976 ;
     RECT  0.192 50.976 0.467 51 ;
     RECT  0.181 51 0.467 51.072 ;
     RECT  0.192 51.072 0.467 51.096 ;
     RECT  0.181 51.096 0.467 51.168 ;
     RECT  0.192 51.168 0.467 51.192 ;
     RECT  0.181 51.192 0.467 51.264 ;
     RECT  0.192 51.264 0.467 51.288 ;
     RECT  0.181 51.288 0.467 51.36 ;
     RECT  0.192 51.36 0.467 51.384 ;
     RECT  0.181 51.384 0.467 51.456 ;
     RECT  0.192 51.456 0.467 51.48 ;
     RECT  0.181 51.48 0.467 51.552 ;
     RECT  0.192 51.552 0.467 51.576 ;
     RECT  0.181 51.576 0.467 51.648 ;
     RECT  0.192 51.648 0.467 51.672 ;
     RECT  0.181 51.672 0.467 51.744 ;
     RECT  0.192 51.744 0.467 51.768 ;
     RECT  0.181 51.768 0.467 51.84 ;
     RECT  0.192 51.84 0.467 51.864 ;
     RECT  0.181 51.864 0.467 51.936 ;
     RECT  0.192 51.936 0.467 51.96 ;
     RECT  0.181 51.96 0.467 52.032 ;
     RECT  0.192 52.032 0.467 52.056 ;
     RECT  0.181 52.056 0.467 52.128 ;
     RECT  0.192 52.128 0.467 52.152 ;
     RECT  0.181 52.152 0.467 52.224 ;
     RECT  0.192 52.224 0.467 52.248 ;
     RECT  0.181 52.248 0.467 52.32 ;
     RECT  0.192 52.32 0.467 52.344 ;
     RECT  0.181 52.344 0.467 52.416 ;
     RECT  0.192 52.416 0.467 52.44 ;
     RECT  0.181 52.44 0.467 52.512 ;
     RECT  0.192 52.512 0.467 52.536 ;
     RECT  0.181 52.536 0.467 52.608 ;
     RECT  0.192 52.608 0.467 52.632 ;
     RECT  0.181 52.632 0.467 52.704 ;
     RECT  0.192 52.704 0.467 52.728 ;
     RECT  0.181 52.728 0.467 52.8 ;
     RECT  0.192 52.8 0.467 52.824 ;
     RECT  0.181 52.824 0.467 52.896 ;
     RECT  0.192 52.896 0.467 52.92 ;
     RECT  0.181 52.92 0.467 52.992 ;
     RECT  0.192 52.992 0.467 53.016 ;
     RECT  0.181 53.016 0.467 53.088 ;
     RECT  0.192 53.088 0.467 53.112 ;
     RECT  0.181 53.112 0.467 53.184 ;
     RECT  0.192 53.184 0.467 53.208 ;
     RECT  0.181 53.208 0.467 53.28 ;
     RECT  0.192 53.28 0.467 53.304 ;
     RECT  0.181 53.304 0.467 53.376 ;
     RECT  0.192 53.376 0.467 53.4 ;
     RECT  0.181 53.4 0.467 53.472 ;
     RECT  0.192 53.472 0.467 53.496 ;
     RECT  0.181 53.496 0.467 53.568 ;
     RECT  0.192 53.568 0.467 53.592 ;
     RECT  0.181 53.592 0.467 53.664 ;
     RECT  0.192 53.664 0.467 53.688 ;
     RECT  0.181 53.688 0.467 53.76 ;
     RECT  0.192 53.76 0.467 53.784 ;
     RECT  0.181 53.784 0.467 53.856 ;
     RECT  0.192 53.856 0.467 53.88 ;
     RECT  0.181 53.88 0.467 53.952 ;
     RECT  0.192 53.952 0.467 53.976 ;
     RECT  0.467 2.256 2.293 53.976 ;
     RECT  2.293 0.816 2.365 0.84 ;
     RECT  2.293 2.064 2.408 53.976 ;
     RECT  2.365 0.288 2.485 0.84 ;
     RECT  2.408 2.064 2.512 54.012 ;
     RECT  2.512 2.064 2.645 53.928 ;
     RECT  2.645 1.968 2.837 53.928 ;
     RECT  2.485 0.192 2.977 0.84 ;
     RECT  2.837 1.968 3.125 53.88 ;
     RECT  2.977 0.144 3.253 0.84 ;
     RECT  3.125 1.968 3.253 43.464 ;
     RECT  3.125 44.688 3.413 53.88 ;
     RECT  3.253 0.144 4.201 43.464 ;
     RECT  3.413 44.688 4.201 53.832 ;
     RECT  4.201 0.144 4.835 53.832 ;
     RECT  4.835 1.728 5.108 53.832 ;
     RECT  5.108 1.728 5.893 54.012 ;
     RECT  4.835 0.144 6.083 0.6 ;
     RECT  6.083 0.192 6.649 0.6 ;
     RECT  5.893 1.728 6.649 54.072 ;
     RECT  6.649 0.192 6.659 54.072 ;
     RECT  6.659 0.288 7.477 54.072 ;
     RECT  7.477 0.288 7.621 54.12 ;
     RECT  7.621 0.192 7.763 54.12 ;
     RECT  7.763 0.384 7.955 54.12 ;
     RECT  7.955 0.816 8.417 54.12 ;
     RECT  8.417 0.816 8.953 53.832 ;
     RECT  8.953 0.288 9.497 53.832 ;
     RECT  9.497 0.288 9.541 40.104 ;
     RECT  9.541 0.192 10.321 40.104 ;
     RECT  10.321 0.144 10.508 40.104 ;
     RECT  9.497 41.088 10.508 53.832 ;
     RECT  10.508 0.144 10.612 54.012 ;
     RECT  10.612 0.144 10.793 53.832 ;
     RECT  10.793 0.144 10.804 53.742 ;
     RECT  10.804 0.144 10.931 25.848 ;
     RECT  10.804 49.824 11.009 51.384 ;
     RECT  10.804 53.088 11.117 53.592 ;
     RECT  11.009 49.824 11.153 49.848 ;
     RECT  10.804 31.968 11.189 39.528 ;
     RECT  10.931 0.192 11.315 25.848 ;
     RECT  11.315 0.528 11.477 25.848 ;
     RECT  11.189 38.688 11.549 39.528 ;
     RECT  11.477 0.528 11.585 18.264 ;
     RECT  11.117 53.28 11.585 53.592 ;
     RECT  11.585 0.528 11.621 12.216 ;
     RECT  11.621 0.528 11.837 12.024 ;
     RECT  11.585 13.776 11.909 18.264 ;
     RECT  11.909 13.824 12.017 18.264 ;
     RECT  11.837 0.528 12.125 1.176 ;
     RECT  12.017 14.064 12.161 17.928 ;
     RECT  11.837 2.256 12.197 12.024 ;
     RECT  11.477 19.248 12.197 25.848 ;
     RECT  10.804 47.136 12.437 47.4 ;
     RECT  12.509 0.192 12.593 0.216 ;
     RECT  12.197 2.256 13.208 10.728 ;
     RECT  12.197 12 13.208 12.024 ;
     RECT  12.161 14.448 13.208 17.928 ;
     RECT  12.197 19.248 13.208 21 ;
     RECT  12.197 22.032 13.208 25.848 ;
     RECT  10.804 26.832 13.208 30.456 ;
     RECT  11.189 31.968 13.208 37.416 ;
     RECT  11.549 39.504 13.208 39.528 ;
     RECT  10.804 41.376 13.208 41.4 ;
     RECT  10.804 42.576 13.208 42.6 ;
     RECT  10.804 43.632 13.208 43.656 ;
     RECT  10.804 45.696 13.208 45.72 ;
     RECT  12.437 46.752 13.208 47.4 ;
     RECT  11.009 51.36 13.208 51.384 ;
     RECT  11.585 53.28 13.208 53.304 ;
     RECT  13.208 2.148 13.312 54.012 ;
     RECT  13.312 2.148 13.504 53.742 ;
     RECT  13.285 1.152 13.525 1.176 ;
     RECT  13.504 2.148 13.525 3.096 ;
     RECT  13.525 1.152 13.565 3.096 ;
     RECT  13.504 6 13.619 7.464 ;
     RECT  13.573 0.288 13.66 0.312 ;
     RECT  13.619 6.336 13.66 7.464 ;
     RECT  13.66 6.336 13.667 6.36 ;
     RECT  13.504 14.352 13.673 16.392 ;
     RECT  13.504 46.752 13.789 47.4 ;
     RECT  13.504 22.032 13.889 25.848 ;
     RECT  13.673 16.368 13.997 16.392 ;
     RECT  13.673 14.352 14.033 15.096 ;
     RECT  13.504 20.976 14.357 21 ;
     RECT  13.66 7.44 14.365 7.464 ;
     RECT  14.033 14.352 14.429 15.048 ;
     RECT  14.453 0.192 14.537 0.216 ;
     RECT  13.565 1.728 14.636 3.096 ;
     RECT  13.889 22.032 14.681 23.112 ;
     RECT  14.681 22.032 14.753 22.536 ;
     RECT  13.504 26.832 14.753 30.456 ;
     RECT  13.504 31.968 14.821 37.368 ;
     RECT  14.429 14.352 14.861 14.472 ;
     RECT  13.504 41.376 14.897 41.4 ;
     RECT  7.093 56.016 14.929 56.04 ;
     RECT  14.929 55.92 14.969 56.04 ;
     RECT  14.969 55.92 15.149 55.944 ;
     RECT  13.504 4.704 15.253 4.728 ;
     RECT  14.636 1.728 15.397 3.432 ;
     RECT  15.397 1.104 15.401 3.432 ;
     RECT  15.401 1.104 15.683 1.128 ;
     RECT  15.401 2.148 15.908 3.432 ;
     RECT  15.253 4.416 15.908 4.728 ;
     RECT  15.829 7.632 15.908 7.656 ;
     RECT  14.861 14.448 15.908 14.472 ;
     RECT  13.504 17.376 15.908 17.448 ;
     RECT  14.753 22.512 15.908 22.536 ;
     RECT  13.889 24.144 15.908 25.848 ;
     RECT  14.753 27.072 15.908 30.456 ;
     RECT  14.821 31.968 15.908 37.416 ;
     RECT  13.504 39.504 15.908 39.528 ;
     RECT  13.504 42.576 15.908 42.6 ;
     RECT  13.504 43.632 15.908 43.656 ;
     RECT  13.504 45.696 15.908 45.72 ;
     RECT  13.789 47.136 15.908 47.4 ;
     RECT  15.217 48.48 15.908 48.504 ;
     RECT  13.504 51.36 15.908 51.384 ;
     RECT  15.908 2.148 16.012 54.012 ;
     RECT  16.012 2.256 16.204 53.742 ;
     RECT  15.829 0.192 16.265 0.264 ;
     RECT  16.204 2.256 16.381 5.112 ;
     RECT  16.204 30.336 16.409 30.456 ;
     RECT  16.204 24.384 16.517 24.984 ;
     RECT  16.204 7.44 16.589 7.992 ;
     RECT  16.517 24.96 16.697 24.984 ;
     RECT  16.204 14.448 16.877 14.472 ;
     RECT  16.204 39.504 16.877 39.528 ;
     RECT  16.589 7.968 17.129 7.992 ;
     RECT  16.409 30.336 17.273 30.408 ;
     RECT  17.273 30.384 17.381 30.408 ;
     RECT  16.381 2.256 17.411 4.728 ;
     RECT  17.341 8.544 18.133 8.664 ;
     RECT  17.749 6.864 18.421 6.888 ;
     RECT  16.265 0.192 18.469 0.216 ;
     RECT  18.469 0.192 18.563 0.312 ;
     RECT  17.411 2.256 18.608 3.096 ;
     RECT  17.411 4.416 18.608 4.728 ;
     RECT  18.421 6.288 18.608 6.888 ;
     RECT  18.133 7.968 18.608 8.664 ;
     RECT  17.629 20.64 18.608 20.664 ;
     RECT  16.204 27.12 18.608 28.296 ;
     RECT  16.204 31.968 18.608 37.416 ;
     RECT  16.204 42.576 18.608 42.6 ;
     RECT  16.204 43.632 18.608 43.656 ;
     RECT  16.204 45.696 18.608 45.72 ;
     RECT  16.204 47.136 18.608 47.4 ;
     RECT  16.204 51.36 18.608 51.384 ;
     RECT  18.608 2.148 18.712 54.012 ;
     RECT  18.563 0.288 18.755 0.312 ;
     RECT  18.781 0.816 18.901 0.84 ;
     RECT  18.712 2.148 18.901 53.742 ;
     RECT  18.901 0.816 18.904 53.742 ;
     RECT  18.904 29.904 19.253 30.936 ;
     RECT  18.904 47.376 19.433 47.4 ;
     RECT  18.904 48.48 19.513 48.504 ;
     RECT  18.904 0.816 19.715 4.728 ;
     RECT  19.253 30.768 19.901 30.936 ;
     RECT  18.904 45.696 19.937 45.72 ;
     RECT  18.904 6.24 20.069 6.264 ;
     RECT  20.069 5.712 20.153 6.264 ;
     RECT  19.969 17.088 20.153 17.112 ;
     RECT  19.715 0.816 20.257 3.432 ;
     RECT  18.904 31.968 20.437 37.608 ;
     RECT  18.904 27.648 21.049 27.672 ;
     RECT  20.149 29.568 21.085 29.592 ;
     RECT  20.437 31.68 21.121 37.608 ;
     RECT  20.257 0.144 21.308 3.432 ;
     RECT  19.715 4.416 21.308 4.728 ;
     RECT  20.153 6.24 21.308 6.264 ;
     RECT  21.061 10.272 21.308 10.296 ;
     RECT  20.401 22.752 21.308 22.776 ;
     RECT  18.904 25.248 21.308 25.272 ;
     RECT  21.049 27.168 21.308 27.672 ;
     RECT  21.085 29.568 21.308 29.784 ;
     RECT  21.121 30.768 21.308 37.608 ;
     RECT  18.904 42.576 21.308 42.6 ;
     RECT  18.904 43.632 21.308 43.656 ;
     RECT  18.904 51.36 21.308 51.384 ;
     RECT  21.308 0.144 21.412 54.012 ;
     RECT  21.412 0.144 21.604 53.742 ;
     RECT  21.604 26.256 21.701 27.672 ;
     RECT  21.604 25.152 21.731 25.272 ;
     RECT  21.604 23.184 22.097 24.168 ;
     RECT  21.604 6.288 22.565 6.36 ;
     RECT  21.701 26.256 22.669 26.28 ;
     RECT  21.701 27.312 22.669 27.672 ;
     RECT  22.565 6.336 22.709 6.36 ;
     RECT  22.097 24.144 22.741 24.168 ;
     RECT  21.731 25.152 22.741 25.176 ;
     RECT  21.604 29.472 22.777 29.784 ;
     RECT  21.604 30.816 22.777 31.704 ;
     RECT  21.604 0.144 22.789 3.096 ;
     RECT  21.604 4.416 22.789 4.728 ;
     RECT  22.669 26.256 22.811 27.672 ;
     RECT  22.741 24.144 22.813 25.176 ;
     RECT  21.604 32.784 22.817 37.608 ;
     RECT  22.777 29.472 22.853 31.704 ;
     RECT  22.789 0.144 22.876 4.728 ;
     RECT  22.813 24.144 22.885 25.272 ;
     RECT  22.811 26.256 22.885 27.72 ;
     RECT  22.817 33.696 22.997 37.608 ;
     RECT  22.94 6.816 23.027 6.84 ;
     RECT  22.997 33.696 23.033 36.936 ;
     RECT  22.853 29.568 23.929 31.704 ;
     RECT  22.876 0.144 24.008 3.096 ;
     RECT  22.876 4.416 24.008 4.728 ;
     RECT  23.101 7.392 24.008 7.416 ;
     RECT  22.885 24.144 24.008 27.72 ;
     RECT  23.929 29.232 24.008 31.704 ;
     RECT  23.033 33.696 24.008 34.968 ;
     RECT  23.033 36.24 24.008 36.936 ;
     RECT  21.604 42.576 24.008 42.6 ;
     RECT  21.604 43.632 24.008 43.656 ;
     RECT  21.604 51.36 24.008 51.384 ;
     RECT  24.008 0.144 24.112 54.012 ;
     RECT  24.112 0.144 24.304 53.742 ;
     RECT  24.304 7.344 24.419 7.416 ;
     RECT  24.304 24.432 24.473 31.224 ;
     RECT  24.419 7.392 24.515 7.416 ;
     RECT  24.304 36.24 24.833 36.936 ;
     RECT  24.833 36.528 24.869 36.936 ;
     RECT  24.304 12 25.085 12.024 ;
     RECT  24.869 36.528 25.085 36.552 ;
     RECT  24.473 25.2 25.157 31.224 ;
     RECT  25.157 25.248 26.305 31.224 ;
     RECT  24.304 0.144 26.708 3.096 ;
     RECT  24.304 4.416 26.708 4.728 ;
     RECT  26.305 25.104 26.708 31.224 ;
     RECT  24.304 33.888 26.708 33.912 ;
     RECT  24.304 34.944 26.708 34.968 ;
     RECT  24.304 42.576 26.708 42.6 ;
     RECT  24.304 43.632 26.708 43.656 ;
     RECT  24.304 51.36 26.708 51.384 ;
     RECT  26.708 0.144 26.812 54.012 ;
     RECT  26.812 0.144 27.004 53.742 ;
     RECT  27.004 0.144 27.155 4.728 ;
     RECT  27.004 25.248 27.173 31.224 ;
     RECT  27.155 0.144 27.209 3.432 ;
     RECT  27.173 26.256 27.389 31.224 ;
     RECT  27.155 4.416 28.021 4.728 ;
     RECT  28.021 4.416 28.109 5.16 ;
     RECT  27.209 0.144 28.213 3.384 ;
     RECT  27.389 26.256 28.537 30.984 ;
     RECT  29.041 10.128 29.077 10.152 ;
     RECT  28.213 0.144 29.408 3.432 ;
     RECT  28.109 4.416 29.408 4.728 ;
     RECT  28.597 5.712 29.408 5.736 ;
     RECT  29.077 10.128 29.408 10.248 ;
     RECT  28.405 12 29.408 12.024 ;
     RECT  28.981 15.408 29.408 15.432 ;
     RECT  27.173 25.248 29.408 25.272 ;
     RECT  28.537 26.256 29.408 31.656 ;
     RECT  27.004 33.888 29.408 33.912 ;
     RECT  27.004 42.576 29.408 42.6 ;
     RECT  27.004 43.632 29.408 43.656 ;
     RECT  27.004 51.36 29.408 51.384 ;
     RECT  29.408 0.144 29.512 54.012 ;
     RECT  29.512 0.144 29.704 53.742 ;
     RECT  29.704 25.152 29.801 25.272 ;
     RECT  29.704 26.256 29.801 27.672 ;
     RECT  29.704 0.144 30.449 4.728 ;
     RECT  29.704 29.472 30.449 31.512 ;
     RECT  30.449 30.624 30.629 31.512 ;
     RECT  29.704 33.888 30.769 33.912 ;
     RECT  30.769 33.312 30.805 33.912 ;
     RECT  29.801 26.256 30.841 26.28 ;
     RECT  29.801 27.312 30.841 27.672 ;
     RECT  30.709 14.832 30.845 14.856 ;
     RECT  30.629 31.488 30.845 31.512 ;
     RECT  30.449 29.472 30.917 29.592 ;
     RECT  30.805 33.312 30.917 34.248 ;
     RECT  30.917 33.312 31.165 33.336 ;
     RECT  31.417 22.512 31.489 22.536 ;
     RECT  29.801 25.152 31.669 25.176 ;
     RECT  31.669 24.192 31.849 25.176 ;
     RECT  30.449 0.144 32.108 3.096 ;
     RECT  30.449 4.416 32.108 4.728 ;
     RECT  31.885 12.24 32.108 12.264 ;
     RECT  31.489 22.464 32.108 22.536 ;
     RECT  31.849 23.616 32.108 25.176 ;
     RECT  30.841 26.256 32.108 27.672 ;
     RECT  30.917 29.568 32.108 29.592 ;
     RECT  31.165 32.496 32.108 33.336 ;
     RECT  31.417 34.752 32.108 34.776 ;
     RECT  29.704 42.576 32.108 42.6 ;
     RECT  29.704 43.632 32.108 43.656 ;
     RECT  29.704 51.36 32.108 51.384 ;
     RECT  32.108 0.144 32.212 54.012 ;
     RECT  32.212 0.144 32.404 53.742 ;
     RECT  32.404 33.312 32.861 33.336 ;
     RECT  32.404 22.464 33.541 24.216 ;
     RECT  32.404 34.56 33.653 34.584 ;
     RECT  32.404 0.144 33.683 4.728 ;
     RECT  33.692 6.768 33.733 6.792 ;
     RECT  33.733 6.624 33.865 6.792 ;
     RECT  33.865 6.24 33.868 6.792 ;
     RECT  32.404 26.256 34.765 27.624 ;
     RECT  33.683 0.144 34.808 3.096 ;
     RECT  33.683 4.416 34.808 4.728 ;
     RECT  33.868 6.24 34.808 6.84 ;
     RECT  32.404 12.24 34.808 12.264 ;
     RECT  32.404 21.408 34.808 21.432 ;
     RECT  33.541 22.464 34.808 24.936 ;
     RECT  34.765 26.256 34.808 28.296 ;
     RECT  32.404 29.568 34.808 29.592 ;
     RECT  32.404 42.576 34.808 42.6 ;
     RECT  32.404 43.632 34.808 43.656 ;
     RECT  32.404 51.36 34.808 51.384 ;
     RECT  34.808 0.144 34.912 54.012 ;
     RECT  34.912 0.144 35.104 53.742 ;
     RECT  35.104 26.256 36.029 29.256 ;
     RECT  35.104 42.576 36.245 42.6 ;
     RECT  36.029 26.256 36.497 28.488 ;
     RECT  35.104 0.144 37.508 3.096 ;
     RECT  35.104 4.416 37.508 4.728 ;
     RECT  35.104 8.784 37.508 8.808 ;
     RECT  35.104 12.24 37.508 12.264 ;
     RECT  35.104 21.408 37.508 21.432 ;
     RECT  35.104 22.464 37.508 24.936 ;
     RECT  36.497 26.256 37.508 26.904 ;
     RECT  36.497 28.464 37.508 28.488 ;
     RECT  37.141 30.336 37.508 30.36 ;
     RECT  35.104 43.632 37.508 43.656 ;
     RECT  35.104 51.36 37.508 51.384 ;
     RECT  37.508 0.144 37.612 54.012 ;
     RECT  37.612 0.144 37.804 53.742 ;
     RECT  37.804 26.256 38.549 26.328 ;
     RECT  37.804 22.464 38.801 24.792 ;
     RECT  37.804 27.984 38.801 29.496 ;
     RECT  38.801 28.464 39.053 29.352 ;
     RECT  37.804 0.144 40.208 3.096 ;
     RECT  37.804 4.416 40.208 4.728 ;
     RECT  37.804 8.784 40.208 8.808 ;
     RECT  37.804 12.24 40.208 12.264 ;
     RECT  37.804 21.408 40.208 21.432 ;
     RECT  38.801 22.464 40.208 24.696 ;
     RECT  38.549 26.304 40.208 26.328 ;
     RECT  39.053 28.464 40.208 28.488 ;
     RECT  37.804 43.632 40.208 43.656 ;
     RECT  37.804 51.36 40.208 51.384 ;
     RECT  40.208 0.144 40.312 54.012 ;
     RECT  40.312 0.144 40.504 53.742 ;
     RECT  40.741 55.296 41.075 55.32 ;
     RECT  40.504 0.144 42.908 3.096 ;
     RECT  40.504 4.416 42.908 4.728 ;
     RECT  40.504 8.784 42.908 8.808 ;
     RECT  40.504 12.24 42.908 12.264 ;
     RECT  40.504 21.408 42.908 21.432 ;
     RECT  40.504 22.464 42.908 24.696 ;
     RECT  40.504 43.632 42.908 43.656 ;
     RECT  40.504 51.36 42.908 51.384 ;
     RECT  42.908 0.144 43.012 54.012 ;
     RECT  43.012 0.144 43.204 53.742 ;
     RECT  43.204 43.632 43.625 43.656 ;
     RECT  43.204 21.408 43.907 21.432 ;
     RECT  43.204 22.464 44.099 24.696 ;
     RECT  43.204 51.36 44.345 51.384 ;
     RECT  43.204 0.144 45.608 3.096 ;
     RECT  43.204 4.416 45.608 4.728 ;
     RECT  43.204 12.24 45.608 12.264 ;
     RECT  44.989 14.496 45.608 14.52 ;
     RECT  44.099 22.464 45.608 24.216 ;
     RECT  45.608 0.144 45.712 54.012 ;
     RECT  45.712 0.144 45.904 53.742 ;
     RECT  45.904 22.752 46.259 22.776 ;
     RECT  45.904 23.904 46.643 24.216 ;
     RECT  46.643 24.192 47.027 24.216 ;
     RECT  45.904 0.144 48.308 3.096 ;
     RECT  45.904 4.416 48.308 4.728 ;
     RECT  45.904 12.24 48.308 12.264 ;
     RECT  45.904 14.496 48.308 14.52 ;
     RECT  48.308 0.144 48.412 54.012 ;
     RECT  48.412 0.144 48.604 53.742 ;
     RECT  48.604 0.144 49.205 2.28 ;
     RECT  48.604 4.704 49.885 4.728 ;
     RECT  49.205 0.144 51.008 1.752 ;
     RECT  49.885 3.936 51.008 4.728 ;
     RECT  48.604 14.496 51.008 14.52 ;
     RECT  51.008 0.144 51.112 54.012 ;
     RECT  51.112 0.144 51.304 53.742 ;
     RECT  51.304 0.144 51.443 2.28 ;
     RECT  51.304 14.496 52.019 14.52 ;
     RECT  51.443 0.144 52.211 1.416 ;
     RECT  52.211 0.144 52.643 1.128 ;
     RECT  52.643 0.144 53.699 0.408 ;
     RECT  53.699 0.24 53.795 0.408 ;
     RECT  53.708 2.148 53.812 54.012 ;
     RECT  53.917 0.576 54.001 0.6 ;
     RECT  53.812 2.418 54.004 53.742 ;
    LAYER M5 ;
     RECT  3.36 0.133 3.456 0.144 ;
     RECT  3.48 0.133 3.648 0.144 ;
     RECT  3.672 0.133 3.84 0.144 ;
     RECT  3.864 0.133 4.032 0.144 ;
     RECT  4.056 0.133 4.224 0.144 ;
     RECT  4.248 0.133 4.416 0.144 ;
     RECT  4.44 0.133 4.608 0.144 ;
     RECT  4.632 0.133 4.8 0.144 ;
     RECT  4.824 0.133 4.992 0.144 ;
     RECT  5.016 0.133 5.184 0.144 ;
     RECT  5.208 0.133 5.376 0.144 ;
     RECT  5.4 0.133 5.568 0.144 ;
     RECT  5.592 0.133 5.76 0.144 ;
     RECT  5.784 0.133 5.952 0.144 ;
     RECT  5.976 0.133 6.072 0.144 ;
     RECT  10.896 0.133 10.92 0.144 ;
     RECT  53.664 0.133 53.688 0.144 ;
     RECT  2.328 0.144 2.496 0.192 ;
     RECT  2.52 0.144 2.688 0.192 ;
     RECT  2.712 0.144 2.88 0.192 ;
     RECT  2.904 0.144 3.072 0.192 ;
     RECT  3.096 0.144 3.264 0.192 ;
     RECT  3.288 0.144 3.456 0.192 ;
     RECT  3.48 0.144 3.648 0.192 ;
     RECT  3.672 0.144 3.84 0.192 ;
     RECT  3.864 0.144 4.032 0.192 ;
     RECT  4.056 0.144 4.224 0.192 ;
     RECT  4.248 0.144 4.416 0.192 ;
     RECT  4.44 0.144 4.608 0.192 ;
     RECT  4.632 0.144 4.8 0.192 ;
     RECT  4.824 0.144 4.992 0.192 ;
     RECT  5.016 0.144 5.184 0.192 ;
     RECT  5.208 0.144 5.376 0.192 ;
     RECT  5.4 0.144 5.568 0.192 ;
     RECT  5.592 0.144 5.76 0.192 ;
     RECT  5.784 0.144 5.952 0.192 ;
     RECT  5.976 0.144 6.144 0.192 ;
     RECT  6.168 0.144 6.336 0.192 ;
     RECT  6.36 0.144 6.528 0.192 ;
     RECT  6.552 0.144 6.72 0.192 ;
     RECT  6.744 0.144 6.912 0.192 ;
     RECT  6.936 0.144 7.152 0.192 ;
     RECT  7.176 0.144 7.344 0.192 ;
     RECT  7.368 0.144 7.536 0.192 ;
     RECT  7.56 0.144 7.728 0.192 ;
     RECT  7.752 0.144 7.92 0.192 ;
     RECT  7.944 0.144 8.112 0.192 ;
     RECT  8.136 0.144 8.304 0.192 ;
     RECT  8.328 0.144 8.496 0.192 ;
     RECT  8.52 0.144 8.688 0.192 ;
     RECT  8.712 0.144 8.88 0.192 ;
     RECT  8.904 0.144 9.072 0.192 ;
     RECT  9.096 0.144 9.264 0.192 ;
     RECT  9.288 0.144 9.456 0.192 ;
     RECT  9.48 0.144 9.648 0.192 ;
     RECT  9.672 0.144 9.84 0.192 ;
     RECT  9.864 0.144 10.032 0.192 ;
     RECT  10.056 0.144 10.224 0.192 ;
     RECT  10.248 0.144 10.416 0.192 ;
     RECT  10.44 0.144 10.608 0.192 ;
     RECT  10.632 0.144 10.8 0.192 ;
     RECT  10.824 0.144 10.992 0.192 ;
     RECT  11.016 0.144 11.184 0.192 ;
     RECT  11.208 0.144 11.376 0.192 ;
     RECT  11.4 0.144 11.568 0.192 ;
     RECT  11.592 0.144 11.76 0.192 ;
     RECT  11.784 0.144 11.952 0.192 ;
     RECT  11.976 0.144 12.144 0.192 ;
     RECT  12.168 0.144 12.336 0.192 ;
     RECT  12.36 0.144 12.528 0.192 ;
     RECT  12.552 0.144 12.72 0.192 ;
     RECT  12.744 0.144 12.912 0.192 ;
     RECT  12.936 0.144 13.104 0.192 ;
     RECT  13.128 0.144 13.296 0.192 ;
     RECT  13.32 0.144 13.536 0.192 ;
     RECT  13.56 0.144 13.728 0.192 ;
     RECT  13.752 0.144 13.92 0.192 ;
     RECT  13.944 0.144 14.112 0.192 ;
     RECT  14.136 0.144 14.304 0.192 ;
     RECT  14.328 0.144 14.496 0.192 ;
     RECT  14.52 0.144 14.688 0.192 ;
     RECT  14.712 0.144 14.88 0.192 ;
     RECT  14.904 0.144 15.072 0.192 ;
     RECT  15.096 0.144 15.264 0.192 ;
     RECT  15.288 0.144 15.456 0.192 ;
     RECT  15.48 0.144 15.648 0.192 ;
     RECT  15.672 0.144 15.84 0.192 ;
     RECT  15.864 0.144 16.032 0.192 ;
     RECT  16.056 0.144 16.224 0.192 ;
     RECT  16.248 0.144 16.416 0.192 ;
     RECT  16.44 0.144 16.608 0.192 ;
     RECT  16.632 0.144 16.8 0.192 ;
     RECT  16.824 0.144 16.992 0.192 ;
     RECT  17.016 0.144 17.184 0.192 ;
     RECT  17.208 0.144 17.376 0.192 ;
     RECT  17.4 0.144 17.568 0.192 ;
     RECT  17.592 0.144 17.76 0.192 ;
     RECT  17.784 0.144 17.952 0.192 ;
     RECT  17.976 0.144 18.144 0.192 ;
     RECT  18.168 0.144 18.336 0.192 ;
     RECT  18.36 0.144 18.528 0.192 ;
     RECT  18.552 0.144 18.72 0.192 ;
     RECT  18.744 0.144 18.912 0.192 ;
     RECT  18.936 0.144 19.104 0.192 ;
     RECT  19.128 0.144 19.296 0.192 ;
     RECT  19.32 0.144 19.488 0.192 ;
     RECT  19.512 0.144 19.68 0.192 ;
     RECT  19.704 0.144 19.872 0.192 ;
     RECT  19.896 0.144 20.112 0.192 ;
     RECT  20.136 0.144 20.304 0.192 ;
     RECT  20.328 0.144 20.496 0.192 ;
     RECT  20.52 0.144 20.688 0.192 ;
     RECT  20.712 0.144 20.88 0.192 ;
     RECT  20.904 0.144 21.072 0.192 ;
     RECT  21.096 0.144 21.264 0.192 ;
     RECT  21.288 0.144 21.456 0.192 ;
     RECT  21.48 0.144 21.648 0.192 ;
     RECT  21.672 0.144 21.84 0.192 ;
     RECT  21.864 0.144 22.032 0.192 ;
     RECT  22.056 0.144 22.224 0.192 ;
     RECT  22.248 0.144 22.416 0.192 ;
     RECT  22.44 0.144 22.608 0.192 ;
     RECT  22.632 0.144 22.8 0.192 ;
     RECT  22.824 0.144 22.992 0.192 ;
     RECT  23.016 0.144 23.184 0.192 ;
     RECT  23.208 0.144 23.376 0.192 ;
     RECT  23.4 0.144 23.568 0.192 ;
     RECT  23.592 0.144 23.76 0.192 ;
     RECT  23.784 0.144 23.952 0.192 ;
     RECT  23.976 0.144 24.144 0.192 ;
     RECT  24.168 0.144 24.336 0.192 ;
     RECT  24.36 0.144 24.528 0.192 ;
     RECT  24.552 0.144 24.72 0.192 ;
     RECT  24.744 0.144 24.912 0.192 ;
     RECT  24.936 0.144 25.104 0.192 ;
     RECT  25.128 0.144 25.296 0.192 ;
     RECT  25.32 0.144 25.488 0.192 ;
     RECT  25.512 0.144 25.68 0.192 ;
     RECT  25.704 0.144 25.872 0.192 ;
     RECT  25.896 0.144 26.064 0.192 ;
     RECT  26.088 0.144 26.256 0.192 ;
     RECT  26.28 0.144 26.496 0.192 ;
     RECT  26.52 0.144 26.688 0.192 ;
     RECT  26.712 0.144 26.88 0.192 ;
     RECT  26.904 0.144 27.072 0.192 ;
     RECT  27.096 0.144 27.264 0.192 ;
     RECT  27.288 0.144 27.456 0.192 ;
     RECT  27.48 0.144 27.648 0.192 ;
     RECT  27.672 0.144 27.84 0.192 ;
     RECT  27.864 0.144 28.032 0.192 ;
     RECT  28.056 0.144 28.224 0.192 ;
     RECT  28.248 0.144 28.416 0.192 ;
     RECT  28.44 0.144 28.608 0.192 ;
     RECT  28.632 0.144 28.8 0.192 ;
     RECT  28.824 0.144 28.992 0.192 ;
     RECT  29.016 0.144 29.184 0.192 ;
     RECT  29.208 0.144 29.376 0.192 ;
     RECT  29.4 0.144 29.568 0.192 ;
     RECT  29.592 0.144 29.76 0.192 ;
     RECT  29.784 0.144 29.952 0.192 ;
     RECT  29.976 0.144 30.144 0.192 ;
     RECT  30.168 0.144 30.336 0.192 ;
     RECT  30.36 0.144 30.528 0.192 ;
     RECT  30.552 0.144 30.72 0.192 ;
     RECT  30.744 0.144 30.912 0.192 ;
     RECT  30.936 0.144 31.104 0.192 ;
     RECT  31.128 0.144 31.296 0.192 ;
     RECT  31.32 0.144 31.488 0.192 ;
     RECT  31.512 0.144 31.68 0.192 ;
     RECT  31.704 0.144 31.872 0.192 ;
     RECT  31.896 0.144 32.064 0.192 ;
     RECT  32.088 0.144 32.256 0.192 ;
     RECT  32.28 0.144 32.448 0.192 ;
     RECT  32.472 0.144 32.64 0.192 ;
     RECT  32.664 0.144 32.832 0.192 ;
     RECT  32.856 0.144 33.072 0.192 ;
     RECT  33.096 0.144 33.264 0.192 ;
     RECT  33.288 0.144 33.456 0.192 ;
     RECT  33.48 0.144 33.648 0.192 ;
     RECT  33.672 0.144 33.84 0.192 ;
     RECT  33.864 0.144 34.032 0.192 ;
     RECT  34.056 0.144 34.224 0.192 ;
     RECT  34.248 0.144 34.416 0.192 ;
     RECT  34.44 0.144 34.608 0.192 ;
     RECT  34.632 0.144 34.8 0.192 ;
     RECT  34.824 0.144 34.992 0.192 ;
     RECT  35.016 0.144 35.184 0.192 ;
     RECT  35.208 0.144 35.376 0.192 ;
     RECT  35.4 0.144 35.568 0.192 ;
     RECT  35.592 0.144 35.76 0.192 ;
     RECT  35.784 0.144 35.952 0.192 ;
     RECT  35.976 0.144 36.144 0.192 ;
     RECT  36.168 0.144 36.336 0.192 ;
     RECT  36.36 0.144 36.528 0.192 ;
     RECT  36.552 0.144 36.72 0.192 ;
     RECT  36.744 0.144 36.912 0.192 ;
     RECT  36.936 0.144 37.104 0.192 ;
     RECT  37.128 0.144 37.296 0.192 ;
     RECT  37.32 0.144 37.488 0.192 ;
     RECT  37.512 0.144 37.68 0.192 ;
     RECT  37.704 0.144 37.872 0.192 ;
     RECT  37.896 0.144 38.064 0.192 ;
     RECT  38.088 0.144 38.256 0.192 ;
     RECT  38.28 0.144 38.448 0.192 ;
     RECT  38.472 0.144 38.64 0.192 ;
     RECT  38.664 0.144 38.832 0.192 ;
     RECT  38.856 0.144 39.024 0.192 ;
     RECT  39.048 0.144 39.216 0.192 ;
     RECT  39.24 0.144 39.456 0.192 ;
     RECT  39.48 0.144 39.648 0.192 ;
     RECT  39.672 0.144 39.84 0.192 ;
     RECT  39.864 0.144 40.032 0.192 ;
     RECT  40.056 0.144 40.224 0.192 ;
     RECT  40.248 0.144 40.416 0.192 ;
     RECT  40.44 0.144 40.608 0.192 ;
     RECT  40.632 0.144 40.8 0.192 ;
     RECT  40.824 0.144 40.992 0.192 ;
     RECT  41.016 0.144 41.184 0.192 ;
     RECT  41.208 0.144 41.376 0.192 ;
     RECT  41.4 0.144 41.568 0.192 ;
     RECT  41.592 0.144 41.76 0.192 ;
     RECT  41.784 0.144 41.952 0.192 ;
     RECT  41.976 0.144 42.144 0.192 ;
     RECT  42.168 0.144 42.336 0.192 ;
     RECT  42.36 0.144 42.528 0.192 ;
     RECT  42.552 0.144 42.72 0.192 ;
     RECT  42.744 0.144 42.912 0.192 ;
     RECT  42.936 0.144 43.104 0.192 ;
     RECT  43.128 0.144 43.296 0.192 ;
     RECT  43.32 0.144 43.488 0.192 ;
     RECT  43.512 0.144 43.68 0.192 ;
     RECT  43.704 0.144 43.872 0.192 ;
     RECT  43.896 0.144 44.064 0.192 ;
     RECT  44.088 0.144 44.256 0.192 ;
     RECT  44.28 0.144 44.448 0.192 ;
     RECT  44.472 0.144 44.64 0.192 ;
     RECT  44.664 0.144 44.832 0.192 ;
     RECT  44.856 0.144 45.024 0.192 ;
     RECT  45.048 0.144 45.216 0.192 ;
     RECT  45.24 0.144 45.408 0.192 ;
     RECT  45.432 0.144 45.6 0.192 ;
     RECT  45.624 0.144 45.792 0.192 ;
     RECT  45.816 0.144 46.032 0.192 ;
     RECT  46.056 0.144 46.224 0.192 ;
     RECT  46.248 0.144 46.416 0.192 ;
     RECT  46.44 0.144 46.608 0.192 ;
     RECT  46.632 0.144 46.8 0.192 ;
     RECT  46.824 0.144 46.992 0.192 ;
     RECT  47.016 0.144 47.184 0.192 ;
     RECT  47.208 0.144 47.376 0.192 ;
     RECT  47.4 0.144 47.568 0.192 ;
     RECT  47.592 0.144 47.76 0.192 ;
     RECT  47.784 0.144 47.952 0.192 ;
     RECT  47.976 0.144 48.144 0.192 ;
     RECT  48.168 0.144 48.336 0.192 ;
     RECT  48.36 0.144 48.528 0.192 ;
     RECT  48.552 0.144 48.72 0.192 ;
     RECT  48.744 0.144 48.912 0.192 ;
     RECT  48.936 0.144 49.104 0.192 ;
     RECT  49.128 0.144 49.296 0.192 ;
     RECT  49.32 0.144 49.488 0.192 ;
     RECT  49.512 0.144 49.68 0.192 ;
     RECT  49.704 0.144 49.872 0.192 ;
     RECT  49.896 0.144 50.064 0.192 ;
     RECT  50.088 0.144 50.256 0.192 ;
     RECT  50.28 0.144 50.448 0.192 ;
     RECT  50.472 0.144 50.64 0.192 ;
     RECT  50.664 0.144 50.832 0.192 ;
     RECT  50.856 0.144 51.024 0.192 ;
     RECT  51.048 0.144 51.216 0.192 ;
     RECT  51.24 0.144 51.408 0.192 ;
     RECT  51.432 0.144 51.6 0.192 ;
     RECT  51.624 0.144 51.792 0.192 ;
     RECT  51.816 0.144 51.984 0.192 ;
     RECT  52.008 0.144 52.176 0.192 ;
     RECT  52.2 0.144 52.416 0.192 ;
     RECT  52.44 0.144 52.608 0.192 ;
     RECT  52.632 0.144 52.8 0.192 ;
     RECT  52.824 0.144 52.992 0.192 ;
     RECT  53.016 0.144 53.184 0.192 ;
     RECT  53.208 0.144 53.376 0.192 ;
     RECT  53.4 0.144 53.568 0.192 ;
     RECT  53.592 0.144 53.76 0.192 ;
     RECT  53.784 0.144 53.952 0.192 ;
     RECT  2.304 0.192 53.976 0.227 ;
     RECT  2.304 0.227 38.088 0.371 ;
     RECT  39.648 0.227 53.976 0.419 ;
     RECT  24.336 0.371 38.088 0.563 ;
     RECT  39.648 0.419 52.632 0.563 ;
     RECT  24.336 0.563 29.304 0.611 ;
     RECT  30.336 0.563 32.472 0.611 ;
     RECT  53.952 0.419 53.976 0.611 ;
     RECT  31.872 0.611 32.472 0.659 ;
     RECT  40.032 0.563 52.632 0.659 ;
     RECT  33.648 0.563 38.088 0.707 ;
     RECT  36.528 0.707 38.088 0.755 ;
     RECT  2.304 0.371 23.208 0.851 ;
     RECT  42.336 0.659 52.632 0.899 ;
     RECT  2.688 0.851 23.208 1.139 ;
     RECT  26.688 0.611 29.304 1.139 ;
     RECT  32.064 0.659 32.472 1.139 ;
     RECT  36.912 0.755 38.088 1.139 ;
     RECT  49.68 0.899 52.632 1.139 ;
     RECT  32.448 1.139 32.472 1.187 ;
     RECT  33.648 0.707 35.016 1.187 ;
     RECT  40.032 0.659 41.016 1.187 ;
     RECT  50.064 1.139 52.2 1.427 ;
     RECT  36.912 1.139 37.32 1.715 ;
     RECT  50.064 1.427 52.008 1.763 ;
     RECT  2.688 1.139 15.288 2.053 ;
     RECT  16.32 1.139 23.208 2.053 ;
     RECT  24.384 0.611 24.936 2.053 ;
     RECT  2.304 2.053 15.288 2.137 ;
     RECT  16.32 2.053 24.936 2.137 ;
     RECT  27.12 1.139 29.304 2.137 ;
     RECT  30.336 0.611 30.744 2.137 ;
     RECT  37.104 1.715 37.32 2.137 ;
     RECT  32.1 2.137 32.22 2.151 ;
     RECT  33.648 1.187 34.92 2.151 ;
     RECT  37.104 2.137 37.62 2.151 ;
     RECT  40.08 1.187 40.44 2.151 ;
     RECT  42.336 0.899 48.552 2.151 ;
     RECT  53.7 2.137 53.82 2.151 ;
     RECT  37.104 2.151 37.812 2.243 ;
     RECT  0.192 2.101 0.456 2.339 ;
     RECT  40.08 2.151 40.512 2.867 ;
     RECT  0.288 2.339 0.456 3.301 ;
     RECT  2.304 2.137 24.936 3.443 ;
     RECT  0.288 3.301 0.552 3.877 ;
     RECT  26.7 2.137 30.744 3.971 ;
     RECT  33.648 2.151 35.112 3.971 ;
     RECT  50.64 1.763 52.008 3.971 ;
     RECT  28.032 3.971 30.744 4.019 ;
     RECT  0.192 3.877 0.552 4.115 ;
     RECT  2.304 3.443 14.328 4.405 ;
     RECT  15.9 3.443 24.936 4.405 ;
     RECT  28.032 4.019 29.712 5.171 ;
     RECT  0.192 4.115 0.504 5.317 ;
     RECT  0.192 5.317 0.552 5.605 ;
     RECT  2.304 4.405 24.936 5.747 ;
     RECT  20.496 5.747 24.936 6.275 ;
     RECT  34.416 3.971 35.112 6.275 ;
     RECT  21.072 6.275 24.936 6.323 ;
     RECT  22.608 6.323 24.936 6.371 ;
     RECT  33.744 6.613 33.768 6.803 ;
     RECT  22.992 6.371 24.936 6.851 ;
     RECT  23.184 6.851 24.936 7.427 ;
     RECT  2.304 5.747 19.464 7.475 ;
     RECT  0.192 5.605 0.888 7.909 ;
     RECT  15.264 7.475 19.464 8.003 ;
     RECT  17.952 8.003 19.464 8.579 ;
     RECT  18.336 8.579 19.464 8.627 ;
     RECT  18.48 8.627 19.464 8.675 ;
     RECT  42.336 2.151 48.612 8.819 ;
     RECT  0.192 7.909 0.984 9.203 ;
     RECT  0.192 9.203 0.888 10.067 ;
     RECT  21.072 6.323 21.612 10.307 ;
     RECT  2.304 7.475 13.752 10.931 ;
     RECT  12.432 10.931 13.752 12.035 ;
     RECT  24 7.427 24.936 12.035 ;
     RECT  28.416 5.171 29.712 12.035 ;
     RECT  42.9 8.819 48.612 12.275 ;
     RECT  2.304 10.931 11.448 14.195 ;
     RECT  51 3.971 52.008 14.531 ;
     RECT  30.72 4.019 30.744 14.867 ;
     RECT  28.992 12.035 29.712 15.443 ;
     RECT  2.304 14.195 10.812 15.973 ;
     RECT  0.192 10.067 0.84 16.595 ;
     RECT  2.304 15.973 11.112 17.413 ;
     RECT  0.192 16.595 0.552 18.373 ;
     RECT  0.192 18.373 0.6 19.667 ;
     RECT  2.304 17.413 11.448 20.485 ;
     RECT  12.48 12.035 13.752 20.485 ;
     RECT  0.192 19.667 0.552 20.725 ;
     RECT  0.192 20.725 0.648 21.587 ;
     RECT  2.304 20.485 13.752 22.547 ;
     RECT  0.192 21.587 0.552 22.691 ;
     RECT  11.952 22.547 13.752 22.835 ;
     RECT  0.288 22.691 0.552 23.651 ;
     RECT  42.9 12.275 47.016 23.651 ;
     RECT  42.9 23.651 44.28 23.699 ;
     RECT  0.288 23.651 0.504 23.893 ;
     RECT  45.6 23.651 47.016 23.939 ;
     RECT  46.992 23.939 47.016 24.227 ;
     RECT  2.304 22.547 10.812 24.613 ;
     RECT  42.9 23.699 44.088 24.707 ;
     RECT  2.208 24.613 10.812 25.043 ;
     RECT  2.304 25.043 10.812 25.139 ;
     RECT  21.3 10.307 21.612 25.141 ;
     RECT  2.304 25.139 9.384 25.235 ;
     RECT  21.3 25.141 21.72 25.283 ;
     RECT  0.24 23.893 0.504 25.765 ;
     RECT  0.192 25.765 0.504 26.147 ;
     RECT  2.4 25.235 9.384 26.243 ;
     RECT  0.24 26.147 0.504 26.581 ;
     RECT  0.24 26.581 0.552 26.819 ;
     RECT  0.24 26.819 0.504 27.253 ;
     RECT  2.4 26.243 9.288 27.253 ;
     RECT  0.192 27.253 0.504 27.395 ;
     RECT  10.368 25.139 10.812 27.395 ;
     RECT  0.192 27.395 0.456 28.115 ;
     RECT  0.288 28.115 0.456 28.355 ;
     RECT  2.4 27.253 9.384 28.403 ;
     RECT  2.4 28.403 2.712 28.741 ;
     RECT  0.336 28.355 0.456 29.173 ;
     RECT  0.336 29.173 0.504 29.507 ;
     RECT  2.304 28.741 2.712 29.509 ;
     RECT  3.696 28.403 9.384 29.509 ;
     RECT  0.384 29.507 0.504 29.843 ;
     RECT  0.384 29.843 0.456 30.803 ;
     RECT  2.304 29.509 9.384 31.379 ;
     RECT  2.304 31.379 9.096 32.003 ;
     RECT  0.384 30.803 0.408 32.869 ;
     RECT  0.288 32.869 0.408 33.013 ;
     RECT  2.4 32.003 9.096 33.925 ;
     RECT  10.5 27.395 10.812 33.925 ;
     RECT  0.288 33.013 0.552 34.403 ;
     RECT  0.336 34.403 0.552 34.835 ;
     RECT  0.336 34.835 0.36 35.219 ;
     RECT  0.288 35.797 0.312 36.899 ;
     RECT  2.4 33.925 10.812 38.291 ;
     RECT  0.288 38.245 0.312 38.435 ;
     RECT  3.936 38.291 10.812 38.819 ;
     RECT  3.936 38.819 9.096 39.395 ;
     RECT  4.464 39.395 9.096 40.115 ;
     RECT  2.4 38.291 2.712 40.645 ;
     RECT  2.4 40.645 2.808 41.171 ;
     RECT  4.896 40.115 9.096 41.507 ;
     RECT  5.1 41.507 9.096 42.661 ;
     RECT  0.288 42.901 0.312 43.091 ;
     RECT  2.4 41.171 2.712 43.093 ;
     RECT  2.304 43.093 2.712 43.283 ;
     RECT  5.1 42.661 9.336 44.387 ;
     RECT  5.1 44.387 6.12 44.389 ;
     RECT  4.56 44.389 6.12 45.059 ;
     RECT  0.288 45.781 0.312 46.067 ;
     RECT  7.104 44.387 9.336 46.309 ;
     RECT  12.48 22.835 13.752 46.787 ;
     RECT  0.336 47.653 0.36 47.701 ;
     RECT  4.896 45.059 6.12 47.701 ;
     RECT  7.104 46.309 9.528 47.701 ;
     RECT  0.192 47.701 0.36 47.891 ;
     RECT  4.896 47.701 9.528 48.227 ;
     RECT  15.264 8.003 16.212 48.515 ;
     RECT  18.6 8.675 19.464 48.515 ;
     RECT  9.312 48.227 9.528 48.997 ;
     RECT  10.5 38.819 10.812 48.997 ;
     RECT  4.896 48.227 8.112 49.331 ;
     RECT  0.288 49.285 0.312 49.571 ;
     RECT  4.896 49.331 5.544 49.763 ;
     RECT  4.896 49.763 5.412 50.101 ;
     RECT  9.312 48.997 10.812 50.339 ;
     RECT  4.752 50.101 5.412 50.579 ;
     RECT  7.104 49.331 8.112 51.205 ;
     RECT  9.312 50.339 9.528 51.347 ;
     RECT  5.1 50.579 5.412 51.637 ;
     RECT  7.104 51.205 8.232 51.733 ;
     RECT  0.192 50.533 0.216 51.779 ;
     RECT  9.504 51.347 9.528 51.829 ;
     RECT  10.5 50.339 10.812 51.829 ;
     RECT  6.624 51.733 8.232 52.165 ;
     RECT  6.624 52.165 8.328 52.691 ;
     RECT  4.992 51.637 5.412 52.739 ;
     RECT  5.1 52.739 5.412 52.885 ;
     RECT  6.624 52.691 8.232 52.885 ;
     RECT  9.504 51.829 10.812 53.123 ;
     RECT  5.1 52.885 8.232 53.315 ;
     RECT  9.936 53.123 10.812 53.315 ;
     RECT  5.1 53.315 8.112 53.603 ;
     RECT  2.4 43.283 2.712 54.009 ;
     RECT  5.1 53.603 5.412 54.009 ;
     RECT  7.104 53.603 8.112 54.009 ;
     RECT  10.5 53.315 10.812 54.009 ;
     RECT  13.2 46.787 13.512 54.009 ;
     RECT  15.9 48.515 16.212 54.009 ;
     RECT  18.6 48.515 18.912 54.009 ;
     RECT  21.3 25.283 21.612 54.009 ;
     RECT  24 12.035 24.312 54.009 ;
     RECT  26.7 3.971 27.012 54.009 ;
     RECT  29.4 15.443 29.712 54.009 ;
     RECT  32.1 2.151 32.412 54.009 ;
     RECT  34.8 6.275 35.112 54.009 ;
     RECT  37.5 2.243 37.812 54.009 ;
     RECT  40.2 2.867 40.512 54.009 ;
     RECT  42.9 24.707 43.212 54.009 ;
     RECT  45.6 23.939 45.912 54.009 ;
     RECT  48.3 12.275 48.612 54.009 ;
     RECT  51 14.531 51.312 54.009 ;
     RECT  53.7 2.151 54.012 54.009 ;
     RECT  2.4 54.009 2.52 54.023 ;
     RECT  5.1 54.009 5.22 54.023 ;
     RECT  7.104 54.009 7.92 54.023 ;
     RECT  10.5 54.009 10.62 54.023 ;
     RECT  13.2 54.009 13.32 54.023 ;
     RECT  15.9 54.009 16.02 54.023 ;
     RECT  18.6 54.009 18.72 54.023 ;
     RECT  21.3 54.009 21.42 54.023 ;
     RECT  24 54.009 24.12 54.023 ;
     RECT  26.7 54.009 26.82 54.023 ;
     RECT  29.4 54.009 29.52 54.023 ;
     RECT  32.1 54.009 32.22 54.023 ;
     RECT  34.8 54.009 34.92 54.023 ;
     RECT  37.5 54.009 37.62 54.023 ;
     RECT  40.2 54.009 40.32 54.023 ;
     RECT  42.9 54.009 43.02 54.023 ;
     RECT  45.6 54.009 45.72 54.023 ;
     RECT  48.3 54.009 48.42 54.023 ;
     RECT  51 54.009 51.12 54.023 ;
     RECT  53.7 54.009 53.82 54.023 ;
     RECT  7.104 54.023 7.128 56.051 ;
     RECT  23.208 0.371 24.336 0.611 ;
     RECT  52.632 0.419 53.952 0.611 ;
     RECT  29.304 0.563 30.336 2.137 ;
     RECT  32.472 0.563 33.648 1.187 ;
     RECT  23.208 0.611 24.384 2.053 ;
     RECT  30.744 0.611 31.872 0.659 ;
     RECT  52.632 0.611 53.82 1.139 ;
     RECT  30.744 0.659 32.064 1.139 ;
     RECT  41.016 0.659 42.336 1.187 ;
     RECT  35.016 0.707 36.528 0.755 ;
     RECT  35.016 0.755 35.112 1.187 ;
     RECT  2.304 0.851 2.688 2.053 ;
     RECT  48.552 0.899 49.68 1.139 ;
     RECT  15.288 1.139 16.32 2.137 ;
     RECT  26.7 1.139 27.12 2.137 ;
     RECT  30.744 1.139 32.448 1.187 ;
     RECT  37.32 1.139 37.812 2.137 ;
     RECT  48.552 1.139 50.064 1.763 ;
     RECT  52.2 1.139 53.82 1.427 ;
     RECT  30.744 1.187 33.648 2.137 ;
     RECT  34.92 1.187 35.112 2.151 ;
     RECT  40.44 1.187 40.512 2.151 ;
     RECT  53.7 1.427 53.82 2.137 ;
     RECT  48.552 1.763 48.612 2.151 ;
     RECT  30.744 2.137 32.1 14.867 ;
     RECT  32.22 2.137 33.648 2.151 ;
     RECT  37.62 2.137 37.812 2.151 ;
     RECT  32.412 2.151 33.648 3.971 ;
     RECT  14.328 3.443 15.9 4.405 ;
     RECT  27.012 3.971 28.032 5.171 ;
     RECT  29.712 4.019 30.72 14.867 ;
     RECT  0.504 4.115 0.552 5.317 ;
     RECT  27.012 5.171 28.416 12.035 ;
     RECT  0.888 5.605 2.304 7.909 ;
     RECT  19.464 5.747 20.496 6.275 ;
     RECT  34.416 6.275 34.8 6.613 ;
     RECT  21.612 6.323 22.608 6.371 ;
     RECT  21.612 6.371 22.992 6.851 ;
     RECT  32.412 6.613 33.744 6.803 ;
     RECT  33.768 6.613 34.8 6.803 ;
     RECT  13.752 7.475 15.264 46.787 ;
     RECT  0.984 7.909 2.304 9.203 ;
     RECT  0.888 9.203 2.304 10.067 ;
     RECT  0.84 10.067 2.304 16.595 ;
     RECT  11.448 10.931 12.432 12.035 ;
     RECT  11.448 12.035 12.48 14.195 ;
     RECT  47.016 12.275 48.3 24.227 ;
     RECT  11.112 15.973 12.48 17.413 ;
     RECT  11.448 17.413 12.48 20.485 ;
     RECT  0.552 19.667 0.6 20.725 ;
     RECT  10.812 22.547 11.952 22.835 ;
     RECT  0.24 22.691 0.288 23.893 ;
     RECT  44.28 23.651 45.6 23.699 ;
     RECT  44.088 23.699 45.6 24.707 ;
     RECT  45.912 23.939 46.992 24.227 ;
     RECT  9.384 25.139 10.368 26.243 ;
     RECT  9.288 26.243 10.368 27.253 ;
     RECT  9.384 27.253 10.368 27.395 ;
     RECT  9.384 27.395 10.5 31.379 ;
     RECT  2.712 28.403 3.696 29.509 ;
     RECT  9.096 31.379 10.5 33.925 ;
     RECT  0.288 34.403 0.336 35.219 ;
     RECT  0.288 35.219 0.312 35.797 ;
     RECT  0.288 36.899 0.312 38.245 ;
     RECT  2.712 38.291 3.936 39.395 ;
     RECT  9.096 38.819 10.5 42.661 ;
     RECT  2.712 39.395 2.808 40.645 ;
     RECT  9.336 42.661 10.5 46.309 ;
     RECT  6.12 44.387 7.104 47.701 ;
     RECT  9.528 46.309 10.5 48.997 ;
     RECT  0.288 47.891 0.312 49.285 ;
     RECT  8.112 48.227 9.312 51.205 ;
     RECT  9.528 50.339 10.5 51.829 ;
     RECT  4.992 50.579 5.1 51.637 ;
     RECT  8.232 51.205 9.312 51.347 ;
     RECT  8.232 51.347 9.504 52.165 ;
     RECT  5.412 51.733 6.624 52.885 ;
     RECT  8.328 52.165 9.504 52.691 ;
     RECT  8.232 52.691 9.504 53.123 ;
  END
END dsfd_rly_536_WS
END LIBRARY
